VERSION 5.8 ;
BUSBITCHARS "[]" ;
DIVIDERCHAR "/" ;
UNITS
    DATABASE MICRONS 1000 ;
END UNITS

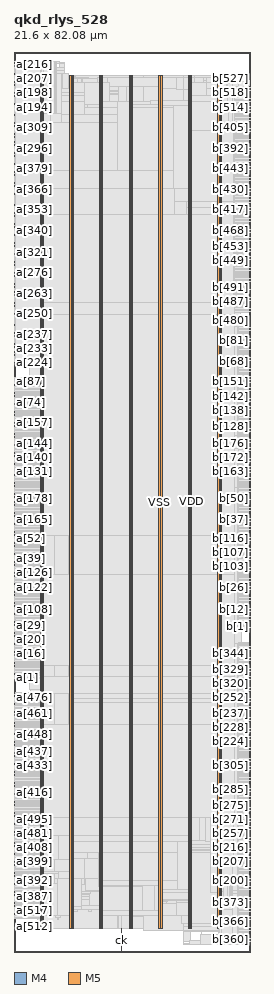
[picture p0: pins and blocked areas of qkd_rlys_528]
MACRO qkd_rlys_528
  FOREIGN qkd_rlys_528 0 0 ;
  CLASS BLOCK ;
  SIZE 21.6 BY 82.08 ;
  PIN a[0]
    DIRECTION INPUT ;
    USE SIGNAL ;
    PORT
      LAYER M4 ;
        RECT  0 24.912 0.084 24.936 ;
    END
  END a[0]
  PIN a[100]
    DIRECTION INPUT ;
    USE SIGNAL ;
    PORT
      LAYER M4 ;
        RECT  0 30.096 0.084 30.12 ;
    END
  END a[100]
  PIN a[101]
    DIRECTION INPUT ;
    USE SIGNAL ;
    PORT
      LAYER M4 ;
        RECT  0 30.24 0.084 30.264 ;
    END
  END a[101]
  PIN a[102]
    DIRECTION INPUT ;
    USE SIGNAL ;
    PORT
      LAYER M4 ;
        RECT  0 30.384 0.084 30.408 ;
    END
  END a[102]
  PIN a[103]
    DIRECTION INPUT ;
    USE SIGNAL ;
    PORT
      LAYER M4 ;
        RECT  0 30.528 0.084 30.552 ;
    END
  END a[103]
  PIN a[104]
    DIRECTION INPUT ;
    USE SIGNAL ;
    PORT
      LAYER M4 ;
        RECT  0 30.672 0.084 30.696 ;
    END
  END a[104]
  PIN a[105]
    DIRECTION INPUT ;
    USE SIGNAL ;
    PORT
      LAYER M4 ;
        RECT  0 30.816 0.084 30.84 ;
    END
  END a[105]
  PIN a[106]
    DIRECTION INPUT ;
    USE SIGNAL ;
    PORT
      LAYER M4 ;
        RECT  0 30.96 0.084 30.984 ;
    END
  END a[106]
  PIN a[107]
    DIRECTION INPUT ;
    USE SIGNAL ;
    PORT
      LAYER M4 ;
        RECT  0 31.104 0.084 31.128 ;
    END
  END a[107]
  PIN a[108]
    DIRECTION INPUT ;
    USE SIGNAL ;
    PORT
      LAYER M4 ;
        RECT  0 31.248 0.084 31.272 ;
    END
  END a[108]
  PIN a[109]
    DIRECTION INPUT ;
    USE SIGNAL ;
    PORT
      LAYER M4 ;
        RECT  0 31.392 0.084 31.416 ;
    END
  END a[109]
  PIN a[10]
    DIRECTION INPUT ;
    USE SIGNAL ;
    PORT
      LAYER M4 ;
        RECT  0 26.352 0.084 26.376 ;
    END
  END a[10]
  PIN a[110]
    DIRECTION INPUT ;
    USE SIGNAL ;
    PORT
      LAYER M4 ;
        RECT  0 31.536 0.084 31.56 ;
    END
  END a[110]
  PIN a[111]
    DIRECTION INPUT ;
    USE SIGNAL ;
    PORT
      LAYER M4 ;
        RECT  0 31.68 0.084 31.704 ;
    END
  END a[111]
  PIN a[112]
    DIRECTION INPUT ;
    USE SIGNAL ;
    PORT
      LAYER M4 ;
        RECT  0 31.824 0.084 31.848 ;
    END
  END a[112]
  PIN a[113]
    DIRECTION INPUT ;
    USE SIGNAL ;
    PORT
      LAYER M4 ;
        RECT  0 31.968 0.084 31.992 ;
    END
  END a[113]
  PIN a[114]
    DIRECTION INPUT ;
    USE SIGNAL ;
    PORT
      LAYER M4 ;
        RECT  0 32.112 0.084 32.136 ;
    END
  END a[114]
  PIN a[115]
    DIRECTION INPUT ;
    USE SIGNAL ;
    PORT
      LAYER M4 ;
        RECT  0 32.256 0.084 32.28 ;
    END
  END a[115]
  PIN a[116]
    DIRECTION INPUT ;
    USE SIGNAL ;
    PORT
      LAYER M4 ;
        RECT  0 32.4 0.084 32.424 ;
    END
  END a[116]
  PIN a[117]
    DIRECTION INPUT ;
    USE SIGNAL ;
    PORT
      LAYER M4 ;
        RECT  0 32.544 0.084 32.568 ;
    END
  END a[117]
  PIN a[118]
    DIRECTION INPUT ;
    USE SIGNAL ;
    PORT
      LAYER M4 ;
        RECT  0 32.688 0.084 32.712 ;
    END
  END a[118]
  PIN a[119]
    DIRECTION INPUT ;
    USE SIGNAL ;
    PORT
      LAYER M4 ;
        RECT  0 32.832 0.084 32.856 ;
    END
  END a[119]
  PIN a[11]
    DIRECTION INPUT ;
    USE SIGNAL ;
    PORT
      LAYER M4 ;
        RECT  0 26.496 0.084 26.52 ;
    END
  END a[11]
  PIN a[120]
    DIRECTION INPUT ;
    USE SIGNAL ;
    PORT
      LAYER M4 ;
        RECT  0 32.976 0.084 33 ;
    END
  END a[120]
  PIN a[121]
    DIRECTION INPUT ;
    USE SIGNAL ;
    PORT
      LAYER M4 ;
        RECT  0 33.12 0.084 33.144 ;
    END
  END a[121]
  PIN a[122]
    DIRECTION INPUT ;
    USE SIGNAL ;
    PORT
      LAYER M4 ;
        RECT  0 33.264 0.084 33.288 ;
    END
  END a[122]
  PIN a[123]
    DIRECTION INPUT ;
    USE SIGNAL ;
    PORT
      LAYER M4 ;
        RECT  0 33.408 0.084 33.432 ;
    END
  END a[123]
  PIN a[124]
    DIRECTION INPUT ;
    USE SIGNAL ;
    PORT
      LAYER M4 ;
        RECT  0 33.552 0.084 33.576 ;
    END
  END a[124]
  PIN a[125]
    DIRECTION INPUT ;
    USE SIGNAL ;
    PORT
      LAYER M4 ;
        RECT  0 33.696 0.084 33.72 ;
    END
  END a[125]
  PIN a[126]
    DIRECTION INPUT ;
    USE SIGNAL ;
    PORT
      LAYER M4 ;
        RECT  0 33.84 0.084 33.864 ;
    END
  END a[126]
  PIN a[127]
    DIRECTION INPUT ;
    USE SIGNAL ;
    PORT
      LAYER M4 ;
        RECT  0 33.984 0.084 34.008 ;
    END
  END a[127]
  PIN a[128]
    DIRECTION INPUT ;
    USE SIGNAL ;
    PORT
      LAYER M4 ;
        RECT  0 43.344 0.084 43.368 ;
    END
  END a[128]
  PIN a[129]
    DIRECTION INPUT ;
    USE SIGNAL ;
    PORT
      LAYER M4 ;
        RECT  0 43.488 0.084 43.512 ;
    END
  END a[129]
  PIN a[12]
    DIRECTION INPUT ;
    USE SIGNAL ;
    PORT
      LAYER M4 ;
        RECT  0 26.64 0.084 26.664 ;
    END
  END a[12]
  PIN a[130]
    DIRECTION INPUT ;
    USE SIGNAL ;
    PORT
      LAYER M4 ;
        RECT  0 43.632 0.084 43.656 ;
    END
  END a[130]
  PIN a[131]
    DIRECTION INPUT ;
    USE SIGNAL ;
    PORT
      LAYER M4 ;
        RECT  0 43.776 0.084 43.8 ;
    END
  END a[131]
  PIN a[132]
    DIRECTION INPUT ;
    USE SIGNAL ;
    PORT
      LAYER M4 ;
        RECT  0 43.92 0.084 43.944 ;
    END
  END a[132]
  PIN a[133]
    DIRECTION INPUT ;
    USE SIGNAL ;
    PORT
      LAYER M4 ;
        RECT  0 44.064 0.084 44.088 ;
    END
  END a[133]
  PIN a[134]
    DIRECTION INPUT ;
    USE SIGNAL ;
    PORT
      LAYER M4 ;
        RECT  0 44.208 0.084 44.232 ;
    END
  END a[134]
  PIN a[135]
    DIRECTION INPUT ;
    USE SIGNAL ;
    PORT
      LAYER M4 ;
        RECT  0 44.352 0.084 44.376 ;
    END
  END a[135]
  PIN a[136]
    DIRECTION INPUT ;
    USE SIGNAL ;
    PORT
      LAYER M4 ;
        RECT  0 44.496 0.084 44.52 ;
    END
  END a[136]
  PIN a[137]
    DIRECTION INPUT ;
    USE SIGNAL ;
    PORT
      LAYER M4 ;
        RECT  0 44.64 0.084 44.664 ;
    END
  END a[137]
  PIN a[138]
    DIRECTION INPUT ;
    USE SIGNAL ;
    PORT
      LAYER M4 ;
        RECT  0 44.784 0.084 44.808 ;
    END
  END a[138]
  PIN a[139]
    DIRECTION INPUT ;
    USE SIGNAL ;
    PORT
      LAYER M4 ;
        RECT  0 44.928 0.084 44.952 ;
    END
  END a[139]
  PIN a[13]
    DIRECTION INPUT ;
    USE SIGNAL ;
    PORT
      LAYER M4 ;
        RECT  0 26.784 0.084 26.808 ;
    END
  END a[13]
  PIN a[140]
    DIRECTION INPUT ;
    USE SIGNAL ;
    PORT
      LAYER M4 ;
        RECT  0 45.072 0.084 45.096 ;
    END
  END a[140]
  PIN a[141]
    DIRECTION INPUT ;
    USE SIGNAL ;
    PORT
      LAYER M4 ;
        RECT  0 45.216 0.084 45.24 ;
    END
  END a[141]
  PIN a[142]
    DIRECTION INPUT ;
    USE SIGNAL ;
    PORT
      LAYER M4 ;
        RECT  0 45.36 0.084 45.384 ;
    END
  END a[142]
  PIN a[143]
    DIRECTION INPUT ;
    USE SIGNAL ;
    PORT
      LAYER M4 ;
        RECT  0 45.504 0.084 45.528 ;
    END
  END a[143]
  PIN a[144]
    DIRECTION INPUT ;
    USE SIGNAL ;
    PORT
      LAYER M4 ;
        RECT  0 45.648 0.084 45.672 ;
    END
  END a[144]
  PIN a[145]
    DIRECTION INPUT ;
    USE SIGNAL ;
    PORT
      LAYER M4 ;
        RECT  0 45.792 0.084 45.816 ;
    END
  END a[145]
  PIN a[146]
    DIRECTION INPUT ;
    USE SIGNAL ;
    PORT
      LAYER M4 ;
        RECT  0 45.936 0.084 45.96 ;
    END
  END a[146]
  PIN a[147]
    DIRECTION INPUT ;
    USE SIGNAL ;
    PORT
      LAYER M4 ;
        RECT  0 46.08 0.084 46.104 ;
    END
  END a[147]
  PIN a[148]
    DIRECTION INPUT ;
    USE SIGNAL ;
    PORT
      LAYER M4 ;
        RECT  0 46.224 0.084 46.248 ;
    END
  END a[148]
  PIN a[149]
    DIRECTION INPUT ;
    USE SIGNAL ;
    PORT
      LAYER M4 ;
        RECT  0 46.368 0.084 46.392 ;
    END
  END a[149]
  PIN a[14]
    DIRECTION INPUT ;
    USE SIGNAL ;
    PORT
      LAYER M4 ;
        RECT  0 26.928 0.084 26.952 ;
    END
  END a[14]
  PIN a[150]
    DIRECTION INPUT ;
    USE SIGNAL ;
    PORT
      LAYER M4 ;
        RECT  0 46.512 0.084 46.536 ;
    END
  END a[150]
  PIN a[151]
    DIRECTION INPUT ;
    USE SIGNAL ;
    PORT
      LAYER M4 ;
        RECT  0 46.656 0.084 46.68 ;
    END
  END a[151]
  PIN a[152]
    DIRECTION INPUT ;
    USE SIGNAL ;
    PORT
      LAYER M4 ;
        RECT  0 46.8 0.084 46.824 ;
    END
  END a[152]
  PIN a[153]
    DIRECTION INPUT ;
    USE SIGNAL ;
    PORT
      LAYER M4 ;
        RECT  0 46.944 0.084 46.968 ;
    END
  END a[153]
  PIN a[154]
    DIRECTION INPUT ;
    USE SIGNAL ;
    PORT
      LAYER M4 ;
        RECT  0 47.088 0.084 47.112 ;
    END
  END a[154]
  PIN a[155]
    DIRECTION INPUT ;
    USE SIGNAL ;
    PORT
      LAYER M4 ;
        RECT  0 47.232 0.084 47.256 ;
    END
  END a[155]
  PIN a[156]
    DIRECTION INPUT ;
    USE SIGNAL ;
    PORT
      LAYER M4 ;
        RECT  0 47.376 0.084 47.4 ;
    END
  END a[156]
  PIN a[157]
    DIRECTION INPUT ;
    USE SIGNAL ;
    PORT
      LAYER M4 ;
        RECT  0 47.52 0.084 47.544 ;
    END
  END a[157]
  PIN a[158]
    DIRECTION INPUT ;
    USE SIGNAL ;
    PORT
      LAYER M4 ;
        RECT  0 47.664 0.084 47.688 ;
    END
  END a[158]
  PIN a[159]
    DIRECTION INPUT ;
    USE SIGNAL ;
    PORT
      LAYER M4 ;
        RECT  0 47.808 0.084 47.832 ;
    END
  END a[159]
  PIN a[15]
    DIRECTION INPUT ;
    USE SIGNAL ;
    PORT
      LAYER M4 ;
        RECT  0 27.072 0.084 27.096 ;
    END
  END a[15]
  PIN a[160]
    DIRECTION INPUT ;
    USE SIGNAL ;
    PORT
      LAYER M4 ;
        RECT  0 38.736 0.084 38.76 ;
    END
  END a[160]
  PIN a[161]
    DIRECTION INPUT ;
    USE SIGNAL ;
    PORT
      LAYER M4 ;
        RECT  0 38.88 0.084 38.904 ;
    END
  END a[161]
  PIN a[162]
    DIRECTION INPUT ;
    USE SIGNAL ;
    PORT
      LAYER M4 ;
        RECT  0 39.024 0.084 39.048 ;
    END
  END a[162]
  PIN a[163]
    DIRECTION INPUT ;
    USE SIGNAL ;
    PORT
      LAYER M4 ;
        RECT  0 39.168 0.084 39.192 ;
    END
  END a[163]
  PIN a[164]
    DIRECTION INPUT ;
    USE SIGNAL ;
    PORT
      LAYER M4 ;
        RECT  0 39.312 0.084 39.336 ;
    END
  END a[164]
  PIN a[165]
    DIRECTION INPUT ;
    USE SIGNAL ;
    PORT
      LAYER M4 ;
        RECT  0 39.456 0.084 39.48 ;
    END
  END a[165]
  PIN a[166]
    DIRECTION INPUT ;
    USE SIGNAL ;
    PORT
      LAYER M4 ;
        RECT  0 39.6 0.084 39.624 ;
    END
  END a[166]
  PIN a[167]
    DIRECTION INPUT ;
    USE SIGNAL ;
    PORT
      LAYER M4 ;
        RECT  0 39.744 0.084 39.768 ;
    END
  END a[167]
  PIN a[168]
    DIRECTION INPUT ;
    USE SIGNAL ;
    PORT
      LAYER M4 ;
        RECT  0 39.888 0.084 39.912 ;
    END
  END a[168]
  PIN a[169]
    DIRECTION INPUT ;
    USE SIGNAL ;
    PORT
      LAYER M4 ;
        RECT  0 40.032 0.084 40.056 ;
    END
  END a[169]
  PIN a[16]
    DIRECTION INPUT ;
    USE SIGNAL ;
    PORT
      LAYER M4 ;
        RECT  0 27.216 0.084 27.24 ;
    END
  END a[16]
  PIN a[170]
    DIRECTION INPUT ;
    USE SIGNAL ;
    PORT
      LAYER M4 ;
        RECT  0 40.176 0.084 40.2 ;
    END
  END a[170]
  PIN a[171]
    DIRECTION INPUT ;
    USE SIGNAL ;
    PORT
      LAYER M4 ;
        RECT  0 40.32 0.084 40.344 ;
    END
  END a[171]
  PIN a[172]
    DIRECTION INPUT ;
    USE SIGNAL ;
    PORT
      LAYER M4 ;
        RECT  0 40.464 0.084 40.488 ;
    END
  END a[172]
  PIN a[173]
    DIRECTION INPUT ;
    USE SIGNAL ;
    PORT
      LAYER M4 ;
        RECT  0 40.608 0.084 40.632 ;
    END
  END a[173]
  PIN a[174]
    DIRECTION INPUT ;
    USE SIGNAL ;
    PORT
      LAYER M4 ;
        RECT  0 40.752 0.084 40.776 ;
    END
  END a[174]
  PIN a[175]
    DIRECTION INPUT ;
    USE SIGNAL ;
    PORT
      LAYER M4 ;
        RECT  0 40.896 0.084 40.92 ;
    END
  END a[175]
  PIN a[176]
    DIRECTION INPUT ;
    USE SIGNAL ;
    PORT
      LAYER M4 ;
        RECT  0 41.04 0.084 41.064 ;
    END
  END a[176]
  PIN a[177]
    DIRECTION INPUT ;
    USE SIGNAL ;
    PORT
      LAYER M4 ;
        RECT  0 41.184 0.084 41.208 ;
    END
  END a[177]
  PIN a[178]
    DIRECTION INPUT ;
    USE SIGNAL ;
    PORT
      LAYER M4 ;
        RECT  0 41.328 0.084 41.352 ;
    END
  END a[178]
  PIN a[179]
    DIRECTION INPUT ;
    USE SIGNAL ;
    PORT
      LAYER M4 ;
        RECT  0 41.472 0.084 41.496 ;
    END
  END a[179]
  PIN a[17]
    DIRECTION INPUT ;
    USE SIGNAL ;
    PORT
      LAYER M4 ;
        RECT  0 27.36 0.084 27.384 ;
    END
  END a[17]
  PIN a[180]
    DIRECTION INPUT ;
    USE SIGNAL ;
    PORT
      LAYER M4 ;
        RECT  0 41.616 0.084 41.64 ;
    END
  END a[180]
  PIN a[181]
    DIRECTION INPUT ;
    USE SIGNAL ;
    PORT
      LAYER M4 ;
        RECT  0 41.76 0.084 41.784 ;
    END
  END a[181]
  PIN a[182]
    DIRECTION INPUT ;
    USE SIGNAL ;
    PORT
      LAYER M4 ;
        RECT  0 41.904 0.084 41.928 ;
    END
  END a[182]
  PIN a[183]
    DIRECTION INPUT ;
    USE SIGNAL ;
    PORT
      LAYER M4 ;
        RECT  0 42.048 0.084 42.072 ;
    END
  END a[183]
  PIN a[184]
    DIRECTION INPUT ;
    USE SIGNAL ;
    PORT
      LAYER M4 ;
        RECT  0 42.192 0.084 42.216 ;
    END
  END a[184]
  PIN a[185]
    DIRECTION INPUT ;
    USE SIGNAL ;
    PORT
      LAYER M4 ;
        RECT  0 42.336 0.084 42.36 ;
    END
  END a[185]
  PIN a[186]
    DIRECTION INPUT ;
    USE SIGNAL ;
    PORT
      LAYER M4 ;
        RECT  0 42.48 0.084 42.504 ;
    END
  END a[186]
  PIN a[187]
    DIRECTION INPUT ;
    USE SIGNAL ;
    PORT
      LAYER M4 ;
        RECT  0 42.624 0.084 42.648 ;
    END
  END a[187]
  PIN a[188]
    DIRECTION INPUT ;
    USE SIGNAL ;
    PORT
      LAYER M4 ;
        RECT  0 42.768 0.084 42.792 ;
    END
  END a[188]
  PIN a[189]
    DIRECTION INPUT ;
    USE SIGNAL ;
    PORT
      LAYER M4 ;
        RECT  0 42.912 0.084 42.936 ;
    END
  END a[189]
  PIN a[18]
    DIRECTION INPUT ;
    USE SIGNAL ;
    PORT
      LAYER M4 ;
        RECT  0 27.504 0.084 27.528 ;
    END
  END a[18]
  PIN a[190]
    DIRECTION INPUT ;
    USE SIGNAL ;
    PORT
      LAYER M4 ;
        RECT  0 43.056 0.084 43.08 ;
    END
  END a[190]
  PIN a[191]
    DIRECTION INPUT ;
    USE SIGNAL ;
    PORT
      LAYER M4 ;
        RECT  0 43.2 0.084 43.224 ;
    END
  END a[191]
  PIN a[192]
    DIRECTION INPUT ;
    USE SIGNAL ;
    PORT
      LAYER M4 ;
        RECT  0 76.752 0.084 76.776 ;
    END
  END a[192]
  PIN a[193]
    DIRECTION INPUT ;
    USE SIGNAL ;
    PORT
      LAYER M4 ;
        RECT  0 76.896 0.084 76.92 ;
    END
  END a[193]
  PIN a[194]
    DIRECTION INPUT ;
    USE SIGNAL ;
    PORT
      LAYER M4 ;
        RECT  0 77.04 0.084 77.064 ;
    END
  END a[194]
  PIN a[195]
    DIRECTION INPUT ;
    USE SIGNAL ;
    PORT
      LAYER M4 ;
        RECT  0 77.184 0.084 77.208 ;
    END
  END a[195]
  PIN a[196]
    DIRECTION INPUT ;
    USE SIGNAL ;
    PORT
      LAYER M4 ;
        RECT  0 77.328 0.084 77.352 ;
    END
  END a[196]
  PIN a[197]
    DIRECTION INPUT ;
    USE SIGNAL ;
    PORT
      LAYER M4 ;
        RECT  0 77.472 0.084 77.496 ;
    END
  END a[197]
  PIN a[198]
    DIRECTION INPUT ;
    USE SIGNAL ;
    PORT
      LAYER M4 ;
        RECT  0 77.616 0.084 77.64 ;
    END
  END a[198]
  PIN a[199]
    DIRECTION INPUT ;
    USE SIGNAL ;
    PORT
      LAYER M4 ;
        RECT  0 77.76 0.084 77.784 ;
    END
  END a[199]
  PIN a[19]
    DIRECTION INPUT ;
    USE SIGNAL ;
    PORT
      LAYER M4 ;
        RECT  0 27.648 0.084 27.672 ;
    END
  END a[19]
  PIN a[1]
    DIRECTION INPUT ;
    USE SIGNAL ;
    PORT
      LAYER M4 ;
        RECT  0 25.056 0.084 25.08 ;
    END
  END a[1]
  PIN a[200]
    DIRECTION INPUT ;
    USE SIGNAL ;
    PORT
      LAYER M4 ;
        RECT  0 77.904 0.084 77.928 ;
    END
  END a[200]
  PIN a[201]
    DIRECTION INPUT ;
    USE SIGNAL ;
    PORT
      LAYER M4 ;
        RECT  0 78.048 0.084 78.072 ;
    END
  END a[201]
  PIN a[202]
    DIRECTION INPUT ;
    USE SIGNAL ;
    PORT
      LAYER M4 ;
        RECT  0 78.192 0.084 78.216 ;
    END
  END a[202]
  PIN a[203]
    DIRECTION INPUT ;
    USE SIGNAL ;
    PORT
      LAYER M4 ;
        RECT  0 78.336 0.084 78.36 ;
    END
  END a[203]
  PIN a[204]
    DIRECTION INPUT ;
    USE SIGNAL ;
    PORT
      LAYER M4 ;
        RECT  0 78.48 0.084 78.504 ;
    END
  END a[204]
  PIN a[205]
    DIRECTION INPUT ;
    USE SIGNAL ;
    PORT
      LAYER M4 ;
        RECT  0 78.624 0.084 78.648 ;
    END
  END a[205]
  PIN a[206]
    DIRECTION INPUT ;
    USE SIGNAL ;
    PORT
      LAYER M4 ;
        RECT  0 78.768 0.084 78.792 ;
    END
  END a[206]
  PIN a[207]
    DIRECTION INPUT ;
    USE SIGNAL ;
    PORT
      LAYER M4 ;
        RECT  0 78.912 0.084 78.936 ;
    END
  END a[207]
  PIN a[208]
    DIRECTION INPUT ;
    USE SIGNAL ;
    PORT
      LAYER M4 ;
        RECT  0 79.056 0.084 79.08 ;
    END
  END a[208]
  PIN a[209]
    DIRECTION INPUT ;
    USE SIGNAL ;
    PORT
      LAYER M4 ;
        RECT  0 79.2 0.084 79.224 ;
    END
  END a[209]
  PIN a[20]
    DIRECTION INPUT ;
    USE SIGNAL ;
    PORT
      LAYER M4 ;
        RECT  0 27.792 0.084 27.816 ;
    END
  END a[20]
  PIN a[210]
    DIRECTION INPUT ;
    USE SIGNAL ;
    PORT
      LAYER M4 ;
        RECT  0 79.344 0.084 79.368 ;
    END
  END a[210]
  PIN a[211]
    DIRECTION INPUT ;
    USE SIGNAL ;
    PORT
      LAYER M4 ;
        RECT  0 79.488 0.084 79.512 ;
    END
  END a[211]
  PIN a[212]
    DIRECTION INPUT ;
    USE SIGNAL ;
    PORT
      LAYER M4 ;
        RECT  0 79.632 0.084 79.656 ;
    END
  END a[212]
  PIN a[213]
    DIRECTION INPUT ;
    USE SIGNAL ;
    PORT
      LAYER M4 ;
        RECT  0 79.776 0.084 79.8 ;
    END
  END a[213]
  PIN a[214]
    DIRECTION INPUT ;
    USE SIGNAL ;
    PORT
      LAYER M4 ;
        RECT  0 79.92 0.084 79.944 ;
    END
  END a[214]
  PIN a[215]
    DIRECTION INPUT ;
    USE SIGNAL ;
    PORT
      LAYER M4 ;
        RECT  0 80.064 0.084 80.088 ;
    END
  END a[215]
  PIN a[216]
    DIRECTION INPUT ;
    USE SIGNAL ;
    PORT
      LAYER M4 ;
        RECT  0 80.208 0.084 80.232 ;
    END
  END a[216]
  PIN a[217]
    DIRECTION INPUT ;
    USE SIGNAL ;
    PORT
      LAYER M4 ;
        RECT  0 80.352 0.084 80.376 ;
    END
  END a[217]
  PIN a[218]
    DIRECTION INPUT ;
    USE SIGNAL ;
    PORT
      LAYER M4 ;
        RECT  0 80.496 0.084 80.52 ;
    END
  END a[218]
  PIN a[219]
    DIRECTION INPUT ;
    USE SIGNAL ;
    PORT
      LAYER M4 ;
        RECT  0 80.64 0.084 80.664 ;
    END
  END a[219]
  PIN a[21]
    DIRECTION INPUT ;
    USE SIGNAL ;
    PORT
      LAYER M4 ;
        RECT  0 27.936 0.084 27.96 ;
    END
  END a[21]
  PIN a[220]
    DIRECTION INPUT ;
    USE SIGNAL ;
    PORT
      LAYER M4 ;
        RECT  0 80.784 0.084 80.808 ;
    END
  END a[220]
  PIN a[221]
    DIRECTION INPUT ;
    USE SIGNAL ;
    PORT
      LAYER M4 ;
        RECT  0 80.928 0.084 80.952 ;
    END
  END a[221]
  PIN a[222]
    DIRECTION INPUT ;
    USE SIGNAL ;
    PORT
      LAYER M4 ;
        RECT  0 81.072 0.084 81.096 ;
    END
  END a[222]
  PIN a[223]
    DIRECTION INPUT ;
    USE SIGNAL ;
    PORT
      LAYER M4 ;
        RECT  0 81.216 0.084 81.24 ;
    END
  END a[223]
  PIN a[224]
    DIRECTION INPUT ;
    USE SIGNAL ;
    PORT
      LAYER M4 ;
        RECT  0 53.712 0.084 53.736 ;
    END
  END a[224]
  PIN a[225]
    DIRECTION INPUT ;
    USE SIGNAL ;
    PORT
      LAYER M4 ;
        RECT  0 53.856 0.084 53.88 ;
    END
  END a[225]
  PIN a[226]
    DIRECTION INPUT ;
    USE SIGNAL ;
    PORT
      LAYER M4 ;
        RECT  0 54 0.084 54.024 ;
    END
  END a[226]
  PIN a[227]
    DIRECTION INPUT ;
    USE SIGNAL ;
    PORT
      LAYER M4 ;
        RECT  0 54.144 0.084 54.168 ;
    END
  END a[227]
  PIN a[228]
    DIRECTION INPUT ;
    USE SIGNAL ;
    PORT
      LAYER M4 ;
        RECT  0 54.288 0.084 54.312 ;
    END
  END a[228]
  PIN a[229]
    DIRECTION INPUT ;
    USE SIGNAL ;
    PORT
      LAYER M4 ;
        RECT  0 54.432 0.084 54.456 ;
    END
  END a[229]
  PIN a[22]
    DIRECTION INPUT ;
    USE SIGNAL ;
    PORT
      LAYER M4 ;
        RECT  0 28.08 0.084 28.104 ;
    END
  END a[22]
  PIN a[230]
    DIRECTION INPUT ;
    USE SIGNAL ;
    PORT
      LAYER M4 ;
        RECT  0 54.576 0.084 54.6 ;
    END
  END a[230]
  PIN a[231]
    DIRECTION INPUT ;
    USE SIGNAL ;
    PORT
      LAYER M4 ;
        RECT  0 54.72 0.084 54.744 ;
    END
  END a[231]
  PIN a[232]
    DIRECTION INPUT ;
    USE SIGNAL ;
    PORT
      LAYER M4 ;
        RECT  0 54.864 0.084 54.888 ;
    END
  END a[232]
  PIN a[233]
    DIRECTION INPUT ;
    USE SIGNAL ;
    PORT
      LAYER M4 ;
        RECT  0 55.008 0.084 55.032 ;
    END
  END a[233]
  PIN a[234]
    DIRECTION INPUT ;
    USE SIGNAL ;
    PORT
      LAYER M4 ;
        RECT  0 55.152 0.084 55.176 ;
    END
  END a[234]
  PIN a[235]
    DIRECTION INPUT ;
    USE SIGNAL ;
    PORT
      LAYER M4 ;
        RECT  0 55.296 0.084 55.32 ;
    END
  END a[235]
  PIN a[236]
    DIRECTION INPUT ;
    USE SIGNAL ;
    PORT
      LAYER M4 ;
        RECT  0 55.44 0.084 55.464 ;
    END
  END a[236]
  PIN a[237]
    DIRECTION INPUT ;
    USE SIGNAL ;
    PORT
      LAYER M4 ;
        RECT  0 55.584 0.084 55.608 ;
    END
  END a[237]
  PIN a[238]
    DIRECTION INPUT ;
    USE SIGNAL ;
    PORT
      LAYER M4 ;
        RECT  0 55.728 0.084 55.752 ;
    END
  END a[238]
  PIN a[239]
    DIRECTION INPUT ;
    USE SIGNAL ;
    PORT
      LAYER M4 ;
        RECT  0 55.872 0.084 55.896 ;
    END
  END a[239]
  PIN a[23]
    DIRECTION INPUT ;
    USE SIGNAL ;
    PORT
      LAYER M4 ;
        RECT  0 28.224 0.084 28.248 ;
    END
  END a[23]
  PIN a[240]
    DIRECTION INPUT ;
    USE SIGNAL ;
    PORT
      LAYER M4 ;
        RECT  0 56.016 0.084 56.04 ;
    END
  END a[240]
  PIN a[241]
    DIRECTION INPUT ;
    USE SIGNAL ;
    PORT
      LAYER M4 ;
        RECT  0 56.16 0.084 56.184 ;
    END
  END a[241]
  PIN a[242]
    DIRECTION INPUT ;
    USE SIGNAL ;
    PORT
      LAYER M4 ;
        RECT  0 56.304 0.084 56.328 ;
    END
  END a[242]
  PIN a[243]
    DIRECTION INPUT ;
    USE SIGNAL ;
    PORT
      LAYER M4 ;
        RECT  0 56.448 0.084 56.472 ;
    END
  END a[243]
  PIN a[244]
    DIRECTION INPUT ;
    USE SIGNAL ;
    PORT
      LAYER M4 ;
        RECT  0 56.592 0.084 56.616 ;
    END
  END a[244]
  PIN a[245]
    DIRECTION INPUT ;
    USE SIGNAL ;
    PORT
      LAYER M4 ;
        RECT  0 56.736 0.084 56.76 ;
    END
  END a[245]
  PIN a[246]
    DIRECTION INPUT ;
    USE SIGNAL ;
    PORT
      LAYER M4 ;
        RECT  0 56.88 0.084 56.904 ;
    END
  END a[246]
  PIN a[247]
    DIRECTION INPUT ;
    USE SIGNAL ;
    PORT
      LAYER M4 ;
        RECT  0 57.024 0.084 57.048 ;
    END
  END a[247]
  PIN a[248]
    DIRECTION INPUT ;
    USE SIGNAL ;
    PORT
      LAYER M4 ;
        RECT  0 57.168 0.084 57.192 ;
    END
  END a[248]
  PIN a[249]
    DIRECTION INPUT ;
    USE SIGNAL ;
    PORT
      LAYER M4 ;
        RECT  0 57.312 0.084 57.336 ;
    END
  END a[249]
  PIN a[24]
    DIRECTION INPUT ;
    USE SIGNAL ;
    PORT
      LAYER M4 ;
        RECT  0 28.368 0.084 28.392 ;
    END
  END a[24]
  PIN a[250]
    DIRECTION INPUT ;
    USE SIGNAL ;
    PORT
      LAYER M4 ;
        RECT  0 57.456 0.084 57.48 ;
    END
  END a[250]
  PIN a[251]
    DIRECTION INPUT ;
    USE SIGNAL ;
    PORT
      LAYER M4 ;
        RECT  0 57.6 0.084 57.624 ;
    END
  END a[251]
  PIN a[252]
    DIRECTION INPUT ;
    USE SIGNAL ;
    PORT
      LAYER M4 ;
        RECT  0 57.744 0.084 57.768 ;
    END
  END a[252]
  PIN a[253]
    DIRECTION INPUT ;
    USE SIGNAL ;
    PORT
      LAYER M4 ;
        RECT  0 57.888 0.084 57.912 ;
    END
  END a[253]
  PIN a[254]
    DIRECTION INPUT ;
    USE SIGNAL ;
    PORT
      LAYER M4 ;
        RECT  0 58.032 0.084 58.056 ;
    END
  END a[254]
  PIN a[255]
    DIRECTION INPUT ;
    USE SIGNAL ;
    PORT
      LAYER M4 ;
        RECT  0 58.176 0.084 58.2 ;
    END
  END a[255]
  PIN a[256]
    DIRECTION INPUT ;
    USE SIGNAL ;
    PORT
      LAYER M4 ;
        RECT  0 58.32 0.084 58.344 ;
    END
  END a[256]
  PIN a[257]
    DIRECTION INPUT ;
    USE SIGNAL ;
    PORT
      LAYER M4 ;
        RECT  0 58.464 0.084 58.488 ;
    END
  END a[257]
  PIN a[258]
    DIRECTION INPUT ;
    USE SIGNAL ;
    PORT
      LAYER M4 ;
        RECT  0 58.608 0.084 58.632 ;
    END
  END a[258]
  PIN a[259]
    DIRECTION INPUT ;
    USE SIGNAL ;
    PORT
      LAYER M4 ;
        RECT  0 58.752 0.084 58.776 ;
    END
  END a[259]
  PIN a[25]
    DIRECTION INPUT ;
    USE SIGNAL ;
    PORT
      LAYER M4 ;
        RECT  0 28.512 0.084 28.536 ;
    END
  END a[25]
  PIN a[260]
    DIRECTION INPUT ;
    USE SIGNAL ;
    PORT
      LAYER M4 ;
        RECT  0 58.896 0.084 58.92 ;
    END
  END a[260]
  PIN a[261]
    DIRECTION INPUT ;
    USE SIGNAL ;
    PORT
      LAYER M4 ;
        RECT  0 59.04 0.084 59.064 ;
    END
  END a[261]
  PIN a[262]
    DIRECTION INPUT ;
    USE SIGNAL ;
    PORT
      LAYER M4 ;
        RECT  0 59.184 0.084 59.208 ;
    END
  END a[262]
  PIN a[263]
    DIRECTION INPUT ;
    USE SIGNAL ;
    PORT
      LAYER M4 ;
        RECT  0 59.328 0.084 59.352 ;
    END
  END a[263]
  PIN a[264]
    DIRECTION INPUT ;
    USE SIGNAL ;
    PORT
      LAYER M4 ;
        RECT  0 59.472 0.084 59.496 ;
    END
  END a[264]
  PIN a[265]
    DIRECTION INPUT ;
    USE SIGNAL ;
    PORT
      LAYER M4 ;
        RECT  0 59.616 0.084 59.64 ;
    END
  END a[265]
  PIN a[266]
    DIRECTION INPUT ;
    USE SIGNAL ;
    PORT
      LAYER M4 ;
        RECT  0 59.76 0.084 59.784 ;
    END
  END a[266]
  PIN a[267]
    DIRECTION INPUT ;
    USE SIGNAL ;
    PORT
      LAYER M4 ;
        RECT  0 59.904 0.084 59.928 ;
    END
  END a[267]
  PIN a[268]
    DIRECTION INPUT ;
    USE SIGNAL ;
    PORT
      LAYER M4 ;
        RECT  0 60.048 0.084 60.072 ;
    END
  END a[268]
  PIN a[269]
    DIRECTION INPUT ;
    USE SIGNAL ;
    PORT
      LAYER M4 ;
        RECT  0 60.192 0.084 60.216 ;
    END
  END a[269]
  PIN a[26]
    DIRECTION INPUT ;
    USE SIGNAL ;
    PORT
      LAYER M4 ;
        RECT  0 28.656 0.084 28.68 ;
    END
  END a[26]
  PIN a[270]
    DIRECTION INPUT ;
    USE SIGNAL ;
    PORT
      LAYER M4 ;
        RECT  0 60.336 0.084 60.36 ;
    END
  END a[270]
  PIN a[271]
    DIRECTION INPUT ;
    USE SIGNAL ;
    PORT
      LAYER M4 ;
        RECT  0 60.48 0.084 60.504 ;
    END
  END a[271]
  PIN a[272]
    DIRECTION INPUT ;
    USE SIGNAL ;
    PORT
      LAYER M4 ;
        RECT  0 60.624 0.084 60.648 ;
    END
  END a[272]
  PIN a[273]
    DIRECTION INPUT ;
    USE SIGNAL ;
    PORT
      LAYER M4 ;
        RECT  0 60.768 0.084 60.792 ;
    END
  END a[273]
  PIN a[274]
    DIRECTION INPUT ;
    USE SIGNAL ;
    PORT
      LAYER M4 ;
        RECT  0 60.912 0.084 60.936 ;
    END
  END a[274]
  PIN a[275]
    DIRECTION INPUT ;
    USE SIGNAL ;
    PORT
      LAYER M4 ;
        RECT  0 61.056 0.084 61.08 ;
    END
  END a[275]
  PIN a[276]
    DIRECTION INPUT ;
    USE SIGNAL ;
    PORT
      LAYER M4 ;
        RECT  0 61.2 0.084 61.224 ;
    END
  END a[276]
  PIN a[277]
    DIRECTION INPUT ;
    USE SIGNAL ;
    PORT
      LAYER M4 ;
        RECT  0 61.344 0.084 61.368 ;
    END
  END a[277]
  PIN a[278]
    DIRECTION INPUT ;
    USE SIGNAL ;
    PORT
      LAYER M4 ;
        RECT  0 61.488 0.084 61.512 ;
    END
  END a[278]
  PIN a[279]
    DIRECTION INPUT ;
    USE SIGNAL ;
    PORT
      LAYER M4 ;
        RECT  0 61.632 0.084 61.656 ;
    END
  END a[279]
  PIN a[27]
    DIRECTION INPUT ;
    USE SIGNAL ;
    PORT
      LAYER M4 ;
        RECT  0 28.8 0.084 28.824 ;
    END
  END a[27]
  PIN a[280]
    DIRECTION INPUT ;
    USE SIGNAL ;
    PORT
      LAYER M4 ;
        RECT  0 61.776 0.084 61.8 ;
    END
  END a[280]
  PIN a[281]
    DIRECTION INPUT ;
    USE SIGNAL ;
    PORT
      LAYER M4 ;
        RECT  0 61.92 0.084 61.944 ;
    END
  END a[281]
  PIN a[282]
    DIRECTION INPUT ;
    USE SIGNAL ;
    PORT
      LAYER M4 ;
        RECT  0 62.064 0.084 62.088 ;
    END
  END a[282]
  PIN a[283]
    DIRECTION INPUT ;
    USE SIGNAL ;
    PORT
      LAYER M4 ;
        RECT  0 62.208 0.084 62.232 ;
    END
  END a[283]
  PIN a[284]
    DIRECTION INPUT ;
    USE SIGNAL ;
    PORT
      LAYER M4 ;
        RECT  0 62.352 0.084 62.376 ;
    END
  END a[284]
  PIN a[285]
    DIRECTION INPUT ;
    USE SIGNAL ;
    PORT
      LAYER M4 ;
        RECT  0 62.496 0.084 62.52 ;
    END
  END a[285]
  PIN a[286]
    DIRECTION INPUT ;
    USE SIGNAL ;
    PORT
      LAYER M4 ;
        RECT  0 62.64 0.084 62.664 ;
    END
  END a[286]
  PIN a[287]
    DIRECTION INPUT ;
    USE SIGNAL ;
    PORT
      LAYER M4 ;
        RECT  0 62.784 0.084 62.808 ;
    END
  END a[287]
  PIN a[288]
    DIRECTION INPUT ;
    USE SIGNAL ;
    PORT
      LAYER M4 ;
        RECT  0 72.144 0.084 72.168 ;
    END
  END a[288]
  PIN a[289]
    DIRECTION INPUT ;
    USE SIGNAL ;
    PORT
      LAYER M4 ;
        RECT  0 72.288 0.084 72.312 ;
    END
  END a[289]
  PIN a[28]
    DIRECTION INPUT ;
    USE SIGNAL ;
    PORT
      LAYER M4 ;
        RECT  0 28.944 0.084 28.968 ;
    END
  END a[28]
  PIN a[290]
    DIRECTION INPUT ;
    USE SIGNAL ;
    PORT
      LAYER M4 ;
        RECT  0 72.432 0.084 72.456 ;
    END
  END a[290]
  PIN a[291]
    DIRECTION INPUT ;
    USE SIGNAL ;
    PORT
      LAYER M4 ;
        RECT  0 72.576 0.084 72.6 ;
    END
  END a[291]
  PIN a[292]
    DIRECTION INPUT ;
    USE SIGNAL ;
    PORT
      LAYER M4 ;
        RECT  0 72.72 0.084 72.744 ;
    END
  END a[292]
  PIN a[293]
    DIRECTION INPUT ;
    USE SIGNAL ;
    PORT
      LAYER M4 ;
        RECT  0 72.864 0.084 72.888 ;
    END
  END a[293]
  PIN a[294]
    DIRECTION INPUT ;
    USE SIGNAL ;
    PORT
      LAYER M4 ;
        RECT  0 73.008 0.084 73.032 ;
    END
  END a[294]
  PIN a[295]
    DIRECTION INPUT ;
    USE SIGNAL ;
    PORT
      LAYER M4 ;
        RECT  0 73.152 0.084 73.176 ;
    END
  END a[295]
  PIN a[296]
    DIRECTION INPUT ;
    USE SIGNAL ;
    PORT
      LAYER M4 ;
        RECT  0 73.296 0.084 73.32 ;
    END
  END a[296]
  PIN a[297]
    DIRECTION INPUT ;
    USE SIGNAL ;
    PORT
      LAYER M4 ;
        RECT  0 73.44 0.084 73.464 ;
    END
  END a[297]
  PIN a[298]
    DIRECTION INPUT ;
    USE SIGNAL ;
    PORT
      LAYER M4 ;
        RECT  0 73.584 0.084 73.608 ;
    END
  END a[298]
  PIN a[299]
    DIRECTION INPUT ;
    USE SIGNAL ;
    PORT
      LAYER M4 ;
        RECT  0 73.728 0.084 73.752 ;
    END
  END a[299]
  PIN a[29]
    DIRECTION INPUT ;
    USE SIGNAL ;
    PORT
      LAYER M4 ;
        RECT  0 29.088 0.084 29.112 ;
    END
  END a[29]
  PIN a[2]
    DIRECTION INPUT ;
    USE SIGNAL ;
    PORT
      LAYER M4 ;
        RECT  0 25.2 0.084 25.224 ;
    END
  END a[2]
  PIN a[300]
    DIRECTION INPUT ;
    USE SIGNAL ;
    PORT
      LAYER M4 ;
        RECT  0 73.872 0.084 73.896 ;
    END
  END a[300]
  PIN a[301]
    DIRECTION INPUT ;
    USE SIGNAL ;
    PORT
      LAYER M4 ;
        RECT  0 74.016 0.084 74.04 ;
    END
  END a[301]
  PIN a[302]
    DIRECTION INPUT ;
    USE SIGNAL ;
    PORT
      LAYER M4 ;
        RECT  0 74.16 0.084 74.184 ;
    END
  END a[302]
  PIN a[303]
    DIRECTION INPUT ;
    USE SIGNAL ;
    PORT
      LAYER M4 ;
        RECT  0 74.304 0.084 74.328 ;
    END
  END a[303]
  PIN a[304]
    DIRECTION INPUT ;
    USE SIGNAL ;
    PORT
      LAYER M4 ;
        RECT  0 74.448 0.084 74.472 ;
    END
  END a[304]
  PIN a[305]
    DIRECTION INPUT ;
    USE SIGNAL ;
    PORT
      LAYER M4 ;
        RECT  0 74.592 0.084 74.616 ;
    END
  END a[305]
  PIN a[306]
    DIRECTION INPUT ;
    USE SIGNAL ;
    PORT
      LAYER M4 ;
        RECT  0 74.736 0.084 74.76 ;
    END
  END a[306]
  PIN a[307]
    DIRECTION INPUT ;
    USE SIGNAL ;
    PORT
      LAYER M4 ;
        RECT  0 74.88 0.084 74.904 ;
    END
  END a[307]
  PIN a[308]
    DIRECTION INPUT ;
    USE SIGNAL ;
    PORT
      LAYER M4 ;
        RECT  0 75.024 0.084 75.048 ;
    END
  END a[308]
  PIN a[309]
    DIRECTION INPUT ;
    USE SIGNAL ;
    PORT
      LAYER M4 ;
        RECT  0 75.168 0.084 75.192 ;
    END
  END a[309]
  PIN a[30]
    DIRECTION INPUT ;
    USE SIGNAL ;
    PORT
      LAYER M4 ;
        RECT  0 29.232 0.084 29.256 ;
    END
  END a[30]
  PIN a[310]
    DIRECTION INPUT ;
    USE SIGNAL ;
    PORT
      LAYER M4 ;
        RECT  0 75.312 0.084 75.336 ;
    END
  END a[310]
  PIN a[311]
    DIRECTION INPUT ;
    USE SIGNAL ;
    PORT
      LAYER M4 ;
        RECT  0 75.456 0.084 75.48 ;
    END
  END a[311]
  PIN a[312]
    DIRECTION INPUT ;
    USE SIGNAL ;
    PORT
      LAYER M4 ;
        RECT  0 75.6 0.084 75.624 ;
    END
  END a[312]
  PIN a[313]
    DIRECTION INPUT ;
    USE SIGNAL ;
    PORT
      LAYER M4 ;
        RECT  0 75.744 0.084 75.768 ;
    END
  END a[313]
  PIN a[314]
    DIRECTION INPUT ;
    USE SIGNAL ;
    PORT
      LAYER M4 ;
        RECT  0 75.888 0.084 75.912 ;
    END
  END a[314]
  PIN a[315]
    DIRECTION INPUT ;
    USE SIGNAL ;
    PORT
      LAYER M4 ;
        RECT  0 76.032 0.084 76.056 ;
    END
  END a[315]
  PIN a[316]
    DIRECTION INPUT ;
    USE SIGNAL ;
    PORT
      LAYER M4 ;
        RECT  0 76.176 0.084 76.2 ;
    END
  END a[316]
  PIN a[317]
    DIRECTION INPUT ;
    USE SIGNAL ;
    PORT
      LAYER M4 ;
        RECT  0 76.32 0.084 76.344 ;
    END
  END a[317]
  PIN a[318]
    DIRECTION INPUT ;
    USE SIGNAL ;
    PORT
      LAYER M4 ;
        RECT  0 76.464 0.084 76.488 ;
    END
  END a[318]
  PIN a[319]
    DIRECTION INPUT ;
    USE SIGNAL ;
    PORT
      LAYER M4 ;
        RECT  0 76.608 0.084 76.632 ;
    END
  END a[319]
  PIN a[31]
    DIRECTION INPUT ;
    USE SIGNAL ;
    PORT
      LAYER M4 ;
        RECT  0 29.376 0.084 29.4 ;
    END
  END a[31]
  PIN a[320]
    DIRECTION INPUT ;
    USE SIGNAL ;
    PORT
      LAYER M4 ;
        RECT  0 62.928 0.084 62.952 ;
    END
  END a[320]
  PIN a[321]
    DIRECTION INPUT ;
    USE SIGNAL ;
    PORT
      LAYER M4 ;
        RECT  0 63.072 0.084 63.096 ;
    END
  END a[321]
  PIN a[322]
    DIRECTION INPUT ;
    USE SIGNAL ;
    PORT
      LAYER M4 ;
        RECT  0 63.216 0.084 63.24 ;
    END
  END a[322]
  PIN a[323]
    DIRECTION INPUT ;
    USE SIGNAL ;
    PORT
      LAYER M4 ;
        RECT  0 63.36 0.084 63.384 ;
    END
  END a[323]
  PIN a[324]
    DIRECTION INPUT ;
    USE SIGNAL ;
    PORT
      LAYER M4 ;
        RECT  0 63.504 0.084 63.528 ;
    END
  END a[324]
  PIN a[325]
    DIRECTION INPUT ;
    USE SIGNAL ;
    PORT
      LAYER M4 ;
        RECT  0 63.648 0.084 63.672 ;
    END
  END a[325]
  PIN a[326]
    DIRECTION INPUT ;
    USE SIGNAL ;
    PORT
      LAYER M4 ;
        RECT  0 63.792 0.084 63.816 ;
    END
  END a[326]
  PIN a[327]
    DIRECTION INPUT ;
    USE SIGNAL ;
    PORT
      LAYER M4 ;
        RECT  0 63.936 0.084 63.96 ;
    END
  END a[327]
  PIN a[328]
    DIRECTION INPUT ;
    USE SIGNAL ;
    PORT
      LAYER M4 ;
        RECT  0 64.08 0.084 64.104 ;
    END
  END a[328]
  PIN a[329]
    DIRECTION INPUT ;
    USE SIGNAL ;
    PORT
      LAYER M4 ;
        RECT  0 64.224 0.084 64.248 ;
    END
  END a[329]
  PIN a[32]
    DIRECTION INPUT ;
    USE SIGNAL ;
    PORT
      LAYER M4 ;
        RECT  0 34.128 0.084 34.152 ;
    END
  END a[32]
  PIN a[330]
    DIRECTION INPUT ;
    USE SIGNAL ;
    PORT
      LAYER M4 ;
        RECT  0 64.368 0.084 64.392 ;
    END
  END a[330]
  PIN a[331]
    DIRECTION INPUT ;
    USE SIGNAL ;
    PORT
      LAYER M4 ;
        RECT  0 64.512 0.084 64.536 ;
    END
  END a[331]
  PIN a[332]
    DIRECTION INPUT ;
    USE SIGNAL ;
    PORT
      LAYER M4 ;
        RECT  0 64.656 0.084 64.68 ;
    END
  END a[332]
  PIN a[333]
    DIRECTION INPUT ;
    USE SIGNAL ;
    PORT
      LAYER M4 ;
        RECT  0 64.8 0.084 64.824 ;
    END
  END a[333]
  PIN a[334]
    DIRECTION INPUT ;
    USE SIGNAL ;
    PORT
      LAYER M4 ;
        RECT  0 64.944 0.084 64.968 ;
    END
  END a[334]
  PIN a[335]
    DIRECTION INPUT ;
    USE SIGNAL ;
    PORT
      LAYER M4 ;
        RECT  0 65.088 0.084 65.112 ;
    END
  END a[335]
  PIN a[336]
    DIRECTION INPUT ;
    USE SIGNAL ;
    PORT
      LAYER M4 ;
        RECT  0 65.232 0.084 65.256 ;
    END
  END a[336]
  PIN a[337]
    DIRECTION INPUT ;
    USE SIGNAL ;
    PORT
      LAYER M4 ;
        RECT  0 65.376 0.084 65.4 ;
    END
  END a[337]
  PIN a[338]
    DIRECTION INPUT ;
    USE SIGNAL ;
    PORT
      LAYER M4 ;
        RECT  0 65.52 0.084 65.544 ;
    END
  END a[338]
  PIN a[339]
    DIRECTION INPUT ;
    USE SIGNAL ;
    PORT
      LAYER M4 ;
        RECT  0 65.664 0.084 65.688 ;
    END
  END a[339]
  PIN a[33]
    DIRECTION INPUT ;
    USE SIGNAL ;
    PORT
      LAYER M4 ;
        RECT  0 34.272 0.084 34.296 ;
    END
  END a[33]
  PIN a[340]
    DIRECTION INPUT ;
    USE SIGNAL ;
    PORT
      LAYER M4 ;
        RECT  0 65.808 0.084 65.832 ;
    END
  END a[340]
  PIN a[341]
    DIRECTION INPUT ;
    USE SIGNAL ;
    PORT
      LAYER M4 ;
        RECT  0 65.952 0.084 65.976 ;
    END
  END a[341]
  PIN a[342]
    DIRECTION INPUT ;
    USE SIGNAL ;
    PORT
      LAYER M4 ;
        RECT  0 66.096 0.084 66.12 ;
    END
  END a[342]
  PIN a[343]
    DIRECTION INPUT ;
    USE SIGNAL ;
    PORT
      LAYER M4 ;
        RECT  0 66.24 0.084 66.264 ;
    END
  END a[343]
  PIN a[344]
    DIRECTION INPUT ;
    USE SIGNAL ;
    PORT
      LAYER M4 ;
        RECT  0 66.384 0.084 66.408 ;
    END
  END a[344]
  PIN a[345]
    DIRECTION INPUT ;
    USE SIGNAL ;
    PORT
      LAYER M4 ;
        RECT  0 66.528 0.084 66.552 ;
    END
  END a[345]
  PIN a[346]
    DIRECTION INPUT ;
    USE SIGNAL ;
    PORT
      LAYER M4 ;
        RECT  0 66.672 0.084 66.696 ;
    END
  END a[346]
  PIN a[347]
    DIRECTION INPUT ;
    USE SIGNAL ;
    PORT
      LAYER M4 ;
        RECT  0 66.816 0.084 66.84 ;
    END
  END a[347]
  PIN a[348]
    DIRECTION INPUT ;
    USE SIGNAL ;
    PORT
      LAYER M4 ;
        RECT  0 66.96 0.084 66.984 ;
    END
  END a[348]
  PIN a[349]
    DIRECTION INPUT ;
    USE SIGNAL ;
    PORT
      LAYER M4 ;
        RECT  0 67.104 0.084 67.128 ;
    END
  END a[349]
  PIN a[34]
    DIRECTION INPUT ;
    USE SIGNAL ;
    PORT
      LAYER M4 ;
        RECT  0 34.416 0.084 34.44 ;
    END
  END a[34]
  PIN a[350]
    DIRECTION INPUT ;
    USE SIGNAL ;
    PORT
      LAYER M4 ;
        RECT  0 67.248 0.084 67.272 ;
    END
  END a[350]
  PIN a[351]
    DIRECTION INPUT ;
    USE SIGNAL ;
    PORT
      LAYER M4 ;
        RECT  0 67.392 0.084 67.416 ;
    END
  END a[351]
  PIN a[352]
    DIRECTION INPUT ;
    USE SIGNAL ;
    PORT
      LAYER M4 ;
        RECT  0 67.536 0.084 67.56 ;
    END
  END a[352]
  PIN a[353]
    DIRECTION INPUT ;
    USE SIGNAL ;
    PORT
      LAYER M4 ;
        RECT  0 67.68 0.084 67.704 ;
    END
  END a[353]
  PIN a[354]
    DIRECTION INPUT ;
    USE SIGNAL ;
    PORT
      LAYER M4 ;
        RECT  0 67.824 0.084 67.848 ;
    END
  END a[354]
  PIN a[355]
    DIRECTION INPUT ;
    USE SIGNAL ;
    PORT
      LAYER M4 ;
        RECT  0 67.968 0.084 67.992 ;
    END
  END a[355]
  PIN a[356]
    DIRECTION INPUT ;
    USE SIGNAL ;
    PORT
      LAYER M4 ;
        RECT  0 68.112 0.084 68.136 ;
    END
  END a[356]
  PIN a[357]
    DIRECTION INPUT ;
    USE SIGNAL ;
    PORT
      LAYER M4 ;
        RECT  0 68.256 0.084 68.28 ;
    END
  END a[357]
  PIN a[358]
    DIRECTION INPUT ;
    USE SIGNAL ;
    PORT
      LAYER M4 ;
        RECT  0 68.4 0.084 68.424 ;
    END
  END a[358]
  PIN a[359]
    DIRECTION INPUT ;
    USE SIGNAL ;
    PORT
      LAYER M4 ;
        RECT  0 68.544 0.084 68.568 ;
    END
  END a[359]
  PIN a[35]
    DIRECTION INPUT ;
    USE SIGNAL ;
    PORT
      LAYER M4 ;
        RECT  0 34.56 0.084 34.584 ;
    END
  END a[35]
  PIN a[360]
    DIRECTION INPUT ;
    USE SIGNAL ;
    PORT
      LAYER M4 ;
        RECT  0 68.688 0.084 68.712 ;
    END
  END a[360]
  PIN a[361]
    DIRECTION INPUT ;
    USE SIGNAL ;
    PORT
      LAYER M4 ;
        RECT  0 68.832 0.084 68.856 ;
    END
  END a[361]
  PIN a[362]
    DIRECTION INPUT ;
    USE SIGNAL ;
    PORT
      LAYER M4 ;
        RECT  0 68.976 0.084 69 ;
    END
  END a[362]
  PIN a[363]
    DIRECTION INPUT ;
    USE SIGNAL ;
    PORT
      LAYER M4 ;
        RECT  0 69.12 0.084 69.144 ;
    END
  END a[363]
  PIN a[364]
    DIRECTION INPUT ;
    USE SIGNAL ;
    PORT
      LAYER M4 ;
        RECT  0 69.264 0.084 69.288 ;
    END
  END a[364]
  PIN a[365]
    DIRECTION INPUT ;
    USE SIGNAL ;
    PORT
      LAYER M4 ;
        RECT  0 69.408 0.084 69.432 ;
    END
  END a[365]
  PIN a[366]
    DIRECTION INPUT ;
    USE SIGNAL ;
    PORT
      LAYER M4 ;
        RECT  0 69.552 0.084 69.576 ;
    END
  END a[366]
  PIN a[367]
    DIRECTION INPUT ;
    USE SIGNAL ;
    PORT
      LAYER M4 ;
        RECT  0 69.696 0.084 69.72 ;
    END
  END a[367]
  PIN a[368]
    DIRECTION INPUT ;
    USE SIGNAL ;
    PORT
      LAYER M4 ;
        RECT  0 69.84 0.084 69.864 ;
    END
  END a[368]
  PIN a[369]
    DIRECTION INPUT ;
    USE SIGNAL ;
    PORT
      LAYER M4 ;
        RECT  0 69.984 0.084 70.008 ;
    END
  END a[369]
  PIN a[36]
    DIRECTION INPUT ;
    USE SIGNAL ;
    PORT
      LAYER M4 ;
        RECT  0 34.704 0.084 34.728 ;
    END
  END a[36]
  PIN a[370]
    DIRECTION INPUT ;
    USE SIGNAL ;
    PORT
      LAYER M4 ;
        RECT  0 70.128 0.084 70.152 ;
    END
  END a[370]
  PIN a[371]
    DIRECTION INPUT ;
    USE SIGNAL ;
    PORT
      LAYER M4 ;
        RECT  0 70.272 0.084 70.296 ;
    END
  END a[371]
  PIN a[372]
    DIRECTION INPUT ;
    USE SIGNAL ;
    PORT
      LAYER M4 ;
        RECT  0 70.416 0.084 70.44 ;
    END
  END a[372]
  PIN a[373]
    DIRECTION INPUT ;
    USE SIGNAL ;
    PORT
      LAYER M4 ;
        RECT  0 70.56 0.084 70.584 ;
    END
  END a[373]
  PIN a[374]
    DIRECTION INPUT ;
    USE SIGNAL ;
    PORT
      LAYER M4 ;
        RECT  0 70.704 0.084 70.728 ;
    END
  END a[374]
  PIN a[375]
    DIRECTION INPUT ;
    USE SIGNAL ;
    PORT
      LAYER M4 ;
        RECT  0 70.848 0.084 70.872 ;
    END
  END a[375]
  PIN a[376]
    DIRECTION INPUT ;
    USE SIGNAL ;
    PORT
      LAYER M4 ;
        RECT  0 70.992 0.084 71.016 ;
    END
  END a[376]
  PIN a[377]
    DIRECTION INPUT ;
    USE SIGNAL ;
    PORT
      LAYER M4 ;
        RECT  0 71.136 0.084 71.16 ;
    END
  END a[377]
  PIN a[378]
    DIRECTION INPUT ;
    USE SIGNAL ;
    PORT
      LAYER M4 ;
        RECT  0 71.28 0.084 71.304 ;
    END
  END a[378]
  PIN a[379]
    DIRECTION INPUT ;
    USE SIGNAL ;
    PORT
      LAYER M4 ;
        RECT  0 71.424 0.084 71.448 ;
    END
  END a[379]
  PIN a[37]
    DIRECTION INPUT ;
    USE SIGNAL ;
    PORT
      LAYER M4 ;
        RECT  0 34.848 0.084 34.872 ;
    END
  END a[37]
  PIN a[380]
    DIRECTION INPUT ;
    USE SIGNAL ;
    PORT
      LAYER M4 ;
        RECT  0 71.568 0.084 71.592 ;
    END
  END a[380]
  PIN a[381]
    DIRECTION INPUT ;
    USE SIGNAL ;
    PORT
      LAYER M4 ;
        RECT  0 71.712 0.084 71.736 ;
    END
  END a[381]
  PIN a[382]
    DIRECTION INPUT ;
    USE SIGNAL ;
    PORT
      LAYER M4 ;
        RECT  0 71.856 0.084 71.88 ;
    END
  END a[382]
  PIN a[383]
    DIRECTION INPUT ;
    USE SIGNAL ;
    PORT
      LAYER M4 ;
        RECT  0 72 0.084 72.024 ;
    END
  END a[383]
  PIN a[384]
    DIRECTION INPUT ;
    USE SIGNAL ;
    PORT
      LAYER M4 ;
        RECT  0 5.328 0.084 5.352 ;
    END
  END a[384]
  PIN a[385]
    DIRECTION INPUT ;
    USE SIGNAL ;
    PORT
      LAYER M4 ;
        RECT  0 5.472 0.084 5.496 ;
    END
  END a[385]
  PIN a[386]
    DIRECTION INPUT ;
    USE SIGNAL ;
    PORT
      LAYER M4 ;
        RECT  0 5.616 0.084 5.64 ;
    END
  END a[386]
  PIN a[387]
    DIRECTION INPUT ;
    USE SIGNAL ;
    PORT
      LAYER M4 ;
        RECT  0 5.76 0.084 5.784 ;
    END
  END a[387]
  PIN a[388]
    DIRECTION INPUT ;
    USE SIGNAL ;
    PORT
      LAYER M4 ;
        RECT  0 5.904 0.084 5.928 ;
    END
  END a[388]
  PIN a[389]
    DIRECTION INPUT ;
    USE SIGNAL ;
    PORT
      LAYER M4 ;
        RECT  0 6.048 0.084 6.072 ;
    END
  END a[389]
  PIN a[38]
    DIRECTION INPUT ;
    USE SIGNAL ;
    PORT
      LAYER M4 ;
        RECT  0 34.992 0.084 35.016 ;
    END
  END a[38]
  PIN a[390]
    DIRECTION INPUT ;
    USE SIGNAL ;
    PORT
      LAYER M4 ;
        RECT  0 6.192 0.084 6.216 ;
    END
  END a[390]
  PIN a[391]
    DIRECTION INPUT ;
    USE SIGNAL ;
    PORT
      LAYER M4 ;
        RECT  0 6.336 0.084 6.36 ;
    END
  END a[391]
  PIN a[392]
    DIRECTION INPUT ;
    USE SIGNAL ;
    PORT
      LAYER M4 ;
        RECT  0 6.48 0.084 6.504 ;
    END
  END a[392]
  PIN a[393]
    DIRECTION INPUT ;
    USE SIGNAL ;
    PORT
      LAYER M4 ;
        RECT  0 6.624 0.084 6.648 ;
    END
  END a[393]
  PIN a[394]
    DIRECTION INPUT ;
    USE SIGNAL ;
    PORT
      LAYER M4 ;
        RECT  0 6.768 0.084 6.792 ;
    END
  END a[394]
  PIN a[395]
    DIRECTION INPUT ;
    USE SIGNAL ;
    PORT
      LAYER M4 ;
        RECT  0 6.912 0.084 6.936 ;
    END
  END a[395]
  PIN a[396]
    DIRECTION INPUT ;
    USE SIGNAL ;
    PORT
      LAYER M4 ;
        RECT  0 7.056 0.084 7.08 ;
    END
  END a[396]
  PIN a[397]
    DIRECTION INPUT ;
    USE SIGNAL ;
    PORT
      LAYER M4 ;
        RECT  0 7.2 0.084 7.224 ;
    END
  END a[397]
  PIN a[398]
    DIRECTION INPUT ;
    USE SIGNAL ;
    PORT
      LAYER M4 ;
        RECT  0 7.344 0.084 7.368 ;
    END
  END a[398]
  PIN a[399]
    DIRECTION INPUT ;
    USE SIGNAL ;
    PORT
      LAYER M4 ;
        RECT  0 7.488 0.084 7.512 ;
    END
  END a[399]
  PIN a[39]
    DIRECTION INPUT ;
    USE SIGNAL ;
    PORT
      LAYER M4 ;
        RECT  0 35.136 0.084 35.16 ;
    END
  END a[39]
  PIN a[3]
    DIRECTION INPUT ;
    USE SIGNAL ;
    PORT
      LAYER M4 ;
        RECT  0 25.344 0.084 25.368 ;
    END
  END a[3]
  PIN a[400]
    DIRECTION INPUT ;
    USE SIGNAL ;
    PORT
      LAYER M4 ;
        RECT  0 7.632 0.084 7.656 ;
    END
  END a[400]
  PIN a[401]
    DIRECTION INPUT ;
    USE SIGNAL ;
    PORT
      LAYER M4 ;
        RECT  0 7.776 0.084 7.8 ;
    END
  END a[401]
  PIN a[402]
    DIRECTION INPUT ;
    USE SIGNAL ;
    PORT
      LAYER M4 ;
        RECT  0 7.92 0.084 7.944 ;
    END
  END a[402]
  PIN a[403]
    DIRECTION INPUT ;
    USE SIGNAL ;
    PORT
      LAYER M4 ;
        RECT  0 8.064 0.084 8.088 ;
    END
  END a[403]
  PIN a[404]
    DIRECTION INPUT ;
    USE SIGNAL ;
    PORT
      LAYER M4 ;
        RECT  0 8.208 0.084 8.232 ;
    END
  END a[404]
  PIN a[405]
    DIRECTION INPUT ;
    USE SIGNAL ;
    PORT
      LAYER M4 ;
        RECT  0 8.352 0.084 8.376 ;
    END
  END a[405]
  PIN a[406]
    DIRECTION INPUT ;
    USE SIGNAL ;
    PORT
      LAYER M4 ;
        RECT  0 8.496 0.084 8.52 ;
    END
  END a[406]
  PIN a[407]
    DIRECTION INPUT ;
    USE SIGNAL ;
    PORT
      LAYER M4 ;
        RECT  0 8.64 0.084 8.664 ;
    END
  END a[407]
  PIN a[408]
    DIRECTION INPUT ;
    USE SIGNAL ;
    PORT
      LAYER M4 ;
        RECT  0 8.784 0.084 8.808 ;
    END
  END a[408]
  PIN a[409]
    DIRECTION INPUT ;
    USE SIGNAL ;
    PORT
      LAYER M4 ;
        RECT  0 8.928 0.084 8.952 ;
    END
  END a[409]
  PIN a[40]
    DIRECTION INPUT ;
    USE SIGNAL ;
    PORT
      LAYER M4 ;
        RECT  0 35.28 0.084 35.304 ;
    END
  END a[40]
  PIN a[410]
    DIRECTION INPUT ;
    USE SIGNAL ;
    PORT
      LAYER M4 ;
        RECT  0 9.072 0.084 9.096 ;
    END
  END a[410]
  PIN a[411]
    DIRECTION INPUT ;
    USE SIGNAL ;
    PORT
      LAYER M4 ;
        RECT  0 9.216 0.084 9.24 ;
    END
  END a[411]
  PIN a[412]
    DIRECTION INPUT ;
    USE SIGNAL ;
    PORT
      LAYER M4 ;
        RECT  0 9.36 0.084 9.384 ;
    END
  END a[412]
  PIN a[413]
    DIRECTION INPUT ;
    USE SIGNAL ;
    PORT
      LAYER M4 ;
        RECT  0 9.504 0.084 9.528 ;
    END
  END a[413]
  PIN a[414]
    DIRECTION INPUT ;
    USE SIGNAL ;
    PORT
      LAYER M4 ;
        RECT  0 9.648 0.084 9.672 ;
    END
  END a[414]
  PIN a[415]
    DIRECTION INPUT ;
    USE SIGNAL ;
    PORT
      LAYER M4 ;
        RECT  0 9.792 0.084 9.816 ;
    END
  END a[415]
  PIN a[416]
    DIRECTION INPUT ;
    USE SIGNAL ;
    PORT
      LAYER M4 ;
        RECT  0 14.544 0.084 14.568 ;
    END
  END a[416]
  PIN a[417]
    DIRECTION INPUT ;
    USE SIGNAL ;
    PORT
      LAYER M4 ;
        RECT  0 14.688 0.084 14.712 ;
    END
  END a[417]
  PIN a[418]
    DIRECTION INPUT ;
    USE SIGNAL ;
    PORT
      LAYER M4 ;
        RECT  0 14.832 0.084 14.856 ;
    END
  END a[418]
  PIN a[419]
    DIRECTION INPUT ;
    USE SIGNAL ;
    PORT
      LAYER M4 ;
        RECT  0 14.976 0.084 15 ;
    END
  END a[419]
  PIN a[41]
    DIRECTION INPUT ;
    USE SIGNAL ;
    PORT
      LAYER M4 ;
        RECT  0 35.424 0.084 35.448 ;
    END
  END a[41]
  PIN a[420]
    DIRECTION INPUT ;
    USE SIGNAL ;
    PORT
      LAYER M4 ;
        RECT  0 15.12 0.084 15.144 ;
    END
  END a[420]
  PIN a[421]
    DIRECTION INPUT ;
    USE SIGNAL ;
    PORT
      LAYER M4 ;
        RECT  0 15.264 0.084 15.288 ;
    END
  END a[421]
  PIN a[422]
    DIRECTION INPUT ;
    USE SIGNAL ;
    PORT
      LAYER M4 ;
        RECT  0 15.408 0.084 15.432 ;
    END
  END a[422]
  PIN a[423]
    DIRECTION INPUT ;
    USE SIGNAL ;
    PORT
      LAYER M4 ;
        RECT  0 15.552 0.084 15.576 ;
    END
  END a[423]
  PIN a[424]
    DIRECTION INPUT ;
    USE SIGNAL ;
    PORT
      LAYER M4 ;
        RECT  0 15.696 0.084 15.72 ;
    END
  END a[424]
  PIN a[425]
    DIRECTION INPUT ;
    USE SIGNAL ;
    PORT
      LAYER M4 ;
        RECT  0 15.84 0.084 15.864 ;
    END
  END a[425]
  PIN a[426]
    DIRECTION INPUT ;
    USE SIGNAL ;
    PORT
      LAYER M4 ;
        RECT  0 15.984 0.084 16.008 ;
    END
  END a[426]
  PIN a[427]
    DIRECTION INPUT ;
    USE SIGNAL ;
    PORT
      LAYER M4 ;
        RECT  0 16.128 0.084 16.152 ;
    END
  END a[427]
  PIN a[428]
    DIRECTION INPUT ;
    USE SIGNAL ;
    PORT
      LAYER M4 ;
        RECT  0 16.272 0.084 16.296 ;
    END
  END a[428]
  PIN a[429]
    DIRECTION INPUT ;
    USE SIGNAL ;
    PORT
      LAYER M4 ;
        RECT  0 16.416 0.084 16.44 ;
    END
  END a[429]
  PIN a[42]
    DIRECTION INPUT ;
    USE SIGNAL ;
    PORT
      LAYER M4 ;
        RECT  0 35.568 0.084 35.592 ;
    END
  END a[42]
  PIN a[430]
    DIRECTION INPUT ;
    USE SIGNAL ;
    PORT
      LAYER M4 ;
        RECT  0 16.56 0.084 16.584 ;
    END
  END a[430]
  PIN a[431]
    DIRECTION INPUT ;
    USE SIGNAL ;
    PORT
      LAYER M4 ;
        RECT  0 16.704 0.084 16.728 ;
    END
  END a[431]
  PIN a[432]
    DIRECTION INPUT ;
    USE SIGNAL ;
    PORT
      LAYER M4 ;
        RECT  0 16.848 0.084 16.872 ;
    END
  END a[432]
  PIN a[433]
    DIRECTION INPUT ;
    USE SIGNAL ;
    PORT
      LAYER M4 ;
        RECT  0 16.992 0.084 17.016 ;
    END
  END a[433]
  PIN a[434]
    DIRECTION INPUT ;
    USE SIGNAL ;
    PORT
      LAYER M4 ;
        RECT  0 17.136 0.084 17.16 ;
    END
  END a[434]
  PIN a[435]
    DIRECTION INPUT ;
    USE SIGNAL ;
    PORT
      LAYER M4 ;
        RECT  0 17.28 0.084 17.304 ;
    END
  END a[435]
  PIN a[436]
    DIRECTION INPUT ;
    USE SIGNAL ;
    PORT
      LAYER M4 ;
        RECT  0 17.424 0.084 17.448 ;
    END
  END a[436]
  PIN a[437]
    DIRECTION INPUT ;
    USE SIGNAL ;
    PORT
      LAYER M4 ;
        RECT  0 17.568 0.084 17.592 ;
    END
  END a[437]
  PIN a[438]
    DIRECTION INPUT ;
    USE SIGNAL ;
    PORT
      LAYER M4 ;
        RECT  0 17.712 0.084 17.736 ;
    END
  END a[438]
  PIN a[439]
    DIRECTION INPUT ;
    USE SIGNAL ;
    PORT
      LAYER M4 ;
        RECT  0 17.856 0.084 17.88 ;
    END
  END a[439]
  PIN a[43]
    DIRECTION INPUT ;
    USE SIGNAL ;
    PORT
      LAYER M4 ;
        RECT  0 35.712 0.084 35.736 ;
    END
  END a[43]
  PIN a[440]
    DIRECTION INPUT ;
    USE SIGNAL ;
    PORT
      LAYER M4 ;
        RECT  0 18 0.084 18.024 ;
    END
  END a[440]
  PIN a[441]
    DIRECTION INPUT ;
    USE SIGNAL ;
    PORT
      LAYER M4 ;
        RECT  0 18.144 0.084 18.168 ;
    END
  END a[441]
  PIN a[442]
    DIRECTION INPUT ;
    USE SIGNAL ;
    PORT
      LAYER M4 ;
        RECT  0 18.288 0.084 18.312 ;
    END
  END a[442]
  PIN a[443]
    DIRECTION INPUT ;
    USE SIGNAL ;
    PORT
      LAYER M4 ;
        RECT  0 18.432 0.084 18.456 ;
    END
  END a[443]
  PIN a[444]
    DIRECTION INPUT ;
    USE SIGNAL ;
    PORT
      LAYER M4 ;
        RECT  0 18.576 0.084 18.6 ;
    END
  END a[444]
  PIN a[445]
    DIRECTION INPUT ;
    USE SIGNAL ;
    PORT
      LAYER M4 ;
        RECT  0 18.72 0.084 18.744 ;
    END
  END a[445]
  PIN a[446]
    DIRECTION INPUT ;
    USE SIGNAL ;
    PORT
      LAYER M4 ;
        RECT  0 18.864 0.084 18.888 ;
    END
  END a[446]
  PIN a[447]
    DIRECTION INPUT ;
    USE SIGNAL ;
    PORT
      LAYER M4 ;
        RECT  0 19.008 0.084 19.032 ;
    END
  END a[447]
  PIN a[448]
    DIRECTION INPUT ;
    USE SIGNAL ;
    PORT
      LAYER M4 ;
        RECT  0 19.152 0.084 19.176 ;
    END
  END a[448]
  PIN a[449]
    DIRECTION INPUT ;
    USE SIGNAL ;
    PORT
      LAYER M4 ;
        RECT  0 19.296 0.084 19.32 ;
    END
  END a[449]
  PIN a[44]
    DIRECTION INPUT ;
    USE SIGNAL ;
    PORT
      LAYER M4 ;
        RECT  0 35.856 0.084 35.88 ;
    END
  END a[44]
  PIN a[450]
    DIRECTION INPUT ;
    USE SIGNAL ;
    PORT
      LAYER M4 ;
        RECT  0 19.44 0.084 19.464 ;
    END
  END a[450]
  PIN a[451]
    DIRECTION INPUT ;
    USE SIGNAL ;
    PORT
      LAYER M4 ;
        RECT  0 19.584 0.084 19.608 ;
    END
  END a[451]
  PIN a[452]
    DIRECTION INPUT ;
    USE SIGNAL ;
    PORT
      LAYER M4 ;
        RECT  0 19.728 0.084 19.752 ;
    END
  END a[452]
  PIN a[453]
    DIRECTION INPUT ;
    USE SIGNAL ;
    PORT
      LAYER M4 ;
        RECT  0 19.872 0.084 19.896 ;
    END
  END a[453]
  PIN a[454]
    DIRECTION INPUT ;
    USE SIGNAL ;
    PORT
      LAYER M4 ;
        RECT  0 20.016 0.084 20.04 ;
    END
  END a[454]
  PIN a[455]
    DIRECTION INPUT ;
    USE SIGNAL ;
    PORT
      LAYER M4 ;
        RECT  0 20.16 0.084 20.184 ;
    END
  END a[455]
  PIN a[456]
    DIRECTION INPUT ;
    USE SIGNAL ;
    PORT
      LAYER M4 ;
        RECT  0 20.304 0.084 20.328 ;
    END
  END a[456]
  PIN a[457]
    DIRECTION INPUT ;
    USE SIGNAL ;
    PORT
      LAYER M4 ;
        RECT  0 20.448 0.084 20.472 ;
    END
  END a[457]
  PIN a[458]
    DIRECTION INPUT ;
    USE SIGNAL ;
    PORT
      LAYER M4 ;
        RECT  0 20.592 0.084 20.616 ;
    END
  END a[458]
  PIN a[459]
    DIRECTION INPUT ;
    USE SIGNAL ;
    PORT
      LAYER M4 ;
        RECT  0 20.736 0.084 20.76 ;
    END
  END a[459]
  PIN a[45]
    DIRECTION INPUT ;
    USE SIGNAL ;
    PORT
      LAYER M4 ;
        RECT  0 36 0.084 36.024 ;
    END
  END a[45]
  PIN a[460]
    DIRECTION INPUT ;
    USE SIGNAL ;
    PORT
      LAYER M4 ;
        RECT  0 20.88 0.084 20.904 ;
    END
  END a[460]
  PIN a[461]
    DIRECTION INPUT ;
    USE SIGNAL ;
    PORT
      LAYER M4 ;
        RECT  0 21.024 0.084 21.048 ;
    END
  END a[461]
  PIN a[462]
    DIRECTION INPUT ;
    USE SIGNAL ;
    PORT
      LAYER M4 ;
        RECT  0 21.168 0.084 21.192 ;
    END
  END a[462]
  PIN a[463]
    DIRECTION INPUT ;
    USE SIGNAL ;
    PORT
      LAYER M4 ;
        RECT  0 21.312 0.084 21.336 ;
    END
  END a[463]
  PIN a[464]
    DIRECTION INPUT ;
    USE SIGNAL ;
    PORT
      LAYER M4 ;
        RECT  0 21.456 0.084 21.48 ;
    END
  END a[464]
  PIN a[465]
    DIRECTION INPUT ;
    USE SIGNAL ;
    PORT
      LAYER M4 ;
        RECT  0 21.6 0.084 21.624 ;
    END
  END a[465]
  PIN a[466]
    DIRECTION INPUT ;
    USE SIGNAL ;
    PORT
      LAYER M4 ;
        RECT  0 21.744 0.084 21.768 ;
    END
  END a[466]
  PIN a[467]
    DIRECTION INPUT ;
    USE SIGNAL ;
    PORT
      LAYER M4 ;
        RECT  0 21.888 0.084 21.912 ;
    END
  END a[467]
  PIN a[468]
    DIRECTION INPUT ;
    USE SIGNAL ;
    PORT
      LAYER M4 ;
        RECT  0 22.032 0.084 22.056 ;
    END
  END a[468]
  PIN a[469]
    DIRECTION INPUT ;
    USE SIGNAL ;
    PORT
      LAYER M4 ;
        RECT  0 22.176 0.084 22.2 ;
    END
  END a[469]
  PIN a[46]
    DIRECTION INPUT ;
    USE SIGNAL ;
    PORT
      LAYER M4 ;
        RECT  0 36.144 0.084 36.168 ;
    END
  END a[46]
  PIN a[470]
    DIRECTION INPUT ;
    USE SIGNAL ;
    PORT
      LAYER M4 ;
        RECT  0 22.32 0.084 22.344 ;
    END
  END a[470]
  PIN a[471]
    DIRECTION INPUT ;
    USE SIGNAL ;
    PORT
      LAYER M4 ;
        RECT  0 22.464 0.084 22.488 ;
    END
  END a[471]
  PIN a[472]
    DIRECTION INPUT ;
    USE SIGNAL ;
    PORT
      LAYER M4 ;
        RECT  0 22.608 0.084 22.632 ;
    END
  END a[472]
  PIN a[473]
    DIRECTION INPUT ;
    USE SIGNAL ;
    PORT
      LAYER M4 ;
        RECT  0 22.752 0.084 22.776 ;
    END
  END a[473]
  PIN a[474]
    DIRECTION INPUT ;
    USE SIGNAL ;
    PORT
      LAYER M4 ;
        RECT  0 22.896 0.084 22.92 ;
    END
  END a[474]
  PIN a[475]
    DIRECTION INPUT ;
    USE SIGNAL ;
    PORT
      LAYER M4 ;
        RECT  0 23.04 0.084 23.064 ;
    END
  END a[475]
  PIN a[476]
    DIRECTION INPUT ;
    USE SIGNAL ;
    PORT
      LAYER M4 ;
        RECT  0 23.184 0.084 23.208 ;
    END
  END a[476]
  PIN a[477]
    DIRECTION INPUT ;
    USE SIGNAL ;
    PORT
      LAYER M4 ;
        RECT  0 23.328 0.084 23.352 ;
    END
  END a[477]
  PIN a[478]
    DIRECTION INPUT ;
    USE SIGNAL ;
    PORT
      LAYER M4 ;
        RECT  0 23.472 0.084 23.496 ;
    END
  END a[478]
  PIN a[479]
    DIRECTION INPUT ;
    USE SIGNAL ;
    PORT
      LAYER M4 ;
        RECT  0 23.616 0.084 23.64 ;
    END
  END a[479]
  PIN a[47]
    DIRECTION INPUT ;
    USE SIGNAL ;
    PORT
      LAYER M4 ;
        RECT  0 36.288 0.084 36.312 ;
    END
  END a[47]
  PIN a[480]
    DIRECTION INPUT ;
    USE SIGNAL ;
    PORT
      LAYER M4 ;
        RECT  0 9.936 0.084 9.96 ;
    END
  END a[480]
  PIN a[481]
    DIRECTION INPUT ;
    USE SIGNAL ;
    PORT
      LAYER M4 ;
        RECT  0 10.08 0.084 10.104 ;
    END
  END a[481]
  PIN a[482]
    DIRECTION INPUT ;
    USE SIGNAL ;
    PORT
      LAYER M4 ;
        RECT  0 10.224 0.084 10.248 ;
    END
  END a[482]
  PIN a[483]
    DIRECTION INPUT ;
    USE SIGNAL ;
    PORT
      LAYER M4 ;
        RECT  0 10.368 0.084 10.392 ;
    END
  END a[483]
  PIN a[484]
    DIRECTION INPUT ;
    USE SIGNAL ;
    PORT
      LAYER M4 ;
        RECT  0 10.512 0.084 10.536 ;
    END
  END a[484]
  PIN a[485]
    DIRECTION INPUT ;
    USE SIGNAL ;
    PORT
      LAYER M4 ;
        RECT  0 10.656 0.084 10.68 ;
    END
  END a[485]
  PIN a[486]
    DIRECTION INPUT ;
    USE SIGNAL ;
    PORT
      LAYER M4 ;
        RECT  0 10.8 0.084 10.824 ;
    END
  END a[486]
  PIN a[487]
    DIRECTION INPUT ;
    USE SIGNAL ;
    PORT
      LAYER M4 ;
        RECT  0 10.944 0.084 10.968 ;
    END
  END a[487]
  PIN a[488]
    DIRECTION INPUT ;
    USE SIGNAL ;
    PORT
      LAYER M4 ;
        RECT  0 11.088 0.084 11.112 ;
    END
  END a[488]
  PIN a[489]
    DIRECTION INPUT ;
    USE SIGNAL ;
    PORT
      LAYER M4 ;
        RECT  0 11.232 0.084 11.256 ;
    END
  END a[489]
  PIN a[48]
    DIRECTION INPUT ;
    USE SIGNAL ;
    PORT
      LAYER M4 ;
        RECT  0 36.432 0.084 36.456 ;
    END
  END a[48]
  PIN a[490]
    DIRECTION INPUT ;
    USE SIGNAL ;
    PORT
      LAYER M4 ;
        RECT  0 11.376 0.084 11.4 ;
    END
  END a[490]
  PIN a[491]
    DIRECTION INPUT ;
    USE SIGNAL ;
    PORT
      LAYER M4 ;
        RECT  0 11.52 0.084 11.544 ;
    END
  END a[491]
  PIN a[492]
    DIRECTION INPUT ;
    USE SIGNAL ;
    PORT
      LAYER M4 ;
        RECT  0 11.664 0.084 11.688 ;
    END
  END a[492]
  PIN a[493]
    DIRECTION INPUT ;
    USE SIGNAL ;
    PORT
      LAYER M4 ;
        RECT  0 11.808 0.084 11.832 ;
    END
  END a[493]
  PIN a[494]
    DIRECTION INPUT ;
    USE SIGNAL ;
    PORT
      LAYER M4 ;
        RECT  0 11.952 0.084 11.976 ;
    END
  END a[494]
  PIN a[495]
    DIRECTION INPUT ;
    USE SIGNAL ;
    PORT
      LAYER M4 ;
        RECT  0 12.096 0.084 12.12 ;
    END
  END a[495]
  PIN a[496]
    DIRECTION INPUT ;
    USE SIGNAL ;
    PORT
      LAYER M4 ;
        RECT  0 12.24 0.084 12.264 ;
    END
  END a[496]
  PIN a[497]
    DIRECTION INPUT ;
    USE SIGNAL ;
    PORT
      LAYER M4 ;
        RECT  0 12.384 0.084 12.408 ;
    END
  END a[497]
  PIN a[498]
    DIRECTION INPUT ;
    USE SIGNAL ;
    PORT
      LAYER M4 ;
        RECT  0 12.528 0.084 12.552 ;
    END
  END a[498]
  PIN a[499]
    DIRECTION INPUT ;
    USE SIGNAL ;
    PORT
      LAYER M4 ;
        RECT  0 12.672 0.084 12.696 ;
    END
  END a[499]
  PIN a[49]
    DIRECTION INPUT ;
    USE SIGNAL ;
    PORT
      LAYER M4 ;
        RECT  0 36.576 0.084 36.6 ;
    END
  END a[49]
  PIN a[4]
    DIRECTION INPUT ;
    USE SIGNAL ;
    PORT
      LAYER M4 ;
        RECT  0 25.488 0.084 25.512 ;
    END
  END a[4]
  PIN a[500]
    DIRECTION INPUT ;
    USE SIGNAL ;
    PORT
      LAYER M4 ;
        RECT  0 12.816 0.084 12.84 ;
    END
  END a[500]
  PIN a[501]
    DIRECTION INPUT ;
    USE SIGNAL ;
    PORT
      LAYER M4 ;
        RECT  0 12.96 0.084 12.984 ;
    END
  END a[501]
  PIN a[502]
    DIRECTION INPUT ;
    USE SIGNAL ;
    PORT
      LAYER M4 ;
        RECT  0 13.104 0.084 13.128 ;
    END
  END a[502]
  PIN a[503]
    DIRECTION INPUT ;
    USE SIGNAL ;
    PORT
      LAYER M4 ;
        RECT  0 13.248 0.084 13.272 ;
    END
  END a[503]
  PIN a[504]
    DIRECTION INPUT ;
    USE SIGNAL ;
    PORT
      LAYER M4 ;
        RECT  0 13.392 0.084 13.416 ;
    END
  END a[504]
  PIN a[505]
    DIRECTION INPUT ;
    USE SIGNAL ;
    PORT
      LAYER M4 ;
        RECT  0 13.536 0.084 13.56 ;
    END
  END a[505]
  PIN a[506]
    DIRECTION INPUT ;
    USE SIGNAL ;
    PORT
      LAYER M4 ;
        RECT  0 13.68 0.084 13.704 ;
    END
  END a[506]
  PIN a[507]
    DIRECTION INPUT ;
    USE SIGNAL ;
    PORT
      LAYER M4 ;
        RECT  0 13.824 0.084 13.848 ;
    END
  END a[507]
  PIN a[508]
    DIRECTION INPUT ;
    USE SIGNAL ;
    PORT
      LAYER M4 ;
        RECT  0 13.968 0.084 13.992 ;
    END
  END a[508]
  PIN a[509]
    DIRECTION INPUT ;
    USE SIGNAL ;
    PORT
      LAYER M4 ;
        RECT  0 14.112 0.084 14.136 ;
    END
  END a[509]
  PIN a[50]
    DIRECTION INPUT ;
    USE SIGNAL ;
    PORT
      LAYER M4 ;
        RECT  0 36.72 0.084 36.744 ;
    END
  END a[50]
  PIN a[510]
    DIRECTION INPUT ;
    USE SIGNAL ;
    PORT
      LAYER M4 ;
        RECT  0 14.256 0.084 14.28 ;
    END
  END a[510]
  PIN a[511]
    DIRECTION INPUT ;
    USE SIGNAL ;
    PORT
      LAYER M4 ;
        RECT  0 14.4 0.084 14.424 ;
    END
  END a[511]
  PIN a[512]
    DIRECTION INPUT ;
    USE SIGNAL ;
    PORT
      LAYER M4 ;
        RECT  0 3.024 0.084 3.048 ;
    END
  END a[512]
  PIN a[513]
    DIRECTION INPUT ;
    USE SIGNAL ;
    PORT
      LAYER M4 ;
        RECT  0 3.168 0.084 3.192 ;
    END
  END a[513]
  PIN a[514]
    DIRECTION INPUT ;
    USE SIGNAL ;
    PORT
      LAYER M4 ;
        RECT  0 3.312 0.084 3.336 ;
    END
  END a[514]
  PIN a[515]
    DIRECTION INPUT ;
    USE SIGNAL ;
    PORT
      LAYER M4 ;
        RECT  0 3.456 0.084 3.48 ;
    END
  END a[515]
  PIN a[516]
    DIRECTION INPUT ;
    USE SIGNAL ;
    PORT
      LAYER M4 ;
        RECT  0 3.6 0.084 3.624 ;
    END
  END a[516]
  PIN a[517]
    DIRECTION INPUT ;
    USE SIGNAL ;
    PORT
      LAYER M4 ;
        RECT  0 3.744 0.084 3.768 ;
    END
  END a[517]
  PIN a[518]
    DIRECTION INPUT ;
    USE SIGNAL ;
    PORT
      LAYER M4 ;
        RECT  0 3.888 0.084 3.912 ;
    END
  END a[518]
  PIN a[519]
    DIRECTION INPUT ;
    USE SIGNAL ;
    PORT
      LAYER M4 ;
        RECT  0 4.032 0.084 4.056 ;
    END
  END a[519]
  PIN a[51]
    DIRECTION INPUT ;
    USE SIGNAL ;
    PORT
      LAYER M4 ;
        RECT  0 36.864 0.084 36.888 ;
    END
  END a[51]
  PIN a[520]
    DIRECTION INPUT ;
    USE SIGNAL ;
    PORT
      LAYER M4 ;
        RECT  0 4.176 0.084 4.2 ;
    END
  END a[520]
  PIN a[521]
    DIRECTION INPUT ;
    USE SIGNAL ;
    PORT
      LAYER M4 ;
        RECT  0 4.32 0.084 4.344 ;
    END
  END a[521]
  PIN a[522]
    DIRECTION INPUT ;
    USE SIGNAL ;
    PORT
      LAYER M4 ;
        RECT  0 4.464 0.084 4.488 ;
    END
  END a[522]
  PIN a[523]
    DIRECTION INPUT ;
    USE SIGNAL ;
    PORT
      LAYER M4 ;
        RECT  0 4.608 0.084 4.632 ;
    END
  END a[523]
  PIN a[524]
    DIRECTION INPUT ;
    USE SIGNAL ;
    PORT
      LAYER M4 ;
        RECT  0 4.752 0.084 4.776 ;
    END
  END a[524]
  PIN a[525]
    DIRECTION INPUT ;
    USE SIGNAL ;
    PORT
      LAYER M4 ;
        RECT  0 4.896 0.084 4.92 ;
    END
  END a[525]
  PIN a[526]
    DIRECTION INPUT ;
    USE SIGNAL ;
    PORT
      LAYER M4 ;
        RECT  0 5.04 0.084 5.064 ;
    END
  END a[526]
  PIN a[527]
    DIRECTION INPUT ;
    USE SIGNAL ;
    PORT
      LAYER M4 ;
        RECT  0 5.184 0.084 5.208 ;
    END
  END a[527]
  PIN a[52]
    DIRECTION INPUT ;
    USE SIGNAL ;
    PORT
      LAYER M4 ;
        RECT  0 37.008 0.084 37.032 ;
    END
  END a[52]
  PIN a[53]
    DIRECTION INPUT ;
    USE SIGNAL ;
    PORT
      LAYER M4 ;
        RECT  0 37.152 0.084 37.176 ;
    END
  END a[53]
  PIN a[54]
    DIRECTION INPUT ;
    USE SIGNAL ;
    PORT
      LAYER M4 ;
        RECT  0 37.296 0.084 37.32 ;
    END
  END a[54]
  PIN a[55]
    DIRECTION INPUT ;
    USE SIGNAL ;
    PORT
      LAYER M4 ;
        RECT  0 37.44 0.084 37.464 ;
    END
  END a[55]
  PIN a[56]
    DIRECTION INPUT ;
    USE SIGNAL ;
    PORT
      LAYER M4 ;
        RECT  0 37.584 0.084 37.608 ;
    END
  END a[56]
  PIN a[57]
    DIRECTION INPUT ;
    USE SIGNAL ;
    PORT
      LAYER M4 ;
        RECT  0 37.728 0.084 37.752 ;
    END
  END a[57]
  PIN a[58]
    DIRECTION INPUT ;
    USE SIGNAL ;
    PORT
      LAYER M4 ;
        RECT  0 37.872 0.084 37.896 ;
    END
  END a[58]
  PIN a[59]
    DIRECTION INPUT ;
    USE SIGNAL ;
    PORT
      LAYER M4 ;
        RECT  0 38.016 0.084 38.04 ;
    END
  END a[59]
  PIN a[5]
    DIRECTION INPUT ;
    USE SIGNAL ;
    PORT
      LAYER M4 ;
        RECT  0 25.632 0.084 25.656 ;
    END
  END a[5]
  PIN a[60]
    DIRECTION INPUT ;
    USE SIGNAL ;
    PORT
      LAYER M4 ;
        RECT  0 38.16 0.084 38.184 ;
    END
  END a[60]
  PIN a[61]
    DIRECTION INPUT ;
    USE SIGNAL ;
    PORT
      LAYER M4 ;
        RECT  0 38.304 0.084 38.328 ;
    END
  END a[61]
  PIN a[62]
    DIRECTION INPUT ;
    USE SIGNAL ;
    PORT
      LAYER M4 ;
        RECT  0 38.448 0.084 38.472 ;
    END
  END a[62]
  PIN a[63]
    DIRECTION INPUT ;
    USE SIGNAL ;
    PORT
      LAYER M4 ;
        RECT  0 38.592 0.084 38.616 ;
    END
  END a[63]
  PIN a[64]
    DIRECTION INPUT ;
    USE SIGNAL ;
    PORT
      LAYER M4 ;
        RECT  0 47.952 0.084 47.976 ;
    END
  END a[64]
  PIN a[65]
    DIRECTION INPUT ;
    USE SIGNAL ;
    PORT
      LAYER M4 ;
        RECT  0 48.096 0.084 48.12 ;
    END
  END a[65]
  PIN a[66]
    DIRECTION INPUT ;
    USE SIGNAL ;
    PORT
      LAYER M4 ;
        RECT  0 48.24 0.084 48.264 ;
    END
  END a[66]
  PIN a[67]
    DIRECTION INPUT ;
    USE SIGNAL ;
    PORT
      LAYER M4 ;
        RECT  0 48.384 0.084 48.408 ;
    END
  END a[67]
  PIN a[68]
    DIRECTION INPUT ;
    USE SIGNAL ;
    PORT
      LAYER M4 ;
        RECT  0 48.528 0.084 48.552 ;
    END
  END a[68]
  PIN a[69]
    DIRECTION INPUT ;
    USE SIGNAL ;
    PORT
      LAYER M4 ;
        RECT  0 48.672 0.084 48.696 ;
    END
  END a[69]
  PIN a[6]
    DIRECTION INPUT ;
    USE SIGNAL ;
    PORT
      LAYER M4 ;
        RECT  0 25.776 0.084 25.8 ;
    END
  END a[6]
  PIN a[70]
    DIRECTION INPUT ;
    USE SIGNAL ;
    PORT
      LAYER M4 ;
        RECT  0 48.816 0.084 48.84 ;
    END
  END a[70]
  PIN a[71]
    DIRECTION INPUT ;
    USE SIGNAL ;
    PORT
      LAYER M4 ;
        RECT  0 48.96 0.084 48.984 ;
    END
  END a[71]
  PIN a[72]
    DIRECTION INPUT ;
    USE SIGNAL ;
    PORT
      LAYER M4 ;
        RECT  0 49.104 0.084 49.128 ;
    END
  END a[72]
  PIN a[73]
    DIRECTION INPUT ;
    USE SIGNAL ;
    PORT
      LAYER M4 ;
        RECT  0 49.248 0.084 49.272 ;
    END
  END a[73]
  PIN a[74]
    DIRECTION INPUT ;
    USE SIGNAL ;
    PORT
      LAYER M4 ;
        RECT  0 49.392 0.084 49.416 ;
    END
  END a[74]
  PIN a[75]
    DIRECTION INPUT ;
    USE SIGNAL ;
    PORT
      LAYER M4 ;
        RECT  0 49.536 0.084 49.56 ;
    END
  END a[75]
  PIN a[76]
    DIRECTION INPUT ;
    USE SIGNAL ;
    PORT
      LAYER M4 ;
        RECT  0 49.68 0.084 49.704 ;
    END
  END a[76]
  PIN a[77]
    DIRECTION INPUT ;
    USE SIGNAL ;
    PORT
      LAYER M4 ;
        RECT  0 49.824 0.084 49.848 ;
    END
  END a[77]
  PIN a[78]
    DIRECTION INPUT ;
    USE SIGNAL ;
    PORT
      LAYER M4 ;
        RECT  0 49.968 0.084 49.992 ;
    END
  END a[78]
  PIN a[79]
    DIRECTION INPUT ;
    USE SIGNAL ;
    PORT
      LAYER M4 ;
        RECT  0 50.112 0.084 50.136 ;
    END
  END a[79]
  PIN a[7]
    DIRECTION INPUT ;
    USE SIGNAL ;
    PORT
      LAYER M4 ;
        RECT  0 25.92 0.084 25.944 ;
    END
  END a[7]
  PIN a[80]
    DIRECTION INPUT ;
    USE SIGNAL ;
    PORT
      LAYER M4 ;
        RECT  0 50.256 0.084 50.28 ;
    END
  END a[80]
  PIN a[81]
    DIRECTION INPUT ;
    USE SIGNAL ;
    PORT
      LAYER M4 ;
        RECT  0 50.4 0.084 50.424 ;
    END
  END a[81]
  PIN a[82]
    DIRECTION INPUT ;
    USE SIGNAL ;
    PORT
      LAYER M4 ;
        RECT  0 50.544 0.084 50.568 ;
    END
  END a[82]
  PIN a[83]
    DIRECTION INPUT ;
    USE SIGNAL ;
    PORT
      LAYER M4 ;
        RECT  0 50.688 0.084 50.712 ;
    END
  END a[83]
  PIN a[84]
    DIRECTION INPUT ;
    USE SIGNAL ;
    PORT
      LAYER M4 ;
        RECT  0 50.832 0.084 50.856 ;
    END
  END a[84]
  PIN a[85]
    DIRECTION INPUT ;
    USE SIGNAL ;
    PORT
      LAYER M4 ;
        RECT  0 50.976 0.084 51 ;
    END
  END a[85]
  PIN a[86]
    DIRECTION INPUT ;
    USE SIGNAL ;
    PORT
      LAYER M4 ;
        RECT  0 51.12 0.084 51.144 ;
    END
  END a[86]
  PIN a[87]
    DIRECTION INPUT ;
    USE SIGNAL ;
    PORT
      LAYER M4 ;
        RECT  0 51.264 0.084 51.288 ;
    END
  END a[87]
  PIN a[88]
    DIRECTION INPUT ;
    USE SIGNAL ;
    PORT
      LAYER M4 ;
        RECT  0 51.408 0.084 51.432 ;
    END
  END a[88]
  PIN a[89]
    DIRECTION INPUT ;
    USE SIGNAL ;
    PORT
      LAYER M4 ;
        RECT  0 51.552 0.084 51.576 ;
    END
  END a[89]
  PIN a[8]
    DIRECTION INPUT ;
    USE SIGNAL ;
    PORT
      LAYER M4 ;
        RECT  0 26.064 0.084 26.088 ;
    END
  END a[8]
  PIN a[90]
    DIRECTION INPUT ;
    USE SIGNAL ;
    PORT
      LAYER M4 ;
        RECT  0 51.696 0.084 51.72 ;
    END
  END a[90]
  PIN a[91]
    DIRECTION INPUT ;
    USE SIGNAL ;
    PORT
      LAYER M4 ;
        RECT  0 51.84 0.084 51.864 ;
    END
  END a[91]
  PIN a[92]
    DIRECTION INPUT ;
    USE SIGNAL ;
    PORT
      LAYER M4 ;
        RECT  0 51.984 0.084 52.008 ;
    END
  END a[92]
  PIN a[93]
    DIRECTION INPUT ;
    USE SIGNAL ;
    PORT
      LAYER M4 ;
        RECT  0 52.128 0.084 52.152 ;
    END
  END a[93]
  PIN a[94]
    DIRECTION INPUT ;
    USE SIGNAL ;
    PORT
      LAYER M4 ;
        RECT  0 52.272 0.084 52.296 ;
    END
  END a[94]
  PIN a[95]
    DIRECTION INPUT ;
    USE SIGNAL ;
    PORT
      LAYER M4 ;
        RECT  0 52.416 0.084 52.44 ;
    END
  END a[95]
  PIN a[96]
    DIRECTION INPUT ;
    USE SIGNAL ;
    PORT
      LAYER M4 ;
        RECT  0 29.52 0.084 29.544 ;
    END
  END a[96]
  PIN a[97]
    DIRECTION INPUT ;
    USE SIGNAL ;
    PORT
      LAYER M4 ;
        RECT  0 29.664 0.084 29.688 ;
    END
  END a[97]
  PIN a[98]
    DIRECTION INPUT ;
    USE SIGNAL ;
    PORT
      LAYER M4 ;
        RECT  0 29.808 0.084 29.832 ;
    END
  END a[98]
  PIN a[99]
    DIRECTION INPUT ;
    USE SIGNAL ;
    PORT
      LAYER M4 ;
        RECT  0 29.952 0.084 29.976 ;
    END
  END a[99]
  PIN a[9]
    DIRECTION INPUT ;
    USE SIGNAL ;
    PORT
      LAYER M4 ;
        RECT  0 26.208 0.084 26.232 ;
    END
  END a[9]
  PIN b[0]
    DIRECTION OUTPUT ;
    USE SIGNAL ;
    PORT
      LAYER M4 ;
        RECT  21.516 29.52 21.6 29.544 ;
    END
  END b[0]
  PIN b[100]
    DIRECTION OUTPUT ;
    USE SIGNAL ;
    PORT
      LAYER M4 ;
        RECT  21.516 34.704 21.6 34.728 ;
    END
  END b[100]
  PIN b[101]
    DIRECTION OUTPUT ;
    USE SIGNAL ;
    PORT
      LAYER M4 ;
        RECT  21.516 34.848 21.6 34.872 ;
    END
  END b[101]
  PIN b[102]
    DIRECTION OUTPUT ;
    USE SIGNAL ;
    PORT
      LAYER M4 ;
        RECT  21.516 34.992 21.6 35.016 ;
    END
  END b[102]
  PIN b[103]
    DIRECTION OUTPUT ;
    USE SIGNAL ;
    PORT
      LAYER M4 ;
        RECT  21.516 35.136 21.6 35.16 ;
    END
  END b[103]
  PIN b[104]
    DIRECTION OUTPUT ;
    USE SIGNAL ;
    PORT
      LAYER M4 ;
        RECT  21.516 35.28 21.6 35.304 ;
    END
  END b[104]
  PIN b[105]
    DIRECTION OUTPUT ;
    USE SIGNAL ;
    PORT
      LAYER M4 ;
        RECT  21.516 35.424 21.6 35.448 ;
    END
  END b[105]
  PIN b[106]
    DIRECTION OUTPUT ;
    USE SIGNAL ;
    PORT
      LAYER M4 ;
        RECT  21.516 35.568 21.6 35.592 ;
    END
  END b[106]
  PIN b[107]
    DIRECTION OUTPUT ;
    USE SIGNAL ;
    PORT
      LAYER M4 ;
        RECT  21.516 35.712 21.6 35.736 ;
    END
  END b[107]
  PIN b[108]
    DIRECTION OUTPUT ;
    USE SIGNAL ;
    PORT
      LAYER M4 ;
        RECT  21.516 35.856 21.6 35.88 ;
    END
  END b[108]
  PIN b[109]
    DIRECTION OUTPUT ;
    USE SIGNAL ;
    PORT
      LAYER M4 ;
        RECT  21.516 36 21.6 36.024 ;
    END
  END b[109]
  PIN b[10]
    DIRECTION OUTPUT ;
    USE SIGNAL ;
    PORT
      LAYER M4 ;
        RECT  21.516 30.96 21.6 30.984 ;
    END
  END b[10]
  PIN b[110]
    DIRECTION OUTPUT ;
    USE SIGNAL ;
    PORT
      LAYER M4 ;
        RECT  21.516 36.144 21.6 36.168 ;
    END
  END b[110]
  PIN b[111]
    DIRECTION OUTPUT ;
    USE SIGNAL ;
    PORT
      LAYER M4 ;
        RECT  21.516 36.288 21.6 36.312 ;
    END
  END b[111]
  PIN b[112]
    DIRECTION OUTPUT ;
    USE SIGNAL ;
    PORT
      LAYER M4 ;
        RECT  21.516 36.432 21.6 36.456 ;
    END
  END b[112]
  PIN b[113]
    DIRECTION OUTPUT ;
    USE SIGNAL ;
    PORT
      LAYER M4 ;
        RECT  21.516 36.576 21.6 36.6 ;
    END
  END b[113]
  PIN b[114]
    DIRECTION OUTPUT ;
    USE SIGNAL ;
    PORT
      LAYER M4 ;
        RECT  21.516 36.72 21.6 36.744 ;
    END
  END b[114]
  PIN b[115]
    DIRECTION OUTPUT ;
    USE SIGNAL ;
    PORT
      LAYER M4 ;
        RECT  21.516 36.864 21.6 36.888 ;
    END
  END b[115]
  PIN b[116]
    DIRECTION OUTPUT ;
    USE SIGNAL ;
    PORT
      LAYER M4 ;
        RECT  21.516 37.008 21.6 37.032 ;
    END
  END b[116]
  PIN b[117]
    DIRECTION OUTPUT ;
    USE SIGNAL ;
    PORT
      LAYER M4 ;
        RECT  21.516 37.152 21.6 37.176 ;
    END
  END b[117]
  PIN b[118]
    DIRECTION OUTPUT ;
    USE SIGNAL ;
    PORT
      LAYER M4 ;
        RECT  21.516 37.296 21.6 37.32 ;
    END
  END b[118]
  PIN b[119]
    DIRECTION OUTPUT ;
    USE SIGNAL ;
    PORT
      LAYER M4 ;
        RECT  21.516 37.44 21.6 37.464 ;
    END
  END b[119]
  PIN b[11]
    DIRECTION OUTPUT ;
    USE SIGNAL ;
    PORT
      LAYER M4 ;
        RECT  21.516 31.104 21.6 31.128 ;
    END
  END b[11]
  PIN b[120]
    DIRECTION OUTPUT ;
    USE SIGNAL ;
    PORT
      LAYER M4 ;
        RECT  21.516 37.584 21.6 37.608 ;
    END
  END b[120]
  PIN b[121]
    DIRECTION OUTPUT ;
    USE SIGNAL ;
    PORT
      LAYER M4 ;
        RECT  21.516 37.728 21.6 37.752 ;
    END
  END b[121]
  PIN b[122]
    DIRECTION OUTPUT ;
    USE SIGNAL ;
    PORT
      LAYER M4 ;
        RECT  21.516 37.872 21.6 37.896 ;
    END
  END b[122]
  PIN b[123]
    DIRECTION OUTPUT ;
    USE SIGNAL ;
    PORT
      LAYER M4 ;
        RECT  21.516 38.016 21.6 38.04 ;
    END
  END b[123]
  PIN b[124]
    DIRECTION OUTPUT ;
    USE SIGNAL ;
    PORT
      LAYER M4 ;
        RECT  21.516 38.16 21.6 38.184 ;
    END
  END b[124]
  PIN b[125]
    DIRECTION OUTPUT ;
    USE SIGNAL ;
    PORT
      LAYER M4 ;
        RECT  21.516 38.304 21.6 38.328 ;
    END
  END b[125]
  PIN b[126]
    DIRECTION OUTPUT ;
    USE SIGNAL ;
    PORT
      LAYER M4 ;
        RECT  21.516 38.448 21.6 38.472 ;
    END
  END b[126]
  PIN b[127]
    DIRECTION OUTPUT ;
    USE SIGNAL ;
    PORT
      LAYER M4 ;
        RECT  21.516 38.592 21.6 38.616 ;
    END
  END b[127]
  PIN b[128]
    DIRECTION OUTPUT ;
    USE SIGNAL ;
    PORT
      LAYER M4 ;
        RECT  21.516 47.952 21.6 47.976 ;
    END
  END b[128]
  PIN b[129]
    DIRECTION OUTPUT ;
    USE SIGNAL ;
    PORT
      LAYER M4 ;
        RECT  21.516 48.096 21.6 48.12 ;
    END
  END b[129]
  PIN b[12]
    DIRECTION OUTPUT ;
    USE SIGNAL ;
    PORT
      LAYER M4 ;
        RECT  21.516 31.248 21.6 31.272 ;
    END
  END b[12]
  PIN b[130]
    DIRECTION OUTPUT ;
    USE SIGNAL ;
    PORT
      LAYER M4 ;
        RECT  21.516 48.24 21.6 48.264 ;
    END
  END b[130]
  PIN b[131]
    DIRECTION OUTPUT ;
    USE SIGNAL ;
    PORT
      LAYER M4 ;
        RECT  21.516 48.384 21.6 48.408 ;
    END
  END b[131]
  PIN b[132]
    DIRECTION OUTPUT ;
    USE SIGNAL ;
    PORT
      LAYER M4 ;
        RECT  21.516 48.528 21.6 48.552 ;
    END
  END b[132]
  PIN b[133]
    DIRECTION OUTPUT ;
    USE SIGNAL ;
    PORT
      LAYER M4 ;
        RECT  21.516 48.672 21.6 48.696 ;
    END
  END b[133]
  PIN b[134]
    DIRECTION OUTPUT ;
    USE SIGNAL ;
    PORT
      LAYER M4 ;
        RECT  21.516 48.816 21.6 48.84 ;
    END
  END b[134]
  PIN b[135]
    DIRECTION OUTPUT ;
    USE SIGNAL ;
    PORT
      LAYER M4 ;
        RECT  21.516 48.96 21.6 48.984 ;
    END
  END b[135]
  PIN b[136]
    DIRECTION OUTPUT ;
    USE SIGNAL ;
    PORT
      LAYER M4 ;
        RECT  21.516 49.104 21.6 49.128 ;
    END
  END b[136]
  PIN b[137]
    DIRECTION OUTPUT ;
    USE SIGNAL ;
    PORT
      LAYER M4 ;
        RECT  21.516 49.248 21.6 49.272 ;
    END
  END b[137]
  PIN b[138]
    DIRECTION OUTPUT ;
    USE SIGNAL ;
    PORT
      LAYER M4 ;
        RECT  21.516 49.392 21.6 49.416 ;
    END
  END b[138]
  PIN b[139]
    DIRECTION OUTPUT ;
    USE SIGNAL ;
    PORT
      LAYER M4 ;
        RECT  21.516 49.536 21.6 49.56 ;
    END
  END b[139]
  PIN b[13]
    DIRECTION OUTPUT ;
    USE SIGNAL ;
    PORT
      LAYER M4 ;
        RECT  21.516 31.392 21.6 31.416 ;
    END
  END b[13]
  PIN b[140]
    DIRECTION OUTPUT ;
    USE SIGNAL ;
    PORT
      LAYER M4 ;
        RECT  21.516 49.68 21.6 49.704 ;
    END
  END b[140]
  PIN b[141]
    DIRECTION OUTPUT ;
    USE SIGNAL ;
    PORT
      LAYER M4 ;
        RECT  21.516 49.824 21.6 49.848 ;
    END
  END b[141]
  PIN b[142]
    DIRECTION OUTPUT ;
    USE SIGNAL ;
    PORT
      LAYER M4 ;
        RECT  21.516 49.968 21.6 49.992 ;
    END
  END b[142]
  PIN b[143]
    DIRECTION OUTPUT ;
    USE SIGNAL ;
    PORT
      LAYER M4 ;
        RECT  21.516 50.112 21.6 50.136 ;
    END
  END b[143]
  PIN b[144]
    DIRECTION OUTPUT ;
    USE SIGNAL ;
    PORT
      LAYER M4 ;
        RECT  21.516 50.256 21.6 50.28 ;
    END
  END b[144]
  PIN b[145]
    DIRECTION OUTPUT ;
    USE SIGNAL ;
    PORT
      LAYER M4 ;
        RECT  21.516 50.4 21.6 50.424 ;
    END
  END b[145]
  PIN b[146]
    DIRECTION OUTPUT ;
    USE SIGNAL ;
    PORT
      LAYER M4 ;
        RECT  21.516 50.544 21.6 50.568 ;
    END
  END b[146]
  PIN b[147]
    DIRECTION OUTPUT ;
    USE SIGNAL ;
    PORT
      LAYER M4 ;
        RECT  21.516 50.688 21.6 50.712 ;
    END
  END b[147]
  PIN b[148]
    DIRECTION OUTPUT ;
    USE SIGNAL ;
    PORT
      LAYER M4 ;
        RECT  21.516 50.832 21.6 50.856 ;
    END
  END b[148]
  PIN b[149]
    DIRECTION OUTPUT ;
    USE SIGNAL ;
    PORT
      LAYER M4 ;
        RECT  21.516 50.976 21.6 51 ;
    END
  END b[149]
  PIN b[14]
    DIRECTION OUTPUT ;
    USE SIGNAL ;
    PORT
      LAYER M4 ;
        RECT  21.516 31.536 21.6 31.56 ;
    END
  END b[14]
  PIN b[150]
    DIRECTION OUTPUT ;
    USE SIGNAL ;
    PORT
      LAYER M4 ;
        RECT  21.516 51.12 21.6 51.144 ;
    END
  END b[150]
  PIN b[151]
    DIRECTION OUTPUT ;
    USE SIGNAL ;
    PORT
      LAYER M4 ;
        RECT  21.516 51.264 21.6 51.288 ;
    END
  END b[151]
  PIN b[152]
    DIRECTION OUTPUT ;
    USE SIGNAL ;
    PORT
      LAYER M4 ;
        RECT  21.516 51.408 21.6 51.432 ;
    END
  END b[152]
  PIN b[153]
    DIRECTION OUTPUT ;
    USE SIGNAL ;
    PORT
      LAYER M4 ;
        RECT  21.516 51.552 21.6 51.576 ;
    END
  END b[153]
  PIN b[154]
    DIRECTION OUTPUT ;
    USE SIGNAL ;
    PORT
      LAYER M4 ;
        RECT  21.516 51.696 21.6 51.72 ;
    END
  END b[154]
  PIN b[155]
    DIRECTION OUTPUT ;
    USE SIGNAL ;
    PORT
      LAYER M4 ;
        RECT  21.516 51.84 21.6 51.864 ;
    END
  END b[155]
  PIN b[156]
    DIRECTION OUTPUT ;
    USE SIGNAL ;
    PORT
      LAYER M4 ;
        RECT  21.516 51.984 21.6 52.008 ;
    END
  END b[156]
  PIN b[157]
    DIRECTION OUTPUT ;
    USE SIGNAL ;
    PORT
      LAYER M4 ;
        RECT  21.516 52.128 21.6 52.152 ;
    END
  END b[157]
  PIN b[158]
    DIRECTION OUTPUT ;
    USE SIGNAL ;
    PORT
      LAYER M4 ;
        RECT  21.516 52.272 21.6 52.296 ;
    END
  END b[158]
  PIN b[159]
    DIRECTION OUTPUT ;
    USE SIGNAL ;
    PORT
      LAYER M4 ;
        RECT  21.516 52.416 21.6 52.44 ;
    END
  END b[159]
  PIN b[15]
    DIRECTION OUTPUT ;
    USE SIGNAL ;
    PORT
      LAYER M4 ;
        RECT  21.516 31.68 21.6 31.704 ;
    END
  END b[15]
  PIN b[160]
    DIRECTION OUTPUT ;
    USE SIGNAL ;
    PORT
      LAYER M4 ;
        RECT  21.516 43.344 21.6 43.368 ;
    END
  END b[160]
  PIN b[161]
    DIRECTION OUTPUT ;
    USE SIGNAL ;
    PORT
      LAYER M4 ;
        RECT  21.516 43.488 21.6 43.512 ;
    END
  END b[161]
  PIN b[162]
    DIRECTION OUTPUT ;
    USE SIGNAL ;
    PORT
      LAYER M4 ;
        RECT  21.516 43.632 21.6 43.656 ;
    END
  END b[162]
  PIN b[163]
    DIRECTION OUTPUT ;
    USE SIGNAL ;
    PORT
      LAYER M4 ;
        RECT  21.516 43.776 21.6 43.8 ;
    END
  END b[163]
  PIN b[164]
    DIRECTION OUTPUT ;
    USE SIGNAL ;
    PORT
      LAYER M4 ;
        RECT  21.516 43.92 21.6 43.944 ;
    END
  END b[164]
  PIN b[165]
    DIRECTION OUTPUT ;
    USE SIGNAL ;
    PORT
      LAYER M4 ;
        RECT  21.516 44.064 21.6 44.088 ;
    END
  END b[165]
  PIN b[166]
    DIRECTION OUTPUT ;
    USE SIGNAL ;
    PORT
      LAYER M4 ;
        RECT  21.516 44.208 21.6 44.232 ;
    END
  END b[166]
  PIN b[167]
    DIRECTION OUTPUT ;
    USE SIGNAL ;
    PORT
      LAYER M4 ;
        RECT  21.516 44.352 21.6 44.376 ;
    END
  END b[167]
  PIN b[168]
    DIRECTION OUTPUT ;
    USE SIGNAL ;
    PORT
      LAYER M4 ;
        RECT  21.516 44.496 21.6 44.52 ;
    END
  END b[168]
  PIN b[169]
    DIRECTION OUTPUT ;
    USE SIGNAL ;
    PORT
      LAYER M4 ;
        RECT  21.516 44.64 21.6 44.664 ;
    END
  END b[169]
  PIN b[16]
    DIRECTION OUTPUT ;
    USE SIGNAL ;
    PORT
      LAYER M4 ;
        RECT  21.516 31.824 21.6 31.848 ;
    END
  END b[16]
  PIN b[170]
    DIRECTION OUTPUT ;
    USE SIGNAL ;
    PORT
      LAYER M4 ;
        RECT  21.516 44.784 21.6 44.808 ;
    END
  END b[170]
  PIN b[171]
    DIRECTION OUTPUT ;
    USE SIGNAL ;
    PORT
      LAYER M4 ;
        RECT  21.516 44.928 21.6 44.952 ;
    END
  END b[171]
  PIN b[172]
    DIRECTION OUTPUT ;
    USE SIGNAL ;
    PORT
      LAYER M4 ;
        RECT  21.516 45.072 21.6 45.096 ;
    END
  END b[172]
  PIN b[173]
    DIRECTION OUTPUT ;
    USE SIGNAL ;
    PORT
      LAYER M4 ;
        RECT  21.516 45.216 21.6 45.24 ;
    END
  END b[173]
  PIN b[174]
    DIRECTION OUTPUT ;
    USE SIGNAL ;
    PORT
      LAYER M4 ;
        RECT  21.516 45.36 21.6 45.384 ;
    END
  END b[174]
  PIN b[175]
    DIRECTION OUTPUT ;
    USE SIGNAL ;
    PORT
      LAYER M4 ;
        RECT  21.516 45.504 21.6 45.528 ;
    END
  END b[175]
  PIN b[176]
    DIRECTION OUTPUT ;
    USE SIGNAL ;
    PORT
      LAYER M4 ;
        RECT  21.516 45.648 21.6 45.672 ;
    END
  END b[176]
  PIN b[177]
    DIRECTION OUTPUT ;
    USE SIGNAL ;
    PORT
      LAYER M4 ;
        RECT  21.516 45.792 21.6 45.816 ;
    END
  END b[177]
  PIN b[178]
    DIRECTION OUTPUT ;
    USE SIGNAL ;
    PORT
      LAYER M4 ;
        RECT  21.516 45.936 21.6 45.96 ;
    END
  END b[178]
  PIN b[179]
    DIRECTION OUTPUT ;
    USE SIGNAL ;
    PORT
      LAYER M4 ;
        RECT  21.516 46.08 21.6 46.104 ;
    END
  END b[179]
  PIN b[17]
    DIRECTION OUTPUT ;
    USE SIGNAL ;
    PORT
      LAYER M4 ;
        RECT  21.516 31.968 21.6 31.992 ;
    END
  END b[17]
  PIN b[180]
    DIRECTION OUTPUT ;
    USE SIGNAL ;
    PORT
      LAYER M4 ;
        RECT  21.516 46.224 21.6 46.248 ;
    END
  END b[180]
  PIN b[181]
    DIRECTION OUTPUT ;
    USE SIGNAL ;
    PORT
      LAYER M4 ;
        RECT  21.516 46.368 21.6 46.392 ;
    END
  END b[181]
  PIN b[182]
    DIRECTION OUTPUT ;
    USE SIGNAL ;
    PORT
      LAYER M4 ;
        RECT  21.516 46.512 21.6 46.536 ;
    END
  END b[182]
  PIN b[183]
    DIRECTION OUTPUT ;
    USE SIGNAL ;
    PORT
      LAYER M4 ;
        RECT  21.516 46.656 21.6 46.68 ;
    END
  END b[183]
  PIN b[184]
    DIRECTION OUTPUT ;
    USE SIGNAL ;
    PORT
      LAYER M4 ;
        RECT  21.516 46.8 21.6 46.824 ;
    END
  END b[184]
  PIN b[185]
    DIRECTION OUTPUT ;
    USE SIGNAL ;
    PORT
      LAYER M4 ;
        RECT  21.516 46.944 21.6 46.968 ;
    END
  END b[185]
  PIN b[186]
    DIRECTION OUTPUT ;
    USE SIGNAL ;
    PORT
      LAYER M4 ;
        RECT  21.516 47.088 21.6 47.112 ;
    END
  END b[186]
  PIN b[187]
    DIRECTION OUTPUT ;
    USE SIGNAL ;
    PORT
      LAYER M4 ;
        RECT  21.516 47.232 21.6 47.256 ;
    END
  END b[187]
  PIN b[188]
    DIRECTION OUTPUT ;
    USE SIGNAL ;
    PORT
      LAYER M4 ;
        RECT  21.516 47.376 21.6 47.4 ;
    END
  END b[188]
  PIN b[189]
    DIRECTION OUTPUT ;
    USE SIGNAL ;
    PORT
      LAYER M4 ;
        RECT  21.516 47.52 21.6 47.544 ;
    END
  END b[189]
  PIN b[18]
    DIRECTION OUTPUT ;
    USE SIGNAL ;
    PORT
      LAYER M4 ;
        RECT  21.516 32.112 21.6 32.136 ;
    END
  END b[18]
  PIN b[190]
    DIRECTION OUTPUT ;
    USE SIGNAL ;
    PORT
      LAYER M4 ;
        RECT  21.516 47.664 21.6 47.688 ;
    END
  END b[190]
  PIN b[191]
    DIRECTION OUTPUT ;
    USE SIGNAL ;
    PORT
      LAYER M4 ;
        RECT  21.516 47.808 21.6 47.832 ;
    END
  END b[191]
  PIN b[192]
    DIRECTION OUTPUT ;
    USE SIGNAL ;
    PORT
      LAYER M4 ;
        RECT  21.516 5.328 21.6 5.352 ;
    END
  END b[192]
  PIN b[193]
    DIRECTION OUTPUT ;
    USE SIGNAL ;
    PORT
      LAYER M4 ;
        RECT  21.516 5.472 21.6 5.496 ;
    END
  END b[193]
  PIN b[194]
    DIRECTION OUTPUT ;
    USE SIGNAL ;
    PORT
      LAYER M4 ;
        RECT  21.516 5.616 21.6 5.64 ;
    END
  END b[194]
  PIN b[195]
    DIRECTION OUTPUT ;
    USE SIGNAL ;
    PORT
      LAYER M4 ;
        RECT  21.516 5.76 21.6 5.784 ;
    END
  END b[195]
  PIN b[196]
    DIRECTION OUTPUT ;
    USE SIGNAL ;
    PORT
      LAYER M4 ;
        RECT  21.516 5.904 21.6 5.928 ;
    END
  END b[196]
  PIN b[197]
    DIRECTION OUTPUT ;
    USE SIGNAL ;
    PORT
      LAYER M4 ;
        RECT  21.516 6.048 21.6 6.072 ;
    END
  END b[197]
  PIN b[198]
    DIRECTION OUTPUT ;
    USE SIGNAL ;
    PORT
      LAYER M4 ;
        RECT  21.516 6.192 21.6 6.216 ;
    END
  END b[198]
  PIN b[199]
    DIRECTION OUTPUT ;
    USE SIGNAL ;
    PORT
      LAYER M4 ;
        RECT  21.516 6.336 21.6 6.36 ;
    END
  END b[199]
  PIN b[19]
    DIRECTION OUTPUT ;
    USE SIGNAL ;
    PORT
      LAYER M4 ;
        RECT  21.516 32.256 21.6 32.28 ;
    END
  END b[19]
  PIN b[1]
    DIRECTION OUTPUT ;
    USE SIGNAL ;
    PORT
      LAYER M4 ;
        RECT  21.516 29.664 21.6 29.688 ;
    END
  END b[1]
  PIN b[200]
    DIRECTION OUTPUT ;
    USE SIGNAL ;
    PORT
      LAYER M4 ;
        RECT  21.516 6.48 21.6 6.504 ;
    END
  END b[200]
  PIN b[201]
    DIRECTION OUTPUT ;
    USE SIGNAL ;
    PORT
      LAYER M4 ;
        RECT  21.516 6.624 21.6 6.648 ;
    END
  END b[201]
  PIN b[202]
    DIRECTION OUTPUT ;
    USE SIGNAL ;
    PORT
      LAYER M4 ;
        RECT  21.516 6.768 21.6 6.792 ;
    END
  END b[202]
  PIN b[203]
    DIRECTION OUTPUT ;
    USE SIGNAL ;
    PORT
      LAYER M4 ;
        RECT  21.516 6.912 21.6 6.936 ;
    END
  END b[203]
  PIN b[204]
    DIRECTION OUTPUT ;
    USE SIGNAL ;
    PORT
      LAYER M4 ;
        RECT  21.516 7.056 21.6 7.08 ;
    END
  END b[204]
  PIN b[205]
    DIRECTION OUTPUT ;
    USE SIGNAL ;
    PORT
      LAYER M4 ;
        RECT  21.516 7.2 21.6 7.224 ;
    END
  END b[205]
  PIN b[206]
    DIRECTION OUTPUT ;
    USE SIGNAL ;
    PORT
      LAYER M4 ;
        RECT  21.516 7.344 21.6 7.368 ;
    END
  END b[206]
  PIN b[207]
    DIRECTION OUTPUT ;
    USE SIGNAL ;
    PORT
      LAYER M4 ;
        RECT  21.516 7.488 21.6 7.512 ;
    END
  END b[207]
  PIN b[208]
    DIRECTION OUTPUT ;
    USE SIGNAL ;
    PORT
      LAYER M4 ;
        RECT  21.516 7.632 21.6 7.656 ;
    END
  END b[208]
  PIN b[209]
    DIRECTION OUTPUT ;
    USE SIGNAL ;
    PORT
      LAYER M4 ;
        RECT  21.516 7.776 21.6 7.8 ;
    END
  END b[209]
  PIN b[20]
    DIRECTION OUTPUT ;
    USE SIGNAL ;
    PORT
      LAYER M4 ;
        RECT  21.516 32.4 21.6 32.424 ;
    END
  END b[20]
  PIN b[210]
    DIRECTION OUTPUT ;
    USE SIGNAL ;
    PORT
      LAYER M4 ;
        RECT  21.516 7.92 21.6 7.944 ;
    END
  END b[210]
  PIN b[211]
    DIRECTION OUTPUT ;
    USE SIGNAL ;
    PORT
      LAYER M4 ;
        RECT  21.516 8.064 21.6 8.088 ;
    END
  END b[211]
  PIN b[212]
    DIRECTION OUTPUT ;
    USE SIGNAL ;
    PORT
      LAYER M4 ;
        RECT  21.516 8.208 21.6 8.232 ;
    END
  END b[212]
  PIN b[213]
    DIRECTION OUTPUT ;
    USE SIGNAL ;
    PORT
      LAYER M4 ;
        RECT  21.516 8.352 21.6 8.376 ;
    END
  END b[213]
  PIN b[214]
    DIRECTION OUTPUT ;
    USE SIGNAL ;
    PORT
      LAYER M4 ;
        RECT  21.516 8.496 21.6 8.52 ;
    END
  END b[214]
  PIN b[215]
    DIRECTION OUTPUT ;
    USE SIGNAL ;
    PORT
      LAYER M4 ;
        RECT  21.516 8.64 21.6 8.664 ;
    END
  END b[215]
  PIN b[216]
    DIRECTION OUTPUT ;
    USE SIGNAL ;
    PORT
      LAYER M4 ;
        RECT  21.516 8.784 21.6 8.808 ;
    END
  END b[216]
  PIN b[217]
    DIRECTION OUTPUT ;
    USE SIGNAL ;
    PORT
      LAYER M4 ;
        RECT  21.516 8.928 21.6 8.952 ;
    END
  END b[217]
  PIN b[218]
    DIRECTION OUTPUT ;
    USE SIGNAL ;
    PORT
      LAYER M4 ;
        RECT  21.516 9.072 21.6 9.096 ;
    END
  END b[218]
  PIN b[219]
    DIRECTION OUTPUT ;
    USE SIGNAL ;
    PORT
      LAYER M4 ;
        RECT  21.516 9.216 21.6 9.24 ;
    END
  END b[219]
  PIN b[21]
    DIRECTION OUTPUT ;
    USE SIGNAL ;
    PORT
      LAYER M4 ;
        RECT  21.516 32.544 21.6 32.568 ;
    END
  END b[21]
  PIN b[220]
    DIRECTION OUTPUT ;
    USE SIGNAL ;
    PORT
      LAYER M4 ;
        RECT  21.516 9.36 21.6 9.384 ;
    END
  END b[220]
  PIN b[221]
    DIRECTION OUTPUT ;
    USE SIGNAL ;
    PORT
      LAYER M4 ;
        RECT  21.516 9.504 21.6 9.528 ;
    END
  END b[221]
  PIN b[222]
    DIRECTION OUTPUT ;
    USE SIGNAL ;
    PORT
      LAYER M4 ;
        RECT  21.516 9.648 21.6 9.672 ;
    END
  END b[222]
  PIN b[223]
    DIRECTION OUTPUT ;
    USE SIGNAL ;
    PORT
      LAYER M4 ;
        RECT  21.516 9.792 21.6 9.816 ;
    END
  END b[223]
  PIN b[224]
    DIRECTION OUTPUT ;
    USE SIGNAL ;
    PORT
      LAYER M4 ;
        RECT  21.516 19.152 21.6 19.176 ;
    END
  END b[224]
  PIN b[225]
    DIRECTION OUTPUT ;
    USE SIGNAL ;
    PORT
      LAYER M4 ;
        RECT  21.516 19.296 21.6 19.32 ;
    END
  END b[225]
  PIN b[226]
    DIRECTION OUTPUT ;
    USE SIGNAL ;
    PORT
      LAYER M4 ;
        RECT  21.516 19.44 21.6 19.464 ;
    END
  END b[226]
  PIN b[227]
    DIRECTION OUTPUT ;
    USE SIGNAL ;
    PORT
      LAYER M4 ;
        RECT  21.516 19.584 21.6 19.608 ;
    END
  END b[227]
  PIN b[228]
    DIRECTION OUTPUT ;
    USE SIGNAL ;
    PORT
      LAYER M4 ;
        RECT  21.516 19.728 21.6 19.752 ;
    END
  END b[228]
  PIN b[229]
    DIRECTION OUTPUT ;
    USE SIGNAL ;
    PORT
      LAYER M4 ;
        RECT  21.516 19.872 21.6 19.896 ;
    END
  END b[229]
  PIN b[22]
    DIRECTION OUTPUT ;
    USE SIGNAL ;
    PORT
      LAYER M4 ;
        RECT  21.516 32.688 21.6 32.712 ;
    END
  END b[22]
  PIN b[230]
    DIRECTION OUTPUT ;
    USE SIGNAL ;
    PORT
      LAYER M4 ;
        RECT  21.516 20.016 21.6 20.04 ;
    END
  END b[230]
  PIN b[231]
    DIRECTION OUTPUT ;
    USE SIGNAL ;
    PORT
      LAYER M4 ;
        RECT  21.516 20.16 21.6 20.184 ;
    END
  END b[231]
  PIN b[232]
    DIRECTION OUTPUT ;
    USE SIGNAL ;
    PORT
      LAYER M4 ;
        RECT  21.516 20.304 21.6 20.328 ;
    END
  END b[232]
  PIN b[233]
    DIRECTION OUTPUT ;
    USE SIGNAL ;
    PORT
      LAYER M4 ;
        RECT  21.516 20.448 21.6 20.472 ;
    END
  END b[233]
  PIN b[234]
    DIRECTION OUTPUT ;
    USE SIGNAL ;
    PORT
      LAYER M4 ;
        RECT  21.516 20.592 21.6 20.616 ;
    END
  END b[234]
  PIN b[235]
    DIRECTION OUTPUT ;
    USE SIGNAL ;
    PORT
      LAYER M4 ;
        RECT  21.516 20.736 21.6 20.76 ;
    END
  END b[235]
  PIN b[236]
    DIRECTION OUTPUT ;
    USE SIGNAL ;
    PORT
      LAYER M4 ;
        RECT  21.516 20.88 21.6 20.904 ;
    END
  END b[236]
  PIN b[237]
    DIRECTION OUTPUT ;
    USE SIGNAL ;
    PORT
      LAYER M4 ;
        RECT  21.516 21.024 21.6 21.048 ;
    END
  END b[237]
  PIN b[238]
    DIRECTION OUTPUT ;
    USE SIGNAL ;
    PORT
      LAYER M4 ;
        RECT  21.516 21.168 21.6 21.192 ;
    END
  END b[238]
  PIN b[239]
    DIRECTION OUTPUT ;
    USE SIGNAL ;
    PORT
      LAYER M4 ;
        RECT  21.516 21.312 21.6 21.336 ;
    END
  END b[239]
  PIN b[23]
    DIRECTION OUTPUT ;
    USE SIGNAL ;
    PORT
      LAYER M4 ;
        RECT  21.516 32.832 21.6 32.856 ;
    END
  END b[23]
  PIN b[240]
    DIRECTION OUTPUT ;
    USE SIGNAL ;
    PORT
      LAYER M4 ;
        RECT  21.516 21.456 21.6 21.48 ;
    END
  END b[240]
  PIN b[241]
    DIRECTION OUTPUT ;
    USE SIGNAL ;
    PORT
      LAYER M4 ;
        RECT  21.516 21.6 21.6 21.624 ;
    END
  END b[241]
  PIN b[242]
    DIRECTION OUTPUT ;
    USE SIGNAL ;
    PORT
      LAYER M4 ;
        RECT  21.516 21.744 21.6 21.768 ;
    END
  END b[242]
  PIN b[243]
    DIRECTION OUTPUT ;
    USE SIGNAL ;
    PORT
      LAYER M4 ;
        RECT  21.516 21.888 21.6 21.912 ;
    END
  END b[243]
  PIN b[244]
    DIRECTION OUTPUT ;
    USE SIGNAL ;
    PORT
      LAYER M4 ;
        RECT  21.516 22.032 21.6 22.056 ;
    END
  END b[244]
  PIN b[245]
    DIRECTION OUTPUT ;
    USE SIGNAL ;
    PORT
      LAYER M4 ;
        RECT  21.516 22.176 21.6 22.2 ;
    END
  END b[245]
  PIN b[246]
    DIRECTION OUTPUT ;
    USE SIGNAL ;
    PORT
      LAYER M4 ;
        RECT  21.516 22.32 21.6 22.344 ;
    END
  END b[246]
  PIN b[247]
    DIRECTION OUTPUT ;
    USE SIGNAL ;
    PORT
      LAYER M4 ;
        RECT  21.516 22.464 21.6 22.488 ;
    END
  END b[247]
  PIN b[248]
    DIRECTION OUTPUT ;
    USE SIGNAL ;
    PORT
      LAYER M4 ;
        RECT  21.516 22.608 21.6 22.632 ;
    END
  END b[248]
  PIN b[249]
    DIRECTION OUTPUT ;
    USE SIGNAL ;
    PORT
      LAYER M4 ;
        RECT  21.516 22.752 21.6 22.776 ;
    END
  END b[249]
  PIN b[24]
    DIRECTION OUTPUT ;
    USE SIGNAL ;
    PORT
      LAYER M4 ;
        RECT  21.516 32.976 21.6 33 ;
    END
  END b[24]
  PIN b[250]
    DIRECTION OUTPUT ;
    USE SIGNAL ;
    PORT
      LAYER M4 ;
        RECT  21.516 22.896 21.6 22.92 ;
    END
  END b[250]
  PIN b[251]
    DIRECTION OUTPUT ;
    USE SIGNAL ;
    PORT
      LAYER M4 ;
        RECT  21.516 23.04 21.6 23.064 ;
    END
  END b[251]
  PIN b[252]
    DIRECTION OUTPUT ;
    USE SIGNAL ;
    PORT
      LAYER M4 ;
        RECT  21.516 23.184 21.6 23.208 ;
    END
  END b[252]
  PIN b[253]
    DIRECTION OUTPUT ;
    USE SIGNAL ;
    PORT
      LAYER M4 ;
        RECT  21.516 23.328 21.6 23.352 ;
    END
  END b[253]
  PIN b[254]
    DIRECTION OUTPUT ;
    USE SIGNAL ;
    PORT
      LAYER M4 ;
        RECT  21.516 23.472 21.6 23.496 ;
    END
  END b[254]
  PIN b[255]
    DIRECTION OUTPUT ;
    USE SIGNAL ;
    PORT
      LAYER M4 ;
        RECT  21.516 23.616 21.6 23.64 ;
    END
  END b[255]
  PIN b[256]
    DIRECTION OUTPUT ;
    USE SIGNAL ;
    PORT
      LAYER M4 ;
        RECT  21.516 9.936 21.6 9.96 ;
    END
  END b[256]
  PIN b[257]
    DIRECTION OUTPUT ;
    USE SIGNAL ;
    PORT
      LAYER M4 ;
        RECT  21.516 10.08 21.6 10.104 ;
    END
  END b[257]
  PIN b[258]
    DIRECTION OUTPUT ;
    USE SIGNAL ;
    PORT
      LAYER M4 ;
        RECT  21.516 10.224 21.6 10.248 ;
    END
  END b[258]
  PIN b[259]
    DIRECTION OUTPUT ;
    USE SIGNAL ;
    PORT
      LAYER M4 ;
        RECT  21.516 10.368 21.6 10.392 ;
    END
  END b[259]
  PIN b[25]
    DIRECTION OUTPUT ;
    USE SIGNAL ;
    PORT
      LAYER M4 ;
        RECT  21.516 33.12 21.6 33.144 ;
    END
  END b[25]
  PIN b[260]
    DIRECTION OUTPUT ;
    USE SIGNAL ;
    PORT
      LAYER M4 ;
        RECT  21.516 10.512 21.6 10.536 ;
    END
  END b[260]
  PIN b[261]
    DIRECTION OUTPUT ;
    USE SIGNAL ;
    PORT
      LAYER M4 ;
        RECT  21.516 10.656 21.6 10.68 ;
    END
  END b[261]
  PIN b[262]
    DIRECTION OUTPUT ;
    USE SIGNAL ;
    PORT
      LAYER M4 ;
        RECT  21.516 10.8 21.6 10.824 ;
    END
  END b[262]
  PIN b[263]
    DIRECTION OUTPUT ;
    USE SIGNAL ;
    PORT
      LAYER M4 ;
        RECT  21.516 10.944 21.6 10.968 ;
    END
  END b[263]
  PIN b[264]
    DIRECTION OUTPUT ;
    USE SIGNAL ;
    PORT
      LAYER M4 ;
        RECT  21.516 11.088 21.6 11.112 ;
    END
  END b[264]
  PIN b[265]
    DIRECTION OUTPUT ;
    USE SIGNAL ;
    PORT
      LAYER M4 ;
        RECT  21.516 11.232 21.6 11.256 ;
    END
  END b[265]
  PIN b[266]
    DIRECTION OUTPUT ;
    USE SIGNAL ;
    PORT
      LAYER M4 ;
        RECT  21.516 11.376 21.6 11.4 ;
    END
  END b[266]
  PIN b[267]
    DIRECTION OUTPUT ;
    USE SIGNAL ;
    PORT
      LAYER M4 ;
        RECT  21.516 11.52 21.6 11.544 ;
    END
  END b[267]
  PIN b[268]
    DIRECTION OUTPUT ;
    USE SIGNAL ;
    PORT
      LAYER M4 ;
        RECT  21.516 11.664 21.6 11.688 ;
    END
  END b[268]
  PIN b[269]
    DIRECTION OUTPUT ;
    USE SIGNAL ;
    PORT
      LAYER M4 ;
        RECT  21.516 11.808 21.6 11.832 ;
    END
  END b[269]
  PIN b[26]
    DIRECTION OUTPUT ;
    USE SIGNAL ;
    PORT
      LAYER M4 ;
        RECT  21.516 33.264 21.6 33.288 ;
    END
  END b[26]
  PIN b[270]
    DIRECTION OUTPUT ;
    USE SIGNAL ;
    PORT
      LAYER M4 ;
        RECT  21.516 11.952 21.6 11.976 ;
    END
  END b[270]
  PIN b[271]
    DIRECTION OUTPUT ;
    USE SIGNAL ;
    PORT
      LAYER M4 ;
        RECT  21.516 12.096 21.6 12.12 ;
    END
  END b[271]
  PIN b[272]
    DIRECTION OUTPUT ;
    USE SIGNAL ;
    PORT
      LAYER M4 ;
        RECT  21.516 12.24 21.6 12.264 ;
    END
  END b[272]
  PIN b[273]
    DIRECTION OUTPUT ;
    USE SIGNAL ;
    PORT
      LAYER M4 ;
        RECT  21.516 12.384 21.6 12.408 ;
    END
  END b[273]
  PIN b[274]
    DIRECTION OUTPUT ;
    USE SIGNAL ;
    PORT
      LAYER M4 ;
        RECT  21.516 12.528 21.6 12.552 ;
    END
  END b[274]
  PIN b[275]
    DIRECTION OUTPUT ;
    USE SIGNAL ;
    PORT
      LAYER M4 ;
        RECT  21.516 12.672 21.6 12.696 ;
    END
  END b[275]
  PIN b[276]
    DIRECTION OUTPUT ;
    USE SIGNAL ;
    PORT
      LAYER M4 ;
        RECT  21.516 12.816 21.6 12.84 ;
    END
  END b[276]
  PIN b[277]
    DIRECTION OUTPUT ;
    USE SIGNAL ;
    PORT
      LAYER M4 ;
        RECT  21.516 12.96 21.6 12.984 ;
    END
  END b[277]
  PIN b[278]
    DIRECTION OUTPUT ;
    USE SIGNAL ;
    PORT
      LAYER M4 ;
        RECT  21.516 13.104 21.6 13.128 ;
    END
  END b[278]
  PIN b[279]
    DIRECTION OUTPUT ;
    USE SIGNAL ;
    PORT
      LAYER M4 ;
        RECT  21.516 13.248 21.6 13.272 ;
    END
  END b[279]
  PIN b[27]
    DIRECTION OUTPUT ;
    USE SIGNAL ;
    PORT
      LAYER M4 ;
        RECT  21.516 33.408 21.6 33.432 ;
    END
  END b[27]
  PIN b[280]
    DIRECTION OUTPUT ;
    USE SIGNAL ;
    PORT
      LAYER M4 ;
        RECT  21.516 13.392 21.6 13.416 ;
    END
  END b[280]
  PIN b[281]
    DIRECTION OUTPUT ;
    USE SIGNAL ;
    PORT
      LAYER M4 ;
        RECT  21.516 13.536 21.6 13.56 ;
    END
  END b[281]
  PIN b[282]
    DIRECTION OUTPUT ;
    USE SIGNAL ;
    PORT
      LAYER M4 ;
        RECT  21.516 13.68 21.6 13.704 ;
    END
  END b[282]
  PIN b[283]
    DIRECTION OUTPUT ;
    USE SIGNAL ;
    PORT
      LAYER M4 ;
        RECT  21.516 13.824 21.6 13.848 ;
    END
  END b[283]
  PIN b[284]
    DIRECTION OUTPUT ;
    USE SIGNAL ;
    PORT
      LAYER M4 ;
        RECT  21.516 13.968 21.6 13.992 ;
    END
  END b[284]
  PIN b[285]
    DIRECTION OUTPUT ;
    USE SIGNAL ;
    PORT
      LAYER M4 ;
        RECT  21.516 14.112 21.6 14.136 ;
    END
  END b[285]
  PIN b[286]
    DIRECTION OUTPUT ;
    USE SIGNAL ;
    PORT
      LAYER M4 ;
        RECT  21.516 14.256 21.6 14.28 ;
    END
  END b[286]
  PIN b[287]
    DIRECTION OUTPUT ;
    USE SIGNAL ;
    PORT
      LAYER M4 ;
        RECT  21.516 14.4 21.6 14.424 ;
    END
  END b[287]
  PIN b[288]
    DIRECTION OUTPUT ;
    USE SIGNAL ;
    PORT
      LAYER M4 ;
        RECT  21.516 14.544 21.6 14.568 ;
    END
  END b[288]
  PIN b[289]
    DIRECTION OUTPUT ;
    USE SIGNAL ;
    PORT
      LAYER M4 ;
        RECT  21.516 14.688 21.6 14.712 ;
    END
  END b[289]
  PIN b[28]
    DIRECTION OUTPUT ;
    USE SIGNAL ;
    PORT
      LAYER M4 ;
        RECT  21.516 33.552 21.6 33.576 ;
    END
  END b[28]
  PIN b[290]
    DIRECTION OUTPUT ;
    USE SIGNAL ;
    PORT
      LAYER M4 ;
        RECT  21.516 14.832 21.6 14.856 ;
    END
  END b[290]
  PIN b[291]
    DIRECTION OUTPUT ;
    USE SIGNAL ;
    PORT
      LAYER M4 ;
        RECT  21.516 14.976 21.6 15 ;
    END
  END b[291]
  PIN b[292]
    DIRECTION OUTPUT ;
    USE SIGNAL ;
    PORT
      LAYER M4 ;
        RECT  21.516 15.12 21.6 15.144 ;
    END
  END b[292]
  PIN b[293]
    DIRECTION OUTPUT ;
    USE SIGNAL ;
    PORT
      LAYER M4 ;
        RECT  21.516 15.264 21.6 15.288 ;
    END
  END b[293]
  PIN b[294]
    DIRECTION OUTPUT ;
    USE SIGNAL ;
    PORT
      LAYER M4 ;
        RECT  21.516 15.408 21.6 15.432 ;
    END
  END b[294]
  PIN b[295]
    DIRECTION OUTPUT ;
    USE SIGNAL ;
    PORT
      LAYER M4 ;
        RECT  21.516 15.552 21.6 15.576 ;
    END
  END b[295]
  PIN b[296]
    DIRECTION OUTPUT ;
    USE SIGNAL ;
    PORT
      LAYER M4 ;
        RECT  21.516 15.696 21.6 15.72 ;
    END
  END b[296]
  PIN b[297]
    DIRECTION OUTPUT ;
    USE SIGNAL ;
    PORT
      LAYER M4 ;
        RECT  21.516 15.84 21.6 15.864 ;
    END
  END b[297]
  PIN b[298]
    DIRECTION OUTPUT ;
    USE SIGNAL ;
    PORT
      LAYER M4 ;
        RECT  21.516 15.984 21.6 16.008 ;
    END
  END b[298]
  PIN b[299]
    DIRECTION OUTPUT ;
    USE SIGNAL ;
    PORT
      LAYER M4 ;
        RECT  21.516 16.128 21.6 16.152 ;
    END
  END b[299]
  PIN b[29]
    DIRECTION OUTPUT ;
    USE SIGNAL ;
    PORT
      LAYER M4 ;
        RECT  21.516 33.696 21.6 33.72 ;
    END
  END b[29]
  PIN b[2]
    DIRECTION OUTPUT ;
    USE SIGNAL ;
    PORT
      LAYER M4 ;
        RECT  21.516 29.808 21.6 29.832 ;
    END
  END b[2]
  PIN b[300]
    DIRECTION OUTPUT ;
    USE SIGNAL ;
    PORT
      LAYER M4 ;
        RECT  21.516 16.272 21.6 16.296 ;
    END
  END b[300]
  PIN b[301]
    DIRECTION OUTPUT ;
    USE SIGNAL ;
    PORT
      LAYER M4 ;
        RECT  21.516 16.416 21.6 16.44 ;
    END
  END b[301]
  PIN b[302]
    DIRECTION OUTPUT ;
    USE SIGNAL ;
    PORT
      LAYER M4 ;
        RECT  21.516 16.56 21.6 16.584 ;
    END
  END b[302]
  PIN b[303]
    DIRECTION OUTPUT ;
    USE SIGNAL ;
    PORT
      LAYER M4 ;
        RECT  21.516 16.704 21.6 16.728 ;
    END
  END b[303]
  PIN b[304]
    DIRECTION OUTPUT ;
    USE SIGNAL ;
    PORT
      LAYER M4 ;
        RECT  21.516 16.848 21.6 16.872 ;
    END
  END b[304]
  PIN b[305]
    DIRECTION OUTPUT ;
    USE SIGNAL ;
    PORT
      LAYER M4 ;
        RECT  21.516 16.992 21.6 17.016 ;
    END
  END b[305]
  PIN b[306]
    DIRECTION OUTPUT ;
    USE SIGNAL ;
    PORT
      LAYER M4 ;
        RECT  21.516 17.136 21.6 17.16 ;
    END
  END b[306]
  PIN b[307]
    DIRECTION OUTPUT ;
    USE SIGNAL ;
    PORT
      LAYER M4 ;
        RECT  21.516 17.28 21.6 17.304 ;
    END
  END b[307]
  PIN b[308]
    DIRECTION OUTPUT ;
    USE SIGNAL ;
    PORT
      LAYER M4 ;
        RECT  21.516 17.424 21.6 17.448 ;
    END
  END b[308]
  PIN b[309]
    DIRECTION OUTPUT ;
    USE SIGNAL ;
    PORT
      LAYER M4 ;
        RECT  21.516 17.568 21.6 17.592 ;
    END
  END b[309]
  PIN b[30]
    DIRECTION OUTPUT ;
    USE SIGNAL ;
    PORT
      LAYER M4 ;
        RECT  21.516 33.84 21.6 33.864 ;
    END
  END b[30]
  PIN b[310]
    DIRECTION OUTPUT ;
    USE SIGNAL ;
    PORT
      LAYER M4 ;
        RECT  21.516 17.712 21.6 17.736 ;
    END
  END b[310]
  PIN b[311]
    DIRECTION OUTPUT ;
    USE SIGNAL ;
    PORT
      LAYER M4 ;
        RECT  21.516 17.856 21.6 17.88 ;
    END
  END b[311]
  PIN b[312]
    DIRECTION OUTPUT ;
    USE SIGNAL ;
    PORT
      LAYER M4 ;
        RECT  21.516 18 21.6 18.024 ;
    END
  END b[312]
  PIN b[313]
    DIRECTION OUTPUT ;
    USE SIGNAL ;
    PORT
      LAYER M4 ;
        RECT  21.516 18.144 21.6 18.168 ;
    END
  END b[313]
  PIN b[314]
    DIRECTION OUTPUT ;
    USE SIGNAL ;
    PORT
      LAYER M4 ;
        RECT  21.516 18.288 21.6 18.312 ;
    END
  END b[314]
  PIN b[315]
    DIRECTION OUTPUT ;
    USE SIGNAL ;
    PORT
      LAYER M4 ;
        RECT  21.516 18.432 21.6 18.456 ;
    END
  END b[315]
  PIN b[316]
    DIRECTION OUTPUT ;
    USE SIGNAL ;
    PORT
      LAYER M4 ;
        RECT  21.516 18.576 21.6 18.6 ;
    END
  END b[316]
  PIN b[317]
    DIRECTION OUTPUT ;
    USE SIGNAL ;
    PORT
      LAYER M4 ;
        RECT  21.516 18.72 21.6 18.744 ;
    END
  END b[317]
  PIN b[318]
    DIRECTION OUTPUT ;
    USE SIGNAL ;
    PORT
      LAYER M4 ;
        RECT  21.516 18.864 21.6 18.888 ;
    END
  END b[318]
  PIN b[319]
    DIRECTION OUTPUT ;
    USE SIGNAL ;
    PORT
      LAYER M4 ;
        RECT  21.516 19.008 21.6 19.032 ;
    END
  END b[319]
  PIN b[31]
    DIRECTION OUTPUT ;
    USE SIGNAL ;
    PORT
      LAYER M4 ;
        RECT  21.516 33.984 21.6 34.008 ;
    END
  END b[31]
  PIN b[320]
    DIRECTION OUTPUT ;
    USE SIGNAL ;
    PORT
      LAYER M4 ;
        RECT  21.516 23.76 21.6 23.784 ;
    END
  END b[320]
  PIN b[321]
    DIRECTION OUTPUT ;
    USE SIGNAL ;
    PORT
      LAYER M4 ;
        RECT  21.516 23.904 21.6 23.928 ;
    END
  END b[321]
  PIN b[322]
    DIRECTION OUTPUT ;
    USE SIGNAL ;
    PORT
      LAYER M4 ;
        RECT  21.516 24.048 21.6 24.072 ;
    END
  END b[322]
  PIN b[323]
    DIRECTION OUTPUT ;
    USE SIGNAL ;
    PORT
      LAYER M4 ;
        RECT  21.516 24.192 21.6 24.216 ;
    END
  END b[323]
  PIN b[324]
    DIRECTION OUTPUT ;
    USE SIGNAL ;
    PORT
      LAYER M4 ;
        RECT  21.516 24.336 21.6 24.36 ;
    END
  END b[324]
  PIN b[325]
    DIRECTION OUTPUT ;
    USE SIGNAL ;
    PORT
      LAYER M4 ;
        RECT  21.516 24.48 21.6 24.504 ;
    END
  END b[325]
  PIN b[326]
    DIRECTION OUTPUT ;
    USE SIGNAL ;
    PORT
      LAYER M4 ;
        RECT  21.516 24.624 21.6 24.648 ;
    END
  END b[326]
  PIN b[327]
    DIRECTION OUTPUT ;
    USE SIGNAL ;
    PORT
      LAYER M4 ;
        RECT  21.516 24.768 21.6 24.792 ;
    END
  END b[327]
  PIN b[328]
    DIRECTION OUTPUT ;
    USE SIGNAL ;
    PORT
      LAYER M4 ;
        RECT  21.516 24.912 21.6 24.936 ;
    END
  END b[328]
  PIN b[329]
    DIRECTION OUTPUT ;
    USE SIGNAL ;
    PORT
      LAYER M4 ;
        RECT  21.516 25.056 21.6 25.08 ;
    END
  END b[329]
  PIN b[32]
    DIRECTION OUTPUT ;
    USE SIGNAL ;
    PORT
      LAYER M4 ;
        RECT  21.516 38.736 21.6 38.76 ;
    END
  END b[32]
  PIN b[330]
    DIRECTION OUTPUT ;
    USE SIGNAL ;
    PORT
      LAYER M4 ;
        RECT  21.516 25.2 21.6 25.224 ;
    END
  END b[330]
  PIN b[331]
    DIRECTION OUTPUT ;
    USE SIGNAL ;
    PORT
      LAYER M4 ;
        RECT  21.516 25.344 21.6 25.368 ;
    END
  END b[331]
  PIN b[332]
    DIRECTION OUTPUT ;
    USE SIGNAL ;
    PORT
      LAYER M4 ;
        RECT  21.516 25.488 21.6 25.512 ;
    END
  END b[332]
  PIN b[333]
    DIRECTION OUTPUT ;
    USE SIGNAL ;
    PORT
      LAYER M4 ;
        RECT  21.516 25.632 21.6 25.656 ;
    END
  END b[333]
  PIN b[334]
    DIRECTION OUTPUT ;
    USE SIGNAL ;
    PORT
      LAYER M4 ;
        RECT  21.516 25.776 21.6 25.8 ;
    END
  END b[334]
  PIN b[335]
    DIRECTION OUTPUT ;
    USE SIGNAL ;
    PORT
      LAYER M4 ;
        RECT  21.516 25.92 21.6 25.944 ;
    END
  END b[335]
  PIN b[336]
    DIRECTION OUTPUT ;
    USE SIGNAL ;
    PORT
      LAYER M4 ;
        RECT  21.516 26.064 21.6 26.088 ;
    END
  END b[336]
  PIN b[337]
    DIRECTION OUTPUT ;
    USE SIGNAL ;
    PORT
      LAYER M4 ;
        RECT  21.516 26.208 21.6 26.232 ;
    END
  END b[337]
  PIN b[338]
    DIRECTION OUTPUT ;
    USE SIGNAL ;
    PORT
      LAYER M4 ;
        RECT  21.516 26.352 21.6 26.376 ;
    END
  END b[338]
  PIN b[339]
    DIRECTION OUTPUT ;
    USE SIGNAL ;
    PORT
      LAYER M4 ;
        RECT  21.516 26.496 21.6 26.52 ;
    END
  END b[339]
  PIN b[33]
    DIRECTION OUTPUT ;
    USE SIGNAL ;
    PORT
      LAYER M4 ;
        RECT  21.516 38.88 21.6 38.904 ;
    END
  END b[33]
  PIN b[340]
    DIRECTION OUTPUT ;
    USE SIGNAL ;
    PORT
      LAYER M4 ;
        RECT  21.516 26.64 21.6 26.664 ;
    END
  END b[340]
  PIN b[341]
    DIRECTION OUTPUT ;
    USE SIGNAL ;
    PORT
      LAYER M4 ;
        RECT  21.516 26.784 21.6 26.808 ;
    END
  END b[341]
  PIN b[342]
    DIRECTION OUTPUT ;
    USE SIGNAL ;
    PORT
      LAYER M4 ;
        RECT  21.516 26.928 21.6 26.952 ;
    END
  END b[342]
  PIN b[343]
    DIRECTION OUTPUT ;
    USE SIGNAL ;
    PORT
      LAYER M4 ;
        RECT  21.516 27.072 21.6 27.096 ;
    END
  END b[343]
  PIN b[344]
    DIRECTION OUTPUT ;
    USE SIGNAL ;
    PORT
      LAYER M4 ;
        RECT  21.516 27.216 21.6 27.24 ;
    END
  END b[344]
  PIN b[345]
    DIRECTION OUTPUT ;
    USE SIGNAL ;
    PORT
      LAYER M4 ;
        RECT  21.516 27.36 21.6 27.384 ;
    END
  END b[345]
  PIN b[346]
    DIRECTION OUTPUT ;
    USE SIGNAL ;
    PORT
      LAYER M4 ;
        RECT  21.516 27.504 21.6 27.528 ;
    END
  END b[346]
  PIN b[347]
    DIRECTION OUTPUT ;
    USE SIGNAL ;
    PORT
      LAYER M4 ;
        RECT  21.516 27.648 21.6 27.672 ;
    END
  END b[347]
  PIN b[348]
    DIRECTION OUTPUT ;
    USE SIGNAL ;
    PORT
      LAYER M4 ;
        RECT  21.516 27.792 21.6 27.816 ;
    END
  END b[348]
  PIN b[349]
    DIRECTION OUTPUT ;
    USE SIGNAL ;
    PORT
      LAYER M4 ;
        RECT  21.516 27.936 21.6 27.96 ;
    END
  END b[349]
  PIN b[34]
    DIRECTION OUTPUT ;
    USE SIGNAL ;
    PORT
      LAYER M4 ;
        RECT  21.516 39.024 21.6 39.048 ;
    END
  END b[34]
  PIN b[350]
    DIRECTION OUTPUT ;
    USE SIGNAL ;
    PORT
      LAYER M4 ;
        RECT  21.516 28.08 21.6 28.104 ;
    END
  END b[350]
  PIN b[351]
    DIRECTION OUTPUT ;
    USE SIGNAL ;
    PORT
      LAYER M4 ;
        RECT  21.516 28.224 21.6 28.248 ;
    END
  END b[351]
  PIN b[352]
    DIRECTION OUTPUT ;
    USE SIGNAL ;
    PORT
      LAYER M4 ;
        RECT  21.516 0.72 21.6 0.744 ;
    END
  END b[352]
  PIN b[353]
    DIRECTION OUTPUT ;
    USE SIGNAL ;
    PORT
      LAYER M4 ;
        RECT  21.516 0.864 21.6 0.888 ;
    END
  END b[353]
  PIN b[354]
    DIRECTION OUTPUT ;
    USE SIGNAL ;
    PORT
      LAYER M4 ;
        RECT  21.516 1.008 21.6 1.032 ;
    END
  END b[354]
  PIN b[355]
    DIRECTION OUTPUT ;
    USE SIGNAL ;
    PORT
      LAYER M4 ;
        RECT  21.516 1.152 21.6 1.176 ;
    END
  END b[355]
  PIN b[356]
    DIRECTION OUTPUT ;
    USE SIGNAL ;
    PORT
      LAYER M4 ;
        RECT  21.516 1.296 21.6 1.32 ;
    END
  END b[356]
  PIN b[357]
    DIRECTION OUTPUT ;
    USE SIGNAL ;
    PORT
      LAYER M4 ;
        RECT  21.516 1.44 21.6 1.464 ;
    END
  END b[357]
  PIN b[358]
    DIRECTION OUTPUT ;
    USE SIGNAL ;
    PORT
      LAYER M4 ;
        RECT  21.516 1.584 21.6 1.608 ;
    END
  END b[358]
  PIN b[359]
    DIRECTION OUTPUT ;
    USE SIGNAL ;
    PORT
      LAYER M4 ;
        RECT  21.516 1.728 21.6 1.752 ;
    END
  END b[359]
  PIN b[35]
    DIRECTION OUTPUT ;
    USE SIGNAL ;
    PORT
      LAYER M4 ;
        RECT  21.516 39.168 21.6 39.192 ;
    END
  END b[35]
  PIN b[360]
    DIRECTION OUTPUT ;
    USE SIGNAL ;
    PORT
      LAYER M4 ;
        RECT  21.516 1.872 21.6 1.896 ;
    END
  END b[360]
  PIN b[361]
    DIRECTION OUTPUT ;
    USE SIGNAL ;
    PORT
      LAYER M4 ;
        RECT  21.516 2.016 21.6 2.04 ;
    END
  END b[361]
  PIN b[362]
    DIRECTION OUTPUT ;
    USE SIGNAL ;
    PORT
      LAYER M4 ;
        RECT  21.516 2.16 21.6 2.184 ;
    END
  END b[362]
  PIN b[363]
    DIRECTION OUTPUT ;
    USE SIGNAL ;
    PORT
      LAYER M4 ;
        RECT  21.516 2.304 21.6 2.328 ;
    END
  END b[363]
  PIN b[364]
    DIRECTION OUTPUT ;
    USE SIGNAL ;
    PORT
      LAYER M4 ;
        RECT  21.516 2.448 21.6 2.472 ;
    END
  END b[364]
  PIN b[365]
    DIRECTION OUTPUT ;
    USE SIGNAL ;
    PORT
      LAYER M4 ;
        RECT  21.516 2.592 21.6 2.616 ;
    END
  END b[365]
  PIN b[366]
    DIRECTION OUTPUT ;
    USE SIGNAL ;
    PORT
      LAYER M4 ;
        RECT  21.516 2.736 21.6 2.76 ;
    END
  END b[366]
  PIN b[367]
    DIRECTION OUTPUT ;
    USE SIGNAL ;
    PORT
      LAYER M4 ;
        RECT  21.516 2.88 21.6 2.904 ;
    END
  END b[367]
  PIN b[368]
    DIRECTION OUTPUT ;
    USE SIGNAL ;
    PORT
      LAYER M4 ;
        RECT  21.516 3.024 21.6 3.048 ;
    END
  END b[368]
  PIN b[369]
    DIRECTION OUTPUT ;
    USE SIGNAL ;
    PORT
      LAYER M4 ;
        RECT  21.516 3.168 21.6 3.192 ;
    END
  END b[369]
  PIN b[36]
    DIRECTION OUTPUT ;
    USE SIGNAL ;
    PORT
      LAYER M4 ;
        RECT  21.516 39.312 21.6 39.336 ;
    END
  END b[36]
  PIN b[370]
    DIRECTION OUTPUT ;
    USE SIGNAL ;
    PORT
      LAYER M4 ;
        RECT  21.516 3.312 21.6 3.336 ;
    END
  END b[370]
  PIN b[371]
    DIRECTION OUTPUT ;
    USE SIGNAL ;
    PORT
      LAYER M4 ;
        RECT  21.516 3.456 21.6 3.48 ;
    END
  END b[371]
  PIN b[372]
    DIRECTION OUTPUT ;
    USE SIGNAL ;
    PORT
      LAYER M4 ;
        RECT  21.516 3.6 21.6 3.624 ;
    END
  END b[372]
  PIN b[373]
    DIRECTION OUTPUT ;
    USE SIGNAL ;
    PORT
      LAYER M4 ;
        RECT  21.516 3.744 21.6 3.768 ;
    END
  END b[373]
  PIN b[374]
    DIRECTION OUTPUT ;
    USE SIGNAL ;
    PORT
      LAYER M4 ;
        RECT  21.516 3.888 21.6 3.912 ;
    END
  END b[374]
  PIN b[375]
    DIRECTION OUTPUT ;
    USE SIGNAL ;
    PORT
      LAYER M4 ;
        RECT  21.516 4.032 21.6 4.056 ;
    END
  END b[375]
  PIN b[376]
    DIRECTION OUTPUT ;
    USE SIGNAL ;
    PORT
      LAYER M4 ;
        RECT  21.516 4.176 21.6 4.2 ;
    END
  END b[376]
  PIN b[377]
    DIRECTION OUTPUT ;
    USE SIGNAL ;
    PORT
      LAYER M4 ;
        RECT  21.516 4.32 21.6 4.344 ;
    END
  END b[377]
  PIN b[378]
    DIRECTION OUTPUT ;
    USE SIGNAL ;
    PORT
      LAYER M4 ;
        RECT  21.516 4.464 21.6 4.488 ;
    END
  END b[378]
  PIN b[379]
    DIRECTION OUTPUT ;
    USE SIGNAL ;
    PORT
      LAYER M4 ;
        RECT  21.516 4.608 21.6 4.632 ;
    END
  END b[379]
  PIN b[37]
    DIRECTION OUTPUT ;
    USE SIGNAL ;
    PORT
      LAYER M4 ;
        RECT  21.516 39.456 21.6 39.48 ;
    END
  END b[37]
  PIN b[380]
    DIRECTION OUTPUT ;
    USE SIGNAL ;
    PORT
      LAYER M4 ;
        RECT  21.516 4.752 21.6 4.776 ;
    END
  END b[380]
  PIN b[381]
    DIRECTION OUTPUT ;
    USE SIGNAL ;
    PORT
      LAYER M4 ;
        RECT  21.516 4.896 21.6 4.92 ;
    END
  END b[381]
  PIN b[382]
    DIRECTION OUTPUT ;
    USE SIGNAL ;
    PORT
      LAYER M4 ;
        RECT  21.516 5.04 21.6 5.064 ;
    END
  END b[382]
  PIN b[383]
    DIRECTION OUTPUT ;
    USE SIGNAL ;
    PORT
      LAYER M4 ;
        RECT  21.516 5.184 21.6 5.208 ;
    END
  END b[383]
  PIN b[384]
    DIRECTION OUTPUT ;
    USE SIGNAL ;
    PORT
      LAYER M4 ;
        RECT  21.516 72.144 21.6 72.168 ;
    END
  END b[384]
  PIN b[385]
    DIRECTION OUTPUT ;
    USE SIGNAL ;
    PORT
      LAYER M4 ;
        RECT  21.516 72.288 21.6 72.312 ;
    END
  END b[385]
  PIN b[386]
    DIRECTION OUTPUT ;
    USE SIGNAL ;
    PORT
      LAYER M4 ;
        RECT  21.516 72.432 21.6 72.456 ;
    END
  END b[386]
  PIN b[387]
    DIRECTION OUTPUT ;
    USE SIGNAL ;
    PORT
      LAYER M4 ;
        RECT  21.516 72.576 21.6 72.6 ;
    END
  END b[387]
  PIN b[388]
    DIRECTION OUTPUT ;
    USE SIGNAL ;
    PORT
      LAYER M4 ;
        RECT  21.516 72.72 21.6 72.744 ;
    END
  END b[388]
  PIN b[389]
    DIRECTION OUTPUT ;
    USE SIGNAL ;
    PORT
      LAYER M4 ;
        RECT  21.516 72.864 21.6 72.888 ;
    END
  END b[389]
  PIN b[38]
    DIRECTION OUTPUT ;
    USE SIGNAL ;
    PORT
      LAYER M4 ;
        RECT  21.516 39.6 21.6 39.624 ;
    END
  END b[38]
  PIN b[390]
    DIRECTION OUTPUT ;
    USE SIGNAL ;
    PORT
      LAYER M4 ;
        RECT  21.516 73.008 21.6 73.032 ;
    END
  END b[390]
  PIN b[391]
    DIRECTION OUTPUT ;
    USE SIGNAL ;
    PORT
      LAYER M4 ;
        RECT  21.516 73.152 21.6 73.176 ;
    END
  END b[391]
  PIN b[392]
    DIRECTION OUTPUT ;
    USE SIGNAL ;
    PORT
      LAYER M4 ;
        RECT  21.516 73.296 21.6 73.32 ;
    END
  END b[392]
  PIN b[393]
    DIRECTION OUTPUT ;
    USE SIGNAL ;
    PORT
      LAYER M4 ;
        RECT  21.516 73.44 21.6 73.464 ;
    END
  END b[393]
  PIN b[394]
    DIRECTION OUTPUT ;
    USE SIGNAL ;
    PORT
      LAYER M4 ;
        RECT  21.516 73.584 21.6 73.608 ;
    END
  END b[394]
  PIN b[395]
    DIRECTION OUTPUT ;
    USE SIGNAL ;
    PORT
      LAYER M4 ;
        RECT  21.516 73.728 21.6 73.752 ;
    END
  END b[395]
  PIN b[396]
    DIRECTION OUTPUT ;
    USE SIGNAL ;
    PORT
      LAYER M4 ;
        RECT  21.516 73.872 21.6 73.896 ;
    END
  END b[396]
  PIN b[397]
    DIRECTION OUTPUT ;
    USE SIGNAL ;
    PORT
      LAYER M4 ;
        RECT  21.516 74.016 21.6 74.04 ;
    END
  END b[397]
  PIN b[398]
    DIRECTION OUTPUT ;
    USE SIGNAL ;
    PORT
      LAYER M4 ;
        RECT  21.516 74.16 21.6 74.184 ;
    END
  END b[398]
  PIN b[399]
    DIRECTION OUTPUT ;
    USE SIGNAL ;
    PORT
      LAYER M4 ;
        RECT  21.516 74.304 21.6 74.328 ;
    END
  END b[399]
  PIN b[39]
    DIRECTION OUTPUT ;
    USE SIGNAL ;
    PORT
      LAYER M4 ;
        RECT  21.516 39.744 21.6 39.768 ;
    END
  END b[39]
  PIN b[3]
    DIRECTION OUTPUT ;
    USE SIGNAL ;
    PORT
      LAYER M4 ;
        RECT  21.516 29.952 21.6 29.976 ;
    END
  END b[3]
  PIN b[400]
    DIRECTION OUTPUT ;
    USE SIGNAL ;
    PORT
      LAYER M4 ;
        RECT  21.516 74.448 21.6 74.472 ;
    END
  END b[400]
  PIN b[401]
    DIRECTION OUTPUT ;
    USE SIGNAL ;
    PORT
      LAYER M4 ;
        RECT  21.516 74.592 21.6 74.616 ;
    END
  END b[401]
  PIN b[402]
    DIRECTION OUTPUT ;
    USE SIGNAL ;
    PORT
      LAYER M4 ;
        RECT  21.516 74.736 21.6 74.76 ;
    END
  END b[402]
  PIN b[403]
    DIRECTION OUTPUT ;
    USE SIGNAL ;
    PORT
      LAYER M4 ;
        RECT  21.516 74.88 21.6 74.904 ;
    END
  END b[403]
  PIN b[404]
    DIRECTION OUTPUT ;
    USE SIGNAL ;
    PORT
      LAYER M4 ;
        RECT  21.516 75.024 21.6 75.048 ;
    END
  END b[404]
  PIN b[405]
    DIRECTION OUTPUT ;
    USE SIGNAL ;
    PORT
      LAYER M4 ;
        RECT  21.516 75.168 21.6 75.192 ;
    END
  END b[405]
  PIN b[406]
    DIRECTION OUTPUT ;
    USE SIGNAL ;
    PORT
      LAYER M4 ;
        RECT  21.516 75.312 21.6 75.336 ;
    END
  END b[406]
  PIN b[407]
    DIRECTION OUTPUT ;
    USE SIGNAL ;
    PORT
      LAYER M4 ;
        RECT  21.516 75.456 21.6 75.48 ;
    END
  END b[407]
  PIN b[408]
    DIRECTION OUTPUT ;
    USE SIGNAL ;
    PORT
      LAYER M4 ;
        RECT  21.516 75.6 21.6 75.624 ;
    END
  END b[408]
  PIN b[409]
    DIRECTION OUTPUT ;
    USE SIGNAL ;
    PORT
      LAYER M4 ;
        RECT  21.516 75.744 21.6 75.768 ;
    END
  END b[409]
  PIN b[40]
    DIRECTION OUTPUT ;
    USE SIGNAL ;
    PORT
      LAYER M4 ;
        RECT  21.516 39.888 21.6 39.912 ;
    END
  END b[40]
  PIN b[410]
    DIRECTION OUTPUT ;
    USE SIGNAL ;
    PORT
      LAYER M4 ;
        RECT  21.516 75.888 21.6 75.912 ;
    END
  END b[410]
  PIN b[411]
    DIRECTION OUTPUT ;
    USE SIGNAL ;
    PORT
      LAYER M4 ;
        RECT  21.516 76.032 21.6 76.056 ;
    END
  END b[411]
  PIN b[412]
    DIRECTION OUTPUT ;
    USE SIGNAL ;
    PORT
      LAYER M4 ;
        RECT  21.516 76.176 21.6 76.2 ;
    END
  END b[412]
  PIN b[413]
    DIRECTION OUTPUT ;
    USE SIGNAL ;
    PORT
      LAYER M4 ;
        RECT  21.516 76.32 21.6 76.344 ;
    END
  END b[413]
  PIN b[414]
    DIRECTION OUTPUT ;
    USE SIGNAL ;
    PORT
      LAYER M4 ;
        RECT  21.516 76.464 21.6 76.488 ;
    END
  END b[414]
  PIN b[415]
    DIRECTION OUTPUT ;
    USE SIGNAL ;
    PORT
      LAYER M4 ;
        RECT  21.516 76.608 21.6 76.632 ;
    END
  END b[415]
  PIN b[416]
    DIRECTION OUTPUT ;
    USE SIGNAL ;
    PORT
      LAYER M4 ;
        RECT  21.516 67.536 21.6 67.56 ;
    END
  END b[416]
  PIN b[417]
    DIRECTION OUTPUT ;
    USE SIGNAL ;
    PORT
      LAYER M4 ;
        RECT  21.516 67.68 21.6 67.704 ;
    END
  END b[417]
  PIN b[418]
    DIRECTION OUTPUT ;
    USE SIGNAL ;
    PORT
      LAYER M4 ;
        RECT  21.516 67.824 21.6 67.848 ;
    END
  END b[418]
  PIN b[419]
    DIRECTION OUTPUT ;
    USE SIGNAL ;
    PORT
      LAYER M4 ;
        RECT  21.516 67.968 21.6 67.992 ;
    END
  END b[419]
  PIN b[41]
    DIRECTION OUTPUT ;
    USE SIGNAL ;
    PORT
      LAYER M4 ;
        RECT  21.516 40.032 21.6 40.056 ;
    END
  END b[41]
  PIN b[420]
    DIRECTION OUTPUT ;
    USE SIGNAL ;
    PORT
      LAYER M4 ;
        RECT  21.516 68.112 21.6 68.136 ;
    END
  END b[420]
  PIN b[421]
    DIRECTION OUTPUT ;
    USE SIGNAL ;
    PORT
      LAYER M4 ;
        RECT  21.516 68.256 21.6 68.28 ;
    END
  END b[421]
  PIN b[422]
    DIRECTION OUTPUT ;
    USE SIGNAL ;
    PORT
      LAYER M4 ;
        RECT  21.516 68.4 21.6 68.424 ;
    END
  END b[422]
  PIN b[423]
    DIRECTION OUTPUT ;
    USE SIGNAL ;
    PORT
      LAYER M4 ;
        RECT  21.516 68.544 21.6 68.568 ;
    END
  END b[423]
  PIN b[424]
    DIRECTION OUTPUT ;
    USE SIGNAL ;
    PORT
      LAYER M4 ;
        RECT  21.516 68.688 21.6 68.712 ;
    END
  END b[424]
  PIN b[425]
    DIRECTION OUTPUT ;
    USE SIGNAL ;
    PORT
      LAYER M4 ;
        RECT  21.516 68.832 21.6 68.856 ;
    END
  END b[425]
  PIN b[426]
    DIRECTION OUTPUT ;
    USE SIGNAL ;
    PORT
      LAYER M4 ;
        RECT  21.516 68.976 21.6 69 ;
    END
  END b[426]
  PIN b[427]
    DIRECTION OUTPUT ;
    USE SIGNAL ;
    PORT
      LAYER M4 ;
        RECT  21.516 69.12 21.6 69.144 ;
    END
  END b[427]
  PIN b[428]
    DIRECTION OUTPUT ;
    USE SIGNAL ;
    PORT
      LAYER M4 ;
        RECT  21.516 69.264 21.6 69.288 ;
    END
  END b[428]
  PIN b[429]
    DIRECTION OUTPUT ;
    USE SIGNAL ;
    PORT
      LAYER M4 ;
        RECT  21.516 69.408 21.6 69.432 ;
    END
  END b[429]
  PIN b[42]
    DIRECTION OUTPUT ;
    USE SIGNAL ;
    PORT
      LAYER M4 ;
        RECT  21.516 40.176 21.6 40.2 ;
    END
  END b[42]
  PIN b[430]
    DIRECTION OUTPUT ;
    USE SIGNAL ;
    PORT
      LAYER M4 ;
        RECT  21.516 69.552 21.6 69.576 ;
    END
  END b[430]
  PIN b[431]
    DIRECTION OUTPUT ;
    USE SIGNAL ;
    PORT
      LAYER M4 ;
        RECT  21.516 69.696 21.6 69.72 ;
    END
  END b[431]
  PIN b[432]
    DIRECTION OUTPUT ;
    USE SIGNAL ;
    PORT
      LAYER M4 ;
        RECT  21.516 69.84 21.6 69.864 ;
    END
  END b[432]
  PIN b[433]
    DIRECTION OUTPUT ;
    USE SIGNAL ;
    PORT
      LAYER M4 ;
        RECT  21.516 69.984 21.6 70.008 ;
    END
  END b[433]
  PIN b[434]
    DIRECTION OUTPUT ;
    USE SIGNAL ;
    PORT
      LAYER M4 ;
        RECT  21.516 70.128 21.6 70.152 ;
    END
  END b[434]
  PIN b[435]
    DIRECTION OUTPUT ;
    USE SIGNAL ;
    PORT
      LAYER M4 ;
        RECT  21.516 70.272 21.6 70.296 ;
    END
  END b[435]
  PIN b[436]
    DIRECTION OUTPUT ;
    USE SIGNAL ;
    PORT
      LAYER M4 ;
        RECT  21.516 70.416 21.6 70.44 ;
    END
  END b[436]
  PIN b[437]
    DIRECTION OUTPUT ;
    USE SIGNAL ;
    PORT
      LAYER M4 ;
        RECT  21.516 70.56 21.6 70.584 ;
    END
  END b[437]
  PIN b[438]
    DIRECTION OUTPUT ;
    USE SIGNAL ;
    PORT
      LAYER M4 ;
        RECT  21.516 70.704 21.6 70.728 ;
    END
  END b[438]
  PIN b[439]
    DIRECTION OUTPUT ;
    USE SIGNAL ;
    PORT
      LAYER M4 ;
        RECT  21.516 70.848 21.6 70.872 ;
    END
  END b[439]
  PIN b[43]
    DIRECTION OUTPUT ;
    USE SIGNAL ;
    PORT
      LAYER M4 ;
        RECT  21.516 40.32 21.6 40.344 ;
    END
  END b[43]
  PIN b[440]
    DIRECTION OUTPUT ;
    USE SIGNAL ;
    PORT
      LAYER M4 ;
        RECT  21.516 70.992 21.6 71.016 ;
    END
  END b[440]
  PIN b[441]
    DIRECTION OUTPUT ;
    USE SIGNAL ;
    PORT
      LAYER M4 ;
        RECT  21.516 71.136 21.6 71.16 ;
    END
  END b[441]
  PIN b[442]
    DIRECTION OUTPUT ;
    USE SIGNAL ;
    PORT
      LAYER M4 ;
        RECT  21.516 71.28 21.6 71.304 ;
    END
  END b[442]
  PIN b[443]
    DIRECTION OUTPUT ;
    USE SIGNAL ;
    PORT
      LAYER M4 ;
        RECT  21.516 71.424 21.6 71.448 ;
    END
  END b[443]
  PIN b[444]
    DIRECTION OUTPUT ;
    USE SIGNAL ;
    PORT
      LAYER M4 ;
        RECT  21.516 71.568 21.6 71.592 ;
    END
  END b[444]
  PIN b[445]
    DIRECTION OUTPUT ;
    USE SIGNAL ;
    PORT
      LAYER M4 ;
        RECT  21.516 71.712 21.6 71.736 ;
    END
  END b[445]
  PIN b[446]
    DIRECTION OUTPUT ;
    USE SIGNAL ;
    PORT
      LAYER M4 ;
        RECT  21.516 71.856 21.6 71.88 ;
    END
  END b[446]
  PIN b[447]
    DIRECTION OUTPUT ;
    USE SIGNAL ;
    PORT
      LAYER M4 ;
        RECT  21.516 72 21.6 72.024 ;
    END
  END b[447]
  PIN b[448]
    DIRECTION OUTPUT ;
    USE SIGNAL ;
    PORT
      LAYER M4 ;
        RECT  21.516 62.928 21.6 62.952 ;
    END
  END b[448]
  PIN b[449]
    DIRECTION OUTPUT ;
    USE SIGNAL ;
    PORT
      LAYER M4 ;
        RECT  21.516 63.072 21.6 63.096 ;
    END
  END b[449]
  PIN b[44]
    DIRECTION OUTPUT ;
    USE SIGNAL ;
    PORT
      LAYER M4 ;
        RECT  21.516 40.464 21.6 40.488 ;
    END
  END b[44]
  PIN b[450]
    DIRECTION OUTPUT ;
    USE SIGNAL ;
    PORT
      LAYER M4 ;
        RECT  21.516 63.216 21.6 63.24 ;
    END
  END b[450]
  PIN b[451]
    DIRECTION OUTPUT ;
    USE SIGNAL ;
    PORT
      LAYER M4 ;
        RECT  21.516 63.36 21.6 63.384 ;
    END
  END b[451]
  PIN b[452]
    DIRECTION OUTPUT ;
    USE SIGNAL ;
    PORT
      LAYER M4 ;
        RECT  21.516 63.504 21.6 63.528 ;
    END
  END b[452]
  PIN b[453]
    DIRECTION OUTPUT ;
    USE SIGNAL ;
    PORT
      LAYER M4 ;
        RECT  21.516 63.648 21.6 63.672 ;
    END
  END b[453]
  PIN b[454]
    DIRECTION OUTPUT ;
    USE SIGNAL ;
    PORT
      LAYER M4 ;
        RECT  21.516 63.792 21.6 63.816 ;
    END
  END b[454]
  PIN b[455]
    DIRECTION OUTPUT ;
    USE SIGNAL ;
    PORT
      LAYER M4 ;
        RECT  21.516 63.936 21.6 63.96 ;
    END
  END b[455]
  PIN b[456]
    DIRECTION OUTPUT ;
    USE SIGNAL ;
    PORT
      LAYER M4 ;
        RECT  21.516 64.08 21.6 64.104 ;
    END
  END b[456]
  PIN b[457]
    DIRECTION OUTPUT ;
    USE SIGNAL ;
    PORT
      LAYER M4 ;
        RECT  21.516 64.224 21.6 64.248 ;
    END
  END b[457]
  PIN b[458]
    DIRECTION OUTPUT ;
    USE SIGNAL ;
    PORT
      LAYER M4 ;
        RECT  21.516 64.368 21.6 64.392 ;
    END
  END b[458]
  PIN b[459]
    DIRECTION OUTPUT ;
    USE SIGNAL ;
    PORT
      LAYER M4 ;
        RECT  21.516 64.512 21.6 64.536 ;
    END
  END b[459]
  PIN b[45]
    DIRECTION OUTPUT ;
    USE SIGNAL ;
    PORT
      LAYER M4 ;
        RECT  21.516 40.608 21.6 40.632 ;
    END
  END b[45]
  PIN b[460]
    DIRECTION OUTPUT ;
    USE SIGNAL ;
    PORT
      LAYER M4 ;
        RECT  21.516 64.656 21.6 64.68 ;
    END
  END b[460]
  PIN b[461]
    DIRECTION OUTPUT ;
    USE SIGNAL ;
    PORT
      LAYER M4 ;
        RECT  21.516 64.8 21.6 64.824 ;
    END
  END b[461]
  PIN b[462]
    DIRECTION OUTPUT ;
    USE SIGNAL ;
    PORT
      LAYER M4 ;
        RECT  21.516 64.944 21.6 64.968 ;
    END
  END b[462]
  PIN b[463]
    DIRECTION OUTPUT ;
    USE SIGNAL ;
    PORT
      LAYER M4 ;
        RECT  21.516 65.088 21.6 65.112 ;
    END
  END b[463]
  PIN b[464]
    DIRECTION OUTPUT ;
    USE SIGNAL ;
    PORT
      LAYER M4 ;
        RECT  21.516 65.232 21.6 65.256 ;
    END
  END b[464]
  PIN b[465]
    DIRECTION OUTPUT ;
    USE SIGNAL ;
    PORT
      LAYER M4 ;
        RECT  21.516 65.376 21.6 65.4 ;
    END
  END b[465]
  PIN b[466]
    DIRECTION OUTPUT ;
    USE SIGNAL ;
    PORT
      LAYER M4 ;
        RECT  21.516 65.52 21.6 65.544 ;
    END
  END b[466]
  PIN b[467]
    DIRECTION OUTPUT ;
    USE SIGNAL ;
    PORT
      LAYER M4 ;
        RECT  21.516 65.664 21.6 65.688 ;
    END
  END b[467]
  PIN b[468]
    DIRECTION OUTPUT ;
    USE SIGNAL ;
    PORT
      LAYER M4 ;
        RECT  21.516 65.808 21.6 65.832 ;
    END
  END b[468]
  PIN b[469]
    DIRECTION OUTPUT ;
    USE SIGNAL ;
    PORT
      LAYER M4 ;
        RECT  21.516 65.952 21.6 65.976 ;
    END
  END b[469]
  PIN b[46]
    DIRECTION OUTPUT ;
    USE SIGNAL ;
    PORT
      LAYER M4 ;
        RECT  21.516 40.752 21.6 40.776 ;
    END
  END b[46]
  PIN b[470]
    DIRECTION OUTPUT ;
    USE SIGNAL ;
    PORT
      LAYER M4 ;
        RECT  21.516 66.096 21.6 66.12 ;
    END
  END b[470]
  PIN b[471]
    DIRECTION OUTPUT ;
    USE SIGNAL ;
    PORT
      LAYER M4 ;
        RECT  21.516 66.24 21.6 66.264 ;
    END
  END b[471]
  PIN b[472]
    DIRECTION OUTPUT ;
    USE SIGNAL ;
    PORT
      LAYER M4 ;
        RECT  21.516 66.384 21.6 66.408 ;
    END
  END b[472]
  PIN b[473]
    DIRECTION OUTPUT ;
    USE SIGNAL ;
    PORT
      LAYER M4 ;
        RECT  21.516 66.528 21.6 66.552 ;
    END
  END b[473]
  PIN b[474]
    DIRECTION OUTPUT ;
    USE SIGNAL ;
    PORT
      LAYER M4 ;
        RECT  21.516 66.672 21.6 66.696 ;
    END
  END b[474]
  PIN b[475]
    DIRECTION OUTPUT ;
    USE SIGNAL ;
    PORT
      LAYER M4 ;
        RECT  21.516 66.816 21.6 66.84 ;
    END
  END b[475]
  PIN b[476]
    DIRECTION OUTPUT ;
    USE SIGNAL ;
    PORT
      LAYER M4 ;
        RECT  21.516 66.96 21.6 66.984 ;
    END
  END b[476]
  PIN b[477]
    DIRECTION OUTPUT ;
    USE SIGNAL ;
    PORT
      LAYER M4 ;
        RECT  21.516 67.104 21.6 67.128 ;
    END
  END b[477]
  PIN b[478]
    DIRECTION OUTPUT ;
    USE SIGNAL ;
    PORT
      LAYER M4 ;
        RECT  21.516 67.248 21.6 67.272 ;
    END
  END b[478]
  PIN b[479]
    DIRECTION OUTPUT ;
    USE SIGNAL ;
    PORT
      LAYER M4 ;
        RECT  21.516 67.392 21.6 67.416 ;
    END
  END b[479]
  PIN b[47]
    DIRECTION OUTPUT ;
    USE SIGNAL ;
    PORT
      LAYER M4 ;
        RECT  21.516 40.896 21.6 40.92 ;
    END
  END b[47]
  PIN b[480]
    DIRECTION OUTPUT ;
    USE SIGNAL ;
    PORT
      LAYER M4 ;
        RECT  21.516 58.32 21.6 58.344 ;
    END
  END b[480]
  PIN b[481]
    DIRECTION OUTPUT ;
    USE SIGNAL ;
    PORT
      LAYER M4 ;
        RECT  21.516 58.464 21.6 58.488 ;
    END
  END b[481]
  PIN b[482]
    DIRECTION OUTPUT ;
    USE SIGNAL ;
    PORT
      LAYER M4 ;
        RECT  21.516 58.608 21.6 58.632 ;
    END
  END b[482]
  PIN b[483]
    DIRECTION OUTPUT ;
    USE SIGNAL ;
    PORT
      LAYER M4 ;
        RECT  21.516 58.752 21.6 58.776 ;
    END
  END b[483]
  PIN b[484]
    DIRECTION OUTPUT ;
    USE SIGNAL ;
    PORT
      LAYER M4 ;
        RECT  21.516 58.896 21.6 58.92 ;
    END
  END b[484]
  PIN b[485]
    DIRECTION OUTPUT ;
    USE SIGNAL ;
    PORT
      LAYER M4 ;
        RECT  21.516 59.04 21.6 59.064 ;
    END
  END b[485]
  PIN b[486]
    DIRECTION OUTPUT ;
    USE SIGNAL ;
    PORT
      LAYER M4 ;
        RECT  21.516 59.184 21.6 59.208 ;
    END
  END b[486]
  PIN b[487]
    DIRECTION OUTPUT ;
    USE SIGNAL ;
    PORT
      LAYER M4 ;
        RECT  21.516 59.328 21.6 59.352 ;
    END
  END b[487]
  PIN b[488]
    DIRECTION OUTPUT ;
    USE SIGNAL ;
    PORT
      LAYER M4 ;
        RECT  21.516 59.472 21.6 59.496 ;
    END
  END b[488]
  PIN b[489]
    DIRECTION OUTPUT ;
    USE SIGNAL ;
    PORT
      LAYER M4 ;
        RECT  21.516 59.616 21.6 59.64 ;
    END
  END b[489]
  PIN b[48]
    DIRECTION OUTPUT ;
    USE SIGNAL ;
    PORT
      LAYER M4 ;
        RECT  21.516 41.04 21.6 41.064 ;
    END
  END b[48]
  PIN b[490]
    DIRECTION OUTPUT ;
    USE SIGNAL ;
    PORT
      LAYER M4 ;
        RECT  21.516 59.76 21.6 59.784 ;
    END
  END b[490]
  PIN b[491]
    DIRECTION OUTPUT ;
    USE SIGNAL ;
    PORT
      LAYER M4 ;
        RECT  21.516 59.904 21.6 59.928 ;
    END
  END b[491]
  PIN b[492]
    DIRECTION OUTPUT ;
    USE SIGNAL ;
    PORT
      LAYER M4 ;
        RECT  21.516 60.048 21.6 60.072 ;
    END
  END b[492]
  PIN b[493]
    DIRECTION OUTPUT ;
    USE SIGNAL ;
    PORT
      LAYER M4 ;
        RECT  21.516 60.192 21.6 60.216 ;
    END
  END b[493]
  PIN b[494]
    DIRECTION OUTPUT ;
    USE SIGNAL ;
    PORT
      LAYER M4 ;
        RECT  21.516 60.336 21.6 60.36 ;
    END
  END b[494]
  PIN b[495]
    DIRECTION OUTPUT ;
    USE SIGNAL ;
    PORT
      LAYER M4 ;
        RECT  21.516 60.48 21.6 60.504 ;
    END
  END b[495]
  PIN b[496]
    DIRECTION OUTPUT ;
    USE SIGNAL ;
    PORT
      LAYER M4 ;
        RECT  21.516 60.624 21.6 60.648 ;
    END
  END b[496]
  PIN b[497]
    DIRECTION OUTPUT ;
    USE SIGNAL ;
    PORT
      LAYER M4 ;
        RECT  21.516 60.768 21.6 60.792 ;
    END
  END b[497]
  PIN b[498]
    DIRECTION OUTPUT ;
    USE SIGNAL ;
    PORT
      LAYER M4 ;
        RECT  21.516 60.912 21.6 60.936 ;
    END
  END b[498]
  PIN b[499]
    DIRECTION OUTPUT ;
    USE SIGNAL ;
    PORT
      LAYER M4 ;
        RECT  21.516 61.056 21.6 61.08 ;
    END
  END b[499]
  PIN b[49]
    DIRECTION OUTPUT ;
    USE SIGNAL ;
    PORT
      LAYER M4 ;
        RECT  21.516 41.184 21.6 41.208 ;
    END
  END b[49]
  PIN b[4]
    DIRECTION OUTPUT ;
    USE SIGNAL ;
    PORT
      LAYER M4 ;
        RECT  21.516 30.096 21.6 30.12 ;
    END
  END b[4]
  PIN b[500]
    DIRECTION OUTPUT ;
    USE SIGNAL ;
    PORT
      LAYER M4 ;
        RECT  21.516 61.2 21.6 61.224 ;
    END
  END b[500]
  PIN b[501]
    DIRECTION OUTPUT ;
    USE SIGNAL ;
    PORT
      LAYER M4 ;
        RECT  21.516 61.344 21.6 61.368 ;
    END
  END b[501]
  PIN b[502]
    DIRECTION OUTPUT ;
    USE SIGNAL ;
    PORT
      LAYER M4 ;
        RECT  21.516 61.488 21.6 61.512 ;
    END
  END b[502]
  PIN b[503]
    DIRECTION OUTPUT ;
    USE SIGNAL ;
    PORT
      LAYER M4 ;
        RECT  21.516 61.632 21.6 61.656 ;
    END
  END b[503]
  PIN b[504]
    DIRECTION OUTPUT ;
    USE SIGNAL ;
    PORT
      LAYER M4 ;
        RECT  21.516 61.776 21.6 61.8 ;
    END
  END b[504]
  PIN b[505]
    DIRECTION OUTPUT ;
    USE SIGNAL ;
    PORT
      LAYER M4 ;
        RECT  21.516 61.92 21.6 61.944 ;
    END
  END b[505]
  PIN b[506]
    DIRECTION OUTPUT ;
    USE SIGNAL ;
    PORT
      LAYER M4 ;
        RECT  21.516 62.064 21.6 62.088 ;
    END
  END b[506]
  PIN b[507]
    DIRECTION OUTPUT ;
    USE SIGNAL ;
    PORT
      LAYER M4 ;
        RECT  21.516 62.208 21.6 62.232 ;
    END
  END b[507]
  PIN b[508]
    DIRECTION OUTPUT ;
    USE SIGNAL ;
    PORT
      LAYER M4 ;
        RECT  21.516 62.352 21.6 62.376 ;
    END
  END b[508]
  PIN b[509]
    DIRECTION OUTPUT ;
    USE SIGNAL ;
    PORT
      LAYER M4 ;
        RECT  21.516 62.496 21.6 62.52 ;
    END
  END b[509]
  PIN b[50]
    DIRECTION OUTPUT ;
    USE SIGNAL ;
    PORT
      LAYER M4 ;
        RECT  21.516 41.328 21.6 41.352 ;
    END
  END b[50]
  PIN b[510]
    DIRECTION OUTPUT ;
    USE SIGNAL ;
    PORT
      LAYER M4 ;
        RECT  21.516 62.64 21.6 62.664 ;
    END
  END b[510]
  PIN b[511]
    DIRECTION OUTPUT ;
    USE SIGNAL ;
    PORT
      LAYER M4 ;
        RECT  21.516 62.784 21.6 62.808 ;
    END
  END b[511]
  PIN b[512]
    DIRECTION OUTPUT ;
    USE SIGNAL ;
    PORT
      LAYER M4 ;
        RECT  21.516 76.752 21.6 76.776 ;
    END
  END b[512]
  PIN b[513]
    DIRECTION OUTPUT ;
    USE SIGNAL ;
    PORT
      LAYER M4 ;
        RECT  21.516 76.896 21.6 76.92 ;
    END
  END b[513]
  PIN b[514]
    DIRECTION OUTPUT ;
    USE SIGNAL ;
    PORT
      LAYER M4 ;
        RECT  21.516 77.04 21.6 77.064 ;
    END
  END b[514]
  PIN b[515]
    DIRECTION OUTPUT ;
    USE SIGNAL ;
    PORT
      LAYER M4 ;
        RECT  21.516 77.184 21.6 77.208 ;
    END
  END b[515]
  PIN b[516]
    DIRECTION OUTPUT ;
    USE SIGNAL ;
    PORT
      LAYER M4 ;
        RECT  21.516 77.328 21.6 77.352 ;
    END
  END b[516]
  PIN b[517]
    DIRECTION OUTPUT ;
    USE SIGNAL ;
    PORT
      LAYER M4 ;
        RECT  21.516 77.472 21.6 77.496 ;
    END
  END b[517]
  PIN b[518]
    DIRECTION OUTPUT ;
    USE SIGNAL ;
    PORT
      LAYER M4 ;
        RECT  21.516 77.616 21.6 77.64 ;
    END
  END b[518]
  PIN b[519]
    DIRECTION OUTPUT ;
    USE SIGNAL ;
    PORT
      LAYER M4 ;
        RECT  21.516 77.76 21.6 77.784 ;
    END
  END b[519]
  PIN b[51]
    DIRECTION OUTPUT ;
    USE SIGNAL ;
    PORT
      LAYER M4 ;
        RECT  21.516 41.472 21.6 41.496 ;
    END
  END b[51]
  PIN b[520]
    DIRECTION OUTPUT ;
    USE SIGNAL ;
    PORT
      LAYER M4 ;
        RECT  21.516 77.904 21.6 77.928 ;
    END
  END b[520]
  PIN b[521]
    DIRECTION OUTPUT ;
    USE SIGNAL ;
    PORT
      LAYER M4 ;
        RECT  21.516 78.048 21.6 78.072 ;
    END
  END b[521]
  PIN b[522]
    DIRECTION OUTPUT ;
    USE SIGNAL ;
    PORT
      LAYER M4 ;
        RECT  21.516 78.192 21.6 78.216 ;
    END
  END b[522]
  PIN b[523]
    DIRECTION OUTPUT ;
    USE SIGNAL ;
    PORT
      LAYER M4 ;
        RECT  21.516 78.336 21.6 78.36 ;
    END
  END b[523]
  PIN b[524]
    DIRECTION OUTPUT ;
    USE SIGNAL ;
    PORT
      LAYER M4 ;
        RECT  21.516 78.48 21.6 78.504 ;
    END
  END b[524]
  PIN b[525]
    DIRECTION OUTPUT ;
    USE SIGNAL ;
    PORT
      LAYER M4 ;
        RECT  21.516 78.624 21.6 78.648 ;
    END
  END b[525]
  PIN b[526]
    DIRECTION OUTPUT ;
    USE SIGNAL ;
    PORT
      LAYER M4 ;
        RECT  21.516 78.768 21.6 78.792 ;
    END
  END b[526]
  PIN b[527]
    DIRECTION OUTPUT ;
    USE SIGNAL ;
    PORT
      LAYER M4 ;
        RECT  21.516 78.912 21.6 78.936 ;
    END
  END b[527]
  PIN b[52]
    DIRECTION OUTPUT ;
    USE SIGNAL ;
    PORT
      LAYER M4 ;
        RECT  21.516 41.616 21.6 41.64 ;
    END
  END b[52]
  PIN b[53]
    DIRECTION OUTPUT ;
    USE SIGNAL ;
    PORT
      LAYER M4 ;
        RECT  21.516 41.76 21.6 41.784 ;
    END
  END b[53]
  PIN b[54]
    DIRECTION OUTPUT ;
    USE SIGNAL ;
    PORT
      LAYER M4 ;
        RECT  21.516 41.904 21.6 41.928 ;
    END
  END b[54]
  PIN b[55]
    DIRECTION OUTPUT ;
    USE SIGNAL ;
    PORT
      LAYER M4 ;
        RECT  21.516 42.048 21.6 42.072 ;
    END
  END b[55]
  PIN b[56]
    DIRECTION OUTPUT ;
    USE SIGNAL ;
    PORT
      LAYER M4 ;
        RECT  21.516 42.192 21.6 42.216 ;
    END
  END b[56]
  PIN b[57]
    DIRECTION OUTPUT ;
    USE SIGNAL ;
    PORT
      LAYER M4 ;
        RECT  21.516 42.336 21.6 42.36 ;
    END
  END b[57]
  PIN b[58]
    DIRECTION OUTPUT ;
    USE SIGNAL ;
    PORT
      LAYER M4 ;
        RECT  21.516 42.48 21.6 42.504 ;
    END
  END b[58]
  PIN b[59]
    DIRECTION OUTPUT ;
    USE SIGNAL ;
    PORT
      LAYER M4 ;
        RECT  21.516 42.624 21.6 42.648 ;
    END
  END b[59]
  PIN b[5]
    DIRECTION OUTPUT ;
    USE SIGNAL ;
    PORT
      LAYER M4 ;
        RECT  21.516 30.24 21.6 30.264 ;
    END
  END b[5]
  PIN b[60]
    DIRECTION OUTPUT ;
    USE SIGNAL ;
    PORT
      LAYER M4 ;
        RECT  21.516 42.768 21.6 42.792 ;
    END
  END b[60]
  PIN b[61]
    DIRECTION OUTPUT ;
    USE SIGNAL ;
    PORT
      LAYER M4 ;
        RECT  21.516 42.912 21.6 42.936 ;
    END
  END b[61]
  PIN b[62]
    DIRECTION OUTPUT ;
    USE SIGNAL ;
    PORT
      LAYER M4 ;
        RECT  21.516 43.056 21.6 43.08 ;
    END
  END b[62]
  PIN b[63]
    DIRECTION OUTPUT ;
    USE SIGNAL ;
    PORT
      LAYER M4 ;
        RECT  21.516 43.2 21.6 43.224 ;
    END
  END b[63]
  PIN b[64]
    DIRECTION OUTPUT ;
    USE SIGNAL ;
    PORT
      LAYER M4 ;
        RECT  21.516 52.56 21.6 52.584 ;
    END
  END b[64]
  PIN b[65]
    DIRECTION OUTPUT ;
    USE SIGNAL ;
    PORT
      LAYER M4 ;
        RECT  21.516 52.704 21.6 52.728 ;
    END
  END b[65]
  PIN b[66]
    DIRECTION OUTPUT ;
    USE SIGNAL ;
    PORT
      LAYER M4 ;
        RECT  21.516 52.848 21.6 52.872 ;
    END
  END b[66]
  PIN b[67]
    DIRECTION OUTPUT ;
    USE SIGNAL ;
    PORT
      LAYER M4 ;
        RECT  21.516 52.992 21.6 53.016 ;
    END
  END b[67]
  PIN b[68]
    DIRECTION OUTPUT ;
    USE SIGNAL ;
    PORT
      LAYER M4 ;
        RECT  21.516 53.136 21.6 53.16 ;
    END
  END b[68]
  PIN b[69]
    DIRECTION OUTPUT ;
    USE SIGNAL ;
    PORT
      LAYER M4 ;
        RECT  21.516 53.28 21.6 53.304 ;
    END
  END b[69]
  PIN b[6]
    DIRECTION OUTPUT ;
    USE SIGNAL ;
    PORT
      LAYER M4 ;
        RECT  21.516 30.384 21.6 30.408 ;
    END
  END b[6]
  PIN b[70]
    DIRECTION OUTPUT ;
    USE SIGNAL ;
    PORT
      LAYER M4 ;
        RECT  21.516 53.424 21.6 53.448 ;
    END
  END b[70]
  PIN b[71]
    DIRECTION OUTPUT ;
    USE SIGNAL ;
    PORT
      LAYER M4 ;
        RECT  21.516 53.568 21.6 53.592 ;
    END
  END b[71]
  PIN b[72]
    DIRECTION OUTPUT ;
    USE SIGNAL ;
    PORT
      LAYER M4 ;
        RECT  21.516 53.712 21.6 53.736 ;
    END
  END b[72]
  PIN b[73]
    DIRECTION OUTPUT ;
    USE SIGNAL ;
    PORT
      LAYER M4 ;
        RECT  21.516 53.856 21.6 53.88 ;
    END
  END b[73]
  PIN b[74]
    DIRECTION OUTPUT ;
    USE SIGNAL ;
    PORT
      LAYER M4 ;
        RECT  21.516 54 21.6 54.024 ;
    END
  END b[74]
  PIN b[75]
    DIRECTION OUTPUT ;
    USE SIGNAL ;
    PORT
      LAYER M4 ;
        RECT  21.516 54.144 21.6 54.168 ;
    END
  END b[75]
  PIN b[76]
    DIRECTION OUTPUT ;
    USE SIGNAL ;
    PORT
      LAYER M4 ;
        RECT  21.516 54.288 21.6 54.312 ;
    END
  END b[76]
  PIN b[77]
    DIRECTION OUTPUT ;
    USE SIGNAL ;
    PORT
      LAYER M4 ;
        RECT  21.516 54.432 21.6 54.456 ;
    END
  END b[77]
  PIN b[78]
    DIRECTION OUTPUT ;
    USE SIGNAL ;
    PORT
      LAYER M4 ;
        RECT  21.516 54.576 21.6 54.6 ;
    END
  END b[78]
  PIN b[79]
    DIRECTION OUTPUT ;
    USE SIGNAL ;
    PORT
      LAYER M4 ;
        RECT  21.516 54.72 21.6 54.744 ;
    END
  END b[79]
  PIN b[7]
    DIRECTION OUTPUT ;
    USE SIGNAL ;
    PORT
      LAYER M4 ;
        RECT  21.516 30.528 21.6 30.552 ;
    END
  END b[7]
  PIN b[80]
    DIRECTION OUTPUT ;
    USE SIGNAL ;
    PORT
      LAYER M4 ;
        RECT  21.516 54.864 21.6 54.888 ;
    END
  END b[80]
  PIN b[81]
    DIRECTION OUTPUT ;
    USE SIGNAL ;
    PORT
      LAYER M4 ;
        RECT  21.516 55.008 21.6 55.032 ;
    END
  END b[81]
  PIN b[82]
    DIRECTION OUTPUT ;
    USE SIGNAL ;
    PORT
      LAYER M4 ;
        RECT  21.516 55.152 21.6 55.176 ;
    END
  END b[82]
  PIN b[83]
    DIRECTION OUTPUT ;
    USE SIGNAL ;
    PORT
      LAYER M4 ;
        RECT  21.516 55.296 21.6 55.32 ;
    END
  END b[83]
  PIN b[84]
    DIRECTION OUTPUT ;
    USE SIGNAL ;
    PORT
      LAYER M4 ;
        RECT  21.516 55.44 21.6 55.464 ;
    END
  END b[84]
  PIN b[85]
    DIRECTION OUTPUT ;
    USE SIGNAL ;
    PORT
      LAYER M4 ;
        RECT  21.516 55.584 21.6 55.608 ;
    END
  END b[85]
  PIN b[86]
    DIRECTION OUTPUT ;
    USE SIGNAL ;
    PORT
      LAYER M4 ;
        RECT  21.516 55.728 21.6 55.752 ;
    END
  END b[86]
  PIN b[87]
    DIRECTION OUTPUT ;
    USE SIGNAL ;
    PORT
      LAYER M4 ;
        RECT  21.516 55.872 21.6 55.896 ;
    END
  END b[87]
  PIN b[88]
    DIRECTION OUTPUT ;
    USE SIGNAL ;
    PORT
      LAYER M4 ;
        RECT  21.516 56.016 21.6 56.04 ;
    END
  END b[88]
  PIN b[89]
    DIRECTION OUTPUT ;
    USE SIGNAL ;
    PORT
      LAYER M4 ;
        RECT  21.516 56.16 21.6 56.184 ;
    END
  END b[89]
  PIN b[8]
    DIRECTION OUTPUT ;
    USE SIGNAL ;
    PORT
      LAYER M4 ;
        RECT  21.516 30.672 21.6 30.696 ;
    END
  END b[8]
  PIN b[90]
    DIRECTION OUTPUT ;
    USE SIGNAL ;
    PORT
      LAYER M4 ;
        RECT  21.516 56.304 21.6 56.328 ;
    END
  END b[90]
  PIN b[91]
    DIRECTION OUTPUT ;
    USE SIGNAL ;
    PORT
      LAYER M4 ;
        RECT  21.516 56.448 21.6 56.472 ;
    END
  END b[91]
  PIN b[92]
    DIRECTION OUTPUT ;
    USE SIGNAL ;
    PORT
      LAYER M4 ;
        RECT  21.516 56.592 21.6 56.616 ;
    END
  END b[92]
  PIN b[93]
    DIRECTION OUTPUT ;
    USE SIGNAL ;
    PORT
      LAYER M4 ;
        RECT  21.516 56.736 21.6 56.76 ;
    END
  END b[93]
  PIN b[94]
    DIRECTION OUTPUT ;
    USE SIGNAL ;
    PORT
      LAYER M4 ;
        RECT  21.516 56.88 21.6 56.904 ;
    END
  END b[94]
  PIN b[95]
    DIRECTION OUTPUT ;
    USE SIGNAL ;
    PORT
      LAYER M4 ;
        RECT  21.516 57.024 21.6 57.048 ;
    END
  END b[95]
  PIN b[96]
    DIRECTION OUTPUT ;
    USE SIGNAL ;
    PORT
      LAYER M4 ;
        RECT  21.516 34.128 21.6 34.152 ;
    END
  END b[96]
  PIN b[97]
    DIRECTION OUTPUT ;
    USE SIGNAL ;
    PORT
      LAYER M4 ;
        RECT  21.516 34.272 21.6 34.296 ;
    END
  END b[97]
  PIN b[98]
    DIRECTION OUTPUT ;
    USE SIGNAL ;
    PORT
      LAYER M4 ;
        RECT  21.516 34.416 21.6 34.44 ;
    END
  END b[98]
  PIN b[99]
    DIRECTION OUTPUT ;
    USE SIGNAL ;
    PORT
      LAYER M4 ;
        RECT  21.516 34.56 21.6 34.584 ;
    END
  END b[99]
  PIN b[9]
    DIRECTION OUTPUT ;
    USE SIGNAL ;
    PORT
      LAYER M4 ;
        RECT  21.516 30.816 21.6 30.84 ;
    END
  END b[9]
  PIN ck
    DIRECTION INPUT ;
    USE SIGNAL ;
    PORT
      LAYER M5 ;
        RECT  9.792 0 9.816 0.084 ;
    END
    PORT
      LAYER M5 ;
        RECT  9.792 0.016 9.816 2.137 ;
    END
  END ck
  PIN VDD
    DIRECTION INOUT ;
    USE POWER ;
    PORT
      LAYER M5 ;
        RECT  18.792 2.151 18.912 79.929 ;
        RECT  16.092 2.151 16.212 79.929 ;
        RECT  13.392 2.151 13.512 79.929 ;
        RECT  10.692 2.151 10.812 79.929 ;
        RECT  7.992 2.151 8.112 79.929 ;
        RECT  5.292 2.151 5.412 79.929 ;
        RECT  2.592 2.151 2.712 79.929 ;
    END
  END VDD
  PIN VSS
    DIRECTION INOUT ;
    USE GROUND ;
    PORT
      LAYER M5 ;
        RECT  18.6 2.137 18.72 79.943 ;
        RECT  15.9 2.137 16.02 79.943 ;
        RECT  13.2 2.137 13.32 79.943 ;
        RECT  10.5 2.137 10.62 79.943 ;
        RECT  7.8 2.137 7.92 79.943 ;
        RECT  5.1 2.137 5.22 79.943 ;
        RECT  2.4 2.137 2.52 79.943 ;
    END
  END VSS
  # OT_OBS_CLOSED layer=M5 d_um=1.536 added=26
  OBS
    LAYER RVTN ;
     RECT  2.16 2.16 19.44 2.295 ;
     RECT  2.16 2.565 19.44 2.835 ;
     RECT  2.16 3.105 19.44 3.375 ;
     RECT  2.16 3.645 19.44 3.915 ;
     RECT  2.16 4.185 19.44 4.455 ;
     RECT  2.16 4.725 19.44 4.995 ;
     RECT  2.16 5.265 19.44 5.535 ;
     RECT  2.16 5.805 19.44 6.075 ;
     RECT  2.16 6.345 19.44 6.615 ;
     RECT  2.16 6.885 19.44 7.155 ;
     RECT  2.16 7.425 19.44 7.695 ;
     RECT  2.16 7.965 19.44 8.235 ;
     RECT  2.16 8.505 19.44 8.775 ;
     RECT  2.16 9.045 19.44 9.315 ;
     RECT  2.16 9.585 19.44 9.855 ;
     RECT  2.16 10.125 19.44 10.395 ;
     RECT  2.16 10.665 19.44 10.935 ;
     RECT  2.16 11.205 19.44 11.475 ;
     RECT  2.16 11.745 19.44 12.015 ;
     RECT  2.16 12.285 19.44 12.555 ;
     RECT  2.16 12.825 19.44 13.095 ;
     RECT  2.16 13.365 19.44 13.635 ;
     RECT  2.16 13.905 19.44 14.175 ;
     RECT  2.16 14.445 19.44 14.715 ;
     RECT  2.16 14.985 19.44 15.255 ;
     RECT  2.16 15.525 19.44 15.795 ;
     RECT  2.16 16.065 19.44 16.335 ;
     RECT  2.16 16.605 19.44 16.875 ;
     RECT  2.16 17.145 19.44 17.415 ;
     RECT  2.16 17.685 19.44 17.955 ;
     RECT  2.16 18.225 19.44 18.495 ;
     RECT  2.16 18.765 19.44 19.035 ;
     RECT  2.16 19.305 19.44 19.575 ;
     RECT  2.16 19.845 19.44 20.115 ;
     RECT  2.16 20.385 19.44 20.655 ;
     RECT  2.16 20.925 19.44 21.195 ;
     RECT  2.16 21.465 19.44 21.735 ;
     RECT  2.16 22.005 19.44 22.275 ;
     RECT  2.16 22.545 19.44 22.815 ;
     RECT  2.16 23.085 19.44 23.355 ;
     RECT  2.16 23.625 19.44 23.895 ;
     RECT  2.16 24.165 19.44 24.435 ;
     RECT  2.16 24.705 19.44 24.975 ;
     RECT  2.16 25.245 19.44 25.515 ;
     RECT  2.16 25.785 19.44 26.055 ;
     RECT  2.16 26.325 19.44 26.595 ;
     RECT  2.16 26.865 19.44 27.135 ;
     RECT  2.16 27.405 19.44 27.675 ;
     RECT  2.16 27.945 19.44 28.215 ;
     RECT  2.16 28.485 19.44 28.755 ;
     RECT  2.16 29.025 19.44 29.295 ;
     RECT  2.16 29.565 19.44 29.835 ;
     RECT  2.16 30.105 19.44 30.375 ;
     RECT  2.16 30.645 19.44 30.915 ;
     RECT  2.16 31.185 19.44 31.455 ;
     RECT  2.16 31.725 19.44 31.995 ;
     RECT  2.16 32.265 19.44 32.535 ;
     RECT  2.16 32.805 19.44 33.075 ;
     RECT  2.16 33.345 19.44 33.615 ;
     RECT  2.16 33.885 19.44 34.155 ;
     RECT  2.16 34.425 19.44 34.695 ;
     RECT  2.16 34.965 19.44 35.235 ;
     RECT  2.16 35.505 19.44 35.775 ;
     RECT  2.16 36.045 19.44 36.315 ;
     RECT  2.16 36.585 19.44 36.855 ;
     RECT  2.16 37.125 19.44 37.395 ;
     RECT  2.16 37.665 19.44 37.935 ;
     RECT  2.16 38.205 19.44 38.475 ;
     RECT  2.16 38.745 19.44 39.015 ;
     RECT  2.16 39.285 19.44 39.555 ;
     RECT  2.16 39.825 19.44 40.095 ;
     RECT  2.16 40.365 19.44 40.635 ;
     RECT  2.16 40.905 19.44 41.175 ;
     RECT  2.16 41.445 19.44 41.715 ;
     RECT  2.16 41.985 19.44 42.255 ;
     RECT  2.16 42.525 19.44 42.795 ;
     RECT  2.16 43.065 19.44 43.335 ;
     RECT  2.16 43.605 19.44 43.875 ;
     RECT  2.16 44.145 19.44 44.415 ;
     RECT  2.16 44.685 19.44 44.955 ;
     RECT  2.16 45.225 19.44 45.495 ;
     RECT  2.16 45.765 19.44 46.035 ;
     RECT  2.16 46.305 19.44 46.575 ;
     RECT  2.16 46.845 19.44 47.115 ;
     RECT  2.16 47.385 19.44 47.655 ;
     RECT  2.16 47.925 19.44 48.195 ;
     RECT  2.16 48.465 19.44 48.735 ;
     RECT  2.16 49.005 19.44 49.275 ;
     RECT  2.16 49.545 19.44 49.815 ;
     RECT  2.16 50.085 19.44 50.355 ;
     RECT  2.16 50.625 19.44 50.895 ;
     RECT  2.16 51.165 19.44 51.435 ;
     RECT  2.16 51.705 19.44 51.975 ;
     RECT  2.16 52.245 19.44 52.515 ;
     RECT  2.16 52.785 19.44 53.055 ;
     RECT  2.16 53.325 19.44 53.595 ;
     RECT  2.16 53.865 19.44 54.135 ;
     RECT  2.16 54.405 19.44 54.675 ;
     RECT  2.16 54.945 19.44 55.215 ;
     RECT  2.16 55.485 19.44 55.755 ;
     RECT  2.16 56.025 19.44 56.295 ;
     RECT  2.16 56.565 19.44 56.835 ;
     RECT  2.16 57.105 19.44 57.375 ;
     RECT  2.16 57.645 19.44 57.915 ;
     RECT  2.16 58.185 19.44 58.455 ;
     RECT  2.16 58.725 19.44 58.995 ;
     RECT  2.16 59.265 19.44 59.535 ;
     RECT  2.16 59.805 19.44 60.075 ;
     RECT  2.16 60.345 19.44 60.615 ;
     RECT  2.16 60.885 19.44 61.155 ;
     RECT  2.16 61.425 19.44 61.695 ;
     RECT  2.16 61.965 19.44 62.235 ;
     RECT  2.16 62.505 19.44 62.775 ;
     RECT  2.16 63.045 19.44 63.315 ;
     RECT  2.16 63.585 19.44 63.855 ;
     RECT  2.16 64.125 19.44 64.395 ;
     RECT  2.16 64.665 19.44 64.935 ;
     RECT  2.16 65.205 19.44 65.475 ;
     RECT  2.16 65.745 19.44 66.015 ;
     RECT  2.16 66.285 19.44 66.555 ;
     RECT  2.16 66.825 19.44 67.095 ;
     RECT  2.16 67.365 19.44 67.635 ;
     RECT  2.16 67.905 19.44 68.175 ;
     RECT  2.16 68.445 19.44 68.715 ;
     RECT  2.16 68.985 19.44 69.255 ;
     RECT  2.16 69.525 19.44 69.795 ;
     RECT  2.16 70.065 19.44 70.335 ;
     RECT  2.16 70.605 19.44 70.875 ;
     RECT  2.16 71.145 19.44 71.415 ;
     RECT  2.16 71.685 19.44 71.955 ;
     RECT  2.16 72.225 19.44 72.495 ;
     RECT  2.16 72.765 19.44 73.035 ;
     RECT  2.16 73.305 19.44 73.575 ;
     RECT  2.16 73.845 19.44 74.115 ;
     RECT  2.16 74.385 19.44 74.655 ;
     RECT  2.16 74.925 19.44 75.195 ;
     RECT  2.16 75.465 19.44 75.735 ;
     RECT  2.16 76.005 19.44 76.275 ;
     RECT  2.16 76.545 19.44 76.815 ;
     RECT  2.16 77.085 19.44 77.355 ;
     RECT  2.16 77.625 19.44 77.895 ;
     RECT  2.16 78.165 19.44 78.435 ;
     RECT  2.16 78.705 19.44 78.975 ;
     RECT  2.16 79.245 19.44 79.515 ;
     RECT  2.16 79.785 19.44 79.92 ;
    LAYER RVTP ;
     RECT  2.16 2.295 19.44 2.565 ;
     RECT  2.16 2.835 19.44 3.105 ;
     RECT  2.16 3.375 19.44 3.645 ;
     RECT  2.16 3.915 19.44 4.185 ;
     RECT  2.16 4.455 19.44 4.725 ;
     RECT  2.16 4.995 19.44 5.265 ;
     RECT  2.16 5.535 19.44 5.805 ;
     RECT  2.16 6.075 19.44 6.345 ;
     RECT  2.16 6.615 19.44 6.885 ;
     RECT  2.16 7.155 19.44 7.425 ;
     RECT  2.16 7.695 19.44 7.965 ;
     RECT  2.16 8.235 19.44 8.505 ;
     RECT  2.16 8.775 19.44 9.045 ;
     RECT  2.16 9.315 19.44 9.585 ;
     RECT  2.16 9.855 19.44 10.125 ;
     RECT  2.16 10.395 19.44 10.665 ;
     RECT  2.16 10.935 19.44 11.205 ;
     RECT  2.16 11.475 19.44 11.745 ;
     RECT  2.16 12.015 19.44 12.285 ;
     RECT  2.16 12.555 19.44 12.825 ;
     RECT  2.16 13.095 19.44 13.365 ;
     RECT  2.16 13.635 19.44 13.905 ;
     RECT  2.16 14.175 19.44 14.445 ;
     RECT  2.16 14.715 19.44 14.985 ;
     RECT  2.16 15.255 19.44 15.525 ;
     RECT  2.16 15.795 19.44 16.065 ;
     RECT  2.16 16.335 19.44 16.605 ;
     RECT  2.16 16.875 19.44 17.145 ;
     RECT  2.16 17.415 19.44 17.685 ;
     RECT  2.16 17.955 19.44 18.225 ;
     RECT  2.16 18.495 19.44 18.765 ;
     RECT  2.16 19.035 19.44 19.305 ;
     RECT  2.16 19.575 19.44 19.845 ;
     RECT  2.16 20.115 19.44 20.385 ;
     RECT  2.16 20.655 19.44 20.925 ;
     RECT  2.16 21.195 19.44 21.465 ;
     RECT  2.16 21.735 19.44 22.005 ;
     RECT  2.16 22.275 19.44 22.545 ;
     RECT  2.16 22.815 19.44 23.085 ;
     RECT  2.16 23.355 19.44 23.625 ;
     RECT  2.16 23.895 19.44 24.165 ;
     RECT  2.16 24.435 19.44 24.705 ;
     RECT  2.16 24.975 19.44 25.245 ;
     RECT  2.16 25.515 19.44 25.785 ;
     RECT  2.16 26.055 19.44 26.325 ;
     RECT  2.16 26.595 19.44 26.865 ;
     RECT  2.16 27.135 19.44 27.405 ;
     RECT  2.16 27.675 19.44 27.945 ;
     RECT  2.16 28.215 19.44 28.485 ;
     RECT  2.16 28.755 19.44 29.025 ;
     RECT  2.16 29.295 19.44 29.565 ;
     RECT  2.16 29.835 19.44 30.105 ;
     RECT  2.16 30.375 19.44 30.645 ;
     RECT  2.16 30.915 19.44 31.185 ;
     RECT  2.16 31.455 19.44 31.725 ;
     RECT  2.16 31.995 19.44 32.265 ;
     RECT  2.16 32.535 19.44 32.805 ;
     RECT  2.16 33.075 19.44 33.345 ;
     RECT  2.16 33.615 19.44 33.885 ;
     RECT  2.16 34.155 19.44 34.425 ;
     RECT  2.16 34.695 19.44 34.965 ;
     RECT  2.16 35.235 19.44 35.505 ;
     RECT  2.16 35.775 19.44 36.045 ;
     RECT  2.16 36.315 19.44 36.585 ;
     RECT  2.16 36.855 19.44 37.125 ;
     RECT  2.16 37.395 19.44 37.665 ;
     RECT  2.16 37.935 19.44 38.205 ;
     RECT  2.16 38.475 19.44 38.745 ;
     RECT  2.16 39.015 19.44 39.285 ;
     RECT  2.16 39.555 19.44 39.825 ;
     RECT  2.16 40.095 19.44 40.365 ;
     RECT  2.16 40.635 19.44 40.905 ;
     RECT  2.16 41.175 19.44 41.445 ;
     RECT  2.16 41.715 19.44 41.985 ;
     RECT  2.16 42.255 19.44 42.525 ;
     RECT  2.16 42.795 19.44 43.065 ;
     RECT  2.16 43.335 19.44 43.605 ;
     RECT  2.16 43.875 19.44 44.145 ;
     RECT  2.16 44.415 19.44 44.685 ;
     RECT  2.16 44.955 19.44 45.225 ;
     RECT  2.16 45.495 19.44 45.765 ;
     RECT  2.16 46.035 19.44 46.305 ;
     RECT  2.16 46.575 19.44 46.845 ;
     RECT  2.16 47.115 19.44 47.385 ;
     RECT  2.16 47.655 19.44 47.925 ;
     RECT  2.16 48.195 19.44 48.465 ;
     RECT  2.16 48.735 19.44 49.005 ;
     RECT  2.16 49.275 19.44 49.545 ;
     RECT  2.16 49.815 19.44 50.085 ;
     RECT  2.16 50.355 19.44 50.625 ;
     RECT  2.16 50.895 19.44 51.165 ;
     RECT  2.16 51.435 19.44 51.705 ;
     RECT  2.16 51.975 19.44 52.245 ;
     RECT  2.16 52.515 19.44 52.785 ;
     RECT  2.16 53.055 19.44 53.325 ;
     RECT  2.16 53.595 19.44 53.865 ;
     RECT  2.16 54.135 19.44 54.405 ;
     RECT  2.16 54.675 19.44 54.945 ;
     RECT  2.16 55.215 19.44 55.485 ;
     RECT  2.16 55.755 19.44 56.025 ;
     RECT  2.16 56.295 19.44 56.565 ;
     RECT  2.16 56.835 19.44 57.105 ;
     RECT  2.16 57.375 19.44 57.645 ;
     RECT  2.16 57.915 19.44 58.185 ;
     RECT  2.16 58.455 19.44 58.725 ;
     RECT  2.16 58.995 19.44 59.265 ;
     RECT  2.16 59.535 19.44 59.805 ;
     RECT  2.16 60.075 19.44 60.345 ;
     RECT  2.16 60.615 19.44 60.885 ;
     RECT  2.16 61.155 19.44 61.425 ;
     RECT  2.16 61.695 19.44 61.965 ;
     RECT  2.16 62.235 19.44 62.505 ;
     RECT  2.16 62.775 19.44 63.045 ;
     RECT  2.16 63.315 19.44 63.585 ;
     RECT  2.16 63.855 19.44 64.125 ;
     RECT  2.16 64.395 19.44 64.665 ;
     RECT  2.16 64.935 19.44 65.205 ;
     RECT  2.16 65.475 19.44 65.745 ;
     RECT  2.16 66.015 19.44 66.285 ;
     RECT  2.16 66.555 19.44 66.825 ;
     RECT  2.16 67.095 19.44 67.365 ;
     RECT  2.16 67.635 19.44 67.905 ;
     RECT  2.16 68.175 19.44 68.445 ;
     RECT  2.16 68.715 19.44 68.985 ;
     RECT  2.16 69.255 19.44 69.525 ;
     RECT  2.16 69.795 19.44 70.065 ;
     RECT  2.16 70.335 19.44 70.605 ;
     RECT  2.16 70.875 19.44 71.145 ;
     RECT  2.16 71.415 19.44 71.685 ;
     RECT  2.16 71.955 19.44 72.225 ;
     RECT  2.16 72.495 19.44 72.765 ;
     RECT  2.16 73.035 19.44 73.305 ;
     RECT  2.16 73.575 19.44 73.845 ;
     RECT  2.16 74.115 19.44 74.385 ;
     RECT  2.16 74.655 19.44 74.925 ;
     RECT  2.16 75.195 19.44 75.465 ;
     RECT  2.16 75.735 19.44 76.005 ;
     RECT  2.16 76.275 19.44 76.545 ;
     RECT  2.16 76.815 19.44 77.085 ;
     RECT  2.16 77.355 19.44 77.625 ;
     RECT  2.16 77.895 19.44 78.165 ;
     RECT  2.16 78.435 19.44 78.705 ;
     RECT  2.16 78.975 19.44 79.245 ;
     RECT  2.16 79.515 19.44 79.785 ;
    LAYER M1 ;
     RECT  2.16 2.151 19.44 79.929 ;
    LAYER M2 ;
     RECT  0.031 78.408 0.131 78.696 ;
     RECT  0.131 78.408 1.399 78.426 ;
     RECT  1.435 23.904 1.471 23.922 ;
     RECT  1.435 66.366 1.471 66.384 ;
     RECT  0.535 18.198 1.579 18.216 ;
     RECT  1.543 70.416 1.579 70.434 ;
     RECT  1.579 18.036 1.615 18.216 ;
     RECT  1.471 23.67 1.651 23.922 ;
     RECT  1.651 5.274 1.687 5.292 ;
     RECT  1.543 19.116 1.903 19.134 ;
     RECT  1.507 65.016 1.903 65.034 ;
     RECT  1.903 19.116 1.939 19.872 ;
     RECT  0.103 69.498 1.939 69.516 ;
     RECT  1.579 70.416 1.939 70.974 ;
     RECT  1.939 14.76 2.011 14.859 ;
     RECT  1.975 72.036 2.011 72.054 ;
     RECT  1.939 10.836 2.047 10.854 ;
     RECT  0.103 12.528 2.047 12.546 ;
     RECT  2.047 10.836 2.083 10.926 ;
     RECT  0.535 75.204 2.083 75.222 ;
     RECT  1.687 5.076 2.119 5.292 ;
     RECT  2.047 8.676 2.119 8.694 ;
     RECT  0.103 27.342 2.119 27.36 ;
     RECT  1.903 34.326 2.119 34.344 ;
     RECT  1.903 37.134 2.119 37.152 ;
     RECT  1.903 46.206 2.119 46.764 ;
     RECT  1.903 49.896 2.119 49.914 ;
     RECT  1.903 52.686 2.119 52.704 ;
     RECT  1.903 57.006 2.119 57.024 ;
     RECT  1.939 69.498 2.119 70.974 ;
     RECT  2.083 74.736 2.119 75.222 ;
     RECT  2.083 10.134 2.155 10.926 ;
     RECT  2.047 76.446 2.155 76.464 ;
     RECT  2.119 4.806 2.16 5.292 ;
     RECT  0.103 7.902 2.16 7.92 ;
     RECT  2.119 8.676 2.16 8.766 ;
     RECT  2.155 10.134 2.16 11.268 ;
     RECT  2.047 12.024 2.16 12.546 ;
     RECT  2.011 14.76 2.16 15.588 ;
     RECT  1.975 16.686 2.16 16.704 ;
     RECT  1.615 17.496 2.16 18.216 ;
     RECT  1.939 19.116 2.16 20.214 ;
     RECT  1.507 21.006 2.16 21.024 ;
     RECT  1.651 23.634 2.16 23.994 ;
     RECT  2.119 26.766 2.16 27.36 ;
     RECT  2.119 33.048 2.16 33.066 ;
     RECT  2.119 34.236 2.16 34.344 ;
     RECT  2.119 37.134 2.16 37.224 ;
     RECT  0.103 40.41 2.16 40.428 ;
     RECT  2.119 42.696 2.16 42.786 ;
     RECT  2.119 46.116 2.16 46.836 ;
     RECT  2.119 49.824 2.16 49.914 ;
     RECT  2.119 50.832 2.16 50.85 ;
     RECT  2.119 52.596 2.16 52.704 ;
     RECT  0.103 53.568 2.16 54.09 ;
     RECT  2.119 57.006 2.16 57.096 ;
     RECT  1.939 63.396 2.16 63.414 ;
     RECT  1.903 65.016 2.16 65.538 ;
     RECT  1.471 66.366 2.16 66.852 ;
     RECT  0.535 68.256 2.16 68.274 ;
     RECT  2.119 69.03 2.16 70.974 ;
     RECT  2.011 72.036 2.16 72.558 ;
     RECT  1.651 73.314 2.16 73.332 ;
     RECT  2.119 74.736 2.16 75.528 ;
     RECT  2.155 76.446 2.16 76.644 ;
     RECT  1.399 78.21 2.16 78.426 ;
     RECT  2.16 2.151 11.767 79.929 ;
     RECT  11.767 1.998 15.475 79.929 ;
     RECT  15.475 1.881 16.447 79.929 ;
     RECT  16.447 1.836 18.815 79.929 ;
     RECT  18.815 1.881 18.995 79.929 ;
     RECT  18.995 1.926 19.44 79.929 ;
     RECT  19.44 3.384 19.679 33.03 ;
     RECT  19.679 3.384 19.787 32.796 ;
     RECT  19.787 3.384 19.823 30.744 ;
     RECT  19.44 74.124 19.859 79.614 ;
     RECT  19.44 43.92 19.895 73.332 ;
     RECT  19.44 1.926 19.931 2.628 ;
     RECT  19.823 24.714 19.931 30.744 ;
     RECT  19.787 31.536 19.931 32.796 ;
     RECT  19.44 33.894 19.931 43.164 ;
     RECT  19.931 24.714 19.967 30.474 ;
     RECT  19.895 43.92 19.967 73.224 ;
     RECT  19.931 33.894 20.111 39.924 ;
     RECT  19.967 43.92 20.147 63.954 ;
     RECT  19.823 3.384 20.219 23.922 ;
     RECT  20.219 3.384 20.435 23.076 ;
     RECT  19.931 31.698 20.443 32.796 ;
     RECT  20.435 3.384 20.471 6.534 ;
     RECT  20.435 7.506 20.471 23.076 ;
     RECT  20.147 56.268 20.471 63.954 ;
     RECT  20.471 3.384 20.507 6.444 ;
     RECT  20.471 10.206 20.507 23.076 ;
     RECT  19.967 28.656 20.507 30.438 ;
     RECT  20.111 33.894 20.507 36.954 ;
     RECT  19.931 40.716 20.507 43.164 ;
     RECT  20.147 43.92 20.507 55.512 ;
     RECT  20.471 57.816 20.507 63.954 ;
     RECT  19.967 64.71 20.507 73.224 ;
     RECT  19.859 74.124 20.507 79.434 ;
     RECT  20.507 4.806 20.543 6.444 ;
     RECT  20.471 7.506 20.543 9.414 ;
     RECT  20.507 10.206 20.543 12.888 ;
     RECT  20.507 15.57 20.543 19.566 ;
     RECT  20.507 20.358 20.543 23.076 ;
     RECT  20.219 23.868 20.543 23.922 ;
     RECT  19.967 24.714 20.543 26.154 ;
     RECT  20.507 28.764 20.543 30.438 ;
     RECT  20.443 31.698 20.543 33.066 ;
     RECT  20.507 33.966 20.543 36.954 ;
     RECT  20.111 37.746 20.543 39.924 ;
     RECT  20.507 43.92 20.543 45.288 ;
     RECT  20.507 46.044 20.543 47.646 ;
     RECT  20.507 48.438 20.543 49.914 ;
     RECT  20.507 50.976 20.543 51.534 ;
     RECT  20.507 52.326 20.543 55.512 ;
     RECT  20.471 56.268 20.543 56.979 ;
     RECT  20.507 58.806 20.543 63.954 ;
     RECT  20.507 64.71 20.543 65.772 ;
     RECT  20.507 66.636 20.543 72.792 ;
     RECT  20.507 74.124 20.543 76.644 ;
     RECT  19.931 2.034 20.579 2.628 ;
     RECT  20.543 15.57 20.579 18.288 ;
     RECT  20.543 22.014 20.579 23.076 ;
     RECT  19.967 26.91 20.579 27.702 ;
     RECT  20.543 30.186 20.579 30.438 ;
     RECT  20.543 31.698 20.579 32.094 ;
     RECT  20.543 74.196 20.579 76.644 ;
     RECT  20.543 12.87 20.615 12.888 ;
     RECT  20.543 58.806 20.615 62.73 ;
     RECT  20.615 58.806 20.651 60.948 ;
     RECT  20.615 62.712 20.651 62.73 ;
     RECT  20.543 68.22 20.651 72.792 ;
     RECT  20.507 57.996 20.687 58.014 ;
     RECT  20.651 58.806 20.687 60.138 ;
     RECT  20.579 16.308 20.723 18.288 ;
     RECT  20.507 41.418 20.723 43.128 ;
     RECT  20.543 56.961 20.723 56.979 ;
     RECT  20.543 46.044 20.795 47.412 ;
     RECT  20.651 70.848 21.371 72.792 ;
     RECT  20.543 4.806 21.407 5.904 ;
     RECT  20.507 77.706 21.407 79.434 ;
     RECT  21.407 4.806 21.443 5.868 ;
     RECT  20.543 10.206 21.443 11.772 ;
     RECT  20.543 67.302 21.443 67.464 ;
     RECT  21.407 77.706 21.443 78.534 ;
     RECT  20.507 3.384 21.479 3.708 ;
     RECT  21.443 4.806 21.479 4.986 ;
     RECT  21.443 5.85 21.479 5.868 ;
     RECT  21.443 10.206 21.479 10.998 ;
     RECT  20.723 16.308 21.479 16.362 ;
     RECT  20.543 20.358 21.479 20.754 ;
     RECT  20.579 22.014 21.479 22.734 ;
     RECT  20.543 24.714 21.479 25.776 ;
     RECT  20.543 33.966 21.479 36.342 ;
     RECT  20.723 41.418 21.479 42.318 ;
     RECT  20.795 46.044 21.479 46.602 ;
     RECT  20.543 54.18 21.479 55.404 ;
     RECT  21.371 70.848 21.479 72.018 ;
     RECT  21.407 79.416 21.479 79.434 ;
     RECT  20.579 2.034 21.515 2.484 ;
     RECT  21.479 3.69 21.515 3.708 ;
     RECT  21.479 4.806 21.515 4.824 ;
     RECT  20.543 7.506 21.515 8.838 ;
     RECT  21.479 10.404 21.515 10.926 ;
     RECT  21.443 11.754 21.515 11.772 ;
     RECT  20.507 13.644 21.515 14.814 ;
     RECT  21.479 16.344 21.515 16.362 ;
     RECT  20.723 17.496 21.515 18.288 ;
     RECT  20.543 19.386 21.515 19.404 ;
     RECT  21.479 20.358 21.515 20.646 ;
     RECT  21.479 22.014 21.515 22.032 ;
     RECT  20.543 23.868 21.515 23.886 ;
     RECT  21.479 24.714 21.515 24.732 ;
     RECT  21.479 25.758 21.515 25.776 ;
     RECT  20.579 26.91 21.515 27.198 ;
     RECT  20.579 30.42 21.515 30.438 ;
     RECT  20.579 31.734 21.515 32.094 ;
     RECT  21.479 33.966 21.515 36.108 ;
     RECT  20.543 37.98 21.515 39.852 ;
     RECT  21.479 41.418 21.515 42.084 ;
     RECT  20.723 43.11 21.515 43.128 ;
     RECT  20.543 44.388 21.515 44.874 ;
     RECT  21.479 46.206 21.515 46.602 ;
     RECT  20.543 48.978 21.515 49.302 ;
     RECT  20.543 50.976 21.515 50.994 ;
     RECT  20.543 53.136 21.515 53.154 ;
     RECT  21.479 54.18 21.515 54.198 ;
     RECT  21.479 55.386 21.515 55.404 ;
     RECT  20.687 59.076 21.515 60.138 ;
     RECT  20.651 60.93 21.515 60.948 ;
     RECT  20.543 63.63 21.515 63.648 ;
     RECT  20.543 64.746 21.515 65.772 ;
     RECT  21.443 67.446 21.515 67.464 ;
     RECT  20.651 68.22 21.515 69.588 ;
     RECT  21.479 70.848 21.515 70.866 ;
     RECT  21.479 71.766 21.515 71.784 ;
     RECT  21.371 72.774 21.515 72.792 ;
     RECT  20.579 74.196 21.515 76.068 ;
     RECT  21.443 77.94 21.515 77.958 ;
    LAYER M3 ;
     RECT  15.444 0.715 15.462 1.003 ;
     RECT  21.492 0.859 21.51 1.147 ;
     RECT  21.456 1.147 21.51 1.291 ;
     RECT  21.42 1.291 21.51 1.435 ;
     RECT  15.444 1.003 16.074 1.831 ;
     RECT  17.064 1.579 17.082 1.831 ;
     RECT  19.908 1.723 19.926 1.867 ;
     RECT  15.444 1.831 17.082 1.876 ;
     RECT  18.792 1.831 18.81 1.876 ;
     RECT  19.908 1.867 20.502 1.949 ;
     RECT  15.444 1.876 17.622 1.957 ;
     RECT  18.792 1.876 18.99 1.957 ;
     RECT  11.772 1.993 11.79 2.029 ;
     RECT  11.772 2.029 11.826 2.219 ;
     RECT  15.444 1.957 19.134 2.299 ;
     RECT  15.444 2.299 19.386 2.363 ;
     RECT  21.384 1.435 21.51 2.399 ;
     RECT  2.415 2.143 2.505 2.413 ;
     RECT  5.115 2.143 5.205 2.413 ;
     RECT  7.815 2.143 7.905 2.413 ;
     RECT  10.515 2.143 10.605 2.413 ;
     RECT  13.215 2.143 13.305 2.413 ;
     RECT  21.456 2.399 21.51 2.489 ;
     RECT  15.444 2.363 19.134 2.605 ;
     RECT  20.484 1.949 20.502 2.605 ;
     RECT  20.484 2.605 20.574 2.765 ;
     RECT  2.415 2.413 2.697 3.019 ;
     RECT  21.456 2.489 21.474 3.163 ;
     RECT  3.996 3.001 4.014 3.181 ;
     RECT  10.515 2.413 10.797 3.271 ;
     RECT  11.772 2.219 11.79 3.271 ;
     RECT  2.304 3.019 2.697 3.307 ;
     RECT  15.264 2.605 19.134 3.307 ;
     RECT  3.78 3.181 4.266 3.343 ;
     RECT  5.115 2.413 5.397 3.343 ;
     RECT  2.304 3.307 2.754 3.451 ;
     RECT  21.42 3.163 21.474 3.451 ;
     RECT  13.215 2.413 13.497 3.541 ;
     RECT  15.264 3.307 19.386 3.541 ;
     RECT  14.832 3.541 19.386 3.595 ;
     RECT  20.484 2.765 20.502 3.595 ;
     RECT  3.78 3.343 5.397 3.685 ;
     RECT  9.468 2.191 9.486 3.685 ;
     RECT  21.42 3.451 21.51 3.713 ;
     RECT  2.304 3.451 3.006 3.721 ;
     RECT  3.78 3.685 5.814 3.721 ;
     RECT  10.515 3.271 11.79 3.883 ;
     RECT  2.304 3.721 5.814 4.081 ;
     RECT  6.768 3.721 7.038 4.081 ;
     RECT  2.304 4.081 7.038 4.253 ;
     RECT  10.515 3.883 12.294 4.261 ;
     RECT  13.215 3.541 13.878 4.351 ;
     RECT  13.104 4.351 13.878 4.397 ;
     RECT  8.928 3.685 9.486 4.459 ;
     RECT  8.928 4.459 9.63 4.531 ;
     RECT  10.515 4.261 12.366 4.531 ;
     RECT  13.215 4.397 13.878 4.621 ;
     RECT  13.215 4.621 13.986 4.729 ;
     RECT  14.832 3.595 20.502 4.729 ;
     RECT  21.42 3.713 21.438 4.747 ;
     RECT  13.215 4.729 20.502 4.757 ;
     RECT  2.304 4.253 6.894 4.801 ;
     RECT  7.815 2.413 8.097 4.801 ;
     RECT  21.42 4.747 21.474 4.801 ;
     RECT  0.144 4.315 0.162 5.021 ;
     RECT  19.908 4.757 20.502 5.027 ;
     RECT  2.124 4.801 6.894 5.071 ;
     RECT  19.944 5.027 20.502 5.071 ;
     RECT  21.42 4.801 21.51 5.179 ;
     RECT  1.692 5.071 6.894 5.269 ;
     RECT  1.656 5.269 6.894 5.341 ;
     RECT  19.944 5.071 20.538 5.357 ;
     RECT  7.815 4.801 8.154 5.467 ;
     RECT  21.384 5.179 21.51 5.501 ;
     RECT  1.656 5.341 7.002 5.503 ;
     RECT  7.815 5.467 8.19 5.503 ;
     RECT  1.656 5.503 8.19 5.504 ;
     RECT  8.928 4.531 12.366 5.539 ;
     RECT  13.215 4.757 19.062 5.539 ;
     RECT  21.384 5.501 21.474 5.873 ;
     RECT  21.384 5.873 21.402 5.909 ;
     RECT  8.928 5.539 19.062 6.331 ;
     RECT  19.944 5.357 20.502 6.331 ;
     RECT  1.656 5.504 8.154 6.421 ;
     RECT  8.928 6.331 20.502 6.421 ;
     RECT  1.656 6.421 20.538 6.449 ;
     RECT  1.656 6.449 15.066 6.719 ;
     RECT  15.804 6.449 20.538 6.719 ;
     RECT  20.412 6.719 20.538 6.797 ;
     RECT  20.412 6.797 20.502 6.809 ;
     RECT  1.656 6.719 8.19 6.845 ;
     RECT  15.804 6.719 19.422 7.229 ;
     RECT  8.928 6.719 15.066 7.231 ;
     RECT  15.804 7.229 19.386 7.231 ;
     RECT  8.928 7.231 19.386 7.259 ;
     RECT  0.144 7.051 0.162 7.771 ;
     RECT  8.928 7.259 19.314 7.861 ;
     RECT  0.144 7.771 0.342 7.897 ;
     RECT  0.108 7.897 0.342 7.949 ;
     RECT  0.108 7.949 0.162 8.093 ;
     RECT  8.892 7.861 19.314 8.159 ;
     RECT  8.928 8.159 19.314 8.203 ;
     RECT  20.448 6.809 20.502 8.203 ;
     RECT  0.144 8.093 0.162 8.477 ;
     RECT  21.492 7.483 21.51 8.843 ;
     RECT  1.656 6.845 8.097 9.211 ;
     RECT  1.656 9.211 8.154 9.283 ;
     RECT  8.928 8.203 20.502 9.283 ;
     RECT  1.656 9.283 20.502 9.391 ;
     RECT  1.656 9.391 20.538 9.533 ;
     RECT  1.656 9.533 20.466 9.779 ;
     RECT  21.492 9.787 21.51 9.931 ;
     RECT  21.456 9.931 21.51 10.219 ;
     RECT  1.656 9.779 19.926 10.319 ;
     RECT  1.656 10.319 19.386 10.697 ;
     RECT  0.144 10.123 0.162 10.829 ;
     RECT  20.484 11.083 20.502 11.173 ;
     RECT  21.42 10.219 21.51 11.237 ;
     RECT  1.656 10.697 19.098 11.515 ;
     RECT  21.492 11.237 21.51 11.777 ;
     RECT  1.656 11.515 19.386 12.289 ;
     RECT  20.484 11.173 20.538 12.289 ;
     RECT  0.108 12.523 0.126 12.56 ;
     RECT  1.656 12.289 20.538 12.701 ;
     RECT  20.484 12.701 20.538 12.865 ;
     RECT  0.144 13.531 0.162 13.661 ;
     RECT  1.656 12.701 19.422 13.675 ;
     RECT  20.484 12.865 20.61 13.675 ;
     RECT  1.656 13.675 20.61 14.521 ;
     RECT  21.492 13.531 21.51 14.819 ;
     RECT  1.656 14.521 20.682 15.251 ;
     RECT  20.448 15.251 20.682 15.719 ;
     RECT  20.52 15.719 20.682 16.267 ;
     RECT  21.492 15.979 21.51 16.267 ;
     RECT  20.52 16.267 21.51 16.367 ;
     RECT  20.52 16.367 21.33 16.445 ;
     RECT  20.52 16.445 20.718 16.681 ;
     RECT  1.656 15.251 19.638 16.915 ;
     RECT  20.448 16.681 20.718 16.915 ;
     RECT  1.656 16.915 20.718 17.491 ;
     RECT  1.62 17.491 20.718 18.031 ;
     RECT  21.492 17.275 21.51 18.293 ;
     RECT  0.54 18.193 0.558 18.317 ;
     RECT  1.584 18.031 20.718 18.317 ;
     RECT  1.584 18.317 19.638 19.111 ;
     RECT  1.548 19.111 19.638 19.339 ;
     RECT  20.448 18.317 20.718 19.339 ;
     RECT  21.492 19.291 21.51 20.587 ;
     RECT  21.456 20.587 21.51 20.651 ;
     RECT  21.456 20.651 21.474 20.759 ;
     RECT  1.548 19.339 20.718 21.001 ;
     RECT  0.144 20.347 0.162 21.053 ;
     RECT  21.492 21.739 21.51 21.883 ;
     RECT  21.456 21.883 21.51 22.037 ;
     RECT  21.456 22.037 21.474 22.739 ;
     RECT  1.512 21.001 20.718 23.665 ;
     RECT  21.492 23.755 21.51 23.891 ;
     RECT  1.476 23.665 20.718 23.899 ;
     RECT  21.492 24.619 21.51 24.737 ;
     RECT  1.44 23.899 20.718 25.096 ;
     RECT  21.456 24.763 21.474 25.096 ;
     RECT  1.44 25.096 21.474 25.753 ;
     RECT  1.44 25.753 21.51 25.805 ;
     RECT  1.44 25.805 20.79 26.905 ;
     RECT  1.44 26.905 21.51 27.245 ;
     RECT  0.108 27.337 0.126 27.389 ;
     RECT  1.44 27.245 20.79 30.379 ;
     RECT  1.44 30.379 21.51 30.443 ;
     RECT  1.44 30.443 20.79 31.531 ;
     RECT  1.44 31.531 21.51 32.099 ;
     RECT  0.144 31.147 0.162 32.429 ;
     RECT  1.44 32.099 20.79 33.547 ;
     RECT  0.144 35.131 0.162 35.261 ;
     RECT  1.44 33.547 21.51 35.261 ;
     RECT  21.456 35.261 21.51 35.267 ;
     RECT  21.492 35.267 21.51 36.113 ;
     RECT  21.456 36.139 21.474 36.347 ;
     RECT  0.144 38.587 0.162 38.717 ;
     RECT  21.492 37.723 21.51 39.857 ;
     RECT  0.108 40.405 0.126 40.493 ;
     RECT  21.492 40.891 21.51 42.043 ;
     RECT  0.144 41.947 0.162 42.077 ;
     RECT  21.456 42.043 21.51 42.089 ;
     RECT  21.456 42.089 21.474 42.323 ;
     RECT  21.492 42.907 21.51 43.133 ;
     RECT  0.144 43.195 0.162 43.325 ;
     RECT  21.492 44.059 21.51 44.879 ;
     RECT  21.492 45.643 21.51 45.787 ;
     RECT  1.44 35.261 20.718 45.931 ;
     RECT  21.456 45.787 21.51 45.931 ;
     RECT  1.44 45.931 21.51 46.607 ;
     RECT  1.44 46.607 20.79 47.417 ;
     RECT  0.144 48.091 0.162 48.221 ;
     RECT  21.492 48.667 21.51 49.307 ;
     RECT  21.492 50.827 21.51 50.999 ;
     RECT  0.144 51.739 0.162 52.253 ;
     RECT  21.492 53.131 21.51 53.168 ;
     RECT  0.108 53.563 0.126 54.173 ;
     RECT  1.44 47.417 20.718 54.427 ;
     RECT  21.492 54.139 21.51 54.427 ;
     RECT  1.44 54.427 21.51 54.653 ;
     RECT  21.456 54.653 21.51 54.752 ;
     RECT  21.492 54.752 21.51 55.409 ;
     RECT  1.44 54.653 20.718 56.299 ;
     RECT  1.44 56.299 21.438 56.429 ;
     RECT  1.44 56.429 20.718 56.984 ;
     RECT  1.44 56.984 20.682 58.019 ;
     RECT  1.44 58.019 20.646 58.637 ;
     RECT  20.484 58.637 20.646 58.801 ;
     RECT  20.484 58.801 20.682 59.027 ;
     RECT  20.52 59.027 20.682 59.323 ;
     RECT  21.492 59.035 21.51 59.323 ;
     RECT  20.52 59.323 21.51 59.501 ;
     RECT  1.44 58.637 19.458 60.187 ;
     RECT  20.52 59.501 20.646 60.187 ;
     RECT  1.44 60.187 20.646 60.683 ;
     RECT  1.44 60.683 20.61 60.719 ;
     RECT  21.492 59.501 21.51 60.953 ;
     RECT  1.44 60.719 19.458 61.483 ;
     RECT  20.448 60.719 20.61 61.483 ;
     RECT  0.144 61.387 0.162 61.517 ;
     RECT  1.44 61.483 20.61 62.069 ;
     RECT  20.448 62.069 20.61 62.707 ;
     RECT  1.44 62.069 19.494 62.923 ;
     RECT  20.448 62.707 20.646 62.923 ;
     RECT  21.492 63.355 21.51 63.653 ;
     RECT  21.42 64.219 21.438 64.349 ;
     RECT  21.492 64.651 21.51 65.777 ;
     RECT  1.44 62.923 20.646 66.389 ;
     RECT  1.476 66.389 20.646 66.857 ;
     RECT  21.42 67.243 21.438 67.325 ;
     RECT  1.548 66.857 20.646 67.853 ;
     RECT  20.448 67.853 20.646 67.973 ;
     RECT  1.548 67.853 19.458 68.099 ;
     RECT  1.548 68.099 10.998 68.369 ;
     RECT  0.54 68.251 0.558 68.429 ;
     RECT  1.548 68.369 10.962 68.441 ;
     RECT  20.484 67.973 20.646 68.513 ;
     RECT  21.492 67.441 21.51 69.115 ;
     RECT  21.456 69.115 21.51 69.287 ;
     RECT  1.548 68.441 10.89 69.547 ;
     RECT  13.215 68.099 19.458 69.547 ;
     RECT  20.556 68.513 20.646 69.547 ;
     RECT  21.492 69.287 21.51 69.593 ;
     RECT  0.108 69.493 0.126 69.725 ;
     RECT  1.548 69.547 10.998 69.871 ;
     RECT  11.88 68.099 12.402 69.871 ;
     RECT  13.215 69.547 20.646 70.133 ;
     RECT  1.548 69.871 12.402 70.169 ;
     RECT  13.215 70.133 20.574 70.331 ;
     RECT  1.548 70.169 10.89 70.439 ;
     RECT  20.448 70.331 20.574 70.445 ;
     RECT  21.492 70.699 21.51 70.843 ;
     RECT  21.456 70.843 21.51 70.871 ;
     RECT  1.584 70.439 10.89 70.979 ;
     RECT  21.456 70.871 21.474 71.563 ;
     RECT  21.42 71.563 21.474 71.707 ;
     RECT  21.384 71.707 21.474 71.761 ;
     RECT  21.384 71.761 21.51 71.851 ;
     RECT  1.656 70.979 10.89 71.959 ;
     RECT  1.656 71.959 10.926 72.329 ;
     RECT  13.215 70.331 19.494 72.427 ;
     RECT  20.484 70.445 20.574 72.427 ;
     RECT  21.348 71.851 21.51 72.563 ;
     RECT  21.492 72.563 21.51 72.797 ;
     RECT  1.656 72.329 10.89 73.337 ;
     RECT  21.492 73.579 21.51 74.011 ;
     RECT  21.456 74.011 21.51 74.417 ;
     RECT  13.215 72.427 20.574 74.489 ;
     RECT  11.88 70.169 12.402 74.579 ;
     RECT  11.88 74.579 11.898 74.759 ;
     RECT  1.692 73.337 10.89 75.119 ;
     RECT  0.54 75.199 0.558 75.341 ;
     RECT  15.876 74.489 20.574 75.731 ;
     RECT  13.215 74.489 15.066 75.839 ;
     RECT  20.196 75.731 20.574 75.929 ;
     RECT  21.492 74.417 21.51 76.073 ;
     RECT  14.616 75.839 15.066 76.109 ;
     RECT  14.616 76.109 14.634 76.343 ;
     RECT  15.876 75.731 19.026 76.549 ;
     RECT  20.484 75.929 20.574 76.649 ;
     RECT  10.296 75.119 10.89 76.739 ;
     RECT  15.876 76.549 19.422 76.781 ;
     RECT  20.484 76.649 20.502 76.891 ;
     RECT  15.876 76.781 19.062 77.117 ;
     RECT  19.908 76.891 20.502 77.189 ;
     RECT  21.492 77.035 21.51 77.323 ;
     RECT  14.832 76.987 14.85 77.423 ;
     RECT  21.456 77.323 21.51 77.467 ;
     RECT  0.144 77.371 0.162 77.501 ;
     RECT  19.908 77.189 19.926 77.611 ;
     RECT  21.42 77.467 21.51 77.755 ;
     RECT  21.384 77.755 21.51 77.963 ;
     RECT  19.872 77.611 19.926 77.971 ;
     RECT  21.384 77.963 21.474 78.187 ;
     RECT  1.692 75.119 9.558 78.205 ;
     RECT  15.876 77.117 19.026 78.205 ;
     RECT  1.404 78.205 9.558 78.269 ;
     RECT  19.872 77.971 20.538 78.365 ;
     RECT  19.872 78.365 20.502 78.475 ;
     RECT  2.268 78.269 9.558 78.512 ;
     RECT  2.304 78.512 9.558 78.539 ;
     RECT  19.836 78.475 20.502 78.629 ;
     RECT  0.036 78.403 0.054 78.667 ;
     RECT  0.036 78.667 0.162 78.701 ;
     RECT  15.876 78.205 19.062 78.763 ;
     RECT  19.836 78.629 19.926 78.763 ;
     RECT  21.312 78.187 21.474 78.773 ;
     RECT  0.108 78.701 0.162 78.797 ;
     RECT  14.832 78.667 14.85 78.797 ;
     RECT  21.384 78.773 21.474 78.809 ;
     RECT  2.304 78.539 9.486 78.899 ;
     RECT  15.876 78.763 19.926 78.899 ;
     RECT  10.296 76.739 10.797 79.169 ;
     RECT  15.915 78.899 19.926 79.169 ;
     RECT  7.668 78.899 9.486 79.181 ;
     RECT  2.304 78.899 6.894 79.205 ;
     RECT  7.668 79.181 9.342 79.205 ;
     RECT  17.244 79.169 19.926 79.241 ;
     RECT  7.668 79.205 8.91 79.439 ;
     RECT  17.244 79.241 19.854 79.439 ;
     RECT  21.456 78.809 21.474 79.439 ;
     RECT  2.304 79.205 6.858 79.469 ;
     RECT  18.216 79.439 19.854 79.619 ;
     RECT  2.376 79.469 6.858 79.661 ;
     RECT  7.668 79.439 8.694 79.667 ;
     RECT  10.515 79.169 10.797 79.667 ;
     RECT  13.215 75.839 13.497 79.667 ;
     RECT  15.915 79.169 16.197 79.667 ;
     RECT  2.376 79.661 6.786 79.709 ;
     RECT  8.676 79.667 8.694 79.709 ;
     RECT  18.216 79.619 19.134 79.709 ;
     RECT  7.668 79.667 7.905 79.723 ;
     RECT  2.376 79.709 5.67 79.745 ;
     RECT  6.624 79.709 6.642 79.745 ;
     RECT  17.244 79.439 17.262 79.745 ;
     RECT  2.376 79.745 5.634 79.781 ;
     RECT  7.632 79.723 7.905 79.781 ;
     RECT  18.216 79.709 18.705 79.781 ;
     RECT  0.108 78.797 0.126 79.819 ;
     RECT  2.415 79.781 5.634 79.853 ;
     RECT  2.415 79.853 5.205 79.889 ;
     RECT  2.415 79.889 2.574 79.937 ;
     RECT  3.348 79.889 5.205 79.937 ;
     RECT  7.815 79.781 7.905 79.937 ;
     RECT  10.515 79.667 10.605 79.937 ;
     RECT  13.215 79.667 13.305 79.937 ;
     RECT  15.915 79.667 16.005 79.937 ;
     RECT  18.615 79.781 18.705 79.937 ;
     RECT  0.108 79.819 0.162 79.949 ;
     RECT  3.348 79.937 4.914 80.093 ;
     RECT  0.108 79.949 0.126 80.237 ;
     RECT  3.348 80.093 4.59 80.381 ;
     RECT  3.816 80.381 4.59 80.669 ;
     RECT  2.556 79.937 2.574 80.813 ;
     RECT  1.404 78.269 1.422 80.957 ;
     RECT  4.14 80.669 4.59 81.101 ;
     RECT  4.14 81.101 4.158 81.245 ;
    LAYER M4 ;
     RECT  0.084 53.712 0.137 53.736 ;
     RECT  0.06 53.736 0.137 53.856 ;
     RECT  0.084 53.856 0.137 53.88 ;
     RECT  0.06 53.88 0.137 54 ;
     RECT  0.084 54 0.137 54.024 ;
     RECT  0.06 54.024 0.137 54.144 ;
     RECT  0.084 54.144 0.137 54.168 ;
     RECT  0.06 54.168 0.137 54.288 ;
     RECT  0.084 54.288 0.137 54.312 ;
     RECT  0.06 54.312 0.137 54.432 ;
     RECT  0.084 54.432 0.137 54.456 ;
     RECT  0.06 54.456 0.137 54.576 ;
     RECT  0.084 54.576 0.137 54.6 ;
     RECT  0.06 54.6 0.137 54.72 ;
     RECT  0.084 54.72 0.137 54.744 ;
     RECT  0.06 54.744 0.137 54.864 ;
     RECT  0.084 54.864 0.137 54.888 ;
     RECT  0.06 54.888 0.137 55.008 ;
     RECT  0.084 55.008 0.137 55.032 ;
     RECT  0.06 55.032 0.137 55.152 ;
     RECT  0.084 55.152 0.137 55.176 ;
     RECT  0.06 55.176 0.137 55.296 ;
     RECT  0.084 55.296 0.137 55.32 ;
     RECT  0.06 55.32 0.137 55.44 ;
     RECT  0.084 55.44 0.137 55.464 ;
     RECT  0.06 55.464 0.137 55.584 ;
     RECT  0.084 55.584 0.137 55.608 ;
     RECT  0.06 55.608 0.137 55.728 ;
     RECT  0.084 55.728 0.137 55.752 ;
     RECT  0.06 55.752 0.137 55.872 ;
     RECT  0.084 55.872 0.137 55.896 ;
     RECT  0.06 55.896 0.137 56.016 ;
     RECT  0.084 56.016 0.137 56.04 ;
     RECT  0.06 56.04 0.137 56.16 ;
     RECT  0.084 56.16 0.137 56.184 ;
     RECT  0.06 56.184 0.137 56.304 ;
     RECT  0.084 56.304 0.137 56.328 ;
     RECT  0.06 56.328 0.137 56.448 ;
     RECT  0.084 56.448 0.137 56.472 ;
     RECT  0.06 56.472 0.137 56.592 ;
     RECT  0.084 56.592 0.137 56.616 ;
     RECT  0.06 56.616 0.137 56.736 ;
     RECT  0.084 56.736 0.137 56.76 ;
     RECT  0.06 56.76 0.137 56.88 ;
     RECT  0.084 56.88 0.137 56.904 ;
     RECT  0.06 56.904 0.137 57.024 ;
     RECT  0.084 57.024 0.137 57.048 ;
     RECT  0.06 57.048 0.137 57.168 ;
     RECT  0.084 57.168 0.137 57.192 ;
     RECT  0.06 57.192 0.137 57.312 ;
     RECT  0.084 57.312 0.137 57.336 ;
     RECT  0.06 57.336 0.137 57.456 ;
     RECT  0.084 57.456 0.137 57.48 ;
     RECT  0.06 57.48 0.137 57.6 ;
     RECT  0.084 57.6 0.137 57.624 ;
     RECT  0.06 57.624 0.137 57.744 ;
     RECT  0.084 57.744 0.137 57.768 ;
     RECT  0.06 57.768 0.137 57.888 ;
     RECT  0.084 57.888 0.137 57.912 ;
     RECT  0.06 57.912 0.137 58.032 ;
     RECT  0.084 58.032 0.137 58.056 ;
     RECT  0.06 58.056 0.137 58.176 ;
     RECT  0.084 58.176 0.137 58.2 ;
     RECT  0.06 58.2 0.137 58.32 ;
     RECT  0.084 58.32 0.137 58.344 ;
     RECT  0.06 58.344 0.137 58.464 ;
     RECT  0.084 58.464 0.137 58.488 ;
     RECT  0.06 58.488 0.137 58.608 ;
     RECT  0.084 58.608 0.137 58.632 ;
     RECT  0.06 58.632 0.137 58.752 ;
     RECT  0.084 58.752 0.137 58.776 ;
     RECT  0.06 58.776 0.137 58.896 ;
     RECT  0.084 58.896 0.137 58.92 ;
     RECT  0.06 58.92 0.137 59.04 ;
     RECT  0.084 59.04 0.137 59.064 ;
     RECT  0.06 59.064 0.137 59.184 ;
     RECT  0.084 59.184 0.137 59.208 ;
     RECT  0.06 59.208 0.137 59.328 ;
     RECT  0.084 59.328 0.137 59.352 ;
     RECT  0.06 59.352 0.137 59.472 ;
     RECT  0.084 59.472 0.137 59.496 ;
     RECT  0.06 59.496 0.137 59.616 ;
     RECT  0.084 59.616 0.137 59.64 ;
     RECT  0.06 59.64 0.137 59.76 ;
     RECT  0.084 59.76 0.137 59.784 ;
     RECT  0.06 59.784 0.137 59.904 ;
     RECT  0.084 59.904 0.137 59.928 ;
     RECT  0.06 59.928 0.137 60.048 ;
     RECT  0.084 60.048 0.137 60.072 ;
     RECT  0.06 60.072 0.137 60.192 ;
     RECT  0.084 60.192 0.137 60.216 ;
     RECT  0.06 60.216 0.137 60.336 ;
     RECT  0.084 60.336 0.137 60.36 ;
     RECT  0.06 60.36 0.137 60.48 ;
     RECT  0.084 60.48 0.137 60.504 ;
     RECT  0.06 60.504 0.137 60.624 ;
     RECT  0.084 60.624 0.137 60.648 ;
     RECT  0.06 60.648 0.137 60.768 ;
     RECT  0.084 60.768 0.137 60.792 ;
     RECT  0.06 60.792 0.137 60.912 ;
     RECT  0.084 60.912 0.137 60.936 ;
     RECT  0.06 60.936 0.137 61.056 ;
     RECT  0.084 61.056 0.137 61.08 ;
     RECT  0.06 61.08 0.137 61.2 ;
     RECT  0.084 61.2 0.137 61.224 ;
     RECT  0.06 61.224 0.137 61.344 ;
     RECT  0.084 61.344 0.137 61.368 ;
     RECT  0.06 61.368 0.137 61.488 ;
     RECT  0.084 61.488 0.137 61.512 ;
     RECT  0.06 61.512 0.137 61.632 ;
     RECT  0.084 61.632 0.137 61.656 ;
     RECT  0.06 61.656 0.137 61.776 ;
     RECT  0.084 61.776 0.137 61.8 ;
     RECT  0.06 61.8 0.137 61.92 ;
     RECT  0.084 61.92 0.137 61.944 ;
     RECT  0.06 61.944 0.137 62.064 ;
     RECT  0.084 62.064 0.137 62.088 ;
     RECT  0.06 62.088 0.137 62.208 ;
     RECT  0.084 62.208 0.137 62.232 ;
     RECT  0.06 62.232 0.137 62.352 ;
     RECT  0.084 62.352 0.137 62.376 ;
     RECT  0.06 62.376 0.137 62.496 ;
     RECT  0.084 62.496 0.137 62.52 ;
     RECT  0.06 62.52 0.137 62.64 ;
     RECT  0.084 62.64 0.137 62.664 ;
     RECT  0.06 62.664 0.137 62.784 ;
     RECT  0.084 62.784 0.137 62.808 ;
     RECT  0.06 62.808 0.137 62.928 ;
     RECT  0.084 62.928 0.137 62.952 ;
     RECT  0.06 62.952 0.137 63.072 ;
     RECT  0.084 63.072 0.137 63.096 ;
     RECT  0.06 63.096 0.137 63.216 ;
     RECT  0.084 63.216 0.137 63.24 ;
     RECT  0.06 63.24 0.137 63.36 ;
     RECT  0.084 63.36 0.137 63.384 ;
     RECT  0.06 63.384 0.137 63.504 ;
     RECT  0.084 63.504 0.137 63.528 ;
     RECT  0.06 63.528 0.137 63.648 ;
     RECT  0.084 63.648 0.137 63.672 ;
     RECT  0.06 63.672 0.137 63.792 ;
     RECT  0.084 63.792 0.137 63.816 ;
     RECT  0.06 63.816 0.137 63.936 ;
     RECT  0.084 63.936 0.137 63.96 ;
     RECT  0.06 63.96 0.137 64.08 ;
     RECT  0.084 64.08 0.137 64.104 ;
     RECT  0.06 64.104 0.137 64.224 ;
     RECT  0.084 64.224 0.137 64.248 ;
     RECT  0.06 64.248 0.137 64.368 ;
     RECT  0.084 64.368 0.137 64.392 ;
     RECT  0.06 64.392 0.137 64.512 ;
     RECT  0.084 64.512 0.137 64.536 ;
     RECT  0.06 64.536 0.137 64.656 ;
     RECT  0.084 64.656 0.137 64.68 ;
     RECT  0.06 64.68 0.137 64.8 ;
     RECT  0.084 64.8 0.137 64.824 ;
     RECT  0.06 64.824 0.137 64.944 ;
     RECT  0.084 64.944 0.137 64.968 ;
     RECT  0.06 64.968 0.137 65.088 ;
     RECT  0.084 65.088 0.137 65.112 ;
     RECT  0.06 65.112 0.137 65.232 ;
     RECT  0.084 65.232 0.137 65.256 ;
     RECT  0.06 65.256 0.137 65.376 ;
     RECT  0.084 65.376 0.137 65.4 ;
     RECT  0.06 65.4 0.137 65.52 ;
     RECT  0.084 65.52 0.137 65.544 ;
     RECT  0.06 65.544 0.137 65.664 ;
     RECT  0.084 65.664 0.137 65.688 ;
     RECT  0.06 65.688 0.137 65.808 ;
     RECT  0.084 65.808 0.137 65.832 ;
     RECT  0.06 65.832 0.137 65.952 ;
     RECT  0.084 65.952 0.137 65.976 ;
     RECT  0.06 65.976 0.137 66.096 ;
     RECT  0.084 66.096 0.137 66.12 ;
     RECT  0.06 66.12 0.137 66.24 ;
     RECT  0.084 66.24 0.137 66.264 ;
     RECT  0.06 66.264 0.137 66.384 ;
     RECT  0.084 66.384 0.137 66.408 ;
     RECT  0.06 66.408 0.137 66.528 ;
     RECT  0.084 66.528 0.137 66.552 ;
     RECT  0.06 66.552 0.137 66.672 ;
     RECT  0.084 66.672 0.137 66.696 ;
     RECT  0.06 66.696 0.137 66.816 ;
     RECT  0.084 66.816 0.137 66.84 ;
     RECT  0.06 66.84 0.137 66.96 ;
     RECT  0.084 66.96 0.137 66.984 ;
     RECT  0.06 66.984 0.137 67.104 ;
     RECT  0.084 67.104 0.137 67.128 ;
     RECT  0.06 67.128 0.137 67.248 ;
     RECT  0.084 67.248 0.137 67.272 ;
     RECT  0.06 67.272 0.137 67.392 ;
     RECT  0.084 67.392 0.137 67.416 ;
     RECT  0.06 67.416 0.137 67.536 ;
     RECT  0.084 67.536 0.137 67.56 ;
     RECT  0.06 67.56 0.137 67.68 ;
     RECT  0.084 67.68 0.137 67.704 ;
     RECT  0.06 67.704 0.137 67.824 ;
     RECT  0.084 67.824 0.137 67.848 ;
     RECT  0.06 67.848 0.137 67.968 ;
     RECT  0.084 67.968 0.137 67.992 ;
     RECT  0.06 67.992 0.137 68.112 ;
     RECT  0.084 68.112 0.137 68.136 ;
     RECT  0.06 68.136 0.137 68.256 ;
     RECT  0.084 68.256 0.137 68.28 ;
     RECT  0.06 68.28 0.137 68.4 ;
     RECT  0.084 68.4 0.137 68.424 ;
     RECT  0.06 68.424 0.137 68.544 ;
     RECT  0.084 68.544 0.137 68.568 ;
     RECT  0.06 68.568 0.137 68.688 ;
     RECT  0.084 68.688 0.137 68.712 ;
     RECT  0.06 68.712 0.137 68.832 ;
     RECT  0.084 68.832 0.137 68.856 ;
     RECT  0.06 68.856 0.137 68.976 ;
     RECT  0.084 68.976 0.137 69 ;
     RECT  0.06 69 0.137 69.12 ;
     RECT  0.084 69.12 0.137 69.144 ;
     RECT  0.06 69.144 0.137 69.264 ;
     RECT  0.084 69.264 0.137 69.288 ;
     RECT  0.06 69.288 0.137 69.408 ;
     RECT  0.084 69.408 0.137 69.432 ;
     RECT  0.06 69.432 0.137 69.552 ;
     RECT  0.084 69.552 0.137 69.576 ;
     RECT  0.06 69.576 0.137 69.696 ;
     RECT  0.084 69.696 0.137 69.72 ;
     RECT  0.06 69.72 0.137 69.84 ;
     RECT  0.084 69.84 0.137 69.864 ;
     RECT  0.06 69.864 0.137 69.984 ;
     RECT  0.084 69.984 0.137 70.008 ;
     RECT  0.06 70.008 0.137 70.128 ;
     RECT  0.084 70.128 0.137 70.152 ;
     RECT  0.06 70.152 0.137 70.272 ;
     RECT  0.084 70.272 0.137 70.296 ;
     RECT  0.06 70.296 0.137 70.416 ;
     RECT  0.084 70.416 0.137 70.44 ;
     RECT  0.06 70.44 0.137 70.56 ;
     RECT  0.084 70.56 0.137 70.584 ;
     RECT  0.06 70.584 0.137 70.704 ;
     RECT  0.084 70.704 0.137 70.728 ;
     RECT  0.06 70.728 0.137 70.848 ;
     RECT  0.084 70.848 0.137 70.872 ;
     RECT  0.06 70.872 0.137 70.992 ;
     RECT  0.084 70.992 0.137 71.016 ;
     RECT  0.06 71.016 0.137 71.136 ;
     RECT  0.084 71.136 0.137 71.16 ;
     RECT  0.06 71.16 0.137 71.28 ;
     RECT  0.084 71.28 0.137 71.304 ;
     RECT  0.06 71.304 0.137 71.424 ;
     RECT  0.084 71.424 0.137 71.448 ;
     RECT  0.06 71.448 0.137 71.568 ;
     RECT  0.084 71.568 0.137 71.592 ;
     RECT  0.06 71.592 0.137 71.712 ;
     RECT  0.084 71.712 0.137 71.736 ;
     RECT  0.06 71.736 0.137 71.856 ;
     RECT  0.084 71.856 0.137 71.88 ;
     RECT  0.06 71.88 0.137 72 ;
     RECT  0.084 72 0.137 72.024 ;
     RECT  0.06 72.024 0.137 72.144 ;
     RECT  0.084 72.144 0.137 72.168 ;
     RECT  0.06 72.168 0.137 72.288 ;
     RECT  0.084 72.288 0.137 72.312 ;
     RECT  0.06 72.312 0.137 72.432 ;
     RECT  0.084 72.432 0.137 72.456 ;
     RECT  0.06 72.456 0.137 72.576 ;
     RECT  0.084 72.576 0.137 72.6 ;
     RECT  0.06 72.6 0.137 72.72 ;
     RECT  0.084 72.72 0.137 72.744 ;
     RECT  0.06 72.744 0.137 72.864 ;
     RECT  0.084 72.864 0.137 72.888 ;
     RECT  0.06 72.888 0.137 73.008 ;
     RECT  0.084 73.008 0.137 73.032 ;
     RECT  0.06 73.032 0.137 73.152 ;
     RECT  0.084 73.152 0.137 73.176 ;
     RECT  0.06 73.176 0.137 73.296 ;
     RECT  0.084 73.296 0.137 73.32 ;
     RECT  0.06 73.32 0.137 73.44 ;
     RECT  0.084 73.44 0.137 73.464 ;
     RECT  0.06 73.464 0.137 73.584 ;
     RECT  0.084 73.584 0.137 73.608 ;
     RECT  0.06 73.608 0.137 73.728 ;
     RECT  0.084 73.728 0.137 73.752 ;
     RECT  0.06 73.752 0.137 73.872 ;
     RECT  0.084 73.872 0.137 73.896 ;
     RECT  0.06 73.896 0.137 74.016 ;
     RECT  0.084 74.016 0.137 74.04 ;
     RECT  0.06 74.04 0.137 74.16 ;
     RECT  0.084 74.16 0.137 74.184 ;
     RECT  0.06 74.184 0.137 74.304 ;
     RECT  0.084 74.304 0.137 74.328 ;
     RECT  0.06 74.328 0.137 74.448 ;
     RECT  0.084 74.448 0.137 74.472 ;
     RECT  0.06 74.472 0.137 74.592 ;
     RECT  0.084 74.592 0.137 74.616 ;
     RECT  0.06 74.616 0.137 74.736 ;
     RECT  0.084 74.736 0.137 74.76 ;
     RECT  0.06 74.76 0.137 74.88 ;
     RECT  0.084 74.88 0.137 74.904 ;
     RECT  0.06 74.904 0.137 75.024 ;
     RECT  0.084 75.024 0.137 75.048 ;
     RECT  0.06 75.048 0.137 75.168 ;
     RECT  0.084 75.168 0.137 75.192 ;
     RECT  0.06 75.192 0.137 75.312 ;
     RECT  0.084 75.312 0.137 75.336 ;
     RECT  0.06 75.336 0.137 75.456 ;
     RECT  0.084 75.456 0.137 75.48 ;
     RECT  0.06 75.48 0.137 75.6 ;
     RECT  0.084 75.6 0.137 75.624 ;
     RECT  0.06 75.624 0.137 75.744 ;
     RECT  0.084 75.744 0.137 75.768 ;
     RECT  0.06 75.768 0.137 75.888 ;
     RECT  0.084 75.888 0.137 75.912 ;
     RECT  0.06 75.912 0.137 76.032 ;
     RECT  0.084 76.032 0.137 76.056 ;
     RECT  0.06 76.056 0.137 76.176 ;
     RECT  0.084 76.176 0.137 76.2 ;
     RECT  0.06 76.2 0.137 76.32 ;
     RECT  0.084 76.32 0.137 76.344 ;
     RECT  0.06 76.344 0.137 76.464 ;
     RECT  0.084 76.464 0.137 76.488 ;
     RECT  0.06 76.488 0.137 76.608 ;
     RECT  0.084 76.608 0.137 76.632 ;
     RECT  0.06 76.632 0.137 76.752 ;
     RECT  0.084 76.752 0.137 76.776 ;
     RECT  0.06 76.776 0.137 76.896 ;
     RECT  0.084 76.896 0.137 76.92 ;
     RECT  0.06 76.92 0.137 77.04 ;
     RECT  0.084 77.04 0.137 77.064 ;
     RECT  0.06 77.064 0.137 77.184 ;
     RECT  0.084 77.184 0.137 77.208 ;
     RECT  0.06 77.208 0.137 77.328 ;
     RECT  0.084 77.328 0.137 77.352 ;
     RECT  0.06 77.352 0.137 77.472 ;
     RECT  0.084 77.472 0.137 77.496 ;
     RECT  0.06 77.496 0.137 77.616 ;
     RECT  0.084 77.616 0.137 77.64 ;
     RECT  0.06 77.64 0.137 77.76 ;
     RECT  0.084 77.76 0.137 77.784 ;
     RECT  0.06 77.784 0.137 77.904 ;
     RECT  0.084 77.904 0.137 77.928 ;
     RECT  0.06 77.928 0.137 78.048 ;
     RECT  0.084 78.048 0.137 78.072 ;
     RECT  0.06 78.072 0.137 78.192 ;
     RECT  0.084 78.192 0.137 78.216 ;
     RECT  0.06 78.216 0.137 78.336 ;
     RECT  0.084 78.336 0.137 78.36 ;
     RECT  0.06 78.36 0.137 78.48 ;
     RECT  0.084 78.48 0.137 78.504 ;
     RECT  0.06 78.504 0.137 78.624 ;
     RECT  0.084 78.624 0.137 78.648 ;
     RECT  0.06 78.648 0.137 78.768 ;
     RECT  0.084 78.768 0.137 78.792 ;
     RECT  0.06 78.792 0.137 78.912 ;
     RECT  0.084 78.912 0.137 78.936 ;
     RECT  0.06 78.936 0.137 79.056 ;
     RECT  0.084 79.056 0.137 79.08 ;
     RECT  0.06 79.08 0.137 79.2 ;
     RECT  0.084 79.2 0.137 79.224 ;
     RECT  0.06 79.224 0.137 79.344 ;
     RECT  0.084 79.344 0.137 79.368 ;
     RECT  0.06 79.368 0.137 79.488 ;
     RECT  0.084 79.488 0.137 79.512 ;
     RECT  0.06 79.512 0.137 79.632 ;
     RECT  0.084 79.632 0.137 79.656 ;
     RECT  0.06 79.656 0.137 79.776 ;
     RECT  0.084 79.776 0.137 79.8 ;
     RECT  0.06 79.8 0.137 79.92 ;
     RECT  0.084 79.92 0.137 79.944 ;
     RECT  0.06 79.944 0.137 80.064 ;
     RECT  0.084 80.064 0.137 80.088 ;
     RECT  0.06 80.088 0.137 80.208 ;
     RECT  0.084 80.208 0.137 80.232 ;
     RECT  0.06 80.232 0.137 80.352 ;
     RECT  0.084 80.352 0.137 80.376 ;
     RECT  0.06 80.376 0.137 80.496 ;
     RECT  0.084 80.496 0.137 80.52 ;
     RECT  0.06 80.52 0.137 80.64 ;
     RECT  0.084 80.64 0.137 80.664 ;
     RECT  0.06 80.664 0.137 80.784 ;
     RECT  0.084 80.784 0.137 80.808 ;
     RECT  0.06 80.808 0.137 80.928 ;
     RECT  0.084 80.928 0.137 80.952 ;
     RECT  0.06 80.952 0.137 81.072 ;
     RECT  0.084 81.072 0.137 81.096 ;
     RECT  0.06 81.096 0.137 81.216 ;
     RECT  0.084 81.216 0.137 81.24 ;
     RECT  0.084 3.024 2.408 3.048 ;
     RECT  0.06 3.048 2.408 3.168 ;
     RECT  0.084 3.168 2.408 3.192 ;
     RECT  0.06 3.192 2.408 3.312 ;
     RECT  0.084 3.312 2.408 3.336 ;
     RECT  0.06 3.336 2.408 3.456 ;
     RECT  0.084 3.456 2.408 3.48 ;
     RECT  0.06 3.48 2.408 3.6 ;
     RECT  0.084 3.6 2.408 3.624 ;
     RECT  0.06 3.624 2.408 3.744 ;
     RECT  0.084 3.744 2.408 3.768 ;
     RECT  0.06 3.768 2.408 3.888 ;
     RECT  0.084 3.888 2.408 3.912 ;
     RECT  0.06 3.912 2.408 4.032 ;
     RECT  0.084 4.032 2.408 4.056 ;
     RECT  0.06 4.056 2.408 4.176 ;
     RECT  0.084 4.176 2.408 4.2 ;
     RECT  0.06 4.2 2.408 4.32 ;
     RECT  0.084 4.32 2.408 4.344 ;
     RECT  0.06 4.344 2.408 4.464 ;
     RECT  0.084 4.464 2.408 4.488 ;
     RECT  0.06 4.488 2.408 4.608 ;
     RECT  0.084 4.608 2.408 4.632 ;
     RECT  0.06 4.632 2.408 4.752 ;
     RECT  0.084 4.752 2.408 4.776 ;
     RECT  0.06 4.776 2.408 4.896 ;
     RECT  0.084 4.896 2.408 4.92 ;
     RECT  0.06 4.92 2.408 5.04 ;
     RECT  0.084 5.04 2.408 5.064 ;
     RECT  0.06 5.064 2.408 5.184 ;
     RECT  0.084 5.184 2.408 5.208 ;
     RECT  0.06 5.208 2.408 5.328 ;
     RECT  0.084 5.328 2.408 5.352 ;
     RECT  0.06 5.352 2.408 5.472 ;
     RECT  0.084 5.472 2.408 5.496 ;
     RECT  0.06 5.496 2.408 5.616 ;
     RECT  0.084 5.616 2.408 5.64 ;
     RECT  0.06 5.64 2.408 5.76 ;
     RECT  0.084 5.76 2.408 5.784 ;
     RECT  0.06 5.784 2.408 5.904 ;
     RECT  0.084 5.904 2.408 5.928 ;
     RECT  0.06 5.928 2.408 6.048 ;
     RECT  0.084 6.048 2.408 6.072 ;
     RECT  0.06 6.072 2.408 6.192 ;
     RECT  0.084 6.192 2.408 6.216 ;
     RECT  0.06 6.216 2.408 6.336 ;
     RECT  0.084 6.336 2.408 6.36 ;
     RECT  0.06 6.36 2.408 6.48 ;
     RECT  0.084 6.48 2.408 6.504 ;
     RECT  0.06 6.504 2.408 6.624 ;
     RECT  0.084 6.624 2.408 6.648 ;
     RECT  0.06 6.648 2.408 6.768 ;
     RECT  0.084 6.768 2.408 6.792 ;
     RECT  0.06 6.792 2.408 6.912 ;
     RECT  0.084 6.912 2.408 6.936 ;
     RECT  0.06 6.936 2.408 7.056 ;
     RECT  0.084 7.056 2.408 7.08 ;
     RECT  0.06 7.08 2.408 7.2 ;
     RECT  0.084 7.2 2.408 7.224 ;
     RECT  0.06 7.224 2.408 7.344 ;
     RECT  0.084 7.344 2.408 7.368 ;
     RECT  0.06 7.368 2.408 7.488 ;
     RECT  0.084 7.488 2.408 7.512 ;
     RECT  0.06 7.512 2.408 7.632 ;
     RECT  0.084 7.632 2.408 7.656 ;
     RECT  0.06 7.656 2.408 7.776 ;
     RECT  0.084 7.776 2.408 7.8 ;
     RECT  0.06 7.8 2.408 7.92 ;
     RECT  0.084 7.92 2.408 7.944 ;
     RECT  0.06 7.944 2.408 8.064 ;
     RECT  0.084 8.064 2.408 8.088 ;
     RECT  0.06 8.088 2.408 8.208 ;
     RECT  0.084 8.208 2.408 8.232 ;
     RECT  0.06 8.232 2.408 8.352 ;
     RECT  0.084 8.352 2.408 8.376 ;
     RECT  0.06 8.376 2.408 8.496 ;
     RECT  0.084 8.496 2.408 8.52 ;
     RECT  0.06 8.52 2.408 8.64 ;
     RECT  0.084 8.64 2.408 8.664 ;
     RECT  0.06 8.664 2.408 8.784 ;
     RECT  0.084 8.784 2.408 8.808 ;
     RECT  0.06 8.808 2.408 8.928 ;
     RECT  0.084 8.928 2.408 8.952 ;
     RECT  0.06 8.952 2.408 9.072 ;
     RECT  0.084 9.072 2.408 9.096 ;
     RECT  0.06 9.096 2.408 9.216 ;
     RECT  0.084 9.216 2.408 9.24 ;
     RECT  0.06 9.24 2.408 9.36 ;
     RECT  0.084 9.36 2.408 9.384 ;
     RECT  0.06 9.384 2.408 9.504 ;
     RECT  0.084 9.504 2.408 9.528 ;
     RECT  0.06 9.528 2.408 9.648 ;
     RECT  0.084 9.648 2.408 9.672 ;
     RECT  0.06 9.672 2.408 9.792 ;
     RECT  0.084 9.792 2.408 9.816 ;
     RECT  0.06 9.816 2.408 9.936 ;
     RECT  0.084 9.936 2.408 9.96 ;
     RECT  0.06 9.96 2.408 10.08 ;
     RECT  0.084 10.08 2.408 10.104 ;
     RECT  0.06 10.104 2.408 10.224 ;
     RECT  0.084 10.224 2.408 10.248 ;
     RECT  0.06 10.248 2.408 10.368 ;
     RECT  0.084 10.368 2.408 10.392 ;
     RECT  0.06 10.392 2.408 10.512 ;
     RECT  0.084 10.512 2.408 10.536 ;
     RECT  0.06 10.536 2.408 10.656 ;
     RECT  0.084 10.656 2.408 10.68 ;
     RECT  0.06 10.68 2.408 10.8 ;
     RECT  0.084 10.8 2.408 10.824 ;
     RECT  0.06 10.824 2.408 10.944 ;
     RECT  0.084 10.944 2.408 10.968 ;
     RECT  0.06 10.968 2.408 11.088 ;
     RECT  0.084 11.088 2.408 11.112 ;
     RECT  0.06 11.112 2.408 11.232 ;
     RECT  0.084 11.232 2.408 11.256 ;
     RECT  0.06 11.256 2.408 11.376 ;
     RECT  0.084 11.376 2.408 11.4 ;
     RECT  0.06 11.4 2.408 11.52 ;
     RECT  0.084 11.52 2.408 11.544 ;
     RECT  0.06 11.544 2.408 11.664 ;
     RECT  0.084 11.664 2.408 11.688 ;
     RECT  0.06 11.688 2.408 11.808 ;
     RECT  0.084 11.808 2.408 11.832 ;
     RECT  0.06 11.832 2.408 11.952 ;
     RECT  0.084 11.952 2.408 11.976 ;
     RECT  0.06 11.976 2.408 12.096 ;
     RECT  0.084 12.096 2.408 12.12 ;
     RECT  0.06 12.12 2.408 12.24 ;
     RECT  0.084 12.24 2.408 12.264 ;
     RECT  0.06 12.264 2.408 12.384 ;
     RECT  0.084 12.384 2.408 12.408 ;
     RECT  0.06 12.408 2.408 12.528 ;
     RECT  0.084 12.528 2.408 12.552 ;
     RECT  0.06 12.552 2.408 12.672 ;
     RECT  0.084 12.672 2.408 12.696 ;
     RECT  0.06 12.696 2.408 12.816 ;
     RECT  0.084 12.816 2.408 12.84 ;
     RECT  0.06 12.84 2.408 12.96 ;
     RECT  0.084 12.96 2.408 12.984 ;
     RECT  0.06 12.984 2.408 13.104 ;
     RECT  0.084 13.104 2.408 13.128 ;
     RECT  0.06 13.128 2.408 13.248 ;
     RECT  0.084 13.248 2.408 13.272 ;
     RECT  0.06 13.272 2.408 13.392 ;
     RECT  0.084 13.392 2.408 13.416 ;
     RECT  0.06 13.416 2.408 13.536 ;
     RECT  0.084 13.536 2.408 13.56 ;
     RECT  0.06 13.56 2.408 13.68 ;
     RECT  0.084 13.68 2.408 13.704 ;
     RECT  0.06 13.704 2.408 13.824 ;
     RECT  0.084 13.824 2.408 13.848 ;
     RECT  0.06 13.848 2.408 13.968 ;
     RECT  0.084 13.968 2.408 13.992 ;
     RECT  0.06 13.992 2.408 14.112 ;
     RECT  0.084 14.112 2.408 14.136 ;
     RECT  0.06 14.136 2.408 14.256 ;
     RECT  0.084 14.256 2.408 14.28 ;
     RECT  0.06 14.28 2.408 14.4 ;
     RECT  0.084 14.4 2.408 14.424 ;
     RECT  0.06 14.424 2.408 14.544 ;
     RECT  0.084 14.544 2.408 14.568 ;
     RECT  0.06 14.568 2.408 14.688 ;
     RECT  0.084 14.688 2.408 14.712 ;
     RECT  0.06 14.712 2.408 14.832 ;
     RECT  0.084 14.832 2.408 14.856 ;
     RECT  0.06 14.856 2.408 14.976 ;
     RECT  0.084 14.976 2.408 15 ;
     RECT  0.06 15 2.408 15.12 ;
     RECT  0.084 15.12 2.408 15.144 ;
     RECT  0.06 15.144 2.408 15.264 ;
     RECT  0.084 15.264 2.408 15.288 ;
     RECT  0.06 15.288 2.408 15.408 ;
     RECT  0.084 15.408 2.408 15.432 ;
     RECT  0.06 15.432 2.408 15.552 ;
     RECT  0.084 15.552 2.408 15.576 ;
     RECT  0.06 15.576 2.408 15.696 ;
     RECT  0.084 15.696 2.408 15.72 ;
     RECT  0.06 15.72 2.408 15.84 ;
     RECT  0.084 15.84 2.408 15.864 ;
     RECT  0.06 15.864 2.408 15.984 ;
     RECT  0.084 15.984 2.408 16.008 ;
     RECT  0.06 16.008 2.408 16.128 ;
     RECT  0.084 16.128 2.408 16.152 ;
     RECT  0.06 16.152 2.408 16.272 ;
     RECT  0.084 16.272 2.408 16.296 ;
     RECT  0.06 16.296 2.408 16.416 ;
     RECT  0.084 16.416 2.408 16.44 ;
     RECT  0.06 16.44 2.408 16.56 ;
     RECT  0.084 16.56 2.408 16.584 ;
     RECT  0.06 16.584 2.408 16.704 ;
     RECT  0.084 16.704 2.408 16.728 ;
     RECT  0.06 16.728 2.408 16.848 ;
     RECT  0.084 16.848 2.408 16.872 ;
     RECT  0.06 16.872 2.408 16.992 ;
     RECT  0.084 16.992 2.408 17.016 ;
     RECT  0.06 17.016 2.408 17.136 ;
     RECT  0.084 17.136 2.408 17.16 ;
     RECT  0.06 17.16 2.408 17.28 ;
     RECT  0.084 17.28 2.408 17.304 ;
     RECT  0.06 17.304 2.408 17.424 ;
     RECT  0.084 17.424 2.408 17.448 ;
     RECT  0.06 17.448 2.408 17.568 ;
     RECT  0.084 17.568 2.408 17.592 ;
     RECT  0.06 17.592 2.408 17.712 ;
     RECT  0.084 17.712 2.408 17.736 ;
     RECT  0.06 17.736 2.408 17.856 ;
     RECT  0.084 17.856 2.408 17.88 ;
     RECT  0.06 17.88 2.408 18 ;
     RECT  0.084 18 2.408 18.024 ;
     RECT  0.06 18.024 2.408 18.144 ;
     RECT  0.084 18.144 2.408 18.168 ;
     RECT  0.06 18.168 2.408 18.288 ;
     RECT  0.084 18.288 2.408 18.312 ;
     RECT  0.06 18.312 2.408 18.432 ;
     RECT  0.084 18.432 2.408 18.456 ;
     RECT  0.06 18.456 2.408 18.576 ;
     RECT  0.084 18.576 2.408 18.6 ;
     RECT  0.06 18.6 2.408 18.72 ;
     RECT  0.084 18.72 2.408 18.744 ;
     RECT  0.06 18.744 2.408 18.864 ;
     RECT  0.084 18.864 2.408 18.888 ;
     RECT  0.06 18.888 2.408 19.008 ;
     RECT  0.084 19.008 2.408 19.032 ;
     RECT  0.06 19.032 2.408 19.152 ;
     RECT  0.084 19.152 2.408 19.176 ;
     RECT  0.06 19.176 2.408 19.296 ;
     RECT  0.084 19.296 2.408 19.32 ;
     RECT  0.06 19.32 2.408 19.44 ;
     RECT  0.084 19.44 2.408 19.464 ;
     RECT  0.06 19.464 2.408 19.584 ;
     RECT  0.084 19.584 2.408 19.608 ;
     RECT  0.06 19.608 2.408 19.728 ;
     RECT  0.084 19.728 2.408 19.752 ;
     RECT  0.06 19.752 2.408 19.872 ;
     RECT  0.084 19.872 2.408 19.896 ;
     RECT  0.06 19.896 2.408 20.016 ;
     RECT  0.084 20.016 2.408 20.04 ;
     RECT  0.06 20.04 2.408 20.16 ;
     RECT  0.084 20.16 2.408 20.184 ;
     RECT  0.06 20.184 2.408 20.304 ;
     RECT  0.084 20.304 2.408 20.328 ;
     RECT  0.06 20.328 2.408 20.448 ;
     RECT  0.084 20.448 2.408 20.472 ;
     RECT  0.06 20.472 2.408 20.592 ;
     RECT  0.084 20.592 2.408 20.616 ;
     RECT  0.06 20.616 2.408 20.736 ;
     RECT  0.084 20.736 2.408 20.76 ;
     RECT  0.06 20.76 2.408 20.88 ;
     RECT  0.084 20.88 2.408 20.904 ;
     RECT  0.06 20.904 2.408 21.024 ;
     RECT  0.084 21.024 2.408 21.048 ;
     RECT  0.06 21.048 2.408 21.168 ;
     RECT  0.084 21.168 2.408 21.192 ;
     RECT  0.06 21.192 2.408 21.312 ;
     RECT  0.084 21.312 2.408 21.336 ;
     RECT  0.06 21.336 2.408 21.456 ;
     RECT  0.084 21.456 2.408 21.48 ;
     RECT  0.06 21.48 2.408 21.6 ;
     RECT  0.084 21.6 2.408 21.624 ;
     RECT  0.06 21.624 2.408 21.744 ;
     RECT  0.084 21.744 2.408 21.768 ;
     RECT  0.06 21.768 2.408 21.888 ;
     RECT  0.084 21.888 2.408 21.912 ;
     RECT  0.06 21.912 2.408 22.032 ;
     RECT  0.084 22.032 2.408 22.056 ;
     RECT  0.06 22.056 2.408 22.176 ;
     RECT  0.084 22.176 2.408 22.2 ;
     RECT  0.06 22.2 2.408 22.32 ;
     RECT  0.084 22.32 2.408 22.344 ;
     RECT  0.06 22.344 2.408 22.464 ;
     RECT  0.084 22.464 2.408 22.488 ;
     RECT  0.06 22.488 2.408 22.608 ;
     RECT  0.084 22.608 2.408 22.632 ;
     RECT  0.06 22.632 2.408 22.752 ;
     RECT  0.084 22.752 2.408 22.776 ;
     RECT  0.06 22.776 2.408 22.896 ;
     RECT  0.084 22.896 2.408 22.92 ;
     RECT  0.06 22.92 2.408 23.04 ;
     RECT  0.084 23.04 2.408 23.064 ;
     RECT  0.06 23.064 2.408 23.184 ;
     RECT  0.084 23.184 2.408 23.208 ;
     RECT  0.06 23.208 2.408 23.328 ;
     RECT  0.084 23.328 2.408 23.352 ;
     RECT  0.06 23.352 2.408 23.472 ;
     RECT  0.084 23.472 2.408 23.496 ;
     RECT  0.06 23.496 2.408 23.616 ;
     RECT  0.084 23.616 2.408 23.64 ;
     RECT  0.084 24.912 2.408 24.936 ;
     RECT  0.06 24.936 2.408 25.056 ;
     RECT  0.084 25.056 2.408 25.08 ;
     RECT  0.06 25.08 2.408 25.2 ;
     RECT  0.084 25.2 2.408 25.224 ;
     RECT  0.06 25.224 2.408 25.344 ;
     RECT  0.084 25.344 2.408 25.368 ;
     RECT  0.06 25.368 2.408 25.488 ;
     RECT  0.084 25.488 2.408 25.512 ;
     RECT  0.06 25.512 2.408 25.632 ;
     RECT  0.084 25.632 2.408 25.656 ;
     RECT  0.06 25.656 2.408 25.776 ;
     RECT  0.084 25.776 2.408 25.8 ;
     RECT  0.06 25.8 2.408 25.92 ;
     RECT  0.084 25.92 2.408 25.944 ;
     RECT  0.06 25.944 2.408 26.064 ;
     RECT  0.084 26.064 2.408 26.088 ;
     RECT  0.06 26.088 2.408 26.208 ;
     RECT  0.084 26.208 2.408 26.232 ;
     RECT  0.06 26.232 2.408 26.352 ;
     RECT  0.084 26.352 2.408 26.376 ;
     RECT  0.06 26.376 2.408 26.496 ;
     RECT  0.084 26.496 2.408 26.52 ;
     RECT  0.06 26.52 2.408 26.64 ;
     RECT  0.084 26.64 2.408 26.664 ;
     RECT  0.06 26.664 2.408 26.784 ;
     RECT  0.084 26.784 2.408 26.808 ;
     RECT  0.06 26.808 2.408 26.928 ;
     RECT  0.084 26.928 2.408 26.952 ;
     RECT  0.06 26.952 2.408 27.072 ;
     RECT  0.084 27.072 2.408 27.096 ;
     RECT  0.06 27.096 2.408 27.216 ;
     RECT  0.084 27.216 2.408 27.24 ;
     RECT  0.06 27.24 2.408 27.36 ;
     RECT  0.084 27.36 2.408 27.384 ;
     RECT  0.06 27.384 2.408 27.504 ;
     RECT  0.084 27.504 2.408 27.528 ;
     RECT  0.06 27.528 2.408 27.648 ;
     RECT  0.084 27.648 2.408 27.672 ;
     RECT  0.06 27.672 2.408 27.792 ;
     RECT  0.084 27.792 2.408 27.816 ;
     RECT  0.06 27.816 2.408 27.936 ;
     RECT  0.084 27.936 2.408 27.96 ;
     RECT  0.06 27.96 2.408 28.08 ;
     RECT  0.084 28.08 2.408 28.104 ;
     RECT  0.06 28.104 2.408 28.224 ;
     RECT  0.084 28.224 2.408 28.248 ;
     RECT  0.06 28.248 2.408 28.368 ;
     RECT  0.084 28.368 2.408 28.392 ;
     RECT  0.06 28.392 2.408 28.512 ;
     RECT  0.084 28.512 2.408 28.536 ;
     RECT  0.06 28.536 2.408 28.656 ;
     RECT  0.084 28.656 2.408 28.68 ;
     RECT  0.06 28.68 2.408 28.8 ;
     RECT  0.084 28.8 2.408 28.824 ;
     RECT  0.06 28.824 2.408 28.944 ;
     RECT  0.084 28.944 2.408 28.968 ;
     RECT  0.06 28.968 2.408 29.088 ;
     RECT  0.084 29.088 2.408 29.112 ;
     RECT  0.06 29.112 2.408 29.232 ;
     RECT  0.084 29.232 2.408 29.256 ;
     RECT  0.06 29.256 2.408 29.376 ;
     RECT  0.084 29.376 2.408 29.4 ;
     RECT  0.06 29.4 2.408 29.52 ;
     RECT  0.084 29.52 2.408 29.544 ;
     RECT  0.06 29.544 2.408 29.664 ;
     RECT  0.084 29.664 2.408 29.688 ;
     RECT  0.06 29.688 2.408 29.808 ;
     RECT  0.084 29.808 2.408 29.832 ;
     RECT  0.06 29.832 2.408 29.952 ;
     RECT  0.084 29.952 2.408 29.976 ;
     RECT  0.06 29.976 2.408 30.096 ;
     RECT  0.084 30.096 2.408 30.12 ;
     RECT  0.06 30.12 2.408 30.24 ;
     RECT  0.084 30.24 2.408 30.264 ;
     RECT  0.06 30.264 2.408 30.384 ;
     RECT  0.084 30.384 2.408 30.408 ;
     RECT  0.06 30.408 2.408 30.528 ;
     RECT  0.084 30.528 2.408 30.552 ;
     RECT  0.06 30.552 2.408 30.672 ;
     RECT  0.084 30.672 2.408 30.696 ;
     RECT  0.06 30.696 2.408 30.816 ;
     RECT  0.084 30.816 2.408 30.84 ;
     RECT  0.06 30.84 2.408 30.96 ;
     RECT  0.084 30.96 2.408 30.984 ;
     RECT  0.06 30.984 2.408 31.104 ;
     RECT  0.084 31.104 2.408 31.128 ;
     RECT  0.06 31.128 2.408 31.248 ;
     RECT  0.084 31.248 2.408 31.272 ;
     RECT  0.06 31.272 2.408 31.392 ;
     RECT  0.084 31.392 2.408 31.416 ;
     RECT  0.06 31.416 2.408 31.536 ;
     RECT  0.084 31.536 2.408 31.56 ;
     RECT  0.06 31.56 2.408 31.68 ;
     RECT  0.084 31.68 2.408 31.704 ;
     RECT  0.06 31.704 2.408 31.824 ;
     RECT  0.084 31.824 2.408 31.848 ;
     RECT  0.06 31.848 2.408 31.968 ;
     RECT  0.084 31.968 2.408 31.992 ;
     RECT  0.06 31.992 2.408 32.112 ;
     RECT  0.084 32.112 2.408 32.136 ;
     RECT  0.06 32.136 2.408 32.256 ;
     RECT  0.084 32.256 2.408 32.28 ;
     RECT  0.06 32.28 2.408 32.4 ;
     RECT  0.084 32.4 2.408 32.424 ;
     RECT  0.06 32.424 2.408 32.544 ;
     RECT  0.084 32.544 2.408 32.568 ;
     RECT  0.06 32.568 2.408 32.688 ;
     RECT  0.084 32.688 2.408 32.712 ;
     RECT  0.06 32.712 2.408 32.832 ;
     RECT  0.084 32.832 2.408 32.856 ;
     RECT  0.06 32.856 2.408 32.976 ;
     RECT  0.084 32.976 2.408 33 ;
     RECT  0.06 33 2.408 33.12 ;
     RECT  0.084 33.12 2.408 33.144 ;
     RECT  0.06 33.144 2.408 33.264 ;
     RECT  0.084 33.264 2.408 33.288 ;
     RECT  0.06 33.288 2.408 33.408 ;
     RECT  0.084 33.408 2.408 33.432 ;
     RECT  0.06 33.432 2.408 33.552 ;
     RECT  0.084 33.552 2.408 33.576 ;
     RECT  0.06 33.576 2.408 33.696 ;
     RECT  0.084 33.696 2.408 33.72 ;
     RECT  0.06 33.72 2.408 33.84 ;
     RECT  0.084 33.84 2.408 33.864 ;
     RECT  0.06 33.864 2.408 33.984 ;
     RECT  0.084 33.984 2.408 34.008 ;
     RECT  0.06 34.008 2.408 34.128 ;
     RECT  0.084 34.128 2.408 34.152 ;
     RECT  0.06 34.152 2.408 34.272 ;
     RECT  0.084 34.272 2.408 34.296 ;
     RECT  0.06 34.296 2.408 34.416 ;
     RECT  0.084 34.416 2.408 34.44 ;
     RECT  0.06 34.44 2.408 34.56 ;
     RECT  0.084 34.56 2.408 34.584 ;
     RECT  0.06 34.584 2.408 34.704 ;
     RECT  0.084 34.704 2.408 34.728 ;
     RECT  0.06 34.728 2.408 34.848 ;
     RECT  0.084 34.848 2.408 34.872 ;
     RECT  0.06 34.872 2.408 34.992 ;
     RECT  0.084 34.992 2.408 35.016 ;
     RECT  0.06 35.016 2.408 35.136 ;
     RECT  0.084 35.136 2.408 35.16 ;
     RECT  0.06 35.16 2.408 35.28 ;
     RECT  0.084 35.28 2.408 35.304 ;
     RECT  0.06 35.304 2.408 35.424 ;
     RECT  0.084 35.424 2.408 35.448 ;
     RECT  0.06 35.448 2.408 35.568 ;
     RECT  0.084 35.568 2.408 35.592 ;
     RECT  0.06 35.592 2.408 35.712 ;
     RECT  0.084 35.712 2.408 35.736 ;
     RECT  0.06 35.736 2.408 35.856 ;
     RECT  0.084 35.856 2.408 35.88 ;
     RECT  0.06 35.88 2.408 36 ;
     RECT  0.084 36 2.408 36.024 ;
     RECT  0.06 36.024 2.408 36.144 ;
     RECT  0.084 36.144 2.408 36.168 ;
     RECT  0.06 36.168 2.408 36.288 ;
     RECT  0.084 36.288 2.408 36.312 ;
     RECT  0.06 36.312 2.408 36.432 ;
     RECT  0.084 36.432 2.408 36.456 ;
     RECT  0.06 36.456 2.408 36.576 ;
     RECT  0.084 36.576 2.408 36.6 ;
     RECT  0.06 36.6 2.408 36.72 ;
     RECT  0.084 36.72 2.408 36.744 ;
     RECT  0.06 36.744 2.408 36.864 ;
     RECT  0.084 36.864 2.408 36.888 ;
     RECT  0.06 36.888 2.408 37.008 ;
     RECT  0.084 37.008 2.408 37.032 ;
     RECT  0.06 37.032 2.408 37.152 ;
     RECT  0.084 37.152 2.408 37.176 ;
     RECT  0.06 37.176 2.408 37.296 ;
     RECT  0.084 37.296 2.408 37.32 ;
     RECT  0.06 37.32 2.408 37.44 ;
     RECT  0.084 37.44 2.408 37.464 ;
     RECT  0.06 37.464 2.408 37.584 ;
     RECT  0.084 37.584 2.408 37.608 ;
     RECT  0.06 37.608 2.408 37.728 ;
     RECT  0.084 37.728 2.408 37.752 ;
     RECT  0.06 37.752 2.408 37.872 ;
     RECT  0.084 37.872 2.408 37.896 ;
     RECT  0.06 37.896 2.408 38.016 ;
     RECT  0.084 38.016 2.408 38.04 ;
     RECT  0.06 38.04 2.408 38.16 ;
     RECT  0.084 38.16 2.408 38.184 ;
     RECT  0.06 38.184 2.408 38.304 ;
     RECT  0.084 38.304 2.408 38.328 ;
     RECT  0.06 38.328 2.408 38.448 ;
     RECT  0.084 38.448 2.408 38.472 ;
     RECT  0.06 38.472 2.408 38.592 ;
     RECT  0.084 38.592 2.408 38.616 ;
     RECT  0.06 38.616 2.408 38.736 ;
     RECT  0.084 38.736 2.408 38.76 ;
     RECT  0.06 38.76 2.408 38.88 ;
     RECT  0.084 38.88 2.408 38.904 ;
     RECT  0.06 38.904 2.408 39.024 ;
     RECT  0.084 39.024 2.408 39.048 ;
     RECT  0.06 39.048 2.408 39.168 ;
     RECT  0.084 39.168 2.408 39.192 ;
     RECT  0.06 39.192 2.408 39.312 ;
     RECT  0.084 39.312 2.408 39.336 ;
     RECT  0.06 39.336 2.408 39.456 ;
     RECT  0.084 39.456 2.408 39.48 ;
     RECT  0.06 39.48 2.408 39.6 ;
     RECT  0.084 39.6 2.408 39.624 ;
     RECT  0.06 39.624 2.408 39.744 ;
     RECT  0.084 39.744 2.408 39.768 ;
     RECT  0.06 39.768 2.408 39.888 ;
     RECT  0.084 39.888 2.408 39.912 ;
     RECT  0.06 39.912 2.408 40.032 ;
     RECT  0.084 40.032 2.408 40.056 ;
     RECT  0.06 40.056 2.408 40.176 ;
     RECT  0.084 40.176 2.408 40.2 ;
     RECT  0.06 40.2 2.408 40.32 ;
     RECT  0.084 40.32 2.408 40.344 ;
     RECT  0.06 40.344 2.408 40.464 ;
     RECT  0.084 40.464 2.408 40.488 ;
     RECT  0.06 40.488 2.408 40.608 ;
     RECT  0.084 40.608 2.408 40.632 ;
     RECT  0.06 40.632 2.408 40.752 ;
     RECT  0.084 40.752 2.408 40.776 ;
     RECT  0.06 40.776 2.408 40.896 ;
     RECT  0.084 40.896 2.408 40.92 ;
     RECT  0.06 40.92 2.408 41.04 ;
     RECT  0.084 41.04 2.408 41.064 ;
     RECT  0.06 41.064 2.408 41.184 ;
     RECT  0.084 41.184 2.408 41.208 ;
     RECT  0.06 41.208 2.408 41.328 ;
     RECT  0.084 41.328 2.408 41.352 ;
     RECT  0.06 41.352 2.408 41.472 ;
     RECT  0.084 41.472 2.408 41.496 ;
     RECT  0.06 41.496 2.408 41.616 ;
     RECT  0.084 41.616 2.408 41.64 ;
     RECT  0.06 41.64 2.408 41.76 ;
     RECT  0.084 41.76 2.408 41.784 ;
     RECT  0.06 41.784 2.408 41.904 ;
     RECT  0.084 41.904 2.408 41.928 ;
     RECT  0.06 41.928 2.408 42.048 ;
     RECT  0.084 42.048 2.408 42.072 ;
     RECT  0.06 42.072 2.408 42.192 ;
     RECT  0.084 42.192 2.408 42.216 ;
     RECT  0.06 42.216 2.408 42.336 ;
     RECT  0.084 42.336 2.408 42.36 ;
     RECT  0.06 42.36 2.408 42.48 ;
     RECT  0.084 42.48 2.408 42.504 ;
     RECT  0.06 42.504 2.408 42.624 ;
     RECT  0.084 42.624 2.408 42.648 ;
     RECT  0.06 42.648 2.408 42.768 ;
     RECT  0.084 42.768 2.408 42.792 ;
     RECT  0.06 42.792 2.408 42.912 ;
     RECT  0.084 42.912 2.408 42.936 ;
     RECT  0.06 42.936 2.408 43.056 ;
     RECT  0.084 43.056 2.408 43.08 ;
     RECT  0.06 43.08 2.408 43.2 ;
     RECT  0.084 43.2 2.408 43.224 ;
     RECT  0.06 43.224 2.408 43.344 ;
     RECT  0.084 43.344 2.408 43.368 ;
     RECT  0.06 43.368 2.408 43.488 ;
     RECT  0.084 43.488 2.408 43.512 ;
     RECT  0.06 43.512 2.408 43.632 ;
     RECT  0.084 43.632 2.408 43.656 ;
     RECT  0.06 43.656 2.408 43.776 ;
     RECT  0.084 43.776 2.408 43.8 ;
     RECT  0.06 43.8 2.408 43.92 ;
     RECT  0.084 43.92 2.408 43.944 ;
     RECT  0.06 43.944 2.408 44.064 ;
     RECT  0.084 44.064 2.408 44.088 ;
     RECT  0.06 44.088 2.408 44.208 ;
     RECT  0.084 44.208 2.408 44.232 ;
     RECT  0.06 44.232 2.408 44.352 ;
     RECT  0.084 44.352 2.408 44.376 ;
     RECT  0.06 44.376 2.408 44.496 ;
     RECT  0.084 44.496 2.408 44.52 ;
     RECT  0.06 44.52 2.408 44.64 ;
     RECT  0.084 44.64 2.408 44.664 ;
     RECT  0.06 44.664 2.408 44.784 ;
     RECT  0.084 44.784 2.408 44.808 ;
     RECT  0.06 44.808 2.408 44.928 ;
     RECT  0.084 44.928 2.408 44.952 ;
     RECT  0.06 44.952 2.408 45.072 ;
     RECT  0.084 45.072 2.408 45.096 ;
     RECT  0.06 45.096 2.408 45.216 ;
     RECT  0.084 45.216 2.408 45.24 ;
     RECT  0.06 45.24 2.408 45.36 ;
     RECT  0.084 45.36 2.408 45.384 ;
     RECT  0.06 45.384 2.408 45.504 ;
     RECT  0.084 45.504 2.408 45.528 ;
     RECT  0.06 45.528 2.408 45.648 ;
     RECT  0.084 45.648 2.408 45.672 ;
     RECT  0.06 45.672 2.408 45.792 ;
     RECT  0.084 45.792 2.408 45.816 ;
     RECT  0.06 45.816 2.408 45.936 ;
     RECT  0.084 45.936 2.408 45.96 ;
     RECT  0.06 45.96 2.408 46.08 ;
     RECT  0.084 46.08 2.408 46.104 ;
     RECT  0.06 46.104 2.408 46.224 ;
     RECT  0.084 46.224 2.408 46.248 ;
     RECT  0.06 46.248 2.408 46.368 ;
     RECT  0.084 46.368 2.408 46.392 ;
     RECT  0.06 46.392 2.408 46.512 ;
     RECT  0.084 46.512 2.408 46.536 ;
     RECT  0.06 46.536 2.408 46.656 ;
     RECT  0.084 46.656 2.408 46.68 ;
     RECT  0.06 46.68 2.408 46.8 ;
     RECT  0.084 46.8 2.408 46.824 ;
     RECT  0.06 46.824 2.408 46.944 ;
     RECT  0.084 46.944 2.408 46.968 ;
     RECT  0.06 46.968 2.408 47.088 ;
     RECT  0.084 47.088 2.408 47.112 ;
     RECT  0.06 47.112 2.408 47.232 ;
     RECT  0.084 47.232 2.408 47.256 ;
     RECT  0.06 47.256 2.408 47.376 ;
     RECT  0.084 47.376 2.408 47.4 ;
     RECT  0.06 47.4 2.408 47.52 ;
     RECT  0.084 47.52 2.408 47.544 ;
     RECT  0.06 47.544 2.408 47.664 ;
     RECT  0.084 47.664 2.408 47.688 ;
     RECT  0.06 47.688 2.408 47.808 ;
     RECT  0.084 47.808 2.408 47.832 ;
     RECT  0.06 47.832 2.408 47.952 ;
     RECT  0.084 47.952 2.408 47.976 ;
     RECT  0.06 47.976 2.408 48.096 ;
     RECT  0.084 48.096 2.408 48.12 ;
     RECT  0.06 48.12 2.408 48.24 ;
     RECT  0.084 48.24 2.408 48.264 ;
     RECT  0.06 48.264 2.408 48.384 ;
     RECT  0.084 48.384 2.408 48.408 ;
     RECT  0.06 48.408 2.408 48.528 ;
     RECT  0.084 48.528 2.408 48.552 ;
     RECT  0.06 48.552 2.408 48.672 ;
     RECT  0.084 48.672 2.408 48.696 ;
     RECT  0.06 48.696 2.408 48.816 ;
     RECT  0.084 48.816 2.408 48.84 ;
     RECT  0.06 48.84 2.408 48.96 ;
     RECT  0.084 48.96 2.408 48.984 ;
     RECT  0.06 48.984 2.408 49.104 ;
     RECT  0.084 49.104 2.408 49.128 ;
     RECT  0.06 49.128 2.408 49.248 ;
     RECT  0.084 49.248 2.408 49.272 ;
     RECT  0.06 49.272 2.408 49.392 ;
     RECT  0.084 49.392 2.408 49.416 ;
     RECT  0.06 49.416 2.408 49.536 ;
     RECT  0.084 49.536 2.408 49.56 ;
     RECT  0.06 49.56 2.408 49.68 ;
     RECT  0.084 49.68 2.408 49.704 ;
     RECT  0.06 49.704 2.408 49.824 ;
     RECT  0.084 49.824 2.408 49.848 ;
     RECT  0.06 49.848 2.408 49.968 ;
     RECT  0.084 49.968 2.408 49.992 ;
     RECT  0.06 49.992 2.408 50.112 ;
     RECT  0.084 50.112 2.408 50.136 ;
     RECT  0.06 50.136 2.408 50.256 ;
     RECT  0.084 50.256 2.408 50.28 ;
     RECT  0.06 50.28 2.408 50.4 ;
     RECT  0.084 50.4 2.408 50.424 ;
     RECT  0.06 50.424 2.408 50.544 ;
     RECT  0.084 50.544 2.408 50.568 ;
     RECT  0.06 50.568 2.408 50.688 ;
     RECT  0.084 50.688 2.408 50.712 ;
     RECT  0.06 50.712 2.408 50.832 ;
     RECT  0.084 50.832 2.408 50.856 ;
     RECT  0.06 50.856 2.408 50.976 ;
     RECT  0.084 50.976 2.408 51 ;
     RECT  0.06 51 2.408 51.12 ;
     RECT  0.084 51.12 2.408 51.144 ;
     RECT  0.06 51.144 2.408 51.264 ;
     RECT  0.084 51.264 2.408 51.288 ;
     RECT  0.06 51.288 2.408 51.408 ;
     RECT  0.084 51.408 2.408 51.432 ;
     RECT  0.06 51.432 2.408 51.552 ;
     RECT  0.084 51.552 2.408 51.576 ;
     RECT  0.06 51.576 2.408 51.696 ;
     RECT  0.084 51.696 2.408 51.72 ;
     RECT  0.06 51.72 2.408 51.84 ;
     RECT  0.084 51.84 2.408 51.864 ;
     RECT  0.06 51.864 2.408 51.984 ;
     RECT  0.084 51.984 2.408 52.008 ;
     RECT  0.06 52.008 2.408 52.128 ;
     RECT  0.084 52.128 2.408 52.152 ;
     RECT  0.06 52.152 2.408 52.272 ;
     RECT  0.084 52.272 2.408 52.296 ;
     RECT  0.06 52.296 2.408 52.416 ;
     RECT  0.084 52.416 2.408 52.44 ;
     RECT  0.137 53.856 2.408 81.24 ;
     RECT  2.408 2.148 2.512 81.24 ;
     RECT  2.512 2.418 2.704 81.24 ;
     RECT  2.704 14.112 2.729 15.288 ;
     RECT  2.704 54.096 2.729 56.328 ;
     RECT  2.704 3.312 2.765 3.336 ;
     RECT  2.704 6.768 2.765 10.728 ;
     RECT  2.704 11.76 2.765 11.784 ;
     RECT  2.704 13.104 2.765 13.128 ;
     RECT  2.704 40.32 2.765 43.08 ;
     RECT  2.729 54.432 2.765 56.328 ;
     RECT  2.704 59.04 2.765 59.256 ;
     RECT  2.704 60.912 2.765 63.816 ;
     RECT  2.704 66.816 2.765 68.712 ;
     RECT  2.704 69.84 2.765 69.864 ;
     RECT  2.704 74.592 2.765 75.192 ;
     RECT  2.704 24.912 2.801 24.936 ;
     RECT  2.704 57.6 2.801 57.624 ;
     RECT  2.765 63.36 2.801 63.816 ;
     RECT  2.765 66.816 2.801 67.848 ;
     RECT  2.704 28.656 2.837 28.824 ;
     RECT  2.704 34.704 2.837 36.888 ;
     RECT  2.704 16.56 2.873 21.768 ;
     RECT  2.704 30.096 2.873 33.672 ;
     RECT  2.837 36.432 2.873 36.888 ;
     RECT  2.704 38.688 2.873 39.336 ;
     RECT  2.765 40.32 2.873 41.976 ;
     RECT  2.704 44.928 2.873 48.984 ;
     RECT  2.837 34.704 2.909 35.256 ;
     RECT  2.765 55.728 2.909 56.328 ;
     RECT  2.765 60.912 2.909 61.944 ;
     RECT  2.765 6.768 2.981 8.472 ;
     RECT  2.873 30.096 2.981 31.176 ;
     RECT  2.909 55.728 2.981 55.752 ;
     RECT  2.873 18.144 3.017 21.768 ;
     RECT  2.704 4.416 3.089 5.112 ;
     RECT  2.765 9.792 3.089 10.728 ;
     RECT  2.704 27.072 3.089 27.096 ;
     RECT  2.873 32.304 3.089 33.672 ;
     RECT  2.873 40.896 3.089 41.112 ;
     RECT  2.909 60.912 3.089 60.936 ;
     RECT  2.729 14.4 3.125 15.288 ;
     RECT  2.704 26.064 3.125 26.088 ;
     RECT  2.704 50.832 3.125 52.296 ;
     RECT  3.125 14.4 3.197 15 ;
     RECT  3.017 21.744 3.305 21.768 ;
     RECT  2.981 30.336 3.305 31.176 ;
     RECT  2.873 39.024 3.305 39.336 ;
     RECT  2.765 43.056 3.305 43.08 ;
     RECT  2.704 71.712 3.413 73.032 ;
     RECT  2.981 6.768 3.685 7.752 ;
     RECT  2.704 76.464 3.697 81.24 ;
     RECT  3.697 76.416 3.769 81.24 ;
     RECT  2.801 67.152 3.781 67.704 ;
     RECT  2.765 75.12 3.781 75.192 ;
     RECT  3.769 76.368 3.781 81.24 ;
     RECT  3.781 67.152 3.827 68.376 ;
     RECT  3.74 71.04 3.827 71.064 ;
     RECT  3.305 39.024 3.841 39.096 ;
     RECT  2.873 45.024 3.841 48.984 ;
     RECT  3.125 50.832 3.841 51.384 ;
     RECT  2.765 59.232 3.841 59.256 ;
     RECT  2.704 64.944 3.841 64.968 ;
     RECT  3.781 75.12 3.881 81.24 ;
     RECT  3.089 9.792 3.913 10.344 ;
     RECT  3.089 33.024 3.913 33.672 ;
     RECT  2.909 34.704 3.913 34.728 ;
     RECT  3.841 38.688 3.913 39.096 ;
     RECT  3.089 41.04 3.913 41.112 ;
     RECT  3.841 44.448 3.913 48.984 ;
     RECT  3.841 50.544 3.913 51.384 ;
     RECT  3.841 59.232 3.913 59.304 ;
     RECT  3.197 14.4 3.949 14.904 ;
     RECT  3.017 18.144 3.971 20.616 ;
     RECT  3.089 4.656 3.973 5.112 ;
     RECT  3.685 6.24 3.973 7.752 ;
     RECT  3.913 58.704 3.973 59.304 ;
     RECT  3.913 60.576 3.973 60.6 ;
     RECT  3.973 4.656 3.98 7.752 ;
     RECT  2.873 16.56 3.98 16.584 ;
     RECT  3.973 57.984 4.019 60.6 ;
     RECT  3.971 20.064 4.021 20.616 ;
     RECT  3.913 33.024 4.021 34.728 ;
     RECT  3.98 4.656 4.067 8.472 ;
     RECT  3.971 18.144 4.067 18.84 ;
     RECT  2.873 36.432 4.097 36.456 ;
     RECT  4.021 12.48 4.129 12.504 ;
     RECT  3.949 13.68 4.129 14.904 ;
     RECT  3.913 26.016 4.165 26.04 ;
     RECT  3.305 30.336 4.165 30.888 ;
     RECT  4.021 33.024 4.165 34.824 ;
     RECT  3.881 81.072 4.169 81.24 ;
     RECT  2.837 28.656 4.172 28.68 ;
     RECT  4.129 12.48 4.201 14.904 ;
     RECT  3.98 16.224 4.201 16.584 ;
     RECT  4.172 27.84 4.201 28.68 ;
     RECT  4.165 29.76 4.201 30.888 ;
     RECT  4.165 32.976 4.201 34.824 ;
     RECT  4.165 25.104 4.213 26.04 ;
     RECT  2.765 54.624 4.237 54.648 ;
     RECT  4.021 20.064 4.273 20.712 ;
     RECT  3.913 41.04 4.309 41.256 ;
     RECT  3.685 74.112 4.309 74.136 ;
     RECT  3.881 75.12 4.309 80.088 ;
     RECT  3.841 64.944 4.345 65.064 ;
     RECT  4.309 40.944 4.357 41.256 ;
     RECT  4.309 74.112 4.381 80.088 ;
     RECT  3.913 38.16 4.412 39.096 ;
     RECT  4.357 40.416 4.412 41.256 ;
     RECT  3.913 44.448 4.412 51.384 ;
     RECT  3.413 72.432 4.417 73.032 ;
     RECT  4.381 74.064 4.417 80.088 ;
     RECT  4.201 12.48 4.453 16.968 ;
     RECT  4.412 38.16 4.453 41.256 ;
     RECT  4.412 43.776 4.453 51.384 ;
     RECT  4.019 59.28 4.501 60.6 ;
     RECT  4.489 62.16 4.501 62.184 ;
     RECT  4.169 81.072 4.601 81.096 ;
     RECT  4.453 38.16 4.645 51.384 ;
     RECT  4.345 64.896 4.652 65.064 ;
     RECT  4.237 66.192 4.652 66.216 ;
     RECT  4.652 64.896 4.693 66.216 ;
     RECT  4.549 11.376 4.7 11.4 ;
     RECT  4.453 12.48 4.7 17.112 ;
     RECT  4.501 59.28 4.741 62.184 ;
     RECT  3.913 63.216 4.741 63.24 ;
     RECT  3.827 67.296 4.748 68.376 ;
     RECT  4.525 69.552 4.748 69.576 ;
     RECT  4.237 52.464 4.789 52.488 ;
     RECT  4.748 67.296 4.789 69.576 ;
     RECT  4.741 59.28 4.849 63.24 ;
     RECT  4.693 64.416 4.849 66.216 ;
     RECT  4.645 38.016 4.885 51.384 ;
     RECT  4.789 52.416 4.885 52.488 ;
     RECT  4.417 72.432 4.925 80.088 ;
     RECT  3.913 9.6 4.933 10.344 ;
     RECT  4.7 11.376 4.933 17.112 ;
     RECT  4.885 38.016 4.949 52.488 ;
     RECT  3.733 53.568 4.949 53.592 ;
     RECT  3.973 3.36 4.957 3.384 ;
     RECT  4.067 4.656 4.957 7.944 ;
     RECT  4.933 9.6 4.993 17.112 ;
     RECT  4.525 31.92 4.993 31.944 ;
     RECT  4.201 32.976 4.993 35.352 ;
     RECT  4.957 3.36 5.108 7.944 ;
     RECT  4.993 9.6 5.108 17.64 ;
     RECT  4.067 18.816 5.108 18.84 ;
     RECT  4.273 20.064 5.108 20.856 ;
     RECT  4.124 23.568 5.108 23.592 ;
     RECT  4.213 25.104 5.108 26.136 ;
     RECT  4.201 27.84 5.108 30.888 ;
     RECT  4.993 31.92 5.108 35.352 ;
     RECT  4.949 38.016 5.108 53.592 ;
     RECT  4.237 54.624 5.108 55.272 ;
     RECT  4.741 56.448 5.108 56.472 ;
     RECT  4.019 57.984 5.108 58.056 ;
     RECT  4.849 59.28 5.108 66.216 ;
     RECT  4.789 67.296 5.108 70.104 ;
     RECT  4.925 72.432 5.108 79.932 ;
     RECT  5.108 2.148 5.212 79.932 ;
     RECT  5.212 2.418 5.404 79.704 ;
     RECT  5.404 71.28 5.429 76.536 ;
     RECT  5.404 62.208 5.465 65.544 ;
     RECT  5.404 54.624 5.537 57.048 ;
     RECT  5.404 67.248 5.555 67.704 ;
     RECT  5.404 28.8 5.717 35.64 ;
     RECT  5.465 62.208 5.753 63.624 ;
     RECT  5.404 17.616 5.789 20.616 ;
     RECT  5.404 77.568 5.789 79.704 ;
     RECT  5.404 12.24 5.795 16.632 ;
     RECT  5.404 21.648 5.825 21.672 ;
     RECT  5.429 74.112 5.825 76.536 ;
     RECT  5.789 17.616 5.836 20.568 ;
     RECT  5.717 28.8 5.861 33.288 ;
     RECT  5.717 34.368 5.861 35.64 ;
     RECT  5.861 28.8 5.933 30.456 ;
     RECT  5.861 31.776 5.933 33.288 ;
     RECT  5.753 63.216 5.939 63.624 ;
     RECT  5.753 62.208 5.941 62.232 ;
     RECT  5.404 37.632 6.005 52.488 ;
     RECT  5.933 28.944 6.077 30.456 ;
     RECT  5.404 60.96 6.077 60.984 ;
     RECT  5.836 17.616 6.113 17.64 ;
     RECT  6.077 30.432 6.113 30.456 ;
     RECT  6.005 37.632 6.149 51.864 ;
     RECT  5.537 54.672 6.149 57.048 ;
     RECT  5.404 3.84 6.172 4.92 ;
     RECT  5.789 78.624 6.185 79.704 ;
     RECT  6.185 79.008 6.257 79.704 ;
     RECT  5.795 16.032 6.275 16.632 ;
     RECT  5.836 18.72 6.275 20.568 ;
     RECT  6.149 54.672 6.365 56.952 ;
     RECT  5.404 68.88 6.365 70.104 ;
     RECT  6.149 37.632 6.401 39.624 ;
     RECT  5.404 6.144 6.419 10.68 ;
     RECT  5.465 64.896 6.469 65.544 ;
     RECT  6.365 69.984 6.469 70.104 ;
     RECT  5.429 71.28 6.469 73.128 ;
     RECT  6.419 6.144 6.505 7.176 ;
     RECT  6.149 40.8 6.545 51.864 ;
     RECT  6.469 69.984 6.611 73.128 ;
     RECT  6.365 54.672 6.613 55.224 ;
     RECT  6.469 64.32 6.685 65.544 ;
     RECT  5.825 74.592 6.709 76.536 ;
     RECT  5.404 59.184 6.721 59.784 ;
     RECT  6.401 38.448 6.725 39.624 ;
     RECT  6.419 8.208 6.749 10.68 ;
     RECT  5.555 67.248 6.757 67.272 ;
     RECT  6.685 68.592 6.757 68.616 ;
     RECT  6.721 59.088 6.829 59.784 ;
     RECT  6.757 67.248 6.829 68.616 ;
     RECT  6.709 74.592 6.829 77.304 ;
     RECT  6.749 8.208 6.833 10.872 ;
     RECT  6.611 71.616 6.833 73.128 ;
     RECT  5.404 25.632 6.888 27.336 ;
     RECT  6.829 22.08 6.901 22.2 ;
     RECT  5.933 31.776 6.949 33.048 ;
     RECT  5.861 35.472 6.949 35.64 ;
     RECT  6.908 36.624 6.949 36.648 ;
     RECT  5.795 12.24 6.956 14.808 ;
     RECT  6.956 12.24 6.997 15.192 ;
     RECT  5.404 23.808 6.997 24.648 ;
     RECT  6.888 25.632 6.997 27.912 ;
     RECT  6.545 40.848 7.045 51.864 ;
     RECT  6.949 30.816 7.117 33.048 ;
     RECT  7.045 40.848 7.189 52.728 ;
     RECT  6.613 54.048 7.189 55.224 ;
     RECT  6.833 71.856 7.196 73.128 ;
     RECT  7.117 30.816 7.297 33.96 ;
     RECT  7.297 30.576 7.333 33.96 ;
     RECT  6.275 16.512 7.369 16.632 ;
     RECT  7.148 17.616 7.369 17.64 ;
     RECT  7.369 16.512 7.513 17.64 ;
     RECT  6.997 11.664 7.621 15.192 ;
     RECT  7.513 16.368 7.621 17.64 ;
     RECT  6.257 79.152 7.621 79.704 ;
     RECT  6.077 28.944 7.801 29.016 ;
     RECT  6.829 74.592 7.801 77.976 ;
     RECT  7.621 79.152 7.801 79.752 ;
     RECT  6.172 3.84 7.808 4.248 ;
     RECT  6.505 5.616 7.808 7.176 ;
     RECT  6.833 8.208 7.808 10.68 ;
     RECT  7.621 11.664 7.808 17.64 ;
     RECT  6.275 18.72 7.808 20.136 ;
     RECT  6.901 21.12 7.808 22.2 ;
     RECT  6.997 23.808 7.808 27.912 ;
     RECT  7.801 28.944 7.808 29.256 ;
     RECT  7.333 30.576 7.808 34.152 ;
     RECT  6.949 35.472 7.808 36.648 ;
     RECT  6.725 38.448 7.808 39.336 ;
     RECT  7.189 40.848 7.808 55.224 ;
     RECT  6.365 56.928 7.808 56.952 ;
     RECT  6.829 58.704 7.808 59.784 ;
     RECT  7.189 60.96 7.808 60.984 ;
     RECT  7.148 62.16 7.808 62.184 ;
     RECT  5.939 63.216 7.808 63.24 ;
     RECT  6.685 64.32 7.808 65.592 ;
     RECT  6.829 66.768 7.808 68.616 ;
     RECT  6.611 69.984 7.808 70.104 ;
     RECT  7.196 71.856 7.808 73.464 ;
     RECT  7.801 74.592 7.808 79.752 ;
     RECT  7.808 2.148 7.912 79.932 ;
     RECT  7.912 2.418 8.104 79.752 ;
     RECT  8.104 33.024 8.129 37.32 ;
     RECT  8.104 20.064 8.165 20.136 ;
     RECT  8.104 38.448 8.201 38.808 ;
     RECT  8.104 39.984 8.201 47.736 ;
     RECT  8.104 49.296 8.201 53.352 ;
     RECT  8.165 20.112 8.237 20.136 ;
     RECT  8.201 43.536 8.237 47.448 ;
     RECT  8.104 5.472 8.243 10.68 ;
     RECT  8.104 11.952 8.243 16.392 ;
     RECT  8.129 33.456 8.243 37.32 ;
     RECT  8.201 50.784 8.243 53.352 ;
     RECT  8.104 57.408 8.243 58.392 ;
     RECT  8.104 61.008 8.243 61.656 ;
     RECT  8.104 54.72 8.273 56.424 ;
     RECT  8.201 39.984 8.284 42.552 ;
     RECT  8.243 15.648 8.345 16.392 ;
     RECT  8.104 25.488 8.381 27.624 ;
     RECT  8.104 29.088 8.381 32.04 ;
     RECT  8.104 62.736 8.381 62.76 ;
     RECT  8.284 40.752 8.387 42.552 ;
     RECT  8.104 63.792 8.387 64.632 ;
     RECT  8.104 67.152 8.387 67.32 ;
     RECT  8.104 68.352 8.387 69 ;
     RECT  8.273 55.2 8.417 56.04 ;
     RECT  8.243 37.056 8.435 37.32 ;
     RECT  8.104 18.672 8.453 18.792 ;
     RECT  8.435 37.056 8.476 37.08 ;
     RECT  8.104 23.328 8.483 24.12 ;
     RECT  8.104 74.976 8.483 79.752 ;
     RECT  8.453 18.72 8.489 18.792 ;
     RECT  8.381 25.488 8.489 25.656 ;
     RECT  8.104 70.128 8.489 71.064 ;
     RECT  8.104 72.432 8.489 72.504 ;
     RECT  8.483 23.904 8.524 24.12 ;
     RECT  8.483 74.976 8.524 76.536 ;
     RECT  8.483 77.52 8.524 79.752 ;
     RECT  8.237 43.872 8.525 47.448 ;
     RECT  8.489 18.72 8.597 18.744 ;
     RECT  8.381 32.016 8.597 32.04 ;
     RECT  8.243 50.784 8.597 51.672 ;
     RECT  8.525 43.872 8.633 45.288 ;
     RECT  8.381 29.088 8.885 29.112 ;
     RECT  8.387 68.928 8.885 69 ;
     RECT  8.489 70.128 8.929 70.152 ;
     RECT  8.633 43.872 8.963 45 ;
     RECT  8.963 43.872 9.001 44.808 ;
     RECT  8.387 40.848 9.029 42.552 ;
     RECT  8.243 11.952 9.065 14.52 ;
     RECT  8.243 33.936 9.101 35.496 ;
     RECT  9.029 40.848 9.107 42.456 ;
     RECT  8.201 38.544 9.173 38.808 ;
     RECT  8.345 15.648 9.203 15.672 ;
     RECT  8.104 17.376 9.301 17.4 ;
     RECT  9.101 33.936 9.347 34.2 ;
     RECT  9.065 13.632 9.349 14.52 ;
     RECT  9.301 16.992 9.389 17.4 ;
     RECT  8.381 26.64 9.425 27.624 ;
     RECT  8.243 52.704 9.457 53.352 ;
     RECT  8.524 77.52 9.497 77.592 ;
     RECT  8.243 9.504 9.589 10.68 ;
     RECT  9.065 11.952 9.589 12.312 ;
     RECT  8.104 3.312 9.601 4.248 ;
     RECT  8.489 25.488 9.601 25.512 ;
     RECT  9.349 71.28 9.925 71.304 ;
     RECT  8.201 49.296 9.973 49.32 ;
     RECT  9.277 50.736 9.973 50.76 ;
     RECT  9.601 3.312 10.508 4.488 ;
     RECT  8.243 5.472 10.508 8.52 ;
     RECT  9.589 9.504 10.508 12.312 ;
     RECT  9.349 13.632 10.508 14.664 ;
     RECT  9.389 17.376 10.508 17.4 ;
     RECT  10.249 19.632 10.508 19.656 ;
     RECT  9.457 21.408 10.508 21.432 ;
     RECT  9.877 22.752 10.508 22.776 ;
     RECT  8.524 23.904 10.508 23.928 ;
     RECT  9.601 25.488 10.508 25.752 ;
     RECT  9.425 27.6 10.508 27.624 ;
     RECT  8.381 30.576 10.508 30.6 ;
     RECT  9.347 33.936 10.508 33.96 ;
     RECT  9.101 35.472 10.508 35.496 ;
     RECT  9.173 38.688 10.508 38.808 ;
     RECT  9.107 40.944 10.508 42.456 ;
     RECT  9.001 43.872 10.508 44.664 ;
     RECT  8.525 46.8 10.508 47.448 ;
     RECT  9.973 49.296 10.508 50.76 ;
     RECT  9.457 52.704 10.508 54.696 ;
     RECT  8.417 56.016 10.508 56.04 ;
     RECT  9.817 67.248 10.508 67.272 ;
     RECT  8.885 68.928 10.508 68.952 ;
     RECT  9.925 70.704 10.508 71.304 ;
     RECT  8.489 72.432 10.508 72.456 ;
     RECT  8.524 74.976 10.508 75 ;
     RECT  8.524 76.464 10.508 76.536 ;
     RECT  9.497 77.568 10.508 77.592 ;
     RECT  8.524 78.912 10.508 79.752 ;
     RECT  10.508 2.148 10.612 79.932 ;
     RECT  10.612 2.418 10.804 79.752 ;
     RECT  10.804 13.536 10.865 14.664 ;
     RECT  10.804 67.248 11.053 67.848 ;
     RECT  10.804 68.928 11.075 69.576 ;
     RECT  10.804 18.768 11.081 20.376 ;
     RECT  10.804 59.568 11.081 59.592 ;
     RECT  10.804 9.504 11.123 12.312 ;
     RECT  10.804 41.04 11.405 42.456 ;
     RECT  10.804 43.776 11.405 45 ;
     RECT  10.804 22.752 11.801 22.776 ;
     RECT  11.053 67.248 11.845 67.272 ;
     RECT  11.405 41.184 11.909 42.456 ;
     RECT  10.804 46.8 12.053 47.592 ;
     RECT  10.804 27.6 12.121 27.624 ;
     RECT  10.804 30.576 12.157 30.6 ;
     RECT  10.804 72.432 12.229 72.456 ;
     RECT  11.075 68.928 12.265 68.952 ;
     RECT  12.229 72.432 12.337 72.744 ;
     RECT  10.804 33.936 12.409 33.96 ;
     RECT  11.123 10.128 12.469 12.312 ;
     RECT  10.865 13.632 12.469 14.664 ;
     RECT  10.804 76.464 12.469 77.592 ;
     RECT  12.337 72.384 12.757 72.744 ;
     RECT  12.265 68.928 12.901 69.576 ;
     RECT  11.081 19.632 12.985 20.376 ;
     RECT  10.804 25.488 12.985 25.752 ;
     RECT  10.804 16.512 13.093 17.4 ;
     RECT  10.804 38.688 13.093 38.952 ;
     RECT  10.804 52.704 13.093 54.696 ;
     RECT  10.804 56.016 13.093 56.04 ;
     RECT  11.909 42.432 13.201 42.456 ;
     RECT  10.804 3.312 13.208 4.392 ;
     RECT  10.804 5.472 13.208 8.232 ;
     RECT  12.469 10.128 13.208 14.664 ;
     RECT  13.093 16.512 13.208 18.168 ;
     RECT  12.985 19.152 13.208 20.376 ;
     RECT  10.804 21.408 13.208 21.432 ;
     RECT  10.804 23.808 13.208 23.832 ;
     RECT  12.985 25.008 13.208 25.752 ;
     RECT  12.121 26.784 13.208 27.624 ;
     RECT  12.157 29.664 13.208 30.6 ;
     RECT  12.409 33.072 13.208 33.96 ;
     RECT  10.804 35.472 13.208 35.496 ;
     RECT  12.277 37.584 13.208 37.608 ;
     RECT  13.093 38.688 13.208 39.048 ;
     RECT  11.909 41.184 13.208 41.208 ;
     RECT  13.201 42.432 13.208 42.552 ;
     RECT  11.405 43.776 13.208 44.664 ;
     RECT  12.053 47.04 13.208 47.592 ;
     RECT  10.804 49.296 13.208 49.848 ;
     RECT  13.093 52.704 13.208 56.04 ;
     RECT  12.901 68.64 13.208 69.576 ;
     RECT  12.757 71.904 13.208 72.744 ;
     RECT  10.804 74.976 13.208 75 ;
     RECT  12.469 76.464 13.208 77.64 ;
     RECT  10.804 78.912 13.208 79.752 ;
     RECT  13.208 2.148 13.312 79.932 ;
     RECT  13.312 2.418 13.504 79.752 ;
     RECT  13.504 52.704 13.601 56.232 ;
     RECT  13.504 37.104 13.622 37.608 ;
     RECT  13.504 38.928 13.645 39.048 ;
     RECT  13.622 37.584 13.817 37.608 ;
     RECT  13.504 27.6 14.003 27.624 ;
     RECT  13.504 13.632 14.033 14.52 ;
     RECT  13.504 71.808 14.329 71.928 ;
     RECT  13.504 19.296 14.429 20.376 ;
     RECT  13.504 25.488 14.501 26.568 ;
     RECT  13.504 68.4 14.545 68.664 ;
     RECT  14.545 68.64 14.569 68.664 ;
     RECT  14.033 13.632 14.579 13.704 ;
     RECT  13.504 49.296 14.605 49.848 ;
     RECT  14.605 49.296 14.645 50.76 ;
     RECT  14.569 68.64 14.653 69.576 ;
     RECT  14.645 50.736 14.717 50.76 ;
     RECT  13.504 3.312 14.821 4.392 ;
     RECT  13.504 21.408 14.821 21.432 ;
     RECT  13.504 23.808 14.821 23.832 ;
     RECT  13.504 78.768 14.821 79.752 ;
     RECT  13.504 17.376 14.857 18.168 ;
     RECT  13.601 56.016 14.857 56.232 ;
     RECT  14.821 21.408 14.861 22.296 ;
     RECT  14.821 23.808 14.861 23.928 ;
     RECT  14.821 78.672 14.861 79.752 ;
     RECT  13.504 46.752 14.893 47.592 ;
     RECT  14.893 46.752 14.933 47.688 ;
     RECT  13.504 67.248 14.941 67.272 ;
     RECT  13.601 52.704 15.001 54.6 ;
     RECT  14.579 13.632 15.073 13.656 ;
     RECT  14.501 25.728 15.145 26.568 ;
     RECT  13.504 10.032 15.397 12.312 ;
     RECT  15.073 13.344 15.397 13.656 ;
     RECT  14.653 68.64 15.649 68.664 ;
     RECT  14.821 3.312 15.908 4.488 ;
     RECT  13.504 5.472 15.908 8.232 ;
     RECT  15.397 10.032 15.908 13.656 ;
     RECT  15.361 15.456 15.908 15.48 ;
     RECT  14.857 17.376 15.908 18.36 ;
     RECT  14.429 19.632 15.908 20.376 ;
     RECT  14.861 21.504 15.908 22.296 ;
     RECT  14.861 23.904 15.908 23.928 ;
     RECT  15.145 25.728 15.908 26.76 ;
     RECT  15.073 27.936 15.908 27.96 ;
     RECT  13.504 33.936 15.908 33.96 ;
     RECT  13.504 35.472 15.908 35.496 ;
     RECT  13.645 39.024 15.908 39.048 ;
     RECT  13.504 42.528 15.908 42.552 ;
     RECT  13.504 43.872 15.908 44.664 ;
     RECT  14.933 46.848 15.908 47.688 ;
     RECT  14.645 49.296 15.908 49.32 ;
     RECT  15.001 52.704 15.908 54.696 ;
     RECT  14.857 56.016 15.908 56.328 ;
     RECT  14.965 57.6 15.908 57.624 ;
     RECT  15.317 59.28 15.908 59.304 ;
     RECT  15.073 61.008 15.908 61.032 ;
     RECT  15.649 68.4 15.908 68.664 ;
     RECT  14.329 71.904 15.908 71.928 ;
     RECT  13.504 72.96 15.908 72.984 ;
     RECT  13.504 76.464 15.908 77.64 ;
     RECT  14.861 78.672 15.908 78.696 ;
     RECT  14.861 79.728 15.908 79.752 ;
     RECT  15.908 2.148 16.012 79.932 ;
     RECT  15.433 0.72 16.045 0.744 ;
     RECT  16.012 2.418 16.204 79.752 ;
     RECT  16.204 38.448 16.301 44.664 ;
     RECT  16.204 67.824 16.355 71.784 ;
     RECT  16.204 27.936 16.444 29.112 ;
     RECT  16.204 61.392 16.481 62.664 ;
     RECT  16.301 38.448 16.517 42.84 ;
     RECT  16.204 30.624 16.697 31.704 ;
     RECT  16.204 10.128 16.877 20.376 ;
     RECT  16.204 75.504 16.993 78.696 ;
     RECT  16.444 27.936 17.027 27.96 ;
     RECT  16.045 0.72 17.053 1.032 ;
     RECT  16.877 15.456 17.197 20.376 ;
     RECT  16.204 32.784 17.197 34.104 ;
     RECT  16.204 35.472 17.197 35.976 ;
     RECT  16.355 68.352 17.209 71.784 ;
     RECT  16.517 38.448 17.237 39.528 ;
     RECT  16.301 43.824 17.269 44.664 ;
     RECT  16.204 45.936 17.269 49.32 ;
     RECT  16.481 61.392 17.269 61.656 ;
     RECT  16.204 21.504 17.305 23.928 ;
     RECT  16.204 24.912 17.305 26.664 ;
     RECT  16.517 40.56 17.309 42.84 ;
     RECT  16.993 75.504 17.341 77.64 ;
     RECT  17.237 38.448 17.345 39.144 ;
     RECT  16.204 59.184 17.413 59.208 ;
     RECT  17.269 60.624 17.413 61.656 ;
     RECT  16.444 29.088 17.417 29.112 ;
     RECT  17.413 59.184 17.449 61.656 ;
     RECT  16.481 62.64 17.449 62.664 ;
     RECT  17.209 71.76 17.449 71.784 ;
     RECT  16.877 10.128 17.485 14.232 ;
     RECT  16.697 30.816 17.485 31.704 ;
     RECT  17.197 32.784 17.485 35.976 ;
     RECT  17.209 68.352 17.485 70.68 ;
     RECT  17.309 40.8 17.521 42.84 ;
     RECT  17.269 43.824 17.521 49.32 ;
     RECT  16.204 51.744 17.521 56.472 ;
     RECT  16.993 78.672 17.521 78.696 ;
     RECT  16.204 79.728 17.521 79.752 ;
     RECT  17.305 21.504 17.593 26.664 ;
     RECT  17.485 30.816 17.593 35.976 ;
     RECT  16.204 58.128 17.593 58.2 ;
     RECT  17.449 59.184 17.593 62.664 ;
     RECT  17.593 30.816 17.603 37.464 ;
     RECT  16.204 65.568 17.701 66.6 ;
     RECT  17.485 67.68 17.701 70.68 ;
     RECT  17.197 15.456 17.737 20.472 ;
     RECT  17.593 21.504 17.737 27.048 ;
     RECT  17.603 31.344 17.773 37.464 ;
     RECT  17.345 38.448 17.773 39.096 ;
     RECT  17.521 40.8 17.809 49.32 ;
     RECT  17.521 51.744 17.809 57.048 ;
     RECT  17.593 58.128 17.809 62.664 ;
     RECT  17.701 64.896 17.809 66.6 ;
     RECT  17.341 74.928 17.845 77.64 ;
     RECT  17.809 64.32 17.917 66.6 ;
     RECT  17.737 15.456 18.061 27.048 ;
     RECT  17.845 74.688 18.061 77.64 ;
     RECT  17.449 71.76 18.133 71.832 ;
     RECT  18.133 71.76 18.169 71.88 ;
     RECT  18.061 74.64 18.565 77.64 ;
     RECT  17.053 0.72 18.608 1.608 ;
     RECT  16.204 2.592 18.608 9.096 ;
     RECT  17.485 10.08 18.608 14.232 ;
     RECT  18.061 15.456 18.608 27.768 ;
     RECT  17.773 31.344 18.608 39.096 ;
     RECT  17.809 40.8 18.608 49.896 ;
     RECT  17.809 51.072 18.608 57.048 ;
     RECT  17.809 58.128 18.608 63 ;
     RECT  17.917 64.08 18.608 66.6 ;
     RECT  17.701 67.632 18.608 70.68 ;
     RECT  18.169 71.76 18.608 72.024 ;
     RECT  17.413 73.536 18.608 73.56 ;
     RECT  18.565 74.592 18.608 77.64 ;
     RECT  17.521 78.672 18.608 79.752 ;
     RECT  18.608 0.72 18.712 79.932 ;
     RECT  18.712 0.72 18.904 79.752 ;
     RECT  18.904 39.456 19.001 45.24 ;
     RECT  18.904 46.8 19.109 51.72 ;
     RECT  18.904 73.152 19.427 79.752 ;
     RECT  18.904 0.72 19.897 3.912 ;
     RECT  18.904 6.336 19.897 16.632 ;
     RECT  18.904 17.616 19.897 24.936 ;
     RECT  18.904 29.808 19.897 30.84 ;
     RECT  18.904 32.256 19.897 38.184 ;
     RECT  19.001 39.456 19.897 41.208 ;
     RECT  19.109 47.088 19.897 51.72 ;
     RECT  18.904 52.704 19.897 57.048 ;
     RECT  18.904 67.824 19.897 69.432 ;
     RECT  18.904 70.56 19.897 72.024 ;
     RECT  19.427 73.152 19.897 78.936 ;
     RECT  19.897 6.336 19.933 25.08 ;
     RECT  18.904 26.352 19.933 27.816 ;
     RECT  19.897 29.52 19.933 31.128 ;
     RECT  19.897 32.256 19.933 41.208 ;
     RECT  18.904 58.128 19.933 66.696 ;
     RECT  19.897 67.824 19.933 78.936 ;
     RECT  19.933 58.128 20.147 78.936 ;
     RECT  19.897 0.72 20.365 4.632 ;
     RECT  19.933 5.616 20.365 28.104 ;
     RECT  19.933 29.52 20.401 41.208 ;
     RECT  19.001 42.336 20.401 45.24 ;
     RECT  19.897 47.088 20.401 57.048 ;
     RECT  20.365 0.72 20.437 28.104 ;
     RECT  20.401 46.8 20.437 57.048 ;
     RECT  20.401 29.52 20.473 45.24 ;
     RECT  20.437 46.656 20.473 57.048 ;
     RECT  20.437 0.72 21.516 0.744 ;
     RECT  20.437 0.744 21.564 0.864 ;
     RECT  20.437 0.864 21.516 0.888 ;
     RECT  20.437 0.888 21.564 1.008 ;
     RECT  20.437 1.008 21.516 1.032 ;
     RECT  20.437 1.032 21.564 1.152 ;
     RECT  20.437 1.152 21.516 1.176 ;
     RECT  20.437 1.176 21.564 1.296 ;
     RECT  20.437 1.296 21.516 1.32 ;
     RECT  20.437 1.32 21.564 1.44 ;
     RECT  20.437 1.44 21.516 1.464 ;
     RECT  20.437 1.464 21.564 1.584 ;
     RECT  20.437 1.584 21.516 1.608 ;
     RECT  20.437 1.608 21.564 1.728 ;
     RECT  20.437 1.728 21.516 1.752 ;
     RECT  20.437 1.752 21.564 1.872 ;
     RECT  20.437 1.872 21.516 1.896 ;
     RECT  20.437 1.896 21.564 2.016 ;
     RECT  20.437 2.016 21.516 2.04 ;
     RECT  20.437 2.04 21.564 2.16 ;
     RECT  20.437 2.16 21.516 2.184 ;
     RECT  20.437 2.184 21.564 2.304 ;
     RECT  20.437 2.304 21.516 2.328 ;
     RECT  20.437 2.328 21.564 2.448 ;
     RECT  20.437 2.448 21.516 2.472 ;
     RECT  20.437 2.472 21.564 2.592 ;
     RECT  20.437 2.592 21.516 2.616 ;
     RECT  20.437 2.616 21.564 2.736 ;
     RECT  20.437 2.736 21.516 2.76 ;
     RECT  20.437 2.76 21.564 2.88 ;
     RECT  20.437 2.88 21.516 2.904 ;
     RECT  20.437 2.904 21.564 3.024 ;
     RECT  20.437 3.024 21.516 3.048 ;
     RECT  20.437 3.048 21.564 3.168 ;
     RECT  20.437 3.168 21.516 3.192 ;
     RECT  20.437 3.192 21.564 3.312 ;
     RECT  20.437 3.312 21.516 3.336 ;
     RECT  20.437 3.336 21.564 3.456 ;
     RECT  20.437 3.456 21.516 3.48 ;
     RECT  20.437 3.48 21.564 3.6 ;
     RECT  20.437 3.6 21.516 3.624 ;
     RECT  20.437 3.624 21.564 3.744 ;
     RECT  20.437 3.744 21.516 3.768 ;
     RECT  20.437 3.768 21.564 3.888 ;
     RECT  20.437 3.888 21.516 3.912 ;
     RECT  20.437 3.912 21.564 4.032 ;
     RECT  20.437 4.032 21.516 4.056 ;
     RECT  20.437 4.056 21.564 4.176 ;
     RECT  20.437 4.176 21.516 4.2 ;
     RECT  20.437 4.2 21.564 4.32 ;
     RECT  20.437 4.32 21.516 4.344 ;
     RECT  20.437 4.344 21.564 4.464 ;
     RECT  20.437 4.464 21.516 4.488 ;
     RECT  20.437 4.488 21.564 4.608 ;
     RECT  20.437 4.608 21.516 4.632 ;
     RECT  20.437 4.632 21.564 4.752 ;
     RECT  20.437 4.752 21.516 4.776 ;
     RECT  20.437 4.776 21.564 4.896 ;
     RECT  20.437 4.896 21.516 4.92 ;
     RECT  20.437 4.92 21.564 5.04 ;
     RECT  20.437 5.04 21.516 5.064 ;
     RECT  20.437 5.064 21.564 5.184 ;
     RECT  20.437 5.184 21.516 5.208 ;
     RECT  20.437 5.208 21.564 5.328 ;
     RECT  20.437 5.328 21.516 5.352 ;
     RECT  20.437 5.352 21.564 5.472 ;
     RECT  20.437 5.472 21.516 5.496 ;
     RECT  20.437 5.496 21.564 5.616 ;
     RECT  20.437 5.616 21.516 5.64 ;
     RECT  20.437 5.64 21.564 5.76 ;
     RECT  20.437 5.76 21.516 5.784 ;
     RECT  20.437 5.784 21.564 5.904 ;
     RECT  20.437 5.904 21.516 5.928 ;
     RECT  20.437 5.928 21.564 6.048 ;
     RECT  20.437 6.048 21.516 6.072 ;
     RECT  20.437 6.072 21.564 6.192 ;
     RECT  20.437 6.192 21.516 6.216 ;
     RECT  20.437 6.216 21.564 6.336 ;
     RECT  20.437 6.336 21.516 6.36 ;
     RECT  20.437 6.36 21.564 6.48 ;
     RECT  20.437 6.48 21.516 6.504 ;
     RECT  20.437 6.504 21.564 6.624 ;
     RECT  20.437 6.624 21.516 6.648 ;
     RECT  20.437 6.648 21.564 6.768 ;
     RECT  20.437 6.768 21.516 6.792 ;
     RECT  20.437 6.792 21.564 6.912 ;
     RECT  20.437 6.912 21.516 6.936 ;
     RECT  20.437 6.936 21.564 7.056 ;
     RECT  20.437 7.056 21.516 7.08 ;
     RECT  20.437 7.08 21.564 7.2 ;
     RECT  20.437 7.2 21.516 7.224 ;
     RECT  20.437 7.224 21.564 7.344 ;
     RECT  20.437 7.344 21.516 7.368 ;
     RECT  20.437 7.368 21.564 7.488 ;
     RECT  20.437 7.488 21.516 7.512 ;
     RECT  20.437 7.512 21.564 7.632 ;
     RECT  20.437 7.632 21.516 7.656 ;
     RECT  20.437 7.656 21.564 7.776 ;
     RECT  20.437 7.776 21.516 7.8 ;
     RECT  20.437 7.8 21.564 7.92 ;
     RECT  20.437 7.92 21.516 7.944 ;
     RECT  20.437 7.944 21.564 8.064 ;
     RECT  20.437 8.064 21.516 8.088 ;
     RECT  20.437 8.088 21.564 8.208 ;
     RECT  20.437 8.208 21.516 8.232 ;
     RECT  20.437 8.232 21.564 8.352 ;
     RECT  20.437 8.352 21.516 8.376 ;
     RECT  20.437 8.376 21.564 8.496 ;
     RECT  20.437 8.496 21.516 8.52 ;
     RECT  20.437 8.52 21.564 8.64 ;
     RECT  20.437 8.64 21.516 8.664 ;
     RECT  20.437 8.664 21.564 8.784 ;
     RECT  20.437 8.784 21.516 8.808 ;
     RECT  20.437 8.808 21.564 8.928 ;
     RECT  20.437 8.928 21.516 8.952 ;
     RECT  20.437 8.952 21.564 9.072 ;
     RECT  20.437 9.072 21.516 9.096 ;
     RECT  20.437 9.096 21.564 9.216 ;
     RECT  20.437 9.216 21.516 9.24 ;
     RECT  20.437 9.24 21.564 9.36 ;
     RECT  20.437 9.36 21.516 9.384 ;
     RECT  20.437 9.384 21.564 9.504 ;
     RECT  20.437 9.504 21.516 9.528 ;
     RECT  20.437 9.528 21.564 9.648 ;
     RECT  20.437 9.648 21.516 9.672 ;
     RECT  20.437 9.672 21.564 9.792 ;
     RECT  20.437 9.792 21.516 9.816 ;
     RECT  20.437 9.816 21.564 9.936 ;
     RECT  20.437 9.936 21.516 9.96 ;
     RECT  20.437 9.96 21.564 10.08 ;
     RECT  20.437 10.08 21.516 10.104 ;
     RECT  20.437 10.104 21.564 10.224 ;
     RECT  20.437 10.224 21.516 10.248 ;
     RECT  20.437 10.248 21.564 10.368 ;
     RECT  20.437 10.368 21.516 10.392 ;
     RECT  20.437 10.392 21.564 10.512 ;
     RECT  20.437 10.512 21.516 10.536 ;
     RECT  20.437 10.536 21.564 10.656 ;
     RECT  20.437 10.656 21.516 10.68 ;
     RECT  20.437 10.68 21.564 10.8 ;
     RECT  20.437 10.8 21.516 10.824 ;
     RECT  20.437 10.824 21.564 10.944 ;
     RECT  20.437 10.944 21.516 10.968 ;
     RECT  20.437 10.968 21.564 11.088 ;
     RECT  20.437 11.088 21.516 11.112 ;
     RECT  20.437 11.112 21.564 11.232 ;
     RECT  20.437 11.232 21.516 11.256 ;
     RECT  20.437 11.256 21.564 11.376 ;
     RECT  20.437 11.376 21.516 11.4 ;
     RECT  20.437 11.4 21.564 11.52 ;
     RECT  20.437 11.52 21.516 11.544 ;
     RECT  20.437 11.544 21.564 11.664 ;
     RECT  20.437 11.664 21.516 11.688 ;
     RECT  20.437 11.688 21.564 11.808 ;
     RECT  20.437 11.808 21.516 11.832 ;
     RECT  20.437 11.832 21.564 11.952 ;
     RECT  20.437 11.952 21.516 11.976 ;
     RECT  20.437 11.976 21.564 12.096 ;
     RECT  20.437 12.096 21.516 12.12 ;
     RECT  20.437 12.12 21.564 12.24 ;
     RECT  20.437 12.24 21.516 12.264 ;
     RECT  20.437 12.264 21.564 12.384 ;
     RECT  20.437 12.384 21.516 12.408 ;
     RECT  20.437 12.408 21.564 12.528 ;
     RECT  20.437 12.528 21.516 12.552 ;
     RECT  20.437 12.552 21.564 12.672 ;
     RECT  20.437 12.672 21.516 12.696 ;
     RECT  20.437 12.696 21.564 12.816 ;
     RECT  20.437 12.816 21.516 12.84 ;
     RECT  20.437 12.84 21.564 12.96 ;
     RECT  20.437 12.96 21.516 12.984 ;
     RECT  20.437 12.984 21.564 13.104 ;
     RECT  20.437 13.104 21.516 13.128 ;
     RECT  20.437 13.128 21.564 13.248 ;
     RECT  20.437 13.248 21.516 13.272 ;
     RECT  20.437 13.272 21.564 13.392 ;
     RECT  20.437 13.392 21.516 13.416 ;
     RECT  20.437 13.416 21.564 13.536 ;
     RECT  20.437 13.536 21.516 13.56 ;
     RECT  20.437 13.56 21.564 13.68 ;
     RECT  20.437 13.68 21.516 13.704 ;
     RECT  20.437 13.704 21.564 13.824 ;
     RECT  20.437 13.824 21.516 13.848 ;
     RECT  20.437 13.848 21.564 13.968 ;
     RECT  20.437 13.968 21.516 13.992 ;
     RECT  20.437 13.992 21.564 14.112 ;
     RECT  20.437 14.112 21.516 14.136 ;
     RECT  20.437 14.136 21.564 14.256 ;
     RECT  20.437 14.256 21.516 14.28 ;
     RECT  20.437 14.28 21.564 14.4 ;
     RECT  20.437 14.4 21.516 14.424 ;
     RECT  20.437 14.424 21.564 14.544 ;
     RECT  20.437 14.544 21.516 14.568 ;
     RECT  20.437 14.568 21.564 14.688 ;
     RECT  20.437 14.688 21.516 14.712 ;
     RECT  20.437 14.712 21.564 14.832 ;
     RECT  20.437 14.832 21.516 14.856 ;
     RECT  20.437 14.856 21.564 14.976 ;
     RECT  20.437 14.976 21.516 15 ;
     RECT  20.437 15 21.564 15.12 ;
     RECT  20.437 15.12 21.516 15.144 ;
     RECT  20.437 15.144 21.564 15.264 ;
     RECT  20.437 15.264 21.516 15.288 ;
     RECT  20.437 15.288 21.564 15.408 ;
     RECT  20.437 15.408 21.516 15.432 ;
     RECT  20.437 15.432 21.564 15.552 ;
     RECT  20.437 15.552 21.516 15.576 ;
     RECT  20.437 15.576 21.564 15.696 ;
     RECT  20.437 15.696 21.516 15.72 ;
     RECT  20.437 15.72 21.564 15.84 ;
     RECT  20.437 15.84 21.516 15.864 ;
     RECT  20.437 15.864 21.564 15.984 ;
     RECT  20.437 15.984 21.516 16.008 ;
     RECT  20.437 16.008 21.564 16.128 ;
     RECT  20.437 16.128 21.516 16.152 ;
     RECT  20.437 16.152 21.564 16.272 ;
     RECT  20.437 16.272 21.516 16.296 ;
     RECT  20.437 16.296 21.564 16.416 ;
     RECT  20.437 16.416 21.516 16.44 ;
     RECT  20.437 16.44 21.564 16.56 ;
     RECT  20.437 16.56 21.516 16.584 ;
     RECT  20.437 16.584 21.564 16.704 ;
     RECT  20.437 16.704 21.516 16.728 ;
     RECT  20.437 16.728 21.564 16.848 ;
     RECT  20.437 16.848 21.516 16.872 ;
     RECT  20.437 16.872 21.564 16.992 ;
     RECT  20.437 16.992 21.516 17.016 ;
     RECT  20.437 17.016 21.564 17.136 ;
     RECT  20.437 17.136 21.516 17.16 ;
     RECT  20.437 17.16 21.564 17.28 ;
     RECT  20.437 17.28 21.516 17.304 ;
     RECT  20.437 17.304 21.564 17.424 ;
     RECT  20.437 17.424 21.516 17.448 ;
     RECT  20.437 17.448 21.564 17.568 ;
     RECT  20.437 17.568 21.516 17.592 ;
     RECT  20.437 17.592 21.564 17.712 ;
     RECT  20.437 17.712 21.516 17.736 ;
     RECT  20.437 17.736 21.564 17.856 ;
     RECT  20.437 17.856 21.516 17.88 ;
     RECT  20.437 17.88 21.564 18 ;
     RECT  20.437 18 21.516 18.024 ;
     RECT  20.437 18.024 21.564 18.144 ;
     RECT  20.437 18.144 21.516 18.168 ;
     RECT  20.437 18.168 21.564 18.288 ;
     RECT  20.437 18.288 21.516 18.312 ;
     RECT  20.437 18.312 21.564 18.432 ;
     RECT  20.437 18.432 21.516 18.456 ;
     RECT  20.437 18.456 21.564 18.576 ;
     RECT  20.437 18.576 21.516 18.6 ;
     RECT  20.437 18.6 21.564 18.72 ;
     RECT  20.437 18.72 21.516 18.744 ;
     RECT  20.437 18.744 21.564 18.864 ;
     RECT  20.437 18.864 21.516 18.888 ;
     RECT  20.437 18.888 21.564 19.008 ;
     RECT  20.437 19.008 21.516 19.032 ;
     RECT  20.437 19.032 21.564 19.152 ;
     RECT  20.437 19.152 21.516 19.176 ;
     RECT  20.437 19.176 21.564 19.296 ;
     RECT  20.437 19.296 21.516 19.32 ;
     RECT  20.437 19.32 21.564 19.44 ;
     RECT  20.437 19.44 21.516 19.464 ;
     RECT  20.437 19.464 21.564 19.584 ;
     RECT  20.437 19.584 21.516 19.608 ;
     RECT  20.437 19.608 21.564 19.728 ;
     RECT  20.437 19.728 21.516 19.752 ;
     RECT  20.437 19.752 21.564 19.872 ;
     RECT  20.437 19.872 21.516 19.896 ;
     RECT  20.437 19.896 21.564 20.016 ;
     RECT  20.437 20.016 21.516 20.04 ;
     RECT  20.437 20.04 21.564 20.16 ;
     RECT  20.437 20.16 21.516 20.184 ;
     RECT  20.437 20.184 21.564 20.304 ;
     RECT  20.437 20.304 21.516 20.328 ;
     RECT  20.437 20.328 21.564 20.448 ;
     RECT  20.437 20.448 21.516 20.472 ;
     RECT  20.437 20.472 21.564 20.592 ;
     RECT  20.437 20.592 21.516 20.616 ;
     RECT  20.437 20.616 21.564 20.736 ;
     RECT  20.437 20.736 21.516 20.76 ;
     RECT  20.437 20.76 21.564 20.88 ;
     RECT  20.437 20.88 21.516 20.904 ;
     RECT  20.437 20.904 21.564 21.024 ;
     RECT  20.437 21.024 21.516 21.048 ;
     RECT  20.437 21.048 21.564 21.168 ;
     RECT  20.437 21.168 21.516 21.192 ;
     RECT  20.437 21.192 21.564 21.312 ;
     RECT  20.437 21.312 21.516 21.336 ;
     RECT  20.437 21.336 21.564 21.456 ;
     RECT  20.437 21.456 21.516 21.48 ;
     RECT  20.437 21.48 21.564 21.6 ;
     RECT  20.437 21.6 21.516 21.624 ;
     RECT  20.437 21.624 21.564 21.744 ;
     RECT  20.437 21.744 21.516 21.768 ;
     RECT  20.437 21.768 21.564 21.888 ;
     RECT  20.437 21.888 21.516 21.912 ;
     RECT  20.437 21.912 21.564 22.032 ;
     RECT  20.437 22.032 21.516 22.056 ;
     RECT  20.437 22.056 21.564 22.176 ;
     RECT  20.437 22.176 21.516 22.2 ;
     RECT  20.437 22.2 21.564 22.32 ;
     RECT  20.437 22.32 21.516 22.344 ;
     RECT  20.437 22.344 21.564 22.464 ;
     RECT  20.437 22.464 21.516 22.488 ;
     RECT  20.437 22.488 21.564 22.608 ;
     RECT  20.437 22.608 21.516 22.632 ;
     RECT  20.437 22.632 21.564 22.752 ;
     RECT  20.437 22.752 21.516 22.776 ;
     RECT  20.437 22.776 21.564 22.896 ;
     RECT  20.437 22.896 21.516 22.92 ;
     RECT  20.437 22.92 21.564 23.04 ;
     RECT  20.437 23.04 21.516 23.064 ;
     RECT  20.437 23.064 21.564 23.184 ;
     RECT  20.437 23.184 21.516 23.208 ;
     RECT  20.437 23.208 21.564 23.328 ;
     RECT  20.437 23.328 21.516 23.352 ;
     RECT  20.437 23.352 21.564 23.472 ;
     RECT  20.437 23.472 21.516 23.496 ;
     RECT  20.437 23.496 21.564 23.616 ;
     RECT  20.437 23.616 21.516 23.64 ;
     RECT  20.437 23.64 21.564 23.76 ;
     RECT  20.437 23.76 21.516 23.784 ;
     RECT  20.437 23.784 21.564 23.904 ;
     RECT  20.437 23.904 21.516 23.928 ;
     RECT  20.437 23.928 21.564 24.048 ;
     RECT  20.437 24.048 21.516 24.072 ;
     RECT  20.437 24.072 21.564 24.192 ;
     RECT  20.437 24.192 21.516 24.216 ;
     RECT  20.437 24.216 21.564 24.336 ;
     RECT  20.437 24.336 21.516 24.36 ;
     RECT  20.437 24.36 21.564 24.48 ;
     RECT  20.437 24.48 21.516 24.504 ;
     RECT  20.437 24.504 21.564 24.624 ;
     RECT  20.437 24.624 21.516 24.648 ;
     RECT  20.437 24.648 21.564 24.768 ;
     RECT  20.437 24.768 21.516 24.792 ;
     RECT  20.437 24.792 21.564 24.912 ;
     RECT  20.437 24.912 21.516 24.936 ;
     RECT  20.437 24.936 21.564 25.056 ;
     RECT  20.437 25.056 21.516 25.08 ;
     RECT  20.437 25.08 21.564 25.2 ;
     RECT  20.437 25.2 21.516 25.224 ;
     RECT  20.437 25.224 21.564 25.344 ;
     RECT  20.437 25.344 21.516 25.368 ;
     RECT  20.437 25.368 21.564 25.488 ;
     RECT  20.437 25.488 21.516 25.512 ;
     RECT  20.437 25.512 21.564 25.632 ;
     RECT  20.437 25.632 21.516 25.656 ;
     RECT  20.437 25.656 21.564 25.776 ;
     RECT  20.437 25.776 21.516 25.8 ;
     RECT  20.437 25.8 21.564 25.92 ;
     RECT  20.437 25.92 21.516 25.944 ;
     RECT  20.437 25.944 21.564 26.064 ;
     RECT  20.437 26.064 21.516 26.088 ;
     RECT  20.437 26.088 21.564 26.208 ;
     RECT  20.437 26.208 21.516 26.232 ;
     RECT  20.437 26.232 21.564 26.352 ;
     RECT  20.437 26.352 21.516 26.376 ;
     RECT  20.437 26.376 21.564 26.496 ;
     RECT  20.437 26.496 21.516 26.52 ;
     RECT  20.437 26.52 21.564 26.64 ;
     RECT  20.437 26.64 21.516 26.664 ;
     RECT  20.437 26.664 21.564 26.784 ;
     RECT  20.437 26.784 21.516 26.808 ;
     RECT  20.437 26.808 21.564 26.928 ;
     RECT  20.437 26.928 21.516 26.952 ;
     RECT  20.437 26.952 21.564 27.072 ;
     RECT  20.437 27.072 21.516 27.096 ;
     RECT  20.437 27.096 21.564 27.216 ;
     RECT  20.437 27.216 21.516 27.24 ;
     RECT  20.437 27.24 21.564 27.36 ;
     RECT  20.437 27.36 21.516 27.384 ;
     RECT  20.437 27.384 21.564 27.504 ;
     RECT  20.437 27.504 21.516 27.528 ;
     RECT  20.437 27.528 21.564 27.648 ;
     RECT  20.437 27.648 21.516 27.672 ;
     RECT  20.437 27.672 21.564 27.792 ;
     RECT  20.437 27.792 21.516 27.816 ;
     RECT  20.437 27.816 21.564 27.936 ;
     RECT  20.437 27.936 21.516 27.96 ;
     RECT  20.437 27.96 21.564 28.08 ;
     RECT  20.437 28.08 21.516 28.104 ;
     RECT  20.437 28.104 21.564 28.224 ;
     RECT  20.437 28.224 21.516 28.248 ;
     RECT  20.473 29.52 21.516 29.544 ;
     RECT  20.473 29.544 21.564 29.664 ;
     RECT  20.473 29.664 21.516 29.688 ;
     RECT  20.473 29.688 21.564 29.808 ;
     RECT  20.473 29.808 21.516 29.832 ;
     RECT  20.473 29.832 21.564 29.952 ;
     RECT  20.473 29.952 21.516 29.976 ;
     RECT  20.473 29.976 21.564 30.096 ;
     RECT  20.473 30.096 21.516 30.12 ;
     RECT  20.473 30.12 21.564 30.24 ;
     RECT  20.473 30.24 21.516 30.264 ;
     RECT  20.473 30.264 21.564 30.384 ;
     RECT  20.473 30.384 21.516 30.408 ;
     RECT  20.473 30.408 21.564 30.528 ;
     RECT  20.473 30.528 21.516 30.552 ;
     RECT  20.473 30.552 21.564 30.672 ;
     RECT  20.473 30.672 21.516 30.696 ;
     RECT  20.473 30.696 21.564 30.816 ;
     RECT  20.473 30.816 21.516 30.84 ;
     RECT  20.473 30.84 21.564 30.96 ;
     RECT  20.473 30.96 21.516 30.984 ;
     RECT  20.473 30.984 21.564 31.104 ;
     RECT  20.473 31.104 21.516 31.128 ;
     RECT  20.473 31.128 21.564 31.248 ;
     RECT  20.473 31.248 21.516 31.272 ;
     RECT  20.473 31.272 21.564 31.392 ;
     RECT  20.473 31.392 21.516 31.416 ;
     RECT  20.473 31.416 21.564 31.536 ;
     RECT  20.473 31.536 21.516 31.56 ;
     RECT  20.473 31.56 21.564 31.68 ;
     RECT  20.473 31.68 21.516 31.704 ;
     RECT  20.473 31.704 21.564 31.824 ;
     RECT  20.473 31.824 21.516 31.848 ;
     RECT  20.473 31.848 21.564 31.968 ;
     RECT  20.473 31.968 21.516 31.992 ;
     RECT  20.473 31.992 21.564 32.112 ;
     RECT  20.473 32.112 21.516 32.136 ;
     RECT  20.473 32.136 21.564 32.256 ;
     RECT  20.473 32.256 21.516 32.28 ;
     RECT  20.473 32.28 21.564 32.4 ;
     RECT  20.473 32.4 21.516 32.424 ;
     RECT  20.473 32.424 21.564 32.544 ;
     RECT  20.473 32.544 21.516 32.568 ;
     RECT  20.473 32.568 21.564 32.688 ;
     RECT  20.473 32.688 21.516 32.712 ;
     RECT  20.473 32.712 21.564 32.832 ;
     RECT  20.473 32.832 21.516 32.856 ;
     RECT  20.473 32.856 21.564 32.976 ;
     RECT  20.473 32.976 21.516 33 ;
     RECT  20.473 33 21.564 33.12 ;
     RECT  20.473 33.12 21.516 33.144 ;
     RECT  20.473 33.144 21.564 33.264 ;
     RECT  20.473 33.264 21.516 33.288 ;
     RECT  20.473 33.288 21.564 33.408 ;
     RECT  20.473 33.408 21.516 33.432 ;
     RECT  20.473 33.432 21.564 33.552 ;
     RECT  20.473 33.552 21.516 33.576 ;
     RECT  20.473 33.576 21.564 33.696 ;
     RECT  20.473 33.696 21.516 33.72 ;
     RECT  20.473 33.72 21.564 33.84 ;
     RECT  20.473 33.84 21.516 33.864 ;
     RECT  20.473 33.864 21.564 33.984 ;
     RECT  20.473 33.984 21.516 34.008 ;
     RECT  20.473 34.008 21.564 34.128 ;
     RECT  20.473 34.128 21.516 34.152 ;
     RECT  20.473 34.152 21.564 34.272 ;
     RECT  20.473 34.272 21.516 34.296 ;
     RECT  20.473 34.296 21.564 34.416 ;
     RECT  20.473 34.416 21.516 34.44 ;
     RECT  20.473 34.44 21.564 34.56 ;
     RECT  20.473 34.56 21.516 34.584 ;
     RECT  20.473 34.584 21.564 34.704 ;
     RECT  20.473 34.704 21.516 34.728 ;
     RECT  20.473 34.728 21.564 34.848 ;
     RECT  20.473 34.848 21.516 34.872 ;
     RECT  20.473 34.872 21.564 34.992 ;
     RECT  20.473 34.992 21.516 35.016 ;
     RECT  20.473 35.016 21.564 35.136 ;
     RECT  20.473 35.136 21.516 35.16 ;
     RECT  20.473 35.16 21.564 35.28 ;
     RECT  20.473 35.28 21.516 35.304 ;
     RECT  20.473 35.304 21.564 35.424 ;
     RECT  20.473 35.424 21.516 35.448 ;
     RECT  20.473 35.448 21.564 35.568 ;
     RECT  20.473 35.568 21.516 35.592 ;
     RECT  20.473 35.592 21.564 35.712 ;
     RECT  20.473 35.712 21.516 35.736 ;
     RECT  20.473 35.736 21.564 35.856 ;
     RECT  20.473 35.856 21.516 35.88 ;
     RECT  20.473 35.88 21.564 36 ;
     RECT  20.473 36 21.516 36.024 ;
     RECT  20.473 36.024 21.564 36.144 ;
     RECT  20.473 36.144 21.516 36.168 ;
     RECT  20.473 36.168 21.564 36.288 ;
     RECT  20.473 36.288 21.516 36.312 ;
     RECT  20.473 36.312 21.564 36.432 ;
     RECT  20.473 36.432 21.516 36.456 ;
     RECT  20.473 36.456 21.564 36.576 ;
     RECT  20.473 36.576 21.516 36.6 ;
     RECT  20.473 36.6 21.564 36.72 ;
     RECT  20.473 36.72 21.516 36.744 ;
     RECT  20.473 36.744 21.564 36.864 ;
     RECT  20.473 36.864 21.516 36.888 ;
     RECT  20.473 36.888 21.564 37.008 ;
     RECT  20.473 37.008 21.516 37.032 ;
     RECT  20.473 37.032 21.564 37.152 ;
     RECT  20.473 37.152 21.516 37.176 ;
     RECT  20.473 37.176 21.564 37.296 ;
     RECT  20.473 37.296 21.516 37.32 ;
     RECT  20.473 37.32 21.564 37.44 ;
     RECT  20.473 37.44 21.516 37.464 ;
     RECT  20.473 37.464 21.564 37.584 ;
     RECT  20.473 37.584 21.516 37.608 ;
     RECT  20.473 37.608 21.564 37.728 ;
     RECT  20.473 37.728 21.516 37.752 ;
     RECT  20.473 37.752 21.564 37.872 ;
     RECT  20.473 37.872 21.516 37.896 ;
     RECT  20.473 37.896 21.564 38.016 ;
     RECT  20.473 38.016 21.516 38.04 ;
     RECT  20.473 38.04 21.564 38.16 ;
     RECT  20.473 38.16 21.516 38.184 ;
     RECT  20.473 38.184 21.564 38.304 ;
     RECT  20.473 38.304 21.516 38.328 ;
     RECT  20.473 38.328 21.564 38.448 ;
     RECT  20.473 38.448 21.516 38.472 ;
     RECT  20.473 38.472 21.564 38.592 ;
     RECT  20.473 38.592 21.516 38.616 ;
     RECT  20.473 38.616 21.564 38.736 ;
     RECT  20.473 38.736 21.516 38.76 ;
     RECT  20.473 38.76 21.564 38.88 ;
     RECT  20.473 38.88 21.516 38.904 ;
     RECT  20.473 38.904 21.564 39.024 ;
     RECT  20.473 39.024 21.516 39.048 ;
     RECT  20.473 39.048 21.564 39.168 ;
     RECT  20.473 39.168 21.516 39.192 ;
     RECT  20.473 39.192 21.564 39.312 ;
     RECT  20.473 39.312 21.516 39.336 ;
     RECT  20.473 39.336 21.564 39.456 ;
     RECT  20.473 39.456 21.516 39.48 ;
     RECT  20.473 39.48 21.564 39.6 ;
     RECT  20.473 39.6 21.516 39.624 ;
     RECT  20.473 39.624 21.564 39.744 ;
     RECT  20.473 39.744 21.516 39.768 ;
     RECT  20.473 39.768 21.564 39.888 ;
     RECT  20.473 39.888 21.516 39.912 ;
     RECT  20.473 39.912 21.564 40.032 ;
     RECT  20.473 40.032 21.516 40.056 ;
     RECT  20.473 40.056 21.564 40.176 ;
     RECT  20.473 40.176 21.516 40.2 ;
     RECT  20.473 40.2 21.564 40.32 ;
     RECT  20.473 40.32 21.516 40.344 ;
     RECT  20.473 40.344 21.564 40.464 ;
     RECT  20.473 40.464 21.516 40.488 ;
     RECT  20.473 40.488 21.564 40.608 ;
     RECT  20.473 40.608 21.516 40.632 ;
     RECT  20.473 40.632 21.564 40.752 ;
     RECT  20.473 40.752 21.516 40.776 ;
     RECT  20.473 40.776 21.564 40.896 ;
     RECT  20.473 40.896 21.516 40.92 ;
     RECT  20.473 40.92 21.564 41.04 ;
     RECT  20.473 41.04 21.516 41.064 ;
     RECT  20.473 41.064 21.564 41.184 ;
     RECT  20.473 41.184 21.516 41.208 ;
     RECT  20.473 41.208 21.564 41.328 ;
     RECT  20.473 41.328 21.516 41.352 ;
     RECT  20.473 41.352 21.564 41.472 ;
     RECT  20.473 41.472 21.516 41.496 ;
     RECT  20.473 41.496 21.564 41.616 ;
     RECT  20.473 41.616 21.516 41.64 ;
     RECT  20.473 41.64 21.564 41.76 ;
     RECT  20.473 41.76 21.516 41.784 ;
     RECT  20.473 41.784 21.564 41.904 ;
     RECT  20.473 41.904 21.516 41.928 ;
     RECT  20.473 41.928 21.564 42.048 ;
     RECT  20.473 42.048 21.516 42.072 ;
     RECT  20.473 42.072 21.564 42.192 ;
     RECT  20.473 42.192 21.516 42.216 ;
     RECT  20.473 42.216 21.564 42.336 ;
     RECT  20.473 42.336 21.516 42.36 ;
     RECT  20.473 42.36 21.564 42.48 ;
     RECT  20.473 42.48 21.516 42.504 ;
     RECT  20.473 42.504 21.564 42.624 ;
     RECT  20.473 42.624 21.516 42.648 ;
     RECT  20.473 42.648 21.564 42.768 ;
     RECT  20.473 42.768 21.516 42.792 ;
     RECT  20.473 42.792 21.564 42.912 ;
     RECT  20.473 42.912 21.516 42.936 ;
     RECT  20.473 42.936 21.564 43.056 ;
     RECT  20.473 43.056 21.516 43.08 ;
     RECT  20.473 43.08 21.564 43.2 ;
     RECT  20.473 43.2 21.516 43.224 ;
     RECT  20.473 43.224 21.564 43.344 ;
     RECT  20.473 43.344 21.516 43.368 ;
     RECT  20.473 43.368 21.564 43.488 ;
     RECT  20.473 43.488 21.516 43.512 ;
     RECT  20.473 43.512 21.564 43.632 ;
     RECT  20.473 43.632 21.516 43.656 ;
     RECT  20.473 43.656 21.564 43.776 ;
     RECT  20.473 43.776 21.516 43.8 ;
     RECT  20.473 43.8 21.564 43.92 ;
     RECT  20.473 43.92 21.516 43.944 ;
     RECT  20.473 43.944 21.564 44.064 ;
     RECT  20.473 44.064 21.516 44.088 ;
     RECT  20.473 44.088 21.564 44.208 ;
     RECT  20.473 44.208 21.516 44.232 ;
     RECT  20.473 44.232 21.564 44.352 ;
     RECT  20.473 44.352 21.516 44.376 ;
     RECT  20.473 44.376 21.564 44.496 ;
     RECT  20.473 44.496 21.516 44.52 ;
     RECT  20.473 44.52 21.564 44.64 ;
     RECT  20.473 44.64 21.516 44.664 ;
     RECT  20.473 44.664 21.564 44.784 ;
     RECT  20.473 44.784 21.516 44.808 ;
     RECT  20.473 44.808 21.564 44.928 ;
     RECT  20.473 44.928 21.516 44.952 ;
     RECT  20.473 44.952 21.564 45.072 ;
     RECT  20.473 45.072 21.516 45.096 ;
     RECT  20.473 45.096 21.564 45.216 ;
     RECT  20.473 45.216 21.516 45.24 ;
     RECT  20.473 45.24 21.564 45.36 ;
     RECT  20.473 45.36 21.516 45.384 ;
     RECT  20.473 45.384 21.564 45.504 ;
     RECT  20.473 45.504 21.516 45.528 ;
     RECT  20.473 45.528 21.564 45.648 ;
     RECT  20.473 45.648 21.516 45.672 ;
     RECT  20.473 45.672 21.564 45.792 ;
     RECT  20.473 45.792 21.516 45.816 ;
     RECT  20.473 45.816 21.564 45.936 ;
     RECT  20.473 45.936 21.516 45.96 ;
     RECT  20.473 45.96 21.564 46.08 ;
     RECT  20.473 46.08 21.516 46.104 ;
     RECT  20.473 46.104 21.564 46.224 ;
     RECT  20.473 46.224 21.516 46.248 ;
     RECT  20.473 46.248 21.564 46.368 ;
     RECT  20.473 46.368 21.516 46.392 ;
     RECT  20.473 46.392 21.564 46.512 ;
     RECT  20.473 46.512 21.516 46.536 ;
     RECT  20.473 46.536 21.564 46.656 ;
     RECT  20.473 46.656 21.516 46.68 ;
     RECT  20.473 46.68 21.564 46.8 ;
     RECT  20.473 46.8 21.516 46.824 ;
     RECT  20.473 46.824 21.564 46.944 ;
     RECT  20.473 46.944 21.516 46.968 ;
     RECT  20.473 46.968 21.564 47.088 ;
     RECT  20.473 47.088 21.516 47.112 ;
     RECT  20.473 47.112 21.564 47.232 ;
     RECT  20.473 47.232 21.516 47.256 ;
     RECT  20.473 47.256 21.564 47.376 ;
     RECT  20.473 47.376 21.516 47.4 ;
     RECT  20.473 47.4 21.564 47.52 ;
     RECT  20.473 47.52 21.516 47.544 ;
     RECT  20.473 47.544 21.564 47.664 ;
     RECT  20.473 47.664 21.516 47.688 ;
     RECT  20.473 47.688 21.564 47.808 ;
     RECT  20.473 47.808 21.516 47.832 ;
     RECT  20.473 47.832 21.564 47.952 ;
     RECT  20.473 47.952 21.516 47.976 ;
     RECT  20.473 47.976 21.564 48.096 ;
     RECT  20.473 48.096 21.516 48.12 ;
     RECT  20.473 48.12 21.564 48.24 ;
     RECT  20.473 48.24 21.516 48.264 ;
     RECT  20.473 48.264 21.564 48.384 ;
     RECT  20.473 48.384 21.516 48.408 ;
     RECT  20.473 48.408 21.564 48.528 ;
     RECT  20.473 48.528 21.516 48.552 ;
     RECT  20.473 48.552 21.564 48.672 ;
     RECT  20.473 48.672 21.516 48.696 ;
     RECT  20.473 48.696 21.564 48.816 ;
     RECT  20.473 48.816 21.516 48.84 ;
     RECT  20.473 48.84 21.564 48.96 ;
     RECT  20.473 48.96 21.516 48.984 ;
     RECT  20.473 48.984 21.564 49.104 ;
     RECT  20.473 49.104 21.516 49.128 ;
     RECT  20.473 49.128 21.564 49.248 ;
     RECT  20.473 49.248 21.516 49.272 ;
     RECT  20.473 49.272 21.564 49.392 ;
     RECT  20.473 49.392 21.516 49.416 ;
     RECT  20.473 49.416 21.564 49.536 ;
     RECT  20.473 49.536 21.516 49.56 ;
     RECT  20.473 49.56 21.564 49.68 ;
     RECT  20.473 49.68 21.516 49.704 ;
     RECT  20.473 49.704 21.564 49.824 ;
     RECT  20.473 49.824 21.516 49.848 ;
     RECT  20.473 49.848 21.564 49.968 ;
     RECT  20.473 49.968 21.516 49.992 ;
     RECT  20.473 49.992 21.564 50.112 ;
     RECT  20.473 50.112 21.516 50.136 ;
     RECT  20.473 50.136 21.564 50.256 ;
     RECT  20.473 50.256 21.516 50.28 ;
     RECT  20.473 50.28 21.564 50.4 ;
     RECT  20.473 50.4 21.516 50.424 ;
     RECT  20.473 50.424 21.564 50.544 ;
     RECT  20.473 50.544 21.516 50.568 ;
     RECT  20.473 50.568 21.564 50.688 ;
     RECT  20.473 50.688 21.516 50.712 ;
     RECT  20.473 50.712 21.564 50.832 ;
     RECT  20.473 50.832 21.516 50.856 ;
     RECT  20.473 50.856 21.564 50.976 ;
     RECT  20.473 50.976 21.516 51 ;
     RECT  20.473 51 21.564 51.12 ;
     RECT  20.473 51.12 21.516 51.144 ;
     RECT  20.473 51.144 21.564 51.264 ;
     RECT  20.473 51.264 21.516 51.288 ;
     RECT  20.473 51.288 21.564 51.408 ;
     RECT  20.473 51.408 21.516 51.432 ;
     RECT  20.473 51.432 21.564 51.552 ;
     RECT  20.473 51.552 21.516 51.576 ;
     RECT  20.473 51.576 21.564 51.696 ;
     RECT  20.473 51.696 21.516 51.72 ;
     RECT  20.473 51.72 21.564 51.84 ;
     RECT  20.473 51.84 21.516 51.864 ;
     RECT  20.473 51.864 21.564 51.984 ;
     RECT  20.473 51.984 21.516 52.008 ;
     RECT  20.473 52.008 21.564 52.128 ;
     RECT  20.473 52.128 21.516 52.152 ;
     RECT  20.473 52.152 21.564 52.272 ;
     RECT  20.473 52.272 21.516 52.296 ;
     RECT  20.473 52.296 21.564 52.416 ;
     RECT  20.473 52.416 21.516 52.44 ;
     RECT  20.473 52.44 21.564 52.56 ;
     RECT  20.473 52.56 21.516 52.584 ;
     RECT  20.473 52.584 21.564 52.704 ;
     RECT  20.473 52.704 21.516 52.728 ;
     RECT  20.473 52.728 21.564 52.848 ;
     RECT  20.473 52.848 21.516 52.872 ;
     RECT  20.473 52.872 21.564 52.992 ;
     RECT  20.473 52.992 21.516 53.016 ;
     RECT  20.473 53.016 21.564 53.136 ;
     RECT  20.473 53.136 21.516 53.16 ;
     RECT  20.473 53.16 21.564 53.28 ;
     RECT  20.473 53.28 21.516 53.304 ;
     RECT  20.473 53.304 21.564 53.424 ;
     RECT  20.473 53.424 21.516 53.448 ;
     RECT  20.473 53.448 21.564 53.568 ;
     RECT  20.473 53.568 21.516 53.592 ;
     RECT  20.473 53.592 21.564 53.712 ;
     RECT  20.473 53.712 21.516 53.736 ;
     RECT  20.473 53.736 21.564 53.856 ;
     RECT  20.473 53.856 21.516 53.88 ;
     RECT  20.473 53.88 21.564 54 ;
     RECT  20.473 54 21.516 54.024 ;
     RECT  20.473 54.024 21.564 54.144 ;
     RECT  20.473 54.144 21.516 54.168 ;
     RECT  20.473 54.168 21.564 54.288 ;
     RECT  20.473 54.288 21.516 54.312 ;
     RECT  20.473 54.312 21.564 54.432 ;
     RECT  20.473 54.432 21.516 54.456 ;
     RECT  20.473 54.456 21.564 54.576 ;
     RECT  20.473 54.576 21.516 54.6 ;
     RECT  20.473 54.6 21.564 54.72 ;
     RECT  20.473 54.72 21.516 54.744 ;
     RECT  20.473 54.744 21.564 54.864 ;
     RECT  20.473 54.864 21.516 54.888 ;
     RECT  20.473 54.888 21.564 55.008 ;
     RECT  20.473 55.008 21.516 55.032 ;
     RECT  20.473 55.032 21.564 55.152 ;
     RECT  20.473 55.152 21.516 55.176 ;
     RECT  20.473 55.176 21.564 55.296 ;
     RECT  20.473 55.296 21.516 55.32 ;
     RECT  20.473 55.32 21.564 55.44 ;
     RECT  20.473 55.44 21.516 55.464 ;
     RECT  20.473 55.464 21.564 55.584 ;
     RECT  20.473 55.584 21.516 55.608 ;
     RECT  20.473 55.608 21.564 55.728 ;
     RECT  20.473 55.728 21.516 55.752 ;
     RECT  20.473 55.752 21.564 55.872 ;
     RECT  20.473 55.872 21.516 55.896 ;
     RECT  20.473 55.896 21.564 56.016 ;
     RECT  20.473 56.016 21.516 56.04 ;
     RECT  20.473 56.04 21.564 56.16 ;
     RECT  20.473 56.16 21.516 56.184 ;
     RECT  20.473 56.184 21.564 56.304 ;
     RECT  20.473 56.304 21.516 56.328 ;
     RECT  20.473 56.328 21.564 56.448 ;
     RECT  20.473 56.448 21.516 56.472 ;
     RECT  20.473 56.472 21.564 56.592 ;
     RECT  20.473 56.592 21.516 56.616 ;
     RECT  20.473 56.616 21.564 56.736 ;
     RECT  20.473 56.736 21.516 56.76 ;
     RECT  20.473 56.76 21.564 56.88 ;
     RECT  20.473 56.88 21.516 56.904 ;
     RECT  20.473 56.904 21.564 57.024 ;
     RECT  20.473 57.024 21.516 57.048 ;
     RECT  20.147 58.32 21.516 58.344 ;
     RECT  20.147 58.344 21.564 58.464 ;
     RECT  20.147 58.464 21.516 58.488 ;
     RECT  20.147 58.488 21.564 58.608 ;
     RECT  20.147 58.608 21.516 58.632 ;
     RECT  20.147 58.632 21.564 58.752 ;
     RECT  20.147 58.752 21.516 58.776 ;
     RECT  20.147 58.776 21.564 58.896 ;
     RECT  20.147 58.896 21.516 58.92 ;
     RECT  20.147 58.92 21.564 59.04 ;
     RECT  20.147 59.04 21.516 59.064 ;
     RECT  20.147 59.064 21.564 59.184 ;
     RECT  20.147 59.184 21.516 59.208 ;
     RECT  20.147 59.208 21.564 59.328 ;
     RECT  20.147 59.328 21.516 59.352 ;
     RECT  20.147 59.352 21.564 59.472 ;
     RECT  20.147 59.472 21.516 59.496 ;
     RECT  20.147 59.496 21.564 59.616 ;
     RECT  20.147 59.616 21.516 59.64 ;
     RECT  20.147 59.64 21.564 59.76 ;
     RECT  20.147 59.76 21.516 59.784 ;
     RECT  20.147 59.784 21.564 59.904 ;
     RECT  20.147 59.904 21.516 59.928 ;
     RECT  20.147 59.928 21.564 60.048 ;
     RECT  20.147 60.048 21.516 60.072 ;
     RECT  20.147 60.072 21.564 60.192 ;
     RECT  20.147 60.192 21.516 60.216 ;
     RECT  20.147 60.216 21.564 60.336 ;
     RECT  20.147 60.336 21.516 60.36 ;
     RECT  20.147 60.36 21.564 60.48 ;
     RECT  20.147 60.48 21.516 60.504 ;
     RECT  20.147 60.504 21.564 60.624 ;
     RECT  20.147 60.624 21.516 60.648 ;
     RECT  20.147 60.648 21.564 60.768 ;
     RECT  20.147 60.768 21.516 60.792 ;
     RECT  20.147 60.792 21.564 60.912 ;
     RECT  20.147 60.912 21.516 60.936 ;
     RECT  20.147 60.936 21.564 61.056 ;
     RECT  20.147 61.056 21.516 61.08 ;
     RECT  20.147 61.08 21.564 61.2 ;
     RECT  20.147 61.2 21.516 61.224 ;
     RECT  20.147 61.224 21.564 61.344 ;
     RECT  20.147 61.344 21.516 61.368 ;
     RECT  20.147 61.368 21.564 61.488 ;
     RECT  20.147 61.488 21.516 61.512 ;
     RECT  20.147 61.512 21.564 61.632 ;
     RECT  20.147 61.632 21.516 61.656 ;
     RECT  20.147 61.656 21.564 61.776 ;
     RECT  20.147 61.776 21.516 61.8 ;
     RECT  20.147 61.8 21.564 61.92 ;
     RECT  20.147 61.92 21.516 61.944 ;
     RECT  20.147 61.944 21.564 62.064 ;
     RECT  20.147 62.064 21.516 62.088 ;
     RECT  20.147 62.088 21.564 62.208 ;
     RECT  20.147 62.208 21.516 62.232 ;
     RECT  20.147 62.232 21.564 62.352 ;
     RECT  20.147 62.352 21.516 62.376 ;
     RECT  20.147 62.376 21.564 62.496 ;
     RECT  20.147 62.496 21.516 62.52 ;
     RECT  20.147 62.52 21.564 62.64 ;
     RECT  20.147 62.64 21.516 62.664 ;
     RECT  20.147 62.664 21.564 62.784 ;
     RECT  20.147 62.784 21.516 62.808 ;
     RECT  20.147 62.808 21.564 62.928 ;
     RECT  20.147 62.928 21.516 62.952 ;
     RECT  20.147 62.952 21.564 63.072 ;
     RECT  20.147 63.072 21.516 63.096 ;
     RECT  20.147 63.096 21.564 63.216 ;
     RECT  20.147 63.216 21.516 63.24 ;
     RECT  20.147 63.24 21.564 63.36 ;
     RECT  20.147 63.36 21.516 63.384 ;
     RECT  20.147 63.384 21.564 63.504 ;
     RECT  20.147 63.504 21.516 63.528 ;
     RECT  20.147 63.528 21.564 63.648 ;
     RECT  20.147 63.648 21.516 63.672 ;
     RECT  20.147 63.672 21.564 63.792 ;
     RECT  20.147 63.792 21.516 63.816 ;
     RECT  20.147 63.816 21.564 63.936 ;
     RECT  20.147 63.936 21.516 63.96 ;
     RECT  20.147 63.96 21.564 64.08 ;
     RECT  20.147 64.08 21.516 64.104 ;
     RECT  20.147 64.104 21.564 64.224 ;
     RECT  20.147 64.224 21.516 64.248 ;
     RECT  20.147 64.248 21.564 64.368 ;
     RECT  20.147 64.368 21.516 64.392 ;
     RECT  20.147 64.392 21.564 64.512 ;
     RECT  20.147 64.512 21.516 64.536 ;
     RECT  20.147 64.536 21.564 64.656 ;
     RECT  20.147 64.656 21.516 64.68 ;
     RECT  20.147 64.68 21.564 64.8 ;
     RECT  20.147 64.8 21.516 64.824 ;
     RECT  20.147 64.824 21.564 64.944 ;
     RECT  20.147 64.944 21.516 64.968 ;
     RECT  20.147 64.968 21.564 65.088 ;
     RECT  20.147 65.088 21.516 65.112 ;
     RECT  20.147 65.112 21.564 65.232 ;
     RECT  20.147 65.232 21.516 65.256 ;
     RECT  20.147 65.256 21.564 65.376 ;
     RECT  20.147 65.376 21.516 65.4 ;
     RECT  20.147 65.4 21.564 65.52 ;
     RECT  20.147 65.52 21.516 65.544 ;
     RECT  20.147 65.544 21.564 65.664 ;
     RECT  20.147 65.664 21.516 65.688 ;
     RECT  20.147 65.688 21.564 65.808 ;
     RECT  20.147 65.808 21.516 65.832 ;
     RECT  20.147 65.832 21.564 65.952 ;
     RECT  20.147 65.952 21.516 65.976 ;
     RECT  20.147 65.976 21.564 66.096 ;
     RECT  20.147 66.096 21.516 66.12 ;
     RECT  20.147 66.12 21.564 66.24 ;
     RECT  20.147 66.24 21.516 66.264 ;
     RECT  20.147 66.264 21.564 66.384 ;
     RECT  20.147 66.384 21.516 66.408 ;
     RECT  20.147 66.408 21.564 66.528 ;
     RECT  20.147 66.528 21.516 66.552 ;
     RECT  20.147 66.552 21.564 66.672 ;
     RECT  20.147 66.672 21.516 66.696 ;
     RECT  20.147 66.696 21.564 66.816 ;
     RECT  20.147 66.816 21.516 66.84 ;
     RECT  20.147 66.84 21.564 66.96 ;
     RECT  20.147 66.96 21.516 66.984 ;
     RECT  20.147 66.984 21.564 67.104 ;
     RECT  20.147 67.104 21.516 67.128 ;
     RECT  20.147 67.128 21.564 67.248 ;
     RECT  20.147 67.248 21.516 67.272 ;
     RECT  20.147 67.272 21.564 67.392 ;
     RECT  20.147 67.392 21.516 67.416 ;
     RECT  20.147 67.416 21.564 67.536 ;
     RECT  20.147 67.536 21.516 67.56 ;
     RECT  20.147 67.56 21.564 67.68 ;
     RECT  20.147 67.68 21.516 67.704 ;
     RECT  20.147 67.704 21.564 67.824 ;
     RECT  20.147 67.824 21.516 67.848 ;
     RECT  20.147 67.848 21.564 67.968 ;
     RECT  20.147 67.968 21.516 67.992 ;
     RECT  20.147 67.992 21.564 68.112 ;
     RECT  20.147 68.112 21.516 68.136 ;
     RECT  20.147 68.136 21.564 68.256 ;
     RECT  20.147 68.256 21.516 68.28 ;
     RECT  20.147 68.28 21.564 68.4 ;
     RECT  20.147 68.4 21.516 68.424 ;
     RECT  20.147 68.424 21.564 68.544 ;
     RECT  20.147 68.544 21.516 68.568 ;
     RECT  20.147 68.568 21.564 68.688 ;
     RECT  20.147 68.688 21.516 68.712 ;
     RECT  20.147 68.712 21.564 68.832 ;
     RECT  20.147 68.832 21.516 68.856 ;
     RECT  20.147 68.856 21.564 68.976 ;
     RECT  20.147 68.976 21.516 69 ;
     RECT  20.147 69 21.564 69.12 ;
     RECT  20.147 69.12 21.516 69.144 ;
     RECT  20.147 69.144 21.564 69.264 ;
     RECT  20.147 69.264 21.516 69.288 ;
     RECT  20.147 69.288 21.564 69.408 ;
     RECT  20.147 69.408 21.516 69.432 ;
     RECT  20.147 69.432 21.564 69.552 ;
     RECT  20.147 69.552 21.516 69.576 ;
     RECT  20.147 69.576 21.564 69.696 ;
     RECT  20.147 69.696 21.516 69.72 ;
     RECT  20.147 69.72 21.564 69.84 ;
     RECT  20.147 69.84 21.516 69.864 ;
     RECT  20.147 69.864 21.564 69.984 ;
     RECT  20.147 69.984 21.516 70.008 ;
     RECT  20.147 70.008 21.564 70.128 ;
     RECT  20.147 70.128 21.516 70.152 ;
     RECT  20.147 70.152 21.564 70.272 ;
     RECT  20.147 70.272 21.516 70.296 ;
     RECT  20.147 70.296 21.564 70.416 ;
     RECT  20.147 70.416 21.516 70.44 ;
     RECT  20.147 70.44 21.564 70.56 ;
     RECT  20.147 70.56 21.516 70.584 ;
     RECT  20.147 70.584 21.564 70.704 ;
     RECT  20.147 70.704 21.516 70.728 ;
     RECT  20.147 70.728 21.564 70.848 ;
     RECT  20.147 70.848 21.516 70.872 ;
     RECT  20.147 70.872 21.564 70.992 ;
     RECT  20.147 70.992 21.516 71.016 ;
     RECT  20.147 71.016 21.564 71.136 ;
     RECT  20.147 71.136 21.516 71.16 ;
     RECT  20.147 71.16 21.564 71.28 ;
     RECT  20.147 71.28 21.516 71.304 ;
     RECT  20.147 71.304 21.564 71.424 ;
     RECT  20.147 71.424 21.516 71.448 ;
     RECT  20.147 71.448 21.564 71.568 ;
     RECT  20.147 71.568 21.516 71.592 ;
     RECT  20.147 71.592 21.564 71.712 ;
     RECT  20.147 71.712 21.516 71.736 ;
     RECT  20.147 71.736 21.564 71.856 ;
     RECT  20.147 71.856 21.516 71.88 ;
     RECT  20.147 71.88 21.564 72 ;
     RECT  20.147 72 21.516 72.024 ;
     RECT  20.147 72.024 21.564 72.144 ;
     RECT  20.147 72.144 21.516 72.168 ;
     RECT  20.147 72.168 21.564 72.288 ;
     RECT  20.147 72.288 21.516 72.312 ;
     RECT  20.147 72.312 21.564 72.432 ;
     RECT  20.147 72.432 21.516 72.456 ;
     RECT  20.147 72.456 21.564 72.576 ;
     RECT  20.147 72.576 21.516 72.6 ;
     RECT  20.147 72.6 21.564 72.72 ;
     RECT  20.147 72.72 21.516 72.744 ;
     RECT  20.147 72.744 21.564 72.864 ;
     RECT  20.147 72.864 21.516 72.888 ;
     RECT  20.147 72.888 21.564 73.008 ;
     RECT  20.147 73.008 21.516 73.032 ;
     RECT  20.147 73.032 21.564 73.152 ;
     RECT  20.147 73.152 21.516 73.176 ;
     RECT  20.147 73.176 21.564 73.296 ;
     RECT  20.147 73.296 21.516 73.32 ;
     RECT  20.147 73.32 21.564 73.44 ;
     RECT  20.147 73.44 21.516 73.464 ;
     RECT  20.147 73.464 21.564 73.584 ;
     RECT  20.147 73.584 21.516 73.608 ;
     RECT  20.147 73.608 21.564 73.728 ;
     RECT  20.147 73.728 21.516 73.752 ;
     RECT  20.147 73.752 21.564 73.872 ;
     RECT  20.147 73.872 21.516 73.896 ;
     RECT  20.147 73.896 21.564 74.016 ;
     RECT  20.147 74.016 21.516 74.04 ;
     RECT  20.147 74.04 21.564 74.16 ;
     RECT  20.147 74.16 21.516 74.184 ;
     RECT  20.147 74.184 21.564 74.304 ;
     RECT  20.147 74.304 21.516 74.328 ;
     RECT  20.147 74.328 21.564 74.448 ;
     RECT  20.147 74.448 21.516 74.472 ;
     RECT  20.147 74.472 21.564 74.592 ;
     RECT  20.147 74.592 21.516 74.616 ;
     RECT  20.147 74.616 21.564 74.736 ;
     RECT  20.147 74.736 21.516 74.76 ;
     RECT  20.147 74.76 21.564 74.88 ;
     RECT  20.147 74.88 21.516 74.904 ;
     RECT  20.147 74.904 21.564 75.024 ;
     RECT  20.147 75.024 21.516 75.048 ;
     RECT  20.147 75.048 21.564 75.168 ;
     RECT  20.147 75.168 21.516 75.192 ;
     RECT  20.147 75.192 21.564 75.312 ;
     RECT  20.147 75.312 21.516 75.336 ;
     RECT  20.147 75.336 21.564 75.456 ;
     RECT  20.147 75.456 21.516 75.48 ;
     RECT  20.147 75.48 21.564 75.6 ;
     RECT  20.147 75.6 21.516 75.624 ;
     RECT  20.147 75.624 21.564 75.744 ;
     RECT  20.147 75.744 21.516 75.768 ;
     RECT  20.147 75.768 21.564 75.888 ;
     RECT  20.147 75.888 21.516 75.912 ;
     RECT  20.147 75.912 21.564 76.032 ;
     RECT  20.147 76.032 21.516 76.056 ;
     RECT  20.147 76.056 21.564 76.176 ;
     RECT  20.147 76.176 21.516 76.2 ;
     RECT  20.147 76.2 21.564 76.32 ;
     RECT  20.147 76.32 21.516 76.344 ;
     RECT  20.147 76.344 21.564 76.464 ;
     RECT  20.147 76.464 21.516 76.488 ;
     RECT  20.147 76.488 21.564 76.608 ;
     RECT  20.147 76.608 21.516 76.632 ;
     RECT  20.147 76.632 21.564 76.752 ;
     RECT  20.147 76.752 21.516 76.776 ;
     RECT  20.147 76.776 21.564 76.896 ;
     RECT  20.147 76.896 21.516 76.92 ;
     RECT  20.147 76.92 21.564 77.04 ;
     RECT  20.147 77.04 21.516 77.064 ;
     RECT  20.147 77.064 21.564 77.184 ;
     RECT  20.147 77.184 21.516 77.208 ;
     RECT  20.147 77.208 21.564 77.328 ;
     RECT  20.147 77.328 21.516 77.352 ;
     RECT  20.147 77.352 21.564 77.472 ;
     RECT  20.147 77.472 21.516 77.496 ;
     RECT  20.147 77.496 21.564 77.616 ;
     RECT  20.147 77.616 21.516 77.64 ;
     RECT  20.147 77.64 21.564 77.76 ;
     RECT  20.147 77.76 21.516 77.784 ;
     RECT  20.147 77.784 21.564 77.904 ;
     RECT  20.147 77.904 21.516 77.928 ;
     RECT  20.147 77.928 21.564 78.048 ;
     RECT  20.147 78.048 21.516 78.072 ;
     RECT  20.147 78.072 21.564 78.192 ;
     RECT  20.147 78.192 21.516 78.216 ;
     RECT  20.147 78.216 21.564 78.336 ;
     RECT  20.147 78.336 21.516 78.36 ;
     RECT  20.147 78.36 21.564 78.48 ;
     RECT  20.147 78.48 21.516 78.504 ;
     RECT  20.147 78.504 21.564 78.624 ;
     RECT  20.147 78.624 21.516 78.648 ;
     RECT  20.147 78.648 21.564 78.768 ;
     RECT  20.147 78.768 21.516 78.792 ;
     RECT  20.147 78.792 21.564 78.912 ;
     RECT  20.147 78.912 21.516 78.936 ;
    LAYER M5 ;
     RECT  2.4 2.137 2.52 2.151 ;
     RECT  5.1 2.137 5.22 2.151 ;
     RECT  7.8 2.137 7.92 2.151 ;
     RECT  9.792 2.137 10.62 2.151 ;
     RECT  13.2 2.137 13.32 2.151 ;
     RECT  15.9 2.137 16.02 2.151 ;
     RECT  18.6 2.137 18.72 2.151 ;
     RECT  7.8 2.151 8.112 3.301 ;
     RECT  9.792 2.151 10.812 3.301 ;
     RECT  7.8 3.301 10.812 3.829 ;
     RECT  13.2 2.151 13.512 3.829 ;
     RECT  5.1 2.151 5.412 4.117 ;
     RECT  18.6 2.151 18.912 5.461 ;
     RECT  7.8 3.829 11.688 5.989 ;
     RECT  7.68 5.989 11.688 6.037 ;
     RECT  12.816 3.829 13.512 6.037 ;
     RECT  3.984 3.349 4.008 6.229 ;
     RECT  7.68 6.037 13.512 6.565 ;
     RECT  14.88 5.701 14.904 6.565 ;
     RECT  3.696 6.229 4.008 6.661 ;
     RECT  5.1 4.117 6.12 6.661 ;
     RECT  2.4 2.151 2.712 7.141 ;
     RECT  3.696 6.661 4.056 7.141 ;
     RECT  2.4 7.141 4.056 7.379 ;
     RECT  0.144 7.717 0.168 7.955 ;
     RECT  2.4 7.379 3.72 8.437 ;
     RECT  17.904 5.461 18.912 8.437 ;
     RECT  19.968 7.861 19.992 8.437 ;
     RECT  5.1 6.661 6.408 8.485 ;
     RECT  5.1 8.485 6.696 9.061 ;
     RECT  7.68 6.565 14.904 9.061 ;
     RECT  5.1 9.061 14.904 10.117 ;
     RECT  15.9 2.151 16.212 10.117 ;
     RECT  2.4 8.437 4.056 10.645 ;
     RECT  5.1 10.117 16.212 10.645 ;
     RECT  17.904 8.437 19.992 11.701 ;
     RECT  2.4 10.645 16.212 12.229 ;
     RECT  17.904 11.701 20.088 12.229 ;
     RECT  2.4 12.229 20.088 12.277 ;
     RECT  2.4 12.277 20.136 20.723 ;
     RECT  4.944 20.723 20.136 22.789 ;
     RECT  4.944 22.789 20.232 23.123 ;
     RECT  2.4 20.723 3.72 23.557 ;
     RECT  4.944 23.123 20.136 23.557 ;
     RECT  2.4 23.557 20.136 25.139 ;
     RECT  2.4 25.139 3.72 26.101 ;
     RECT  4.944 25.139 20.136 26.101 ;
     RECT  0.144 29.653 0.168 30.371 ;
     RECT  2.4 26.101 20.136 34.403 ;
     RECT  2.4 34.403 3.72 38.005 ;
     RECT  4.944 34.403 20.136 38.005 ;
     RECT  2.4 38.005 20.136 58.163 ;
     RECT  2.4 58.163 20.088 59.219 ;
     RECT  2.4 59.219 20.04 67.283 ;
     RECT  15.696 67.283 20.04 67.859 ;
     RECT  15.696 67.859 19.992 68.435 ;
     RECT  2.4 67.283 14.616 69.587 ;
     RECT  2.4 69.587 14.568 71.315 ;
     RECT  15.9 68.435 19.992 74.963 ;
     RECT  2.4 71.315 9.48 75.683 ;
     RECT  4.32 75.683 9.48 76.403 ;
     RECT  2.4 75.683 3.288 76.499 ;
     RECT  6.432 76.403 9.48 76.979 ;
     RECT  10.5 71.315 14.568 77.027 ;
     RECT  14.544 77.027 14.568 77.171 ;
     RECT  6.432 76.979 6.744 77.315 ;
     RECT  10.5 77.027 13.512 77.315 ;
     RECT  7.8 76.979 9.48 77.555 ;
     RECT  4.32 76.403 5.412 77.557 ;
     RECT  6.432 77.315 6.456 77.557 ;
     RECT  15.9 74.963 19.56 77.603 ;
     RECT  12.48 77.315 13.512 77.651 ;
     RECT  4.32 77.557 6.456 78.131 ;
     RECT  15.9 77.603 19.512 78.131 ;
     RECT  4.368 78.131 6.456 78.371 ;
     RECT  4.368 78.371 5.412 78.707 ;
     RECT  17.568 78.131 19.512 78.707 ;
     RECT  6.432 78.371 6.456 79.283 ;
     RECT  7.8 77.555 8.712 79.283 ;
     RECT  17.568 78.707 19.416 79.283 ;
     RECT  18.6 79.283 19.416 79.763 ;
     RECT  2.4 76.499 2.712 79.929 ;
     RECT  5.1 78.707 5.412 79.929 ;
     RECT  7.8 79.283 8.112 79.929 ;
     RECT  10.5 77.315 10.812 79.929 ;
     RECT  13.2 77.651 13.512 79.929 ;
     RECT  15.9 78.131 16.212 79.929 ;
     RECT  18.6 79.763 18.912 79.929 ;
     RECT  2.4 79.929 2.52 79.943 ;
     RECT  5.1 79.929 5.22 79.943 ;
     RECT  7.8 79.929 7.92 79.943 ;
     RECT  10.5 79.929 10.62 79.943 ;
     RECT  13.2 79.929 13.32 79.943 ;
     RECT  15.9 79.929 16.02 79.943 ;
     RECT  18.6 79.929 18.72 79.943 ;
     RECT  2.712 3.349 3.984 6.229 ;
     RECT  4.008 3.349 5.1 6.661 ;
     RECT  11.688 3.829 12.816 6.037 ;
     RECT  13.512 5.701 14.88 6.565 ;
     RECT  14.904 5.701 15.9 10.117 ;
     RECT  2.712 6.229 3.696 7.141 ;
     RECT  4.056 6.661 5.1 7.379 ;
     RECT  6.408 6.661 7.68 8.485 ;
     RECT  3.72 7.379 5.1 8.437 ;
     RECT  18.912 7.861 19.968 8.437 ;
     RECT  4.056 8.437 5.1 10.645 ;
     RECT  6.696 8.485 7.68 9.061 ;
     RECT  3.72 20.723 4.944 23.557 ;
     RECT  3.72 25.139 4.944 26.101 ;
     RECT  3.72 34.403 4.944 38.005 ;
     RECT  14.616 67.283 15.696 68.435 ;
     RECT  14.616 68.435 15.9 69.587 ;
     RECT  14.568 69.587 15.9 77.171 ;
     RECT  9.48 71.315 10.5 77.555 ;
     RECT  3.288 75.683 4.32 76.499 ;
     RECT  5.412 76.403 6.432 77.557 ;
     RECT  6.744 76.979 7.8 77.315 ;
     RECT  13.512 77.027 14.544 77.171 ;
     RECT  6.456 77.315 7.8 79.283 ;
     RECT  16.212 78.131 17.568 79.283 ;
     RECT  5.412 78.371 6.432 79.283 ;
  END
END qkd_rlys_528
END LIBRARY
